# OpenTallas tools/qwen_missing/link_phy_gen.py: ot_qfd_ucie_x64_phy hard-macro ABSTRACT (licensed PHY IP; FDI side only)
VERSION 5.7 ;
BUSBITCHARS "[]" ;
DIVIDERCHAR "/" ;
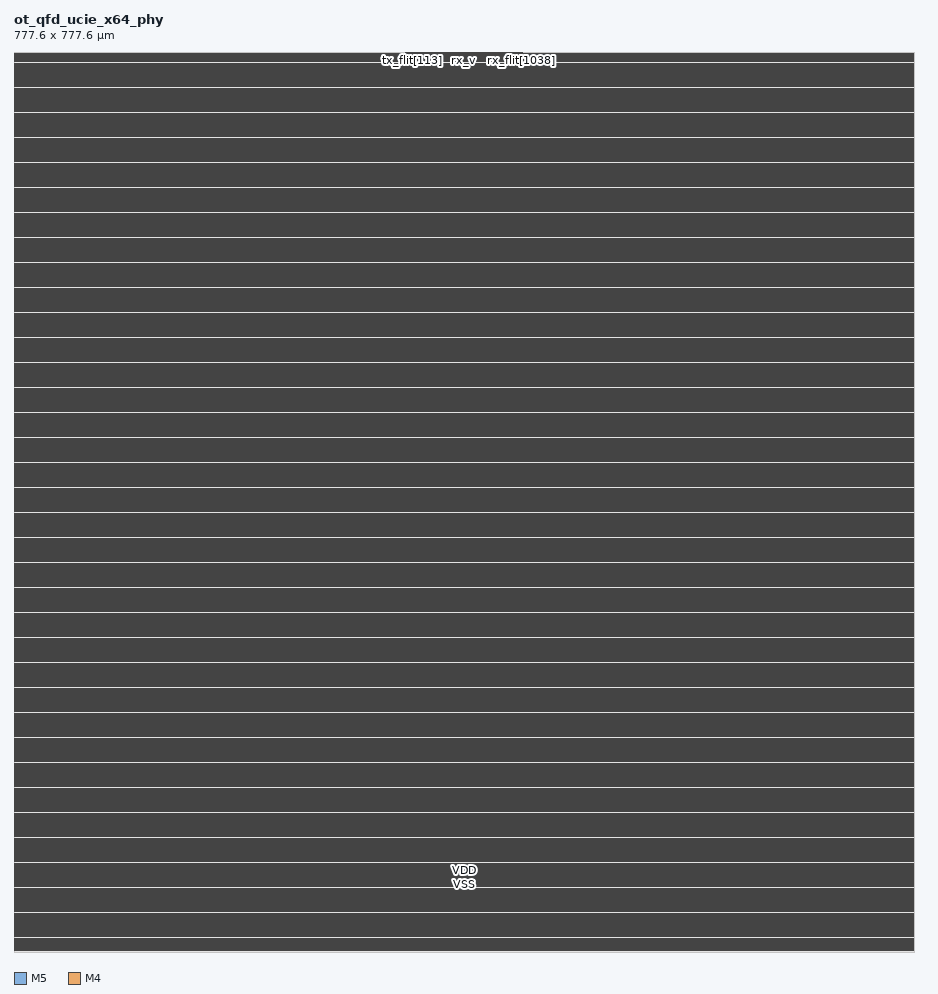
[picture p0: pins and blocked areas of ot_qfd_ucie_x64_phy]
MACRO ot_qfd_ucie_x64_phy
  FOREIGN ot_qfd_ucie_x64_phy 0 0 ;
  SYMMETRY X Y ;
  SIZE 777.600 BY 777.600 ;
  CLASS BLOCK ;
  PIN clk
    DIRECTION INPUT ;
    USE CLOCK ;
    SHAPE ABUTMENT ;
    PORT
      LAYER M5 ;
      RECT 338.616 777.408 338.640 777.600 ;
    END
  END clk
  PIN rst_n
    DIRECTION INPUT ;
    USE SIGNAL ;
    SHAPE ABUTMENT ;
    PORT
      LAYER M5 ;
      RECT 338.664 777.408 338.688 777.600 ;
    END
  END rst_n
  PIN tx_up
    DIRECTION OUTPUT ;
    USE SIGNAL ;
    SHAPE ABUTMENT ;
    PORT
      LAYER M5 ;
      RECT 338.712 777.408 338.736 777.600 ;
    END
  END tx_up
  PIN tx_v
    DIRECTION INPUT ;
    USE SIGNAL ;
    SHAPE ABUTMENT ;
    PORT
      LAYER M5 ;
      RECT 338.760 777.408 338.784 777.600 ;
    END
  END tx_v
  PIN tx_flit[0]
    DIRECTION INPUT ;
    USE SIGNAL ;
    SHAPE ABUTMENT ;
    PORT
      LAYER M5 ;
      RECT 338.808 777.408 338.832 777.600 ;
    END
  END tx_flit[0]
  PIN tx_flit[1]
    DIRECTION INPUT ;
    USE SIGNAL ;
    SHAPE ABUTMENT ;
    PORT
      LAYER M5 ;
      RECT 338.856 777.408 338.880 777.600 ;
    END
  END tx_flit[1]
  PIN tx_flit[2]
    DIRECTION INPUT ;
    USE SIGNAL ;
    SHAPE ABUTMENT ;
    PORT
      LAYER M5 ;
      RECT 338.904 777.408 338.928 777.600 ;
    END
  END tx_flit[2]
  PIN tx_flit[3]
    DIRECTION INPUT ;
    USE SIGNAL ;
    SHAPE ABUTMENT ;
    PORT
      LAYER M5 ;
      RECT 338.952 777.408 338.976 777.600 ;
    END
  END tx_flit[3]
  PIN tx_flit[4]
    DIRECTION INPUT ;
    USE SIGNAL ;
    SHAPE ABUTMENT ;
    PORT
      LAYER M5 ;
      RECT 339.000 777.408 339.024 777.600 ;
    END
  END tx_flit[4]
  PIN tx_flit[5]
    DIRECTION INPUT ;
    USE SIGNAL ;
    SHAPE ABUTMENT ;
    PORT
      LAYER M5 ;
      RECT 339.048 777.408 339.072 777.600 ;
    END
  END tx_flit[5]
  PIN tx_flit[6]
    DIRECTION INPUT ;
    USE SIGNAL ;
    SHAPE ABUTMENT ;
    PORT
      LAYER M5 ;
      RECT 339.096 777.408 339.120 777.600 ;
    END
  END tx_flit[6]
  PIN tx_flit[7]
    DIRECTION INPUT ;
    USE SIGNAL ;
    SHAPE ABUTMENT ;
    PORT
      LAYER M5 ;
      RECT 339.144 777.408 339.168 777.600 ;
    END
  END tx_flit[7]
  PIN tx_flit[8]
    DIRECTION INPUT ;
    USE SIGNAL ;
    SHAPE ABUTMENT ;
    PORT
      LAYER M5 ;
      RECT 339.192 777.408 339.216 777.600 ;
    END
  END tx_flit[8]
  PIN tx_flit[9]
    DIRECTION INPUT ;
    USE SIGNAL ;
    SHAPE ABUTMENT ;
    PORT
      LAYER M5 ;
      RECT 339.240 777.408 339.264 777.600 ;
    END
  END tx_flit[9]
  PIN tx_flit[10]
    DIRECTION INPUT ;
    USE SIGNAL ;
    SHAPE ABUTMENT ;
    PORT
      LAYER M5 ;
      RECT 339.288 777.408 339.312 777.600 ;
    END
  END tx_flit[10]
  PIN tx_flit[11]
    DIRECTION INPUT ;
    USE SIGNAL ;
    SHAPE ABUTMENT ;
    PORT
      LAYER M5 ;
      RECT 339.336 777.408 339.360 777.600 ;
    END
  END tx_flit[11]
  PIN tx_flit[12]
    DIRECTION INPUT ;
    USE SIGNAL ;
    SHAPE ABUTMENT ;
    PORT
      LAYER M5 ;
      RECT 339.384 777.408 339.408 777.600 ;
    END
  END tx_flit[12]
  PIN tx_flit[13]
    DIRECTION INPUT ;
    USE SIGNAL ;
    SHAPE ABUTMENT ;
    PORT
      LAYER M5 ;
      RECT 339.432 777.408 339.456 777.600 ;
    END
  END tx_flit[13]
  PIN tx_flit[14]
    DIRECTION INPUT ;
    USE SIGNAL ;
    SHAPE ABUTMENT ;
    PORT
      LAYER M5 ;
      RECT 339.480 777.408 339.504 777.600 ;
    END
  END tx_flit[14]
  PIN tx_flit[15]
    DIRECTION INPUT ;
    USE SIGNAL ;
    SHAPE ABUTMENT ;
    PORT
      LAYER M5 ;
      RECT 339.528 777.408 339.552 777.600 ;
    END
  END tx_flit[15]
  PIN tx_flit[16]
    DIRECTION INPUT ;
    USE SIGNAL ;
    SHAPE ABUTMENT ;
    PORT
      LAYER M5 ;
      RECT 339.576 777.408 339.600 777.600 ;
    END
  END tx_flit[16]
  PIN tx_flit[17]
    DIRECTION INPUT ;
    USE SIGNAL ;
    SHAPE ABUTMENT ;
    PORT
      LAYER M5 ;
      RECT 339.624 777.408 339.648 777.600 ;
    END
  END tx_flit[17]
  PIN tx_flit[18]
    DIRECTION INPUT ;
    USE SIGNAL ;
    SHAPE ABUTMENT ;
    PORT
      LAYER M5 ;
      RECT 339.672 777.408 339.696 777.600 ;
    END
  END tx_flit[18]
  PIN tx_flit[19]
    DIRECTION INPUT ;
    USE SIGNAL ;
    SHAPE ABUTMENT ;
    PORT
      LAYER M5 ;
      RECT 339.720 777.408 339.744 777.600 ;
    END
  END tx_flit[19]
  PIN tx_flit[20]
    DIRECTION INPUT ;
    USE SIGNAL ;
    SHAPE ABUTMENT ;
    PORT
      LAYER M5 ;
      RECT 339.768 777.408 339.792 777.600 ;
    END
  END tx_flit[20]
  PIN tx_flit[21]
    DIRECTION INPUT ;
    USE SIGNAL ;
    SHAPE ABUTMENT ;
    PORT
      LAYER M5 ;
      RECT 339.816 777.408 339.840 777.600 ;
    END
  END tx_flit[21]
  PIN tx_flit[22]
    DIRECTION INPUT ;
    USE SIGNAL ;
    SHAPE ABUTMENT ;
    PORT
      LAYER M5 ;
      RECT 339.864 777.408 339.888 777.600 ;
    END
  END tx_flit[22]
  PIN tx_flit[23]
    DIRECTION INPUT ;
    USE SIGNAL ;
    SHAPE ABUTMENT ;
    PORT
      LAYER M5 ;
      RECT 339.912 777.408 339.936 777.600 ;
    END
  END tx_flit[23]
  PIN tx_flit[24]
    DIRECTION INPUT ;
    USE SIGNAL ;
    SHAPE ABUTMENT ;
    PORT
      LAYER M5 ;
      RECT 339.960 777.408 339.984 777.600 ;
    END
  END tx_flit[24]
  PIN tx_flit[25]
    DIRECTION INPUT ;
    USE SIGNAL ;
    SHAPE ABUTMENT ;
    PORT
      LAYER M5 ;
      RECT 340.008 777.408 340.032 777.600 ;
    END
  END tx_flit[25]
  PIN tx_flit[26]
    DIRECTION INPUT ;
    USE SIGNAL ;
    SHAPE ABUTMENT ;
    PORT
      LAYER M5 ;
      RECT 340.056 777.408 340.080 777.600 ;
    END
  END tx_flit[26]
  PIN tx_flit[27]
    DIRECTION INPUT ;
    USE SIGNAL ;
    SHAPE ABUTMENT ;
    PORT
      LAYER M5 ;
      RECT 340.104 777.408 340.128 777.600 ;
    END
  END tx_flit[27]
  PIN tx_flit[28]
    DIRECTION INPUT ;
    USE SIGNAL ;
    SHAPE ABUTMENT ;
    PORT
      LAYER M5 ;
      RECT 340.152 777.408 340.176 777.600 ;
    END
  END tx_flit[28]
  PIN tx_flit[29]
    DIRECTION INPUT ;
    USE SIGNAL ;
    SHAPE ABUTMENT ;
    PORT
      LAYER M5 ;
      RECT 340.200 777.408 340.224 777.600 ;
    END
  END tx_flit[29]
  PIN tx_flit[30]
    DIRECTION INPUT ;
    USE SIGNAL ;
    SHAPE ABUTMENT ;
    PORT
      LAYER M5 ;
      RECT 340.248 777.408 340.272 777.600 ;
    END
  END tx_flit[30]
  PIN tx_flit[31]
    DIRECTION INPUT ;
    USE SIGNAL ;
    SHAPE ABUTMENT ;
    PORT
      LAYER M5 ;
      RECT 340.296 777.408 340.320 777.600 ;
    END
  END tx_flit[31]
  PIN tx_flit[32]
    DIRECTION INPUT ;
    USE SIGNAL ;
    SHAPE ABUTMENT ;
    PORT
      LAYER M5 ;
      RECT 340.344 777.408 340.368 777.600 ;
    END
  END tx_flit[32]
  PIN tx_flit[33]
    DIRECTION INPUT ;
    USE SIGNAL ;
    SHAPE ABUTMENT ;
    PORT
      LAYER M5 ;
      RECT 340.392 777.408 340.416 777.600 ;
    END
  END tx_flit[33]
  PIN tx_flit[34]
    DIRECTION INPUT ;
    USE SIGNAL ;
    SHAPE ABUTMENT ;
    PORT
      LAYER M5 ;
      RECT 340.440 777.408 340.464 777.600 ;
    END
  END tx_flit[34]
  PIN tx_flit[35]
    DIRECTION INPUT ;
    USE SIGNAL ;
    SHAPE ABUTMENT ;
    PORT
      LAYER M5 ;
      RECT 340.488 777.408 340.512 777.600 ;
    END
  END tx_flit[35]
  PIN tx_flit[36]
    DIRECTION INPUT ;
    USE SIGNAL ;
    SHAPE ABUTMENT ;
    PORT
      LAYER M5 ;
      RECT 340.536 777.408 340.560 777.600 ;
    END
  END tx_flit[36]
  PIN tx_flit[37]
    DIRECTION INPUT ;
    USE SIGNAL ;
    SHAPE ABUTMENT ;
    PORT
      LAYER M5 ;
      RECT 340.584 777.408 340.608 777.600 ;
    END
  END tx_flit[37]
  PIN tx_flit[38]
    DIRECTION INPUT ;
    USE SIGNAL ;
    SHAPE ABUTMENT ;
    PORT
      LAYER M5 ;
      RECT 340.632 777.408 340.656 777.600 ;
    END
  END tx_flit[38]
  PIN tx_flit[39]
    DIRECTION INPUT ;
    USE SIGNAL ;
    SHAPE ABUTMENT ;
    PORT
      LAYER M5 ;
      RECT 340.680 777.408 340.704 777.600 ;
    END
  END tx_flit[39]
  PIN tx_flit[40]
    DIRECTION INPUT ;
    USE SIGNAL ;
    SHAPE ABUTMENT ;
    PORT
      LAYER M5 ;
      RECT 340.728 777.408 340.752 777.600 ;
    END
  END tx_flit[40]
  PIN tx_flit[41]
    DIRECTION INPUT ;
    USE SIGNAL ;
    SHAPE ABUTMENT ;
    PORT
      LAYER M5 ;
      RECT 340.776 777.408 340.800 777.600 ;
    END
  END tx_flit[41]
  PIN tx_flit[42]
    DIRECTION INPUT ;
    USE SIGNAL ;
    SHAPE ABUTMENT ;
    PORT
      LAYER M5 ;
      RECT 340.824 777.408 340.848 777.600 ;
    END
  END tx_flit[42]
  PIN tx_flit[43]
    DIRECTION INPUT ;
    USE SIGNAL ;
    SHAPE ABUTMENT ;
    PORT
      LAYER M5 ;
      RECT 340.872 777.408 340.896 777.600 ;
    END
  END tx_flit[43]
  PIN tx_flit[44]
    DIRECTION INPUT ;
    USE SIGNAL ;
    SHAPE ABUTMENT ;
    PORT
      LAYER M5 ;
      RECT 340.920 777.408 340.944 777.600 ;
    END
  END tx_flit[44]
  PIN tx_flit[45]
    DIRECTION INPUT ;
    USE SIGNAL ;
    SHAPE ABUTMENT ;
    PORT
      LAYER M5 ;
      RECT 340.968 777.408 340.992 777.600 ;
    END
  END tx_flit[45]
  PIN tx_flit[46]
    DIRECTION INPUT ;
    USE SIGNAL ;
    SHAPE ABUTMENT ;
    PORT
      LAYER M5 ;
      RECT 341.016 777.408 341.040 777.600 ;
    END
  END tx_flit[46]
  PIN tx_flit[47]
    DIRECTION INPUT ;
    USE SIGNAL ;
    SHAPE ABUTMENT ;
    PORT
      LAYER M5 ;
      RECT 341.064 777.408 341.088 777.600 ;
    END
  END tx_flit[47]
  PIN tx_flit[48]
    DIRECTION INPUT ;
    USE SIGNAL ;
    SHAPE ABUTMENT ;
    PORT
      LAYER M5 ;
      RECT 341.112 777.408 341.136 777.600 ;
    END
  END tx_flit[48]
  PIN tx_flit[49]
    DIRECTION INPUT ;
    USE SIGNAL ;
    SHAPE ABUTMENT ;
    PORT
      LAYER M5 ;
      RECT 341.160 777.408 341.184 777.600 ;
    END
  END tx_flit[49]
  PIN tx_flit[50]
    DIRECTION INPUT ;
    USE SIGNAL ;
    SHAPE ABUTMENT ;
    PORT
      LAYER M5 ;
      RECT 341.208 777.408 341.232 777.600 ;
    END
  END tx_flit[50]
  PIN tx_flit[51]
    DIRECTION INPUT ;
    USE SIGNAL ;
    SHAPE ABUTMENT ;
    PORT
      LAYER M5 ;
      RECT 341.256 777.408 341.280 777.600 ;
    END
  END tx_flit[51]
  PIN tx_flit[52]
    DIRECTION INPUT ;
    USE SIGNAL ;
    SHAPE ABUTMENT ;
    PORT
      LAYER M5 ;
      RECT 341.304 777.408 341.328 777.600 ;
    END
  END tx_flit[52]
  PIN tx_flit[53]
    DIRECTION INPUT ;
    USE SIGNAL ;
    SHAPE ABUTMENT ;
    PORT
      LAYER M5 ;
      RECT 341.352 777.408 341.376 777.600 ;
    END
  END tx_flit[53]
  PIN tx_flit[54]
    DIRECTION INPUT ;
    USE SIGNAL ;
    SHAPE ABUTMENT ;
    PORT
      LAYER M5 ;
      RECT 341.400 777.408 341.424 777.600 ;
    END
  END tx_flit[54]
  PIN tx_flit[55]
    DIRECTION INPUT ;
    USE SIGNAL ;
    SHAPE ABUTMENT ;
    PORT
      LAYER M5 ;
      RECT 341.448 777.408 341.472 777.600 ;
    END
  END tx_flit[55]
  PIN tx_flit[56]
    DIRECTION INPUT ;
    USE SIGNAL ;
    SHAPE ABUTMENT ;
    PORT
      LAYER M5 ;
      RECT 341.496 777.408 341.520 777.600 ;
    END
  END tx_flit[56]
  PIN tx_flit[57]
    DIRECTION INPUT ;
    USE SIGNAL ;
    SHAPE ABUTMENT ;
    PORT
      LAYER M5 ;
      RECT 341.544 777.408 341.568 777.600 ;
    END
  END tx_flit[57]
  PIN tx_flit[58]
    DIRECTION INPUT ;
    USE SIGNAL ;
    SHAPE ABUTMENT ;
    PORT
      LAYER M5 ;
      RECT 341.592 777.408 341.616 777.600 ;
    END
  END tx_flit[58]
  PIN tx_flit[59]
    DIRECTION INPUT ;
    USE SIGNAL ;
    SHAPE ABUTMENT ;
    PORT
      LAYER M5 ;
      RECT 341.640 777.408 341.664 777.600 ;
    END
  END tx_flit[59]
  PIN tx_flit[60]
    DIRECTION INPUT ;
    USE SIGNAL ;
    SHAPE ABUTMENT ;
    PORT
      LAYER M5 ;
      RECT 341.688 777.408 341.712 777.600 ;
    END
  END tx_flit[60]
  PIN tx_flit[61]
    DIRECTION INPUT ;
    USE SIGNAL ;
    SHAPE ABUTMENT ;
    PORT
      LAYER M5 ;
      RECT 341.736 777.408 341.760 777.600 ;
    END
  END tx_flit[61]
  PIN tx_flit[62]
    DIRECTION INPUT ;
    USE SIGNAL ;
    SHAPE ABUTMENT ;
    PORT
      LAYER M5 ;
      RECT 341.784 777.408 341.808 777.600 ;
    END
  END tx_flit[62]
  PIN tx_flit[63]
    DIRECTION INPUT ;
    USE SIGNAL ;
    SHAPE ABUTMENT ;
    PORT
      LAYER M5 ;
      RECT 341.832 777.408 341.856 777.600 ;
    END
  END tx_flit[63]
  PIN tx_flit[64]
    DIRECTION INPUT ;
    USE SIGNAL ;
    SHAPE ABUTMENT ;
    PORT
      LAYER M5 ;
      RECT 341.880 777.408 341.904 777.600 ;
    END
  END tx_flit[64]
  PIN tx_flit[65]
    DIRECTION INPUT ;
    USE SIGNAL ;
    SHAPE ABUTMENT ;
    PORT
      LAYER M5 ;
      RECT 341.928 777.408 341.952 777.600 ;
    END
  END tx_flit[65]
  PIN tx_flit[66]
    DIRECTION INPUT ;
    USE SIGNAL ;
    SHAPE ABUTMENT ;
    PORT
      LAYER M5 ;
      RECT 341.976 777.408 342.000 777.600 ;
    END
  END tx_flit[66]
  PIN tx_flit[67]
    DIRECTION INPUT ;
    USE SIGNAL ;
    SHAPE ABUTMENT ;
    PORT
      LAYER M5 ;
      RECT 342.024 777.408 342.048 777.600 ;
    END
  END tx_flit[67]
  PIN tx_flit[68]
    DIRECTION INPUT ;
    USE SIGNAL ;
    SHAPE ABUTMENT ;
    PORT
      LAYER M5 ;
      RECT 342.072 777.408 342.096 777.600 ;
    END
  END tx_flit[68]
  PIN tx_flit[69]
    DIRECTION INPUT ;
    USE SIGNAL ;
    SHAPE ABUTMENT ;
    PORT
      LAYER M5 ;
      RECT 342.120 777.408 342.144 777.600 ;
    END
  END tx_flit[69]
  PIN tx_flit[70]
    DIRECTION INPUT ;
    USE SIGNAL ;
    SHAPE ABUTMENT ;
    PORT
      LAYER M5 ;
      RECT 342.168 777.408 342.192 777.600 ;
    END
  END tx_flit[70]
  PIN tx_flit[71]
    DIRECTION INPUT ;
    USE SIGNAL ;
    SHAPE ABUTMENT ;
    PORT
      LAYER M5 ;
      RECT 342.216 777.408 342.240 777.600 ;
    END
  END tx_flit[71]
  PIN tx_flit[72]
    DIRECTION INPUT ;
    USE SIGNAL ;
    SHAPE ABUTMENT ;
    PORT
      LAYER M5 ;
      RECT 342.264 777.408 342.288 777.600 ;
    END
  END tx_flit[72]
  PIN tx_flit[73]
    DIRECTION INPUT ;
    USE SIGNAL ;
    SHAPE ABUTMENT ;
    PORT
      LAYER M5 ;
      RECT 342.312 777.408 342.336 777.600 ;
    END
  END tx_flit[73]
  PIN tx_flit[74]
    DIRECTION INPUT ;
    USE SIGNAL ;
    SHAPE ABUTMENT ;
    PORT
      LAYER M5 ;
      RECT 342.360 777.408 342.384 777.600 ;
    END
  END tx_flit[74]
  PIN tx_flit[75]
    DIRECTION INPUT ;
    USE SIGNAL ;
    SHAPE ABUTMENT ;
    PORT
      LAYER M5 ;
      RECT 342.408 777.408 342.432 777.600 ;
    END
  END tx_flit[75]
  PIN tx_flit[76]
    DIRECTION INPUT ;
    USE SIGNAL ;
    SHAPE ABUTMENT ;
    PORT
      LAYER M5 ;
      RECT 342.456 777.408 342.480 777.600 ;
    END
  END tx_flit[76]
  PIN tx_flit[77]
    DIRECTION INPUT ;
    USE SIGNAL ;
    SHAPE ABUTMENT ;
    PORT
      LAYER M5 ;
      RECT 342.504 777.408 342.528 777.600 ;
    END
  END tx_flit[77]
  PIN tx_flit[78]
    DIRECTION INPUT ;
    USE SIGNAL ;
    SHAPE ABUTMENT ;
    PORT
      LAYER M5 ;
      RECT 342.552 777.408 342.576 777.600 ;
    END
  END tx_flit[78]
  PIN tx_flit[79]
    DIRECTION INPUT ;
    USE SIGNAL ;
    SHAPE ABUTMENT ;
    PORT
      LAYER M5 ;
      RECT 342.600 777.408 342.624 777.600 ;
    END
  END tx_flit[79]
  PIN tx_flit[80]
    DIRECTION INPUT ;
    USE SIGNAL ;
    SHAPE ABUTMENT ;
    PORT
      LAYER M5 ;
      RECT 342.648 777.408 342.672 777.600 ;
    END
  END tx_flit[80]
  PIN tx_flit[81]
    DIRECTION INPUT ;
    USE SIGNAL ;
    SHAPE ABUTMENT ;
    PORT
      LAYER M5 ;
      RECT 342.696 777.408 342.720 777.600 ;
    END
  END tx_flit[81]
  PIN tx_flit[82]
    DIRECTION INPUT ;
    USE SIGNAL ;
    SHAPE ABUTMENT ;
    PORT
      LAYER M5 ;
      RECT 342.744 777.408 342.768 777.600 ;
    END
  END tx_flit[82]
  PIN tx_flit[83]
    DIRECTION INPUT ;
    USE SIGNAL ;
    SHAPE ABUTMENT ;
    PORT
      LAYER M5 ;
      RECT 342.792 777.408 342.816 777.600 ;
    END
  END tx_flit[83]
  PIN tx_flit[84]
    DIRECTION INPUT ;
    USE SIGNAL ;
    SHAPE ABUTMENT ;
    PORT
      LAYER M5 ;
      RECT 342.840 777.408 342.864 777.600 ;
    END
  END tx_flit[84]
  PIN tx_flit[85]
    DIRECTION INPUT ;
    USE SIGNAL ;
    SHAPE ABUTMENT ;
    PORT
      LAYER M5 ;
      RECT 342.888 777.408 342.912 777.600 ;
    END
  END tx_flit[85]
  PIN tx_flit[86]
    DIRECTION INPUT ;
    USE SIGNAL ;
    SHAPE ABUTMENT ;
    PORT
      LAYER M5 ;
      RECT 342.936 777.408 342.960 777.600 ;
    END
  END tx_flit[86]
  PIN tx_flit[87]
    DIRECTION INPUT ;
    USE SIGNAL ;
    SHAPE ABUTMENT ;
    PORT
      LAYER M5 ;
      RECT 342.984 777.408 343.008 777.600 ;
    END
  END tx_flit[87]
  PIN tx_flit[88]
    DIRECTION INPUT ;
    USE SIGNAL ;
    SHAPE ABUTMENT ;
    PORT
      LAYER M5 ;
      RECT 343.032 777.408 343.056 777.600 ;
    END
  END tx_flit[88]
  PIN tx_flit[89]
    DIRECTION INPUT ;
    USE SIGNAL ;
    SHAPE ABUTMENT ;
    PORT
      LAYER M5 ;
      RECT 343.080 777.408 343.104 777.600 ;
    END
  END tx_flit[89]
  PIN tx_flit[90]
    DIRECTION INPUT ;
    USE SIGNAL ;
    SHAPE ABUTMENT ;
    PORT
      LAYER M5 ;
      RECT 343.128 777.408 343.152 777.600 ;
    END
  END tx_flit[90]
  PIN tx_flit[91]
    DIRECTION INPUT ;
    USE SIGNAL ;
    SHAPE ABUTMENT ;
    PORT
      LAYER M5 ;
      RECT 343.176 777.408 343.200 777.600 ;
    END
  END tx_flit[91]
  PIN tx_flit[92]
    DIRECTION INPUT ;
    USE SIGNAL ;
    SHAPE ABUTMENT ;
    PORT
      LAYER M5 ;
      RECT 343.224 777.408 343.248 777.600 ;
    END
  END tx_flit[92]
  PIN tx_flit[93]
    DIRECTION INPUT ;
    USE SIGNAL ;
    SHAPE ABUTMENT ;
    PORT
      LAYER M5 ;
      RECT 343.272 777.408 343.296 777.600 ;
    END
  END tx_flit[93]
  PIN tx_flit[94]
    DIRECTION INPUT ;
    USE SIGNAL ;
    SHAPE ABUTMENT ;
    PORT
      LAYER M5 ;
      RECT 343.320 777.408 343.344 777.600 ;
    END
  END tx_flit[94]
  PIN tx_flit[95]
    DIRECTION INPUT ;
    USE SIGNAL ;
    SHAPE ABUTMENT ;
    PORT
      LAYER M5 ;
      RECT 343.368 777.408 343.392 777.600 ;
    END
  END tx_flit[95]
  PIN tx_flit[96]
    DIRECTION INPUT ;
    USE SIGNAL ;
    SHAPE ABUTMENT ;
    PORT
      LAYER M5 ;
      RECT 343.416 777.408 343.440 777.600 ;
    END
  END tx_flit[96]
  PIN tx_flit[97]
    DIRECTION INPUT ;
    USE SIGNAL ;
    SHAPE ABUTMENT ;
    PORT
      LAYER M5 ;
      RECT 343.464 777.408 343.488 777.600 ;
    END
  END tx_flit[97]
  PIN tx_flit[98]
    DIRECTION INPUT ;
    USE SIGNAL ;
    SHAPE ABUTMENT ;
    PORT
      LAYER M5 ;
      RECT 343.512 777.408 343.536 777.600 ;
    END
  END tx_flit[98]
  PIN tx_flit[99]
    DIRECTION INPUT ;
    USE SIGNAL ;
    SHAPE ABUTMENT ;
    PORT
      LAYER M5 ;
      RECT 343.560 777.408 343.584 777.600 ;
    END
  END tx_flit[99]
  PIN tx_flit[100]
    DIRECTION INPUT ;
    USE SIGNAL ;
    SHAPE ABUTMENT ;
    PORT
      LAYER M5 ;
      RECT 343.608 777.408 343.632 777.600 ;
    END
  END tx_flit[100]
  PIN tx_flit[101]
    DIRECTION INPUT ;
    USE SIGNAL ;
    SHAPE ABUTMENT ;
    PORT
      LAYER M5 ;
      RECT 343.656 777.408 343.680 777.600 ;
    END
  END tx_flit[101]
  PIN tx_flit[102]
    DIRECTION INPUT ;
    USE SIGNAL ;
    SHAPE ABUTMENT ;
    PORT
      LAYER M5 ;
      RECT 343.704 777.408 343.728 777.600 ;
    END
  END tx_flit[102]
  PIN tx_flit[103]
    DIRECTION INPUT ;
    USE SIGNAL ;
    SHAPE ABUTMENT ;
    PORT
      LAYER M5 ;
      RECT 343.752 777.408 343.776 777.600 ;
    END
  END tx_flit[103]
  PIN tx_flit[104]
    DIRECTION INPUT ;
    USE SIGNAL ;
    SHAPE ABUTMENT ;
    PORT
      LAYER M5 ;
      RECT 343.800 777.408 343.824 777.600 ;
    END
  END tx_flit[104]
  PIN tx_flit[105]
    DIRECTION INPUT ;
    USE SIGNAL ;
    SHAPE ABUTMENT ;
    PORT
      LAYER M5 ;
      RECT 343.848 777.408 343.872 777.600 ;
    END
  END tx_flit[105]
  PIN tx_flit[106]
    DIRECTION INPUT ;
    USE SIGNAL ;
    SHAPE ABUTMENT ;
    PORT
      LAYER M5 ;
      RECT 343.896 777.408 343.920 777.600 ;
    END
  END tx_flit[106]
  PIN tx_flit[107]
    DIRECTION INPUT ;
    USE SIGNAL ;
    SHAPE ABUTMENT ;
    PORT
      LAYER M5 ;
      RECT 343.944 777.408 343.968 777.600 ;
    END
  END tx_flit[107]
  PIN tx_flit[108]
    DIRECTION INPUT ;
    USE SIGNAL ;
    SHAPE ABUTMENT ;
    PORT
      LAYER M5 ;
      RECT 343.992 777.408 344.016 777.600 ;
    END
  END tx_flit[108]
  PIN tx_flit[109]
    DIRECTION INPUT ;
    USE SIGNAL ;
    SHAPE ABUTMENT ;
    PORT
      LAYER M5 ;
      RECT 344.040 777.408 344.064 777.600 ;
    END
  END tx_flit[109]
  PIN tx_flit[110]
    DIRECTION INPUT ;
    USE SIGNAL ;
    SHAPE ABUTMENT ;
    PORT
      LAYER M5 ;
      RECT 344.088 777.408 344.112 777.600 ;
    END
  END tx_flit[110]
  PIN tx_flit[111]
    DIRECTION INPUT ;
    USE SIGNAL ;
    SHAPE ABUTMENT ;
    PORT
      LAYER M5 ;
      RECT 344.136 777.408 344.160 777.600 ;
    END
  END tx_flit[111]
  PIN tx_flit[112]
    DIRECTION INPUT ;
    USE SIGNAL ;
    SHAPE ABUTMENT ;
    PORT
      LAYER M5 ;
      RECT 344.184 777.408 344.208 777.600 ;
    END
  END tx_flit[112]
  PIN tx_flit[113]
    DIRECTION INPUT ;
    USE SIGNAL ;
    SHAPE ABUTMENT ;
    PORT
      LAYER M5 ;
      RECT 344.232 777.408 344.256 777.600 ;
    END
  END tx_flit[113]
  PIN tx_flit[114]
    DIRECTION INPUT ;
    USE SIGNAL ;
    SHAPE ABUTMENT ;
    PORT
      LAYER M5 ;
      RECT 344.280 777.408 344.304 777.600 ;
    END
  END tx_flit[114]
  PIN tx_flit[115]
    DIRECTION INPUT ;
    USE SIGNAL ;
    SHAPE ABUTMENT ;
    PORT
      LAYER M5 ;
      RECT 344.328 777.408 344.352 777.600 ;
    END
  END tx_flit[115]
  PIN tx_flit[116]
    DIRECTION INPUT ;
    USE SIGNAL ;
    SHAPE ABUTMENT ;
    PORT
      LAYER M5 ;
      RECT 344.376 777.408 344.400 777.600 ;
    END
  END tx_flit[116]
  PIN tx_flit[117]
    DIRECTION INPUT ;
    USE SIGNAL ;
    SHAPE ABUTMENT ;
    PORT
      LAYER M5 ;
      RECT 344.424 777.408 344.448 777.600 ;
    END
  END tx_flit[117]
  PIN tx_flit[118]
    DIRECTION INPUT ;
    USE SIGNAL ;
    SHAPE ABUTMENT ;
    PORT
      LAYER M5 ;
      RECT 344.472 777.408 344.496 777.600 ;
    END
  END tx_flit[118]
  PIN tx_flit[119]
    DIRECTION INPUT ;
    USE SIGNAL ;
    SHAPE ABUTMENT ;
    PORT
      LAYER M5 ;
      RECT 344.520 777.408 344.544 777.600 ;
    END
  END tx_flit[119]
  PIN tx_flit[120]
    DIRECTION INPUT ;
    USE SIGNAL ;
    SHAPE ABUTMENT ;
    PORT
      LAYER M5 ;
      RECT 344.568 777.408 344.592 777.600 ;
    END
  END tx_flit[120]
  PIN tx_flit[121]
    DIRECTION INPUT ;
    USE SIGNAL ;
    SHAPE ABUTMENT ;
    PORT
      LAYER M5 ;
      RECT 344.616 777.408 344.640 777.600 ;
    END
  END tx_flit[121]
  PIN tx_flit[122]
    DIRECTION INPUT ;
    USE SIGNAL ;
    SHAPE ABUTMENT ;
    PORT
      LAYER M5 ;
      RECT 344.664 777.408 344.688 777.600 ;
    END
  END tx_flit[122]
  PIN tx_flit[123]
    DIRECTION INPUT ;
    USE SIGNAL ;
    SHAPE ABUTMENT ;
    PORT
      LAYER M5 ;
      RECT 344.712 777.408 344.736 777.600 ;
    END
  END tx_flit[123]
  PIN tx_flit[124]
    DIRECTION INPUT ;
    USE SIGNAL ;
    SHAPE ABUTMENT ;
    PORT
      LAYER M5 ;
      RECT 344.760 777.408 344.784 777.600 ;
    END
  END tx_flit[124]
  PIN tx_flit[125]
    DIRECTION INPUT ;
    USE SIGNAL ;
    SHAPE ABUTMENT ;
    PORT
      LAYER M5 ;
      RECT 344.808 777.408 344.832 777.600 ;
    END
  END tx_flit[125]
  PIN tx_flit[126]
    DIRECTION INPUT ;
    USE SIGNAL ;
    SHAPE ABUTMENT ;
    PORT
      LAYER M5 ;
      RECT 344.856 777.408 344.880 777.600 ;
    END
  END tx_flit[126]
  PIN tx_flit[127]
    DIRECTION INPUT ;
    USE SIGNAL ;
    SHAPE ABUTMENT ;
    PORT
      LAYER M5 ;
      RECT 344.904 777.408 344.928 777.600 ;
    END
  END tx_flit[127]
  PIN tx_flit[128]
    DIRECTION INPUT ;
    USE SIGNAL ;
    SHAPE ABUTMENT ;
    PORT
      LAYER M5 ;
      RECT 344.952 777.408 344.976 777.600 ;
    END
  END tx_flit[128]
  PIN tx_flit[129]
    DIRECTION INPUT ;
    USE SIGNAL ;
    SHAPE ABUTMENT ;
    PORT
      LAYER M5 ;
      RECT 345.000 777.408 345.024 777.600 ;
    END
  END tx_flit[129]
  PIN tx_flit[130]
    DIRECTION INPUT ;
    USE SIGNAL ;
    SHAPE ABUTMENT ;
    PORT
      LAYER M5 ;
      RECT 345.048 777.408 345.072 777.600 ;
    END
  END tx_flit[130]
  PIN tx_flit[131]
    DIRECTION INPUT ;
    USE SIGNAL ;
    SHAPE ABUTMENT ;
    PORT
      LAYER M5 ;
      RECT 345.096 777.408 345.120 777.600 ;
    END
  END tx_flit[131]
  PIN tx_flit[132]
    DIRECTION INPUT ;
    USE SIGNAL ;
    SHAPE ABUTMENT ;
    PORT
      LAYER M5 ;
      RECT 345.144 777.408 345.168 777.600 ;
    END
  END tx_flit[132]
  PIN tx_flit[133]
    DIRECTION INPUT ;
    USE SIGNAL ;
    SHAPE ABUTMENT ;
    PORT
      LAYER M5 ;
      RECT 345.192 777.408 345.216 777.600 ;
    END
  END tx_flit[133]
  PIN tx_flit[134]
    DIRECTION INPUT ;
    USE SIGNAL ;
    SHAPE ABUTMENT ;
    PORT
      LAYER M5 ;
      RECT 345.240 777.408 345.264 777.600 ;
    END
  END tx_flit[134]
  PIN tx_flit[135]
    DIRECTION INPUT ;
    USE SIGNAL ;
    SHAPE ABUTMENT ;
    PORT
      LAYER M5 ;
      RECT 345.288 777.408 345.312 777.600 ;
    END
  END tx_flit[135]
  PIN tx_flit[136]
    DIRECTION INPUT ;
    USE SIGNAL ;
    SHAPE ABUTMENT ;
    PORT
      LAYER M5 ;
      RECT 345.336 777.408 345.360 777.600 ;
    END
  END tx_flit[136]
  PIN tx_flit[137]
    DIRECTION INPUT ;
    USE SIGNAL ;
    SHAPE ABUTMENT ;
    PORT
      LAYER M5 ;
      RECT 345.384 777.408 345.408 777.600 ;
    END
  END tx_flit[137]
  PIN tx_flit[138]
    DIRECTION INPUT ;
    USE SIGNAL ;
    SHAPE ABUTMENT ;
    PORT
      LAYER M5 ;
      RECT 345.432 777.408 345.456 777.600 ;
    END
  END tx_flit[138]
  PIN tx_flit[139]
    DIRECTION INPUT ;
    USE SIGNAL ;
    SHAPE ABUTMENT ;
    PORT
      LAYER M5 ;
      RECT 345.480 777.408 345.504 777.600 ;
    END
  END tx_flit[139]
  PIN tx_flit[140]
    DIRECTION INPUT ;
    USE SIGNAL ;
    SHAPE ABUTMENT ;
    PORT
      LAYER M5 ;
      RECT 345.528 777.408 345.552 777.600 ;
    END
  END tx_flit[140]
  PIN tx_flit[141]
    DIRECTION INPUT ;
    USE SIGNAL ;
    SHAPE ABUTMENT ;
    PORT
      LAYER M5 ;
      RECT 345.576 777.408 345.600 777.600 ;
    END
  END tx_flit[141]
  PIN tx_flit[142]
    DIRECTION INPUT ;
    USE SIGNAL ;
    SHAPE ABUTMENT ;
    PORT
      LAYER M5 ;
      RECT 345.624 777.408 345.648 777.600 ;
    END
  END tx_flit[142]
  PIN tx_flit[143]
    DIRECTION INPUT ;
    USE SIGNAL ;
    SHAPE ABUTMENT ;
    PORT
      LAYER M5 ;
      RECT 345.672 777.408 345.696 777.600 ;
    END
  END tx_flit[143]
  PIN tx_flit[144]
    DIRECTION INPUT ;
    USE SIGNAL ;
    SHAPE ABUTMENT ;
    PORT
      LAYER M5 ;
      RECT 345.720 777.408 345.744 777.600 ;
    END
  END tx_flit[144]
  PIN tx_flit[145]
    DIRECTION INPUT ;
    USE SIGNAL ;
    SHAPE ABUTMENT ;
    PORT
      LAYER M5 ;
      RECT 345.768 777.408 345.792 777.600 ;
    END
  END tx_flit[145]
  PIN tx_flit[146]
    DIRECTION INPUT ;
    USE SIGNAL ;
    SHAPE ABUTMENT ;
    PORT
      LAYER M5 ;
      RECT 345.816 777.408 345.840 777.600 ;
    END
  END tx_flit[146]
  PIN tx_flit[147]
    DIRECTION INPUT ;
    USE SIGNAL ;
    SHAPE ABUTMENT ;
    PORT
      LAYER M5 ;
      RECT 345.864 777.408 345.888 777.600 ;
    END
  END tx_flit[147]
  PIN tx_flit[148]
    DIRECTION INPUT ;
    USE SIGNAL ;
    SHAPE ABUTMENT ;
    PORT
      LAYER M5 ;
      RECT 345.912 777.408 345.936 777.600 ;
    END
  END tx_flit[148]
  PIN tx_flit[149]
    DIRECTION INPUT ;
    USE SIGNAL ;
    SHAPE ABUTMENT ;
    PORT
      LAYER M5 ;
      RECT 345.960 777.408 345.984 777.600 ;
    END
  END tx_flit[149]
  PIN tx_flit[150]
    DIRECTION INPUT ;
    USE SIGNAL ;
    SHAPE ABUTMENT ;
    PORT
      LAYER M5 ;
      RECT 346.008 777.408 346.032 777.600 ;
    END
  END tx_flit[150]
  PIN tx_flit[151]
    DIRECTION INPUT ;
    USE SIGNAL ;
    SHAPE ABUTMENT ;
    PORT
      LAYER M5 ;
      RECT 346.056 777.408 346.080 777.600 ;
    END
  END tx_flit[151]
  PIN tx_flit[152]
    DIRECTION INPUT ;
    USE SIGNAL ;
    SHAPE ABUTMENT ;
    PORT
      LAYER M5 ;
      RECT 346.104 777.408 346.128 777.600 ;
    END
  END tx_flit[152]
  PIN tx_flit[153]
    DIRECTION INPUT ;
    USE SIGNAL ;
    SHAPE ABUTMENT ;
    PORT
      LAYER M5 ;
      RECT 346.152 777.408 346.176 777.600 ;
    END
  END tx_flit[153]
  PIN tx_flit[154]
    DIRECTION INPUT ;
    USE SIGNAL ;
    SHAPE ABUTMENT ;
    PORT
      LAYER M5 ;
      RECT 346.200 777.408 346.224 777.600 ;
    END
  END tx_flit[154]
  PIN tx_flit[155]
    DIRECTION INPUT ;
    USE SIGNAL ;
    SHAPE ABUTMENT ;
    PORT
      LAYER M5 ;
      RECT 346.248 777.408 346.272 777.600 ;
    END
  END tx_flit[155]
  PIN tx_flit[156]
    DIRECTION INPUT ;
    USE SIGNAL ;
    SHAPE ABUTMENT ;
    PORT
      LAYER M5 ;
      RECT 346.296 777.408 346.320 777.600 ;
    END
  END tx_flit[156]
  PIN tx_flit[157]
    DIRECTION INPUT ;
    USE SIGNAL ;
    SHAPE ABUTMENT ;
    PORT
      LAYER M5 ;
      RECT 346.344 777.408 346.368 777.600 ;
    END
  END tx_flit[157]
  PIN tx_flit[158]
    DIRECTION INPUT ;
    USE SIGNAL ;
    SHAPE ABUTMENT ;
    PORT
      LAYER M5 ;
      RECT 346.392 777.408 346.416 777.600 ;
    END
  END tx_flit[158]
  PIN tx_flit[159]
    DIRECTION INPUT ;
    USE SIGNAL ;
    SHAPE ABUTMENT ;
    PORT
      LAYER M5 ;
      RECT 346.440 777.408 346.464 777.600 ;
    END
  END tx_flit[159]
  PIN tx_flit[160]
    DIRECTION INPUT ;
    USE SIGNAL ;
    SHAPE ABUTMENT ;
    PORT
      LAYER M5 ;
      RECT 346.488 777.408 346.512 777.600 ;
    END
  END tx_flit[160]
  PIN tx_flit[161]
    DIRECTION INPUT ;
    USE SIGNAL ;
    SHAPE ABUTMENT ;
    PORT
      LAYER M5 ;
      RECT 346.536 777.408 346.560 777.600 ;
    END
  END tx_flit[161]
  PIN tx_flit[162]
    DIRECTION INPUT ;
    USE SIGNAL ;
    SHAPE ABUTMENT ;
    PORT
      LAYER M5 ;
      RECT 346.584 777.408 346.608 777.600 ;
    END
  END tx_flit[162]
  PIN tx_flit[163]
    DIRECTION INPUT ;
    USE SIGNAL ;
    SHAPE ABUTMENT ;
    PORT
      LAYER M5 ;
      RECT 346.632 777.408 346.656 777.600 ;
    END
  END tx_flit[163]
  PIN tx_flit[164]
    DIRECTION INPUT ;
    USE SIGNAL ;
    SHAPE ABUTMENT ;
    PORT
      LAYER M5 ;
      RECT 346.680 777.408 346.704 777.600 ;
    END
  END tx_flit[164]
  PIN tx_flit[165]
    DIRECTION INPUT ;
    USE SIGNAL ;
    SHAPE ABUTMENT ;
    PORT
      LAYER M5 ;
      RECT 346.728 777.408 346.752 777.600 ;
    END
  END tx_flit[165]
  PIN tx_flit[166]
    DIRECTION INPUT ;
    USE SIGNAL ;
    SHAPE ABUTMENT ;
    PORT
      LAYER M5 ;
      RECT 346.776 777.408 346.800 777.600 ;
    END
  END tx_flit[166]
  PIN tx_flit[167]
    DIRECTION INPUT ;
    USE SIGNAL ;
    SHAPE ABUTMENT ;
    PORT
      LAYER M5 ;
      RECT 346.824 777.408 346.848 777.600 ;
    END
  END tx_flit[167]
  PIN tx_flit[168]
    DIRECTION INPUT ;
    USE SIGNAL ;
    SHAPE ABUTMENT ;
    PORT
      LAYER M5 ;
      RECT 346.872 777.408 346.896 777.600 ;
    END
  END tx_flit[168]
  PIN tx_flit[169]
    DIRECTION INPUT ;
    USE SIGNAL ;
    SHAPE ABUTMENT ;
    PORT
      LAYER M5 ;
      RECT 346.920 777.408 346.944 777.600 ;
    END
  END tx_flit[169]
  PIN tx_flit[170]
    DIRECTION INPUT ;
    USE SIGNAL ;
    SHAPE ABUTMENT ;
    PORT
      LAYER M5 ;
      RECT 346.968 777.408 346.992 777.600 ;
    END
  END tx_flit[170]
  PIN tx_flit[171]
    DIRECTION INPUT ;
    USE SIGNAL ;
    SHAPE ABUTMENT ;
    PORT
      LAYER M5 ;
      RECT 347.016 777.408 347.040 777.600 ;
    END
  END tx_flit[171]
  PIN tx_flit[172]
    DIRECTION INPUT ;
    USE SIGNAL ;
    SHAPE ABUTMENT ;
    PORT
      LAYER M5 ;
      RECT 347.064 777.408 347.088 777.600 ;
    END
  END tx_flit[172]
  PIN tx_flit[173]
    DIRECTION INPUT ;
    USE SIGNAL ;
    SHAPE ABUTMENT ;
    PORT
      LAYER M5 ;
      RECT 347.112 777.408 347.136 777.600 ;
    END
  END tx_flit[173]
  PIN tx_flit[174]
    DIRECTION INPUT ;
    USE SIGNAL ;
    SHAPE ABUTMENT ;
    PORT
      LAYER M5 ;
      RECT 347.160 777.408 347.184 777.600 ;
    END
  END tx_flit[174]
  PIN tx_flit[175]
    DIRECTION INPUT ;
    USE SIGNAL ;
    SHAPE ABUTMENT ;
    PORT
      LAYER M5 ;
      RECT 347.208 777.408 347.232 777.600 ;
    END
  END tx_flit[175]
  PIN tx_flit[176]
    DIRECTION INPUT ;
    USE SIGNAL ;
    SHAPE ABUTMENT ;
    PORT
      LAYER M5 ;
      RECT 347.256 777.408 347.280 777.600 ;
    END
  END tx_flit[176]
  PIN tx_flit[177]
    DIRECTION INPUT ;
    USE SIGNAL ;
    SHAPE ABUTMENT ;
    PORT
      LAYER M5 ;
      RECT 347.304 777.408 347.328 777.600 ;
    END
  END tx_flit[177]
  PIN tx_flit[178]
    DIRECTION INPUT ;
    USE SIGNAL ;
    SHAPE ABUTMENT ;
    PORT
      LAYER M5 ;
      RECT 347.352 777.408 347.376 777.600 ;
    END
  END tx_flit[178]
  PIN tx_flit[179]
    DIRECTION INPUT ;
    USE SIGNAL ;
    SHAPE ABUTMENT ;
    PORT
      LAYER M5 ;
      RECT 347.400 777.408 347.424 777.600 ;
    END
  END tx_flit[179]
  PIN tx_flit[180]
    DIRECTION INPUT ;
    USE SIGNAL ;
    SHAPE ABUTMENT ;
    PORT
      LAYER M5 ;
      RECT 347.448 777.408 347.472 777.600 ;
    END
  END tx_flit[180]
  PIN tx_flit[181]
    DIRECTION INPUT ;
    USE SIGNAL ;
    SHAPE ABUTMENT ;
    PORT
      LAYER M5 ;
      RECT 347.496 777.408 347.520 777.600 ;
    END
  END tx_flit[181]
  PIN tx_flit[182]
    DIRECTION INPUT ;
    USE SIGNAL ;
    SHAPE ABUTMENT ;
    PORT
      LAYER M5 ;
      RECT 347.544 777.408 347.568 777.600 ;
    END
  END tx_flit[182]
  PIN tx_flit[183]
    DIRECTION INPUT ;
    USE SIGNAL ;
    SHAPE ABUTMENT ;
    PORT
      LAYER M5 ;
      RECT 347.592 777.408 347.616 777.600 ;
    END
  END tx_flit[183]
  PIN tx_flit[184]
    DIRECTION INPUT ;
    USE SIGNAL ;
    SHAPE ABUTMENT ;
    PORT
      LAYER M5 ;
      RECT 347.640 777.408 347.664 777.600 ;
    END
  END tx_flit[184]
  PIN tx_flit[185]
    DIRECTION INPUT ;
    USE SIGNAL ;
    SHAPE ABUTMENT ;
    PORT
      LAYER M5 ;
      RECT 347.688 777.408 347.712 777.600 ;
    END
  END tx_flit[185]
  PIN tx_flit[186]
    DIRECTION INPUT ;
    USE SIGNAL ;
    SHAPE ABUTMENT ;
    PORT
      LAYER M5 ;
      RECT 347.736 777.408 347.760 777.600 ;
    END
  END tx_flit[186]
  PIN tx_flit[187]
    DIRECTION INPUT ;
    USE SIGNAL ;
    SHAPE ABUTMENT ;
    PORT
      LAYER M5 ;
      RECT 347.784 777.408 347.808 777.600 ;
    END
  END tx_flit[187]
  PIN tx_flit[188]
    DIRECTION INPUT ;
    USE SIGNAL ;
    SHAPE ABUTMENT ;
    PORT
      LAYER M5 ;
      RECT 347.832 777.408 347.856 777.600 ;
    END
  END tx_flit[188]
  PIN tx_flit[189]
    DIRECTION INPUT ;
    USE SIGNAL ;
    SHAPE ABUTMENT ;
    PORT
      LAYER M5 ;
      RECT 347.880 777.408 347.904 777.600 ;
    END
  END tx_flit[189]
  PIN tx_flit[190]
    DIRECTION INPUT ;
    USE SIGNAL ;
    SHAPE ABUTMENT ;
    PORT
      LAYER M5 ;
      RECT 347.928 777.408 347.952 777.600 ;
    END
  END tx_flit[190]
  PIN tx_flit[191]
    DIRECTION INPUT ;
    USE SIGNAL ;
    SHAPE ABUTMENT ;
    PORT
      LAYER M5 ;
      RECT 347.976 777.408 348.000 777.600 ;
    END
  END tx_flit[191]
  PIN tx_flit[192]
    DIRECTION INPUT ;
    USE SIGNAL ;
    SHAPE ABUTMENT ;
    PORT
      LAYER M5 ;
      RECT 348.024 777.408 348.048 777.600 ;
    END
  END tx_flit[192]
  PIN tx_flit[193]
    DIRECTION INPUT ;
    USE SIGNAL ;
    SHAPE ABUTMENT ;
    PORT
      LAYER M5 ;
      RECT 348.072 777.408 348.096 777.600 ;
    END
  END tx_flit[193]
  PIN tx_flit[194]
    DIRECTION INPUT ;
    USE SIGNAL ;
    SHAPE ABUTMENT ;
    PORT
      LAYER M5 ;
      RECT 348.120 777.408 348.144 777.600 ;
    END
  END tx_flit[194]
  PIN tx_flit[195]
    DIRECTION INPUT ;
    USE SIGNAL ;
    SHAPE ABUTMENT ;
    PORT
      LAYER M5 ;
      RECT 348.168 777.408 348.192 777.600 ;
    END
  END tx_flit[195]
  PIN tx_flit[196]
    DIRECTION INPUT ;
    USE SIGNAL ;
    SHAPE ABUTMENT ;
    PORT
      LAYER M5 ;
      RECT 348.216 777.408 348.240 777.600 ;
    END
  END tx_flit[196]
  PIN tx_flit[197]
    DIRECTION INPUT ;
    USE SIGNAL ;
    SHAPE ABUTMENT ;
    PORT
      LAYER M5 ;
      RECT 348.264 777.408 348.288 777.600 ;
    END
  END tx_flit[197]
  PIN tx_flit[198]
    DIRECTION INPUT ;
    USE SIGNAL ;
    SHAPE ABUTMENT ;
    PORT
      LAYER M5 ;
      RECT 348.312 777.408 348.336 777.600 ;
    END
  END tx_flit[198]
  PIN tx_flit[199]
    DIRECTION INPUT ;
    USE SIGNAL ;
    SHAPE ABUTMENT ;
    PORT
      LAYER M5 ;
      RECT 348.360 777.408 348.384 777.600 ;
    END
  END tx_flit[199]
  PIN tx_flit[200]
    DIRECTION INPUT ;
    USE SIGNAL ;
    SHAPE ABUTMENT ;
    PORT
      LAYER M5 ;
      RECT 348.408 777.408 348.432 777.600 ;
    END
  END tx_flit[200]
  PIN tx_flit[201]
    DIRECTION INPUT ;
    USE SIGNAL ;
    SHAPE ABUTMENT ;
    PORT
      LAYER M5 ;
      RECT 348.456 777.408 348.480 777.600 ;
    END
  END tx_flit[201]
  PIN tx_flit[202]
    DIRECTION INPUT ;
    USE SIGNAL ;
    SHAPE ABUTMENT ;
    PORT
      LAYER M5 ;
      RECT 348.504 777.408 348.528 777.600 ;
    END
  END tx_flit[202]
  PIN tx_flit[203]
    DIRECTION INPUT ;
    USE SIGNAL ;
    SHAPE ABUTMENT ;
    PORT
      LAYER M5 ;
      RECT 348.552 777.408 348.576 777.600 ;
    END
  END tx_flit[203]
  PIN tx_flit[204]
    DIRECTION INPUT ;
    USE SIGNAL ;
    SHAPE ABUTMENT ;
    PORT
      LAYER M5 ;
      RECT 348.600 777.408 348.624 777.600 ;
    END
  END tx_flit[204]
  PIN tx_flit[205]
    DIRECTION INPUT ;
    USE SIGNAL ;
    SHAPE ABUTMENT ;
    PORT
      LAYER M5 ;
      RECT 348.648 777.408 348.672 777.600 ;
    END
  END tx_flit[205]
  PIN tx_flit[206]
    DIRECTION INPUT ;
    USE SIGNAL ;
    SHAPE ABUTMENT ;
    PORT
      LAYER M5 ;
      RECT 348.696 777.408 348.720 777.600 ;
    END
  END tx_flit[206]
  PIN tx_flit[207]
    DIRECTION INPUT ;
    USE SIGNAL ;
    SHAPE ABUTMENT ;
    PORT
      LAYER M5 ;
      RECT 348.744 777.408 348.768 777.600 ;
    END
  END tx_flit[207]
  PIN tx_flit[208]
    DIRECTION INPUT ;
    USE SIGNAL ;
    SHAPE ABUTMENT ;
    PORT
      LAYER M5 ;
      RECT 348.792 777.408 348.816 777.600 ;
    END
  END tx_flit[208]
  PIN tx_flit[209]
    DIRECTION INPUT ;
    USE SIGNAL ;
    SHAPE ABUTMENT ;
    PORT
      LAYER M5 ;
      RECT 348.840 777.408 348.864 777.600 ;
    END
  END tx_flit[209]
  PIN tx_flit[210]
    DIRECTION INPUT ;
    USE SIGNAL ;
    SHAPE ABUTMENT ;
    PORT
      LAYER M5 ;
      RECT 348.888 777.408 348.912 777.600 ;
    END
  END tx_flit[210]
  PIN tx_flit[211]
    DIRECTION INPUT ;
    USE SIGNAL ;
    SHAPE ABUTMENT ;
    PORT
      LAYER M5 ;
      RECT 348.936 777.408 348.960 777.600 ;
    END
  END tx_flit[211]
  PIN tx_flit[212]
    DIRECTION INPUT ;
    USE SIGNAL ;
    SHAPE ABUTMENT ;
    PORT
      LAYER M5 ;
      RECT 348.984 777.408 349.008 777.600 ;
    END
  END tx_flit[212]
  PIN tx_flit[213]
    DIRECTION INPUT ;
    USE SIGNAL ;
    SHAPE ABUTMENT ;
    PORT
      LAYER M5 ;
      RECT 349.032 777.408 349.056 777.600 ;
    END
  END tx_flit[213]
  PIN tx_flit[214]
    DIRECTION INPUT ;
    USE SIGNAL ;
    SHAPE ABUTMENT ;
    PORT
      LAYER M5 ;
      RECT 349.080 777.408 349.104 777.600 ;
    END
  END tx_flit[214]
  PIN tx_flit[215]
    DIRECTION INPUT ;
    USE SIGNAL ;
    SHAPE ABUTMENT ;
    PORT
      LAYER M5 ;
      RECT 349.128 777.408 349.152 777.600 ;
    END
  END tx_flit[215]
  PIN tx_flit[216]
    DIRECTION INPUT ;
    USE SIGNAL ;
    SHAPE ABUTMENT ;
    PORT
      LAYER M5 ;
      RECT 349.176 777.408 349.200 777.600 ;
    END
  END tx_flit[216]
  PIN tx_flit[217]
    DIRECTION INPUT ;
    USE SIGNAL ;
    SHAPE ABUTMENT ;
    PORT
      LAYER M5 ;
      RECT 349.224 777.408 349.248 777.600 ;
    END
  END tx_flit[217]
  PIN tx_flit[218]
    DIRECTION INPUT ;
    USE SIGNAL ;
    SHAPE ABUTMENT ;
    PORT
      LAYER M5 ;
      RECT 349.272 777.408 349.296 777.600 ;
    END
  END tx_flit[218]
  PIN tx_flit[219]
    DIRECTION INPUT ;
    USE SIGNAL ;
    SHAPE ABUTMENT ;
    PORT
      LAYER M5 ;
      RECT 349.320 777.408 349.344 777.600 ;
    END
  END tx_flit[219]
  PIN tx_flit[220]
    DIRECTION INPUT ;
    USE SIGNAL ;
    SHAPE ABUTMENT ;
    PORT
      LAYER M5 ;
      RECT 349.368 777.408 349.392 777.600 ;
    END
  END tx_flit[220]
  PIN tx_flit[221]
    DIRECTION INPUT ;
    USE SIGNAL ;
    SHAPE ABUTMENT ;
    PORT
      LAYER M5 ;
      RECT 349.416 777.408 349.440 777.600 ;
    END
  END tx_flit[221]
  PIN tx_flit[222]
    DIRECTION INPUT ;
    USE SIGNAL ;
    SHAPE ABUTMENT ;
    PORT
      LAYER M5 ;
      RECT 349.464 777.408 349.488 777.600 ;
    END
  END tx_flit[222]
  PIN tx_flit[223]
    DIRECTION INPUT ;
    USE SIGNAL ;
    SHAPE ABUTMENT ;
    PORT
      LAYER M5 ;
      RECT 349.512 777.408 349.536 777.600 ;
    END
  END tx_flit[223]
  PIN tx_flit[224]
    DIRECTION INPUT ;
    USE SIGNAL ;
    SHAPE ABUTMENT ;
    PORT
      LAYER M5 ;
      RECT 349.560 777.408 349.584 777.600 ;
    END
  END tx_flit[224]
  PIN tx_flit[225]
    DIRECTION INPUT ;
    USE SIGNAL ;
    SHAPE ABUTMENT ;
    PORT
      LAYER M5 ;
      RECT 349.608 777.408 349.632 777.600 ;
    END
  END tx_flit[225]
  PIN tx_flit[226]
    DIRECTION INPUT ;
    USE SIGNAL ;
    SHAPE ABUTMENT ;
    PORT
      LAYER M5 ;
      RECT 349.656 777.408 349.680 777.600 ;
    END
  END tx_flit[226]
  PIN tx_flit[227]
    DIRECTION INPUT ;
    USE SIGNAL ;
    SHAPE ABUTMENT ;
    PORT
      LAYER M5 ;
      RECT 349.704 777.408 349.728 777.600 ;
    END
  END tx_flit[227]
  PIN tx_flit[228]
    DIRECTION INPUT ;
    USE SIGNAL ;
    SHAPE ABUTMENT ;
    PORT
      LAYER M5 ;
      RECT 349.752 777.408 349.776 777.600 ;
    END
  END tx_flit[228]
  PIN tx_flit[229]
    DIRECTION INPUT ;
    USE SIGNAL ;
    SHAPE ABUTMENT ;
    PORT
      LAYER M5 ;
      RECT 349.800 777.408 349.824 777.600 ;
    END
  END tx_flit[229]
  PIN tx_flit[230]
    DIRECTION INPUT ;
    USE SIGNAL ;
    SHAPE ABUTMENT ;
    PORT
      LAYER M5 ;
      RECT 349.848 777.408 349.872 777.600 ;
    END
  END tx_flit[230]
  PIN tx_flit[231]
    DIRECTION INPUT ;
    USE SIGNAL ;
    SHAPE ABUTMENT ;
    PORT
      LAYER M5 ;
      RECT 349.896 777.408 349.920 777.600 ;
    END
  END tx_flit[231]
  PIN tx_flit[232]
    DIRECTION INPUT ;
    USE SIGNAL ;
    SHAPE ABUTMENT ;
    PORT
      LAYER M5 ;
      RECT 349.944 777.408 349.968 777.600 ;
    END
  END tx_flit[232]
  PIN tx_flit[233]
    DIRECTION INPUT ;
    USE SIGNAL ;
    SHAPE ABUTMENT ;
    PORT
      LAYER M5 ;
      RECT 349.992 777.408 350.016 777.600 ;
    END
  END tx_flit[233]
  PIN tx_flit[234]
    DIRECTION INPUT ;
    USE SIGNAL ;
    SHAPE ABUTMENT ;
    PORT
      LAYER M5 ;
      RECT 350.040 777.408 350.064 777.600 ;
    END
  END tx_flit[234]
  PIN tx_flit[235]
    DIRECTION INPUT ;
    USE SIGNAL ;
    SHAPE ABUTMENT ;
    PORT
      LAYER M5 ;
      RECT 350.088 777.408 350.112 777.600 ;
    END
  END tx_flit[235]
  PIN tx_flit[236]
    DIRECTION INPUT ;
    USE SIGNAL ;
    SHAPE ABUTMENT ;
    PORT
      LAYER M5 ;
      RECT 350.136 777.408 350.160 777.600 ;
    END
  END tx_flit[236]
  PIN tx_flit[237]
    DIRECTION INPUT ;
    USE SIGNAL ;
    SHAPE ABUTMENT ;
    PORT
      LAYER M5 ;
      RECT 350.184 777.408 350.208 777.600 ;
    END
  END tx_flit[237]
  PIN tx_flit[238]
    DIRECTION INPUT ;
    USE SIGNAL ;
    SHAPE ABUTMENT ;
    PORT
      LAYER M5 ;
      RECT 350.232 777.408 350.256 777.600 ;
    END
  END tx_flit[238]
  PIN tx_flit[239]
    DIRECTION INPUT ;
    USE SIGNAL ;
    SHAPE ABUTMENT ;
    PORT
      LAYER M5 ;
      RECT 350.280 777.408 350.304 777.600 ;
    END
  END tx_flit[239]
  PIN tx_flit[240]
    DIRECTION INPUT ;
    USE SIGNAL ;
    SHAPE ABUTMENT ;
    PORT
      LAYER M5 ;
      RECT 350.328 777.408 350.352 777.600 ;
    END
  END tx_flit[240]
  PIN tx_flit[241]
    DIRECTION INPUT ;
    USE SIGNAL ;
    SHAPE ABUTMENT ;
    PORT
      LAYER M5 ;
      RECT 350.376 777.408 350.400 777.600 ;
    END
  END tx_flit[241]
  PIN tx_flit[242]
    DIRECTION INPUT ;
    USE SIGNAL ;
    SHAPE ABUTMENT ;
    PORT
      LAYER M5 ;
      RECT 350.424 777.408 350.448 777.600 ;
    END
  END tx_flit[242]
  PIN tx_flit[243]
    DIRECTION INPUT ;
    USE SIGNAL ;
    SHAPE ABUTMENT ;
    PORT
      LAYER M5 ;
      RECT 350.472 777.408 350.496 777.600 ;
    END
  END tx_flit[243]
  PIN tx_flit[244]
    DIRECTION INPUT ;
    USE SIGNAL ;
    SHAPE ABUTMENT ;
    PORT
      LAYER M5 ;
      RECT 350.520 777.408 350.544 777.600 ;
    END
  END tx_flit[244]
  PIN tx_flit[245]
    DIRECTION INPUT ;
    USE SIGNAL ;
    SHAPE ABUTMENT ;
    PORT
      LAYER M5 ;
      RECT 350.568 777.408 350.592 777.600 ;
    END
  END tx_flit[245]
  PIN tx_flit[246]
    DIRECTION INPUT ;
    USE SIGNAL ;
    SHAPE ABUTMENT ;
    PORT
      LAYER M5 ;
      RECT 350.616 777.408 350.640 777.600 ;
    END
  END tx_flit[246]
  PIN tx_flit[247]
    DIRECTION INPUT ;
    USE SIGNAL ;
    SHAPE ABUTMENT ;
    PORT
      LAYER M5 ;
      RECT 350.664 777.408 350.688 777.600 ;
    END
  END tx_flit[247]
  PIN tx_flit[248]
    DIRECTION INPUT ;
    USE SIGNAL ;
    SHAPE ABUTMENT ;
    PORT
      LAYER M5 ;
      RECT 350.712 777.408 350.736 777.600 ;
    END
  END tx_flit[248]
  PIN tx_flit[249]
    DIRECTION INPUT ;
    USE SIGNAL ;
    SHAPE ABUTMENT ;
    PORT
      LAYER M5 ;
      RECT 350.760 777.408 350.784 777.600 ;
    END
  END tx_flit[249]
  PIN tx_flit[250]
    DIRECTION INPUT ;
    USE SIGNAL ;
    SHAPE ABUTMENT ;
    PORT
      LAYER M5 ;
      RECT 350.808 777.408 350.832 777.600 ;
    END
  END tx_flit[250]
  PIN tx_flit[251]
    DIRECTION INPUT ;
    USE SIGNAL ;
    SHAPE ABUTMENT ;
    PORT
      LAYER M5 ;
      RECT 350.856 777.408 350.880 777.600 ;
    END
  END tx_flit[251]
  PIN tx_flit[252]
    DIRECTION INPUT ;
    USE SIGNAL ;
    SHAPE ABUTMENT ;
    PORT
      LAYER M5 ;
      RECT 350.904 777.408 350.928 777.600 ;
    END
  END tx_flit[252]
  PIN tx_flit[253]
    DIRECTION INPUT ;
    USE SIGNAL ;
    SHAPE ABUTMENT ;
    PORT
      LAYER M5 ;
      RECT 350.952 777.408 350.976 777.600 ;
    END
  END tx_flit[253]
  PIN tx_flit[254]
    DIRECTION INPUT ;
    USE SIGNAL ;
    SHAPE ABUTMENT ;
    PORT
      LAYER M5 ;
      RECT 351.000 777.408 351.024 777.600 ;
    END
  END tx_flit[254]
  PIN tx_flit[255]
    DIRECTION INPUT ;
    USE SIGNAL ;
    SHAPE ABUTMENT ;
    PORT
      LAYER M5 ;
      RECT 351.048 777.408 351.072 777.600 ;
    END
  END tx_flit[255]
  PIN tx_flit[256]
    DIRECTION INPUT ;
    USE SIGNAL ;
    SHAPE ABUTMENT ;
    PORT
      LAYER M5 ;
      RECT 351.096 777.408 351.120 777.600 ;
    END
  END tx_flit[256]
  PIN tx_flit[257]
    DIRECTION INPUT ;
    USE SIGNAL ;
    SHAPE ABUTMENT ;
    PORT
      LAYER M5 ;
      RECT 351.144 777.408 351.168 777.600 ;
    END
  END tx_flit[257]
  PIN tx_flit[258]
    DIRECTION INPUT ;
    USE SIGNAL ;
    SHAPE ABUTMENT ;
    PORT
      LAYER M5 ;
      RECT 351.192 777.408 351.216 777.600 ;
    END
  END tx_flit[258]
  PIN tx_flit[259]
    DIRECTION INPUT ;
    USE SIGNAL ;
    SHAPE ABUTMENT ;
    PORT
      LAYER M5 ;
      RECT 351.240 777.408 351.264 777.600 ;
    END
  END tx_flit[259]
  PIN tx_flit[260]
    DIRECTION INPUT ;
    USE SIGNAL ;
    SHAPE ABUTMENT ;
    PORT
      LAYER M5 ;
      RECT 351.288 777.408 351.312 777.600 ;
    END
  END tx_flit[260]
  PIN tx_flit[261]
    DIRECTION INPUT ;
    USE SIGNAL ;
    SHAPE ABUTMENT ;
    PORT
      LAYER M5 ;
      RECT 351.336 777.408 351.360 777.600 ;
    END
  END tx_flit[261]
  PIN tx_flit[262]
    DIRECTION INPUT ;
    USE SIGNAL ;
    SHAPE ABUTMENT ;
    PORT
      LAYER M5 ;
      RECT 351.384 777.408 351.408 777.600 ;
    END
  END tx_flit[262]
  PIN tx_flit[263]
    DIRECTION INPUT ;
    USE SIGNAL ;
    SHAPE ABUTMENT ;
    PORT
      LAYER M5 ;
      RECT 351.432 777.408 351.456 777.600 ;
    END
  END tx_flit[263]
  PIN tx_flit[264]
    DIRECTION INPUT ;
    USE SIGNAL ;
    SHAPE ABUTMENT ;
    PORT
      LAYER M5 ;
      RECT 351.480 777.408 351.504 777.600 ;
    END
  END tx_flit[264]
  PIN tx_flit[265]
    DIRECTION INPUT ;
    USE SIGNAL ;
    SHAPE ABUTMENT ;
    PORT
      LAYER M5 ;
      RECT 351.528 777.408 351.552 777.600 ;
    END
  END tx_flit[265]
  PIN tx_flit[266]
    DIRECTION INPUT ;
    USE SIGNAL ;
    SHAPE ABUTMENT ;
    PORT
      LAYER M5 ;
      RECT 351.576 777.408 351.600 777.600 ;
    END
  END tx_flit[266]
  PIN tx_flit[267]
    DIRECTION INPUT ;
    USE SIGNAL ;
    SHAPE ABUTMENT ;
    PORT
      LAYER M5 ;
      RECT 351.624 777.408 351.648 777.600 ;
    END
  END tx_flit[267]
  PIN tx_flit[268]
    DIRECTION INPUT ;
    USE SIGNAL ;
    SHAPE ABUTMENT ;
    PORT
      LAYER M5 ;
      RECT 351.672 777.408 351.696 777.600 ;
    END
  END tx_flit[268]
  PIN tx_flit[269]
    DIRECTION INPUT ;
    USE SIGNAL ;
    SHAPE ABUTMENT ;
    PORT
      LAYER M5 ;
      RECT 351.720 777.408 351.744 777.600 ;
    END
  END tx_flit[269]
  PIN tx_flit[270]
    DIRECTION INPUT ;
    USE SIGNAL ;
    SHAPE ABUTMENT ;
    PORT
      LAYER M5 ;
      RECT 351.768 777.408 351.792 777.600 ;
    END
  END tx_flit[270]
  PIN tx_flit[271]
    DIRECTION INPUT ;
    USE SIGNAL ;
    SHAPE ABUTMENT ;
    PORT
      LAYER M5 ;
      RECT 351.816 777.408 351.840 777.600 ;
    END
  END tx_flit[271]
  PIN tx_flit[272]
    DIRECTION INPUT ;
    USE SIGNAL ;
    SHAPE ABUTMENT ;
    PORT
      LAYER M5 ;
      RECT 351.864 777.408 351.888 777.600 ;
    END
  END tx_flit[272]
  PIN tx_flit[273]
    DIRECTION INPUT ;
    USE SIGNAL ;
    SHAPE ABUTMENT ;
    PORT
      LAYER M5 ;
      RECT 351.912 777.408 351.936 777.600 ;
    END
  END tx_flit[273]
  PIN tx_flit[274]
    DIRECTION INPUT ;
    USE SIGNAL ;
    SHAPE ABUTMENT ;
    PORT
      LAYER M5 ;
      RECT 351.960 777.408 351.984 777.600 ;
    END
  END tx_flit[274]
  PIN tx_flit[275]
    DIRECTION INPUT ;
    USE SIGNAL ;
    SHAPE ABUTMENT ;
    PORT
      LAYER M5 ;
      RECT 352.008 777.408 352.032 777.600 ;
    END
  END tx_flit[275]
  PIN tx_flit[276]
    DIRECTION INPUT ;
    USE SIGNAL ;
    SHAPE ABUTMENT ;
    PORT
      LAYER M5 ;
      RECT 352.056 777.408 352.080 777.600 ;
    END
  END tx_flit[276]
  PIN tx_flit[277]
    DIRECTION INPUT ;
    USE SIGNAL ;
    SHAPE ABUTMENT ;
    PORT
      LAYER M5 ;
      RECT 352.104 777.408 352.128 777.600 ;
    END
  END tx_flit[277]
  PIN tx_flit[278]
    DIRECTION INPUT ;
    USE SIGNAL ;
    SHAPE ABUTMENT ;
    PORT
      LAYER M5 ;
      RECT 352.152 777.408 352.176 777.600 ;
    END
  END tx_flit[278]
  PIN tx_flit[279]
    DIRECTION INPUT ;
    USE SIGNAL ;
    SHAPE ABUTMENT ;
    PORT
      LAYER M5 ;
      RECT 352.200 777.408 352.224 777.600 ;
    END
  END tx_flit[279]
  PIN tx_flit[280]
    DIRECTION INPUT ;
    USE SIGNAL ;
    SHAPE ABUTMENT ;
    PORT
      LAYER M5 ;
      RECT 352.248 777.408 352.272 777.600 ;
    END
  END tx_flit[280]
  PIN tx_flit[281]
    DIRECTION INPUT ;
    USE SIGNAL ;
    SHAPE ABUTMENT ;
    PORT
      LAYER M5 ;
      RECT 352.296 777.408 352.320 777.600 ;
    END
  END tx_flit[281]
  PIN tx_flit[282]
    DIRECTION INPUT ;
    USE SIGNAL ;
    SHAPE ABUTMENT ;
    PORT
      LAYER M5 ;
      RECT 352.344 777.408 352.368 777.600 ;
    END
  END tx_flit[282]
  PIN tx_flit[283]
    DIRECTION INPUT ;
    USE SIGNAL ;
    SHAPE ABUTMENT ;
    PORT
      LAYER M5 ;
      RECT 352.392 777.408 352.416 777.600 ;
    END
  END tx_flit[283]
  PIN tx_flit[284]
    DIRECTION INPUT ;
    USE SIGNAL ;
    SHAPE ABUTMENT ;
    PORT
      LAYER M5 ;
      RECT 352.440 777.408 352.464 777.600 ;
    END
  END tx_flit[284]
  PIN tx_flit[285]
    DIRECTION INPUT ;
    USE SIGNAL ;
    SHAPE ABUTMENT ;
    PORT
      LAYER M5 ;
      RECT 352.488 777.408 352.512 777.600 ;
    END
  END tx_flit[285]
  PIN tx_flit[286]
    DIRECTION INPUT ;
    USE SIGNAL ;
    SHAPE ABUTMENT ;
    PORT
      LAYER M5 ;
      RECT 352.536 777.408 352.560 777.600 ;
    END
  END tx_flit[286]
  PIN tx_flit[287]
    DIRECTION INPUT ;
    USE SIGNAL ;
    SHAPE ABUTMENT ;
    PORT
      LAYER M5 ;
      RECT 352.584 777.408 352.608 777.600 ;
    END
  END tx_flit[287]
  PIN tx_flit[288]
    DIRECTION INPUT ;
    USE SIGNAL ;
    SHAPE ABUTMENT ;
    PORT
      LAYER M5 ;
      RECT 352.632 777.408 352.656 777.600 ;
    END
  END tx_flit[288]
  PIN tx_flit[289]
    DIRECTION INPUT ;
    USE SIGNAL ;
    SHAPE ABUTMENT ;
    PORT
      LAYER M5 ;
      RECT 352.680 777.408 352.704 777.600 ;
    END
  END tx_flit[289]
  PIN tx_flit[290]
    DIRECTION INPUT ;
    USE SIGNAL ;
    SHAPE ABUTMENT ;
    PORT
      LAYER M5 ;
      RECT 352.728 777.408 352.752 777.600 ;
    END
  END tx_flit[290]
  PIN tx_flit[291]
    DIRECTION INPUT ;
    USE SIGNAL ;
    SHAPE ABUTMENT ;
    PORT
      LAYER M5 ;
      RECT 352.776 777.408 352.800 777.600 ;
    END
  END tx_flit[291]
  PIN tx_flit[292]
    DIRECTION INPUT ;
    USE SIGNAL ;
    SHAPE ABUTMENT ;
    PORT
      LAYER M5 ;
      RECT 352.824 777.408 352.848 777.600 ;
    END
  END tx_flit[292]
  PIN tx_flit[293]
    DIRECTION INPUT ;
    USE SIGNAL ;
    SHAPE ABUTMENT ;
    PORT
      LAYER M5 ;
      RECT 352.872 777.408 352.896 777.600 ;
    END
  END tx_flit[293]
  PIN tx_flit[294]
    DIRECTION INPUT ;
    USE SIGNAL ;
    SHAPE ABUTMENT ;
    PORT
      LAYER M5 ;
      RECT 352.920 777.408 352.944 777.600 ;
    END
  END tx_flit[294]
  PIN tx_flit[295]
    DIRECTION INPUT ;
    USE SIGNAL ;
    SHAPE ABUTMENT ;
    PORT
      LAYER M5 ;
      RECT 352.968 777.408 352.992 777.600 ;
    END
  END tx_flit[295]
  PIN tx_flit[296]
    DIRECTION INPUT ;
    USE SIGNAL ;
    SHAPE ABUTMENT ;
    PORT
      LAYER M5 ;
      RECT 353.016 777.408 353.040 777.600 ;
    END
  END tx_flit[296]
  PIN tx_flit[297]
    DIRECTION INPUT ;
    USE SIGNAL ;
    SHAPE ABUTMENT ;
    PORT
      LAYER M5 ;
      RECT 353.064 777.408 353.088 777.600 ;
    END
  END tx_flit[297]
  PIN tx_flit[298]
    DIRECTION INPUT ;
    USE SIGNAL ;
    SHAPE ABUTMENT ;
    PORT
      LAYER M5 ;
      RECT 353.112 777.408 353.136 777.600 ;
    END
  END tx_flit[298]
  PIN tx_flit[299]
    DIRECTION INPUT ;
    USE SIGNAL ;
    SHAPE ABUTMENT ;
    PORT
      LAYER M5 ;
      RECT 353.160 777.408 353.184 777.600 ;
    END
  END tx_flit[299]
  PIN tx_flit[300]
    DIRECTION INPUT ;
    USE SIGNAL ;
    SHAPE ABUTMENT ;
    PORT
      LAYER M5 ;
      RECT 353.208 777.408 353.232 777.600 ;
    END
  END tx_flit[300]
  PIN tx_flit[301]
    DIRECTION INPUT ;
    USE SIGNAL ;
    SHAPE ABUTMENT ;
    PORT
      LAYER M5 ;
      RECT 353.256 777.408 353.280 777.600 ;
    END
  END tx_flit[301]
  PIN tx_flit[302]
    DIRECTION INPUT ;
    USE SIGNAL ;
    SHAPE ABUTMENT ;
    PORT
      LAYER M5 ;
      RECT 353.304 777.408 353.328 777.600 ;
    END
  END tx_flit[302]
  PIN tx_flit[303]
    DIRECTION INPUT ;
    USE SIGNAL ;
    SHAPE ABUTMENT ;
    PORT
      LAYER M5 ;
      RECT 353.352 777.408 353.376 777.600 ;
    END
  END tx_flit[303]
  PIN tx_flit[304]
    DIRECTION INPUT ;
    USE SIGNAL ;
    SHAPE ABUTMENT ;
    PORT
      LAYER M5 ;
      RECT 353.400 777.408 353.424 777.600 ;
    END
  END tx_flit[304]
  PIN tx_flit[305]
    DIRECTION INPUT ;
    USE SIGNAL ;
    SHAPE ABUTMENT ;
    PORT
      LAYER M5 ;
      RECT 353.448 777.408 353.472 777.600 ;
    END
  END tx_flit[305]
  PIN tx_flit[306]
    DIRECTION INPUT ;
    USE SIGNAL ;
    SHAPE ABUTMENT ;
    PORT
      LAYER M5 ;
      RECT 353.496 777.408 353.520 777.600 ;
    END
  END tx_flit[306]
  PIN tx_flit[307]
    DIRECTION INPUT ;
    USE SIGNAL ;
    SHAPE ABUTMENT ;
    PORT
      LAYER M5 ;
      RECT 353.544 777.408 353.568 777.600 ;
    END
  END tx_flit[307]
  PIN tx_flit[308]
    DIRECTION INPUT ;
    USE SIGNAL ;
    SHAPE ABUTMENT ;
    PORT
      LAYER M5 ;
      RECT 353.592 777.408 353.616 777.600 ;
    END
  END tx_flit[308]
  PIN tx_flit[309]
    DIRECTION INPUT ;
    USE SIGNAL ;
    SHAPE ABUTMENT ;
    PORT
      LAYER M5 ;
      RECT 353.640 777.408 353.664 777.600 ;
    END
  END tx_flit[309]
  PIN tx_flit[310]
    DIRECTION INPUT ;
    USE SIGNAL ;
    SHAPE ABUTMENT ;
    PORT
      LAYER M5 ;
      RECT 353.688 777.408 353.712 777.600 ;
    END
  END tx_flit[310]
  PIN tx_flit[311]
    DIRECTION INPUT ;
    USE SIGNAL ;
    SHAPE ABUTMENT ;
    PORT
      LAYER M5 ;
      RECT 353.736 777.408 353.760 777.600 ;
    END
  END tx_flit[311]
  PIN tx_flit[312]
    DIRECTION INPUT ;
    USE SIGNAL ;
    SHAPE ABUTMENT ;
    PORT
      LAYER M5 ;
      RECT 353.784 777.408 353.808 777.600 ;
    END
  END tx_flit[312]
  PIN tx_flit[313]
    DIRECTION INPUT ;
    USE SIGNAL ;
    SHAPE ABUTMENT ;
    PORT
      LAYER M5 ;
      RECT 353.832 777.408 353.856 777.600 ;
    END
  END tx_flit[313]
  PIN tx_flit[314]
    DIRECTION INPUT ;
    USE SIGNAL ;
    SHAPE ABUTMENT ;
    PORT
      LAYER M5 ;
      RECT 353.880 777.408 353.904 777.600 ;
    END
  END tx_flit[314]
  PIN tx_flit[315]
    DIRECTION INPUT ;
    USE SIGNAL ;
    SHAPE ABUTMENT ;
    PORT
      LAYER M5 ;
      RECT 353.928 777.408 353.952 777.600 ;
    END
  END tx_flit[315]
  PIN tx_flit[316]
    DIRECTION INPUT ;
    USE SIGNAL ;
    SHAPE ABUTMENT ;
    PORT
      LAYER M5 ;
      RECT 353.976 777.408 354.000 777.600 ;
    END
  END tx_flit[316]
  PIN tx_flit[317]
    DIRECTION INPUT ;
    USE SIGNAL ;
    SHAPE ABUTMENT ;
    PORT
      LAYER M5 ;
      RECT 354.024 777.408 354.048 777.600 ;
    END
  END tx_flit[317]
  PIN tx_flit[318]
    DIRECTION INPUT ;
    USE SIGNAL ;
    SHAPE ABUTMENT ;
    PORT
      LAYER M5 ;
      RECT 354.072 777.408 354.096 777.600 ;
    END
  END tx_flit[318]
  PIN tx_flit[319]
    DIRECTION INPUT ;
    USE SIGNAL ;
    SHAPE ABUTMENT ;
    PORT
      LAYER M5 ;
      RECT 354.120 777.408 354.144 777.600 ;
    END
  END tx_flit[319]
  PIN tx_flit[320]
    DIRECTION INPUT ;
    USE SIGNAL ;
    SHAPE ABUTMENT ;
    PORT
      LAYER M5 ;
      RECT 354.168 777.408 354.192 777.600 ;
    END
  END tx_flit[320]
  PIN tx_flit[321]
    DIRECTION INPUT ;
    USE SIGNAL ;
    SHAPE ABUTMENT ;
    PORT
      LAYER M5 ;
      RECT 354.216 777.408 354.240 777.600 ;
    END
  END tx_flit[321]
  PIN tx_flit[322]
    DIRECTION INPUT ;
    USE SIGNAL ;
    SHAPE ABUTMENT ;
    PORT
      LAYER M5 ;
      RECT 354.264 777.408 354.288 777.600 ;
    END
  END tx_flit[322]
  PIN tx_flit[323]
    DIRECTION INPUT ;
    USE SIGNAL ;
    SHAPE ABUTMENT ;
    PORT
      LAYER M5 ;
      RECT 354.312 777.408 354.336 777.600 ;
    END
  END tx_flit[323]
  PIN tx_flit[324]
    DIRECTION INPUT ;
    USE SIGNAL ;
    SHAPE ABUTMENT ;
    PORT
      LAYER M5 ;
      RECT 354.360 777.408 354.384 777.600 ;
    END
  END tx_flit[324]
  PIN tx_flit[325]
    DIRECTION INPUT ;
    USE SIGNAL ;
    SHAPE ABUTMENT ;
    PORT
      LAYER M5 ;
      RECT 354.408 777.408 354.432 777.600 ;
    END
  END tx_flit[325]
  PIN tx_flit[326]
    DIRECTION INPUT ;
    USE SIGNAL ;
    SHAPE ABUTMENT ;
    PORT
      LAYER M5 ;
      RECT 354.456 777.408 354.480 777.600 ;
    END
  END tx_flit[326]
  PIN tx_flit[327]
    DIRECTION INPUT ;
    USE SIGNAL ;
    SHAPE ABUTMENT ;
    PORT
      LAYER M5 ;
      RECT 354.504 777.408 354.528 777.600 ;
    END
  END tx_flit[327]
  PIN tx_flit[328]
    DIRECTION INPUT ;
    USE SIGNAL ;
    SHAPE ABUTMENT ;
    PORT
      LAYER M5 ;
      RECT 354.552 777.408 354.576 777.600 ;
    END
  END tx_flit[328]
  PIN tx_flit[329]
    DIRECTION INPUT ;
    USE SIGNAL ;
    SHAPE ABUTMENT ;
    PORT
      LAYER M5 ;
      RECT 354.600 777.408 354.624 777.600 ;
    END
  END tx_flit[329]
  PIN tx_flit[330]
    DIRECTION INPUT ;
    USE SIGNAL ;
    SHAPE ABUTMENT ;
    PORT
      LAYER M5 ;
      RECT 354.648 777.408 354.672 777.600 ;
    END
  END tx_flit[330]
  PIN tx_flit[331]
    DIRECTION INPUT ;
    USE SIGNAL ;
    SHAPE ABUTMENT ;
    PORT
      LAYER M5 ;
      RECT 354.696 777.408 354.720 777.600 ;
    END
  END tx_flit[331]
  PIN tx_flit[332]
    DIRECTION INPUT ;
    USE SIGNAL ;
    SHAPE ABUTMENT ;
    PORT
      LAYER M5 ;
      RECT 354.744 777.408 354.768 777.600 ;
    END
  END tx_flit[332]
  PIN tx_flit[333]
    DIRECTION INPUT ;
    USE SIGNAL ;
    SHAPE ABUTMENT ;
    PORT
      LAYER M5 ;
      RECT 354.792 777.408 354.816 777.600 ;
    END
  END tx_flit[333]
  PIN tx_flit[334]
    DIRECTION INPUT ;
    USE SIGNAL ;
    SHAPE ABUTMENT ;
    PORT
      LAYER M5 ;
      RECT 354.840 777.408 354.864 777.600 ;
    END
  END tx_flit[334]
  PIN tx_flit[335]
    DIRECTION INPUT ;
    USE SIGNAL ;
    SHAPE ABUTMENT ;
    PORT
      LAYER M5 ;
      RECT 354.888 777.408 354.912 777.600 ;
    END
  END tx_flit[335]
  PIN tx_flit[336]
    DIRECTION INPUT ;
    USE SIGNAL ;
    SHAPE ABUTMENT ;
    PORT
      LAYER M5 ;
      RECT 354.936 777.408 354.960 777.600 ;
    END
  END tx_flit[336]
  PIN tx_flit[337]
    DIRECTION INPUT ;
    USE SIGNAL ;
    SHAPE ABUTMENT ;
    PORT
      LAYER M5 ;
      RECT 354.984 777.408 355.008 777.600 ;
    END
  END tx_flit[337]
  PIN tx_flit[338]
    DIRECTION INPUT ;
    USE SIGNAL ;
    SHAPE ABUTMENT ;
    PORT
      LAYER M5 ;
      RECT 355.032 777.408 355.056 777.600 ;
    END
  END tx_flit[338]
  PIN tx_flit[339]
    DIRECTION INPUT ;
    USE SIGNAL ;
    SHAPE ABUTMENT ;
    PORT
      LAYER M5 ;
      RECT 355.080 777.408 355.104 777.600 ;
    END
  END tx_flit[339]
  PIN tx_flit[340]
    DIRECTION INPUT ;
    USE SIGNAL ;
    SHAPE ABUTMENT ;
    PORT
      LAYER M5 ;
      RECT 355.128 777.408 355.152 777.600 ;
    END
  END tx_flit[340]
  PIN tx_flit[341]
    DIRECTION INPUT ;
    USE SIGNAL ;
    SHAPE ABUTMENT ;
    PORT
      LAYER M5 ;
      RECT 355.176 777.408 355.200 777.600 ;
    END
  END tx_flit[341]
  PIN tx_flit[342]
    DIRECTION INPUT ;
    USE SIGNAL ;
    SHAPE ABUTMENT ;
    PORT
      LAYER M5 ;
      RECT 355.224 777.408 355.248 777.600 ;
    END
  END tx_flit[342]
  PIN tx_flit[343]
    DIRECTION INPUT ;
    USE SIGNAL ;
    SHAPE ABUTMENT ;
    PORT
      LAYER M5 ;
      RECT 355.272 777.408 355.296 777.600 ;
    END
  END tx_flit[343]
  PIN tx_flit[344]
    DIRECTION INPUT ;
    USE SIGNAL ;
    SHAPE ABUTMENT ;
    PORT
      LAYER M5 ;
      RECT 355.320 777.408 355.344 777.600 ;
    END
  END tx_flit[344]
  PIN tx_flit[345]
    DIRECTION INPUT ;
    USE SIGNAL ;
    SHAPE ABUTMENT ;
    PORT
      LAYER M5 ;
      RECT 355.368 777.408 355.392 777.600 ;
    END
  END tx_flit[345]
  PIN tx_flit[346]
    DIRECTION INPUT ;
    USE SIGNAL ;
    SHAPE ABUTMENT ;
    PORT
      LAYER M5 ;
      RECT 355.416 777.408 355.440 777.600 ;
    END
  END tx_flit[346]
  PIN tx_flit[347]
    DIRECTION INPUT ;
    USE SIGNAL ;
    SHAPE ABUTMENT ;
    PORT
      LAYER M5 ;
      RECT 355.464 777.408 355.488 777.600 ;
    END
  END tx_flit[347]
  PIN tx_flit[348]
    DIRECTION INPUT ;
    USE SIGNAL ;
    SHAPE ABUTMENT ;
    PORT
      LAYER M5 ;
      RECT 355.512 777.408 355.536 777.600 ;
    END
  END tx_flit[348]
  PIN tx_flit[349]
    DIRECTION INPUT ;
    USE SIGNAL ;
    SHAPE ABUTMENT ;
    PORT
      LAYER M5 ;
      RECT 355.560 777.408 355.584 777.600 ;
    END
  END tx_flit[349]
  PIN tx_flit[350]
    DIRECTION INPUT ;
    USE SIGNAL ;
    SHAPE ABUTMENT ;
    PORT
      LAYER M5 ;
      RECT 355.608 777.408 355.632 777.600 ;
    END
  END tx_flit[350]
  PIN tx_flit[351]
    DIRECTION INPUT ;
    USE SIGNAL ;
    SHAPE ABUTMENT ;
    PORT
      LAYER M5 ;
      RECT 355.656 777.408 355.680 777.600 ;
    END
  END tx_flit[351]
  PIN tx_flit[352]
    DIRECTION INPUT ;
    USE SIGNAL ;
    SHAPE ABUTMENT ;
    PORT
      LAYER M5 ;
      RECT 355.704 777.408 355.728 777.600 ;
    END
  END tx_flit[352]
  PIN tx_flit[353]
    DIRECTION INPUT ;
    USE SIGNAL ;
    SHAPE ABUTMENT ;
    PORT
      LAYER M5 ;
      RECT 355.752 777.408 355.776 777.600 ;
    END
  END tx_flit[353]
  PIN tx_flit[354]
    DIRECTION INPUT ;
    USE SIGNAL ;
    SHAPE ABUTMENT ;
    PORT
      LAYER M5 ;
      RECT 355.800 777.408 355.824 777.600 ;
    END
  END tx_flit[354]
  PIN tx_flit[355]
    DIRECTION INPUT ;
    USE SIGNAL ;
    SHAPE ABUTMENT ;
    PORT
      LAYER M5 ;
      RECT 355.848 777.408 355.872 777.600 ;
    END
  END tx_flit[355]
  PIN tx_flit[356]
    DIRECTION INPUT ;
    USE SIGNAL ;
    SHAPE ABUTMENT ;
    PORT
      LAYER M5 ;
      RECT 355.896 777.408 355.920 777.600 ;
    END
  END tx_flit[356]
  PIN tx_flit[357]
    DIRECTION INPUT ;
    USE SIGNAL ;
    SHAPE ABUTMENT ;
    PORT
      LAYER M5 ;
      RECT 355.944 777.408 355.968 777.600 ;
    END
  END tx_flit[357]
  PIN tx_flit[358]
    DIRECTION INPUT ;
    USE SIGNAL ;
    SHAPE ABUTMENT ;
    PORT
      LAYER M5 ;
      RECT 355.992 777.408 356.016 777.600 ;
    END
  END tx_flit[358]
  PIN tx_flit[359]
    DIRECTION INPUT ;
    USE SIGNAL ;
    SHAPE ABUTMENT ;
    PORT
      LAYER M5 ;
      RECT 356.040 777.408 356.064 777.600 ;
    END
  END tx_flit[359]
  PIN tx_flit[360]
    DIRECTION INPUT ;
    USE SIGNAL ;
    SHAPE ABUTMENT ;
    PORT
      LAYER M5 ;
      RECT 356.088 777.408 356.112 777.600 ;
    END
  END tx_flit[360]
  PIN tx_flit[361]
    DIRECTION INPUT ;
    USE SIGNAL ;
    SHAPE ABUTMENT ;
    PORT
      LAYER M5 ;
      RECT 356.136 777.408 356.160 777.600 ;
    END
  END tx_flit[361]
  PIN tx_flit[362]
    DIRECTION INPUT ;
    USE SIGNAL ;
    SHAPE ABUTMENT ;
    PORT
      LAYER M5 ;
      RECT 356.184 777.408 356.208 777.600 ;
    END
  END tx_flit[362]
  PIN tx_flit[363]
    DIRECTION INPUT ;
    USE SIGNAL ;
    SHAPE ABUTMENT ;
    PORT
      LAYER M5 ;
      RECT 356.232 777.408 356.256 777.600 ;
    END
  END tx_flit[363]
  PIN tx_flit[364]
    DIRECTION INPUT ;
    USE SIGNAL ;
    SHAPE ABUTMENT ;
    PORT
      LAYER M5 ;
      RECT 356.280 777.408 356.304 777.600 ;
    END
  END tx_flit[364]
  PIN tx_flit[365]
    DIRECTION INPUT ;
    USE SIGNAL ;
    SHAPE ABUTMENT ;
    PORT
      LAYER M5 ;
      RECT 356.328 777.408 356.352 777.600 ;
    END
  END tx_flit[365]
  PIN tx_flit[366]
    DIRECTION INPUT ;
    USE SIGNAL ;
    SHAPE ABUTMENT ;
    PORT
      LAYER M5 ;
      RECT 356.376 777.408 356.400 777.600 ;
    END
  END tx_flit[366]
  PIN tx_flit[367]
    DIRECTION INPUT ;
    USE SIGNAL ;
    SHAPE ABUTMENT ;
    PORT
      LAYER M5 ;
      RECT 356.424 777.408 356.448 777.600 ;
    END
  END tx_flit[367]
  PIN tx_flit[368]
    DIRECTION INPUT ;
    USE SIGNAL ;
    SHAPE ABUTMENT ;
    PORT
      LAYER M5 ;
      RECT 356.472 777.408 356.496 777.600 ;
    END
  END tx_flit[368]
  PIN tx_flit[369]
    DIRECTION INPUT ;
    USE SIGNAL ;
    SHAPE ABUTMENT ;
    PORT
      LAYER M5 ;
      RECT 356.520 777.408 356.544 777.600 ;
    END
  END tx_flit[369]
  PIN tx_flit[370]
    DIRECTION INPUT ;
    USE SIGNAL ;
    SHAPE ABUTMENT ;
    PORT
      LAYER M5 ;
      RECT 356.568 777.408 356.592 777.600 ;
    END
  END tx_flit[370]
  PIN tx_flit[371]
    DIRECTION INPUT ;
    USE SIGNAL ;
    SHAPE ABUTMENT ;
    PORT
      LAYER M5 ;
      RECT 356.616 777.408 356.640 777.600 ;
    END
  END tx_flit[371]
  PIN tx_flit[372]
    DIRECTION INPUT ;
    USE SIGNAL ;
    SHAPE ABUTMENT ;
    PORT
      LAYER M5 ;
      RECT 356.664 777.408 356.688 777.600 ;
    END
  END tx_flit[372]
  PIN tx_flit[373]
    DIRECTION INPUT ;
    USE SIGNAL ;
    SHAPE ABUTMENT ;
    PORT
      LAYER M5 ;
      RECT 356.712 777.408 356.736 777.600 ;
    END
  END tx_flit[373]
  PIN tx_flit[374]
    DIRECTION INPUT ;
    USE SIGNAL ;
    SHAPE ABUTMENT ;
    PORT
      LAYER M5 ;
      RECT 356.760 777.408 356.784 777.600 ;
    END
  END tx_flit[374]
  PIN tx_flit[375]
    DIRECTION INPUT ;
    USE SIGNAL ;
    SHAPE ABUTMENT ;
    PORT
      LAYER M5 ;
      RECT 356.808 777.408 356.832 777.600 ;
    END
  END tx_flit[375]
  PIN tx_flit[376]
    DIRECTION INPUT ;
    USE SIGNAL ;
    SHAPE ABUTMENT ;
    PORT
      LAYER M5 ;
      RECT 356.856 777.408 356.880 777.600 ;
    END
  END tx_flit[376]
  PIN tx_flit[377]
    DIRECTION INPUT ;
    USE SIGNAL ;
    SHAPE ABUTMENT ;
    PORT
      LAYER M5 ;
      RECT 356.904 777.408 356.928 777.600 ;
    END
  END tx_flit[377]
  PIN tx_flit[378]
    DIRECTION INPUT ;
    USE SIGNAL ;
    SHAPE ABUTMENT ;
    PORT
      LAYER M5 ;
      RECT 356.952 777.408 356.976 777.600 ;
    END
  END tx_flit[378]
  PIN tx_flit[379]
    DIRECTION INPUT ;
    USE SIGNAL ;
    SHAPE ABUTMENT ;
    PORT
      LAYER M5 ;
      RECT 357.000 777.408 357.024 777.600 ;
    END
  END tx_flit[379]
  PIN tx_flit[380]
    DIRECTION INPUT ;
    USE SIGNAL ;
    SHAPE ABUTMENT ;
    PORT
      LAYER M5 ;
      RECT 357.048 777.408 357.072 777.600 ;
    END
  END tx_flit[380]
  PIN tx_flit[381]
    DIRECTION INPUT ;
    USE SIGNAL ;
    SHAPE ABUTMENT ;
    PORT
      LAYER M5 ;
      RECT 357.096 777.408 357.120 777.600 ;
    END
  END tx_flit[381]
  PIN tx_flit[382]
    DIRECTION INPUT ;
    USE SIGNAL ;
    SHAPE ABUTMENT ;
    PORT
      LAYER M5 ;
      RECT 357.144 777.408 357.168 777.600 ;
    END
  END tx_flit[382]
  PIN tx_flit[383]
    DIRECTION INPUT ;
    USE SIGNAL ;
    SHAPE ABUTMENT ;
    PORT
      LAYER M5 ;
      RECT 357.192 777.408 357.216 777.600 ;
    END
  END tx_flit[383]
  PIN tx_flit[384]
    DIRECTION INPUT ;
    USE SIGNAL ;
    SHAPE ABUTMENT ;
    PORT
      LAYER M5 ;
      RECT 357.240 777.408 357.264 777.600 ;
    END
  END tx_flit[384]
  PIN tx_flit[385]
    DIRECTION INPUT ;
    USE SIGNAL ;
    SHAPE ABUTMENT ;
    PORT
      LAYER M5 ;
      RECT 357.288 777.408 357.312 777.600 ;
    END
  END tx_flit[385]
  PIN tx_flit[386]
    DIRECTION INPUT ;
    USE SIGNAL ;
    SHAPE ABUTMENT ;
    PORT
      LAYER M5 ;
      RECT 357.336 777.408 357.360 777.600 ;
    END
  END tx_flit[386]
  PIN tx_flit[387]
    DIRECTION INPUT ;
    USE SIGNAL ;
    SHAPE ABUTMENT ;
    PORT
      LAYER M5 ;
      RECT 357.384 777.408 357.408 777.600 ;
    END
  END tx_flit[387]
  PIN tx_flit[388]
    DIRECTION INPUT ;
    USE SIGNAL ;
    SHAPE ABUTMENT ;
    PORT
      LAYER M5 ;
      RECT 357.432 777.408 357.456 777.600 ;
    END
  END tx_flit[388]
  PIN tx_flit[389]
    DIRECTION INPUT ;
    USE SIGNAL ;
    SHAPE ABUTMENT ;
    PORT
      LAYER M5 ;
      RECT 357.480 777.408 357.504 777.600 ;
    END
  END tx_flit[389]
  PIN tx_flit[390]
    DIRECTION INPUT ;
    USE SIGNAL ;
    SHAPE ABUTMENT ;
    PORT
      LAYER M5 ;
      RECT 357.528 777.408 357.552 777.600 ;
    END
  END tx_flit[390]
  PIN tx_flit[391]
    DIRECTION INPUT ;
    USE SIGNAL ;
    SHAPE ABUTMENT ;
    PORT
      LAYER M5 ;
      RECT 357.576 777.408 357.600 777.600 ;
    END
  END tx_flit[391]
  PIN tx_flit[392]
    DIRECTION INPUT ;
    USE SIGNAL ;
    SHAPE ABUTMENT ;
    PORT
      LAYER M5 ;
      RECT 357.624 777.408 357.648 777.600 ;
    END
  END tx_flit[392]
  PIN tx_flit[393]
    DIRECTION INPUT ;
    USE SIGNAL ;
    SHAPE ABUTMENT ;
    PORT
      LAYER M5 ;
      RECT 357.672 777.408 357.696 777.600 ;
    END
  END tx_flit[393]
  PIN tx_flit[394]
    DIRECTION INPUT ;
    USE SIGNAL ;
    SHAPE ABUTMENT ;
    PORT
      LAYER M5 ;
      RECT 357.720 777.408 357.744 777.600 ;
    END
  END tx_flit[394]
  PIN tx_flit[395]
    DIRECTION INPUT ;
    USE SIGNAL ;
    SHAPE ABUTMENT ;
    PORT
      LAYER M5 ;
      RECT 357.768 777.408 357.792 777.600 ;
    END
  END tx_flit[395]
  PIN tx_flit[396]
    DIRECTION INPUT ;
    USE SIGNAL ;
    SHAPE ABUTMENT ;
    PORT
      LAYER M5 ;
      RECT 357.816 777.408 357.840 777.600 ;
    END
  END tx_flit[396]
  PIN tx_flit[397]
    DIRECTION INPUT ;
    USE SIGNAL ;
    SHAPE ABUTMENT ;
    PORT
      LAYER M5 ;
      RECT 357.864 777.408 357.888 777.600 ;
    END
  END tx_flit[397]
  PIN tx_flit[398]
    DIRECTION INPUT ;
    USE SIGNAL ;
    SHAPE ABUTMENT ;
    PORT
      LAYER M5 ;
      RECT 357.912 777.408 357.936 777.600 ;
    END
  END tx_flit[398]
  PIN tx_flit[399]
    DIRECTION INPUT ;
    USE SIGNAL ;
    SHAPE ABUTMENT ;
    PORT
      LAYER M5 ;
      RECT 357.960 777.408 357.984 777.600 ;
    END
  END tx_flit[399]
  PIN tx_flit[400]
    DIRECTION INPUT ;
    USE SIGNAL ;
    SHAPE ABUTMENT ;
    PORT
      LAYER M5 ;
      RECT 358.008 777.408 358.032 777.600 ;
    END
  END tx_flit[400]
  PIN tx_flit[401]
    DIRECTION INPUT ;
    USE SIGNAL ;
    SHAPE ABUTMENT ;
    PORT
      LAYER M5 ;
      RECT 358.056 777.408 358.080 777.600 ;
    END
  END tx_flit[401]
  PIN tx_flit[402]
    DIRECTION INPUT ;
    USE SIGNAL ;
    SHAPE ABUTMENT ;
    PORT
      LAYER M5 ;
      RECT 358.104 777.408 358.128 777.600 ;
    END
  END tx_flit[402]
  PIN tx_flit[403]
    DIRECTION INPUT ;
    USE SIGNAL ;
    SHAPE ABUTMENT ;
    PORT
      LAYER M5 ;
      RECT 358.152 777.408 358.176 777.600 ;
    END
  END tx_flit[403]
  PIN tx_flit[404]
    DIRECTION INPUT ;
    USE SIGNAL ;
    SHAPE ABUTMENT ;
    PORT
      LAYER M5 ;
      RECT 358.200 777.408 358.224 777.600 ;
    END
  END tx_flit[404]
  PIN tx_flit[405]
    DIRECTION INPUT ;
    USE SIGNAL ;
    SHAPE ABUTMENT ;
    PORT
      LAYER M5 ;
      RECT 358.248 777.408 358.272 777.600 ;
    END
  END tx_flit[405]
  PIN tx_flit[406]
    DIRECTION INPUT ;
    USE SIGNAL ;
    SHAPE ABUTMENT ;
    PORT
      LAYER M5 ;
      RECT 358.296 777.408 358.320 777.600 ;
    END
  END tx_flit[406]
  PIN tx_flit[407]
    DIRECTION INPUT ;
    USE SIGNAL ;
    SHAPE ABUTMENT ;
    PORT
      LAYER M5 ;
      RECT 358.344 777.408 358.368 777.600 ;
    END
  END tx_flit[407]
  PIN tx_flit[408]
    DIRECTION INPUT ;
    USE SIGNAL ;
    SHAPE ABUTMENT ;
    PORT
      LAYER M5 ;
      RECT 358.392 777.408 358.416 777.600 ;
    END
  END tx_flit[408]
  PIN tx_flit[409]
    DIRECTION INPUT ;
    USE SIGNAL ;
    SHAPE ABUTMENT ;
    PORT
      LAYER M5 ;
      RECT 358.440 777.408 358.464 777.600 ;
    END
  END tx_flit[409]
  PIN tx_flit[410]
    DIRECTION INPUT ;
    USE SIGNAL ;
    SHAPE ABUTMENT ;
    PORT
      LAYER M5 ;
      RECT 358.488 777.408 358.512 777.600 ;
    END
  END tx_flit[410]
  PIN tx_flit[411]
    DIRECTION INPUT ;
    USE SIGNAL ;
    SHAPE ABUTMENT ;
    PORT
      LAYER M5 ;
      RECT 358.536 777.408 358.560 777.600 ;
    END
  END tx_flit[411]
  PIN tx_flit[412]
    DIRECTION INPUT ;
    USE SIGNAL ;
    SHAPE ABUTMENT ;
    PORT
      LAYER M5 ;
      RECT 358.584 777.408 358.608 777.600 ;
    END
  END tx_flit[412]
  PIN tx_flit[413]
    DIRECTION INPUT ;
    USE SIGNAL ;
    SHAPE ABUTMENT ;
    PORT
      LAYER M5 ;
      RECT 358.632 777.408 358.656 777.600 ;
    END
  END tx_flit[413]
  PIN tx_flit[414]
    DIRECTION INPUT ;
    USE SIGNAL ;
    SHAPE ABUTMENT ;
    PORT
      LAYER M5 ;
      RECT 358.680 777.408 358.704 777.600 ;
    END
  END tx_flit[414]
  PIN tx_flit[415]
    DIRECTION INPUT ;
    USE SIGNAL ;
    SHAPE ABUTMENT ;
    PORT
      LAYER M5 ;
      RECT 358.728 777.408 358.752 777.600 ;
    END
  END tx_flit[415]
  PIN tx_flit[416]
    DIRECTION INPUT ;
    USE SIGNAL ;
    SHAPE ABUTMENT ;
    PORT
      LAYER M5 ;
      RECT 358.776 777.408 358.800 777.600 ;
    END
  END tx_flit[416]
  PIN tx_flit[417]
    DIRECTION INPUT ;
    USE SIGNAL ;
    SHAPE ABUTMENT ;
    PORT
      LAYER M5 ;
      RECT 358.824 777.408 358.848 777.600 ;
    END
  END tx_flit[417]
  PIN tx_flit[418]
    DIRECTION INPUT ;
    USE SIGNAL ;
    SHAPE ABUTMENT ;
    PORT
      LAYER M5 ;
      RECT 358.872 777.408 358.896 777.600 ;
    END
  END tx_flit[418]
  PIN tx_flit[419]
    DIRECTION INPUT ;
    USE SIGNAL ;
    SHAPE ABUTMENT ;
    PORT
      LAYER M5 ;
      RECT 358.920 777.408 358.944 777.600 ;
    END
  END tx_flit[419]
  PIN tx_flit[420]
    DIRECTION INPUT ;
    USE SIGNAL ;
    SHAPE ABUTMENT ;
    PORT
      LAYER M5 ;
      RECT 358.968 777.408 358.992 777.600 ;
    END
  END tx_flit[420]
  PIN tx_flit[421]
    DIRECTION INPUT ;
    USE SIGNAL ;
    SHAPE ABUTMENT ;
    PORT
      LAYER M5 ;
      RECT 359.016 777.408 359.040 777.600 ;
    END
  END tx_flit[421]
  PIN tx_flit[422]
    DIRECTION INPUT ;
    USE SIGNAL ;
    SHAPE ABUTMENT ;
    PORT
      LAYER M5 ;
      RECT 359.064 777.408 359.088 777.600 ;
    END
  END tx_flit[422]
  PIN tx_flit[423]
    DIRECTION INPUT ;
    USE SIGNAL ;
    SHAPE ABUTMENT ;
    PORT
      LAYER M5 ;
      RECT 359.112 777.408 359.136 777.600 ;
    END
  END tx_flit[423]
  PIN tx_flit[424]
    DIRECTION INPUT ;
    USE SIGNAL ;
    SHAPE ABUTMENT ;
    PORT
      LAYER M5 ;
      RECT 359.160 777.408 359.184 777.600 ;
    END
  END tx_flit[424]
  PIN tx_flit[425]
    DIRECTION INPUT ;
    USE SIGNAL ;
    SHAPE ABUTMENT ;
    PORT
      LAYER M5 ;
      RECT 359.208 777.408 359.232 777.600 ;
    END
  END tx_flit[425]
  PIN tx_flit[426]
    DIRECTION INPUT ;
    USE SIGNAL ;
    SHAPE ABUTMENT ;
    PORT
      LAYER M5 ;
      RECT 359.256 777.408 359.280 777.600 ;
    END
  END tx_flit[426]
  PIN tx_flit[427]
    DIRECTION INPUT ;
    USE SIGNAL ;
    SHAPE ABUTMENT ;
    PORT
      LAYER M5 ;
      RECT 359.304 777.408 359.328 777.600 ;
    END
  END tx_flit[427]
  PIN tx_flit[428]
    DIRECTION INPUT ;
    USE SIGNAL ;
    SHAPE ABUTMENT ;
    PORT
      LAYER M5 ;
      RECT 359.352 777.408 359.376 777.600 ;
    END
  END tx_flit[428]
  PIN tx_flit[429]
    DIRECTION INPUT ;
    USE SIGNAL ;
    SHAPE ABUTMENT ;
    PORT
      LAYER M5 ;
      RECT 359.400 777.408 359.424 777.600 ;
    END
  END tx_flit[429]
  PIN tx_flit[430]
    DIRECTION INPUT ;
    USE SIGNAL ;
    SHAPE ABUTMENT ;
    PORT
      LAYER M5 ;
      RECT 359.448 777.408 359.472 777.600 ;
    END
  END tx_flit[430]
  PIN tx_flit[431]
    DIRECTION INPUT ;
    USE SIGNAL ;
    SHAPE ABUTMENT ;
    PORT
      LAYER M5 ;
      RECT 359.496 777.408 359.520 777.600 ;
    END
  END tx_flit[431]
  PIN tx_flit[432]
    DIRECTION INPUT ;
    USE SIGNAL ;
    SHAPE ABUTMENT ;
    PORT
      LAYER M5 ;
      RECT 359.544 777.408 359.568 777.600 ;
    END
  END tx_flit[432]
  PIN tx_flit[433]
    DIRECTION INPUT ;
    USE SIGNAL ;
    SHAPE ABUTMENT ;
    PORT
      LAYER M5 ;
      RECT 359.592 777.408 359.616 777.600 ;
    END
  END tx_flit[433]
  PIN tx_flit[434]
    DIRECTION INPUT ;
    USE SIGNAL ;
    SHAPE ABUTMENT ;
    PORT
      LAYER M5 ;
      RECT 359.640 777.408 359.664 777.600 ;
    END
  END tx_flit[434]
  PIN tx_flit[435]
    DIRECTION INPUT ;
    USE SIGNAL ;
    SHAPE ABUTMENT ;
    PORT
      LAYER M5 ;
      RECT 359.688 777.408 359.712 777.600 ;
    END
  END tx_flit[435]
  PIN tx_flit[436]
    DIRECTION INPUT ;
    USE SIGNAL ;
    SHAPE ABUTMENT ;
    PORT
      LAYER M5 ;
      RECT 359.736 777.408 359.760 777.600 ;
    END
  END tx_flit[436]
  PIN tx_flit[437]
    DIRECTION INPUT ;
    USE SIGNAL ;
    SHAPE ABUTMENT ;
    PORT
      LAYER M5 ;
      RECT 359.784 777.408 359.808 777.600 ;
    END
  END tx_flit[437]
  PIN tx_flit[438]
    DIRECTION INPUT ;
    USE SIGNAL ;
    SHAPE ABUTMENT ;
    PORT
      LAYER M5 ;
      RECT 359.832 777.408 359.856 777.600 ;
    END
  END tx_flit[438]
  PIN tx_flit[439]
    DIRECTION INPUT ;
    USE SIGNAL ;
    SHAPE ABUTMENT ;
    PORT
      LAYER M5 ;
      RECT 359.880 777.408 359.904 777.600 ;
    END
  END tx_flit[439]
  PIN tx_flit[440]
    DIRECTION INPUT ;
    USE SIGNAL ;
    SHAPE ABUTMENT ;
    PORT
      LAYER M5 ;
      RECT 359.928 777.408 359.952 777.600 ;
    END
  END tx_flit[440]
  PIN tx_flit[441]
    DIRECTION INPUT ;
    USE SIGNAL ;
    SHAPE ABUTMENT ;
    PORT
      LAYER M5 ;
      RECT 359.976 777.408 360.000 777.600 ;
    END
  END tx_flit[441]
  PIN tx_flit[442]
    DIRECTION INPUT ;
    USE SIGNAL ;
    SHAPE ABUTMENT ;
    PORT
      LAYER M5 ;
      RECT 360.024 777.408 360.048 777.600 ;
    END
  END tx_flit[442]
  PIN tx_flit[443]
    DIRECTION INPUT ;
    USE SIGNAL ;
    SHAPE ABUTMENT ;
    PORT
      LAYER M5 ;
      RECT 360.072 777.408 360.096 777.600 ;
    END
  END tx_flit[443]
  PIN tx_flit[444]
    DIRECTION INPUT ;
    USE SIGNAL ;
    SHAPE ABUTMENT ;
    PORT
      LAYER M5 ;
      RECT 360.120 777.408 360.144 777.600 ;
    END
  END tx_flit[444]
  PIN tx_flit[445]
    DIRECTION INPUT ;
    USE SIGNAL ;
    SHAPE ABUTMENT ;
    PORT
      LAYER M5 ;
      RECT 360.168 777.408 360.192 777.600 ;
    END
  END tx_flit[445]
  PIN tx_flit[446]
    DIRECTION INPUT ;
    USE SIGNAL ;
    SHAPE ABUTMENT ;
    PORT
      LAYER M5 ;
      RECT 360.216 777.408 360.240 777.600 ;
    END
  END tx_flit[446]
  PIN tx_flit[447]
    DIRECTION INPUT ;
    USE SIGNAL ;
    SHAPE ABUTMENT ;
    PORT
      LAYER M5 ;
      RECT 360.264 777.408 360.288 777.600 ;
    END
  END tx_flit[447]
  PIN tx_flit[448]
    DIRECTION INPUT ;
    USE SIGNAL ;
    SHAPE ABUTMENT ;
    PORT
      LAYER M5 ;
      RECT 360.312 777.408 360.336 777.600 ;
    END
  END tx_flit[448]
  PIN tx_flit[449]
    DIRECTION INPUT ;
    USE SIGNAL ;
    SHAPE ABUTMENT ;
    PORT
      LAYER M5 ;
      RECT 360.360 777.408 360.384 777.600 ;
    END
  END tx_flit[449]
  PIN tx_flit[450]
    DIRECTION INPUT ;
    USE SIGNAL ;
    SHAPE ABUTMENT ;
    PORT
      LAYER M5 ;
      RECT 360.408 777.408 360.432 777.600 ;
    END
  END tx_flit[450]
  PIN tx_flit[451]
    DIRECTION INPUT ;
    USE SIGNAL ;
    SHAPE ABUTMENT ;
    PORT
      LAYER M5 ;
      RECT 360.456 777.408 360.480 777.600 ;
    END
  END tx_flit[451]
  PIN tx_flit[452]
    DIRECTION INPUT ;
    USE SIGNAL ;
    SHAPE ABUTMENT ;
    PORT
      LAYER M5 ;
      RECT 360.504 777.408 360.528 777.600 ;
    END
  END tx_flit[452]
  PIN tx_flit[453]
    DIRECTION INPUT ;
    USE SIGNAL ;
    SHAPE ABUTMENT ;
    PORT
      LAYER M5 ;
      RECT 360.552 777.408 360.576 777.600 ;
    END
  END tx_flit[453]
  PIN tx_flit[454]
    DIRECTION INPUT ;
    USE SIGNAL ;
    SHAPE ABUTMENT ;
    PORT
      LAYER M5 ;
      RECT 360.600 777.408 360.624 777.600 ;
    END
  END tx_flit[454]
  PIN tx_flit[455]
    DIRECTION INPUT ;
    USE SIGNAL ;
    SHAPE ABUTMENT ;
    PORT
      LAYER M5 ;
      RECT 360.648 777.408 360.672 777.600 ;
    END
  END tx_flit[455]
  PIN tx_flit[456]
    DIRECTION INPUT ;
    USE SIGNAL ;
    SHAPE ABUTMENT ;
    PORT
      LAYER M5 ;
      RECT 360.696 777.408 360.720 777.600 ;
    END
  END tx_flit[456]
  PIN tx_flit[457]
    DIRECTION INPUT ;
    USE SIGNAL ;
    SHAPE ABUTMENT ;
    PORT
      LAYER M5 ;
      RECT 360.744 777.408 360.768 777.600 ;
    END
  END tx_flit[457]
  PIN tx_flit[458]
    DIRECTION INPUT ;
    USE SIGNAL ;
    SHAPE ABUTMENT ;
    PORT
      LAYER M5 ;
      RECT 360.792 777.408 360.816 777.600 ;
    END
  END tx_flit[458]
  PIN tx_flit[459]
    DIRECTION INPUT ;
    USE SIGNAL ;
    SHAPE ABUTMENT ;
    PORT
      LAYER M5 ;
      RECT 360.840 777.408 360.864 777.600 ;
    END
  END tx_flit[459]
  PIN tx_flit[460]
    DIRECTION INPUT ;
    USE SIGNAL ;
    SHAPE ABUTMENT ;
    PORT
      LAYER M5 ;
      RECT 360.888 777.408 360.912 777.600 ;
    END
  END tx_flit[460]
  PIN tx_flit[461]
    DIRECTION INPUT ;
    USE SIGNAL ;
    SHAPE ABUTMENT ;
    PORT
      LAYER M5 ;
      RECT 360.936 777.408 360.960 777.600 ;
    END
  END tx_flit[461]
  PIN tx_flit[462]
    DIRECTION INPUT ;
    USE SIGNAL ;
    SHAPE ABUTMENT ;
    PORT
      LAYER M5 ;
      RECT 360.984 777.408 361.008 777.600 ;
    END
  END tx_flit[462]
  PIN tx_flit[463]
    DIRECTION INPUT ;
    USE SIGNAL ;
    SHAPE ABUTMENT ;
    PORT
      LAYER M5 ;
      RECT 361.032 777.408 361.056 777.600 ;
    END
  END tx_flit[463]
  PIN tx_flit[464]
    DIRECTION INPUT ;
    USE SIGNAL ;
    SHAPE ABUTMENT ;
    PORT
      LAYER M5 ;
      RECT 361.080 777.408 361.104 777.600 ;
    END
  END tx_flit[464]
  PIN tx_flit[465]
    DIRECTION INPUT ;
    USE SIGNAL ;
    SHAPE ABUTMENT ;
    PORT
      LAYER M5 ;
      RECT 361.128 777.408 361.152 777.600 ;
    END
  END tx_flit[465]
  PIN tx_flit[466]
    DIRECTION INPUT ;
    USE SIGNAL ;
    SHAPE ABUTMENT ;
    PORT
      LAYER M5 ;
      RECT 361.176 777.408 361.200 777.600 ;
    END
  END tx_flit[466]
  PIN tx_flit[467]
    DIRECTION INPUT ;
    USE SIGNAL ;
    SHAPE ABUTMENT ;
    PORT
      LAYER M5 ;
      RECT 361.224 777.408 361.248 777.600 ;
    END
  END tx_flit[467]
  PIN tx_flit[468]
    DIRECTION INPUT ;
    USE SIGNAL ;
    SHAPE ABUTMENT ;
    PORT
      LAYER M5 ;
      RECT 361.272 777.408 361.296 777.600 ;
    END
  END tx_flit[468]
  PIN tx_flit[469]
    DIRECTION INPUT ;
    USE SIGNAL ;
    SHAPE ABUTMENT ;
    PORT
      LAYER M5 ;
      RECT 361.320 777.408 361.344 777.600 ;
    END
  END tx_flit[469]
  PIN tx_flit[470]
    DIRECTION INPUT ;
    USE SIGNAL ;
    SHAPE ABUTMENT ;
    PORT
      LAYER M5 ;
      RECT 361.368 777.408 361.392 777.600 ;
    END
  END tx_flit[470]
  PIN tx_flit[471]
    DIRECTION INPUT ;
    USE SIGNAL ;
    SHAPE ABUTMENT ;
    PORT
      LAYER M5 ;
      RECT 361.416 777.408 361.440 777.600 ;
    END
  END tx_flit[471]
  PIN tx_flit[472]
    DIRECTION INPUT ;
    USE SIGNAL ;
    SHAPE ABUTMENT ;
    PORT
      LAYER M5 ;
      RECT 361.464 777.408 361.488 777.600 ;
    END
  END tx_flit[472]
  PIN tx_flit[473]
    DIRECTION INPUT ;
    USE SIGNAL ;
    SHAPE ABUTMENT ;
    PORT
      LAYER M5 ;
      RECT 361.512 777.408 361.536 777.600 ;
    END
  END tx_flit[473]
  PIN tx_flit[474]
    DIRECTION INPUT ;
    USE SIGNAL ;
    SHAPE ABUTMENT ;
    PORT
      LAYER M5 ;
      RECT 361.560 777.408 361.584 777.600 ;
    END
  END tx_flit[474]
  PIN tx_flit[475]
    DIRECTION INPUT ;
    USE SIGNAL ;
    SHAPE ABUTMENT ;
    PORT
      LAYER M5 ;
      RECT 361.608 777.408 361.632 777.600 ;
    END
  END tx_flit[475]
  PIN tx_flit[476]
    DIRECTION INPUT ;
    USE SIGNAL ;
    SHAPE ABUTMENT ;
    PORT
      LAYER M5 ;
      RECT 361.656 777.408 361.680 777.600 ;
    END
  END tx_flit[476]
  PIN tx_flit[477]
    DIRECTION INPUT ;
    USE SIGNAL ;
    SHAPE ABUTMENT ;
    PORT
      LAYER M5 ;
      RECT 361.704 777.408 361.728 777.600 ;
    END
  END tx_flit[477]
  PIN tx_flit[478]
    DIRECTION INPUT ;
    USE SIGNAL ;
    SHAPE ABUTMENT ;
    PORT
      LAYER M5 ;
      RECT 361.752 777.408 361.776 777.600 ;
    END
  END tx_flit[478]
  PIN tx_flit[479]
    DIRECTION INPUT ;
    USE SIGNAL ;
    SHAPE ABUTMENT ;
    PORT
      LAYER M5 ;
      RECT 361.800 777.408 361.824 777.600 ;
    END
  END tx_flit[479]
  PIN tx_flit[480]
    DIRECTION INPUT ;
    USE SIGNAL ;
    SHAPE ABUTMENT ;
    PORT
      LAYER M5 ;
      RECT 361.848 777.408 361.872 777.600 ;
    END
  END tx_flit[480]
  PIN tx_flit[481]
    DIRECTION INPUT ;
    USE SIGNAL ;
    SHAPE ABUTMENT ;
    PORT
      LAYER M5 ;
      RECT 361.896 777.408 361.920 777.600 ;
    END
  END tx_flit[481]
  PIN tx_flit[482]
    DIRECTION INPUT ;
    USE SIGNAL ;
    SHAPE ABUTMENT ;
    PORT
      LAYER M5 ;
      RECT 361.944 777.408 361.968 777.600 ;
    END
  END tx_flit[482]
  PIN tx_flit[483]
    DIRECTION INPUT ;
    USE SIGNAL ;
    SHAPE ABUTMENT ;
    PORT
      LAYER M5 ;
      RECT 361.992 777.408 362.016 777.600 ;
    END
  END tx_flit[483]
  PIN tx_flit[484]
    DIRECTION INPUT ;
    USE SIGNAL ;
    SHAPE ABUTMENT ;
    PORT
      LAYER M5 ;
      RECT 362.040 777.408 362.064 777.600 ;
    END
  END tx_flit[484]
  PIN tx_flit[485]
    DIRECTION INPUT ;
    USE SIGNAL ;
    SHAPE ABUTMENT ;
    PORT
      LAYER M5 ;
      RECT 362.088 777.408 362.112 777.600 ;
    END
  END tx_flit[485]
  PIN tx_flit[486]
    DIRECTION INPUT ;
    USE SIGNAL ;
    SHAPE ABUTMENT ;
    PORT
      LAYER M5 ;
      RECT 362.136 777.408 362.160 777.600 ;
    END
  END tx_flit[486]
  PIN tx_flit[487]
    DIRECTION INPUT ;
    USE SIGNAL ;
    SHAPE ABUTMENT ;
    PORT
      LAYER M5 ;
      RECT 362.184 777.408 362.208 777.600 ;
    END
  END tx_flit[487]
  PIN tx_flit[488]
    DIRECTION INPUT ;
    USE SIGNAL ;
    SHAPE ABUTMENT ;
    PORT
      LAYER M5 ;
      RECT 362.232 777.408 362.256 777.600 ;
    END
  END tx_flit[488]
  PIN tx_flit[489]
    DIRECTION INPUT ;
    USE SIGNAL ;
    SHAPE ABUTMENT ;
    PORT
      LAYER M5 ;
      RECT 362.280 777.408 362.304 777.600 ;
    END
  END tx_flit[489]
  PIN tx_flit[490]
    DIRECTION INPUT ;
    USE SIGNAL ;
    SHAPE ABUTMENT ;
    PORT
      LAYER M5 ;
      RECT 362.328 777.408 362.352 777.600 ;
    END
  END tx_flit[490]
  PIN tx_flit[491]
    DIRECTION INPUT ;
    USE SIGNAL ;
    SHAPE ABUTMENT ;
    PORT
      LAYER M5 ;
      RECT 362.376 777.408 362.400 777.600 ;
    END
  END tx_flit[491]
  PIN tx_flit[492]
    DIRECTION INPUT ;
    USE SIGNAL ;
    SHAPE ABUTMENT ;
    PORT
      LAYER M5 ;
      RECT 362.424 777.408 362.448 777.600 ;
    END
  END tx_flit[492]
  PIN tx_flit[493]
    DIRECTION INPUT ;
    USE SIGNAL ;
    SHAPE ABUTMENT ;
    PORT
      LAYER M5 ;
      RECT 362.472 777.408 362.496 777.600 ;
    END
  END tx_flit[493]
  PIN tx_flit[494]
    DIRECTION INPUT ;
    USE SIGNAL ;
    SHAPE ABUTMENT ;
    PORT
      LAYER M5 ;
      RECT 362.520 777.408 362.544 777.600 ;
    END
  END tx_flit[494]
  PIN tx_flit[495]
    DIRECTION INPUT ;
    USE SIGNAL ;
    SHAPE ABUTMENT ;
    PORT
      LAYER M5 ;
      RECT 362.568 777.408 362.592 777.600 ;
    END
  END tx_flit[495]
  PIN tx_flit[496]
    DIRECTION INPUT ;
    USE SIGNAL ;
    SHAPE ABUTMENT ;
    PORT
      LAYER M5 ;
      RECT 362.616 777.408 362.640 777.600 ;
    END
  END tx_flit[496]
  PIN tx_flit[497]
    DIRECTION INPUT ;
    USE SIGNAL ;
    SHAPE ABUTMENT ;
    PORT
      LAYER M5 ;
      RECT 362.664 777.408 362.688 777.600 ;
    END
  END tx_flit[497]
  PIN tx_flit[498]
    DIRECTION INPUT ;
    USE SIGNAL ;
    SHAPE ABUTMENT ;
    PORT
      LAYER M5 ;
      RECT 362.712 777.408 362.736 777.600 ;
    END
  END tx_flit[498]
  PIN tx_flit[499]
    DIRECTION INPUT ;
    USE SIGNAL ;
    SHAPE ABUTMENT ;
    PORT
      LAYER M5 ;
      RECT 362.760 777.408 362.784 777.600 ;
    END
  END tx_flit[499]
  PIN tx_flit[500]
    DIRECTION INPUT ;
    USE SIGNAL ;
    SHAPE ABUTMENT ;
    PORT
      LAYER M5 ;
      RECT 362.808 777.408 362.832 777.600 ;
    END
  END tx_flit[500]
  PIN tx_flit[501]
    DIRECTION INPUT ;
    USE SIGNAL ;
    SHAPE ABUTMENT ;
    PORT
      LAYER M5 ;
      RECT 362.856 777.408 362.880 777.600 ;
    END
  END tx_flit[501]
  PIN tx_flit[502]
    DIRECTION INPUT ;
    USE SIGNAL ;
    SHAPE ABUTMENT ;
    PORT
      LAYER M5 ;
      RECT 362.904 777.408 362.928 777.600 ;
    END
  END tx_flit[502]
  PIN tx_flit[503]
    DIRECTION INPUT ;
    USE SIGNAL ;
    SHAPE ABUTMENT ;
    PORT
      LAYER M5 ;
      RECT 362.952 777.408 362.976 777.600 ;
    END
  END tx_flit[503]
  PIN tx_flit[504]
    DIRECTION INPUT ;
    USE SIGNAL ;
    SHAPE ABUTMENT ;
    PORT
      LAYER M5 ;
      RECT 363.000 777.408 363.024 777.600 ;
    END
  END tx_flit[504]
  PIN tx_flit[505]
    DIRECTION INPUT ;
    USE SIGNAL ;
    SHAPE ABUTMENT ;
    PORT
      LAYER M5 ;
      RECT 363.048 777.408 363.072 777.600 ;
    END
  END tx_flit[505]
  PIN tx_flit[506]
    DIRECTION INPUT ;
    USE SIGNAL ;
    SHAPE ABUTMENT ;
    PORT
      LAYER M5 ;
      RECT 363.096 777.408 363.120 777.600 ;
    END
  END tx_flit[506]
  PIN tx_flit[507]
    DIRECTION INPUT ;
    USE SIGNAL ;
    SHAPE ABUTMENT ;
    PORT
      LAYER M5 ;
      RECT 363.144 777.408 363.168 777.600 ;
    END
  END tx_flit[507]
  PIN tx_flit[508]
    DIRECTION INPUT ;
    USE SIGNAL ;
    SHAPE ABUTMENT ;
    PORT
      LAYER M5 ;
      RECT 363.192 777.408 363.216 777.600 ;
    END
  END tx_flit[508]
  PIN tx_flit[509]
    DIRECTION INPUT ;
    USE SIGNAL ;
    SHAPE ABUTMENT ;
    PORT
      LAYER M5 ;
      RECT 363.240 777.408 363.264 777.600 ;
    END
  END tx_flit[509]
  PIN tx_flit[510]
    DIRECTION INPUT ;
    USE SIGNAL ;
    SHAPE ABUTMENT ;
    PORT
      LAYER M5 ;
      RECT 363.288 777.408 363.312 777.600 ;
    END
  END tx_flit[510]
  PIN tx_flit[511]
    DIRECTION INPUT ;
    USE SIGNAL ;
    SHAPE ABUTMENT ;
    PORT
      LAYER M5 ;
      RECT 363.336 777.408 363.360 777.600 ;
    END
  END tx_flit[511]
  PIN tx_flit[512]
    DIRECTION INPUT ;
    USE SIGNAL ;
    SHAPE ABUTMENT ;
    PORT
      LAYER M5 ;
      RECT 363.384 777.408 363.408 777.600 ;
    END
  END tx_flit[512]
  PIN tx_flit[513]
    DIRECTION INPUT ;
    USE SIGNAL ;
    SHAPE ABUTMENT ;
    PORT
      LAYER M5 ;
      RECT 363.432 777.408 363.456 777.600 ;
    END
  END tx_flit[513]
  PIN tx_flit[514]
    DIRECTION INPUT ;
    USE SIGNAL ;
    SHAPE ABUTMENT ;
    PORT
      LAYER M5 ;
      RECT 363.480 777.408 363.504 777.600 ;
    END
  END tx_flit[514]
  PIN tx_flit[515]
    DIRECTION INPUT ;
    USE SIGNAL ;
    SHAPE ABUTMENT ;
    PORT
      LAYER M5 ;
      RECT 363.528 777.408 363.552 777.600 ;
    END
  END tx_flit[515]
  PIN tx_flit[516]
    DIRECTION INPUT ;
    USE SIGNAL ;
    SHAPE ABUTMENT ;
    PORT
      LAYER M5 ;
      RECT 363.576 777.408 363.600 777.600 ;
    END
  END tx_flit[516]
  PIN tx_flit[517]
    DIRECTION INPUT ;
    USE SIGNAL ;
    SHAPE ABUTMENT ;
    PORT
      LAYER M5 ;
      RECT 363.624 777.408 363.648 777.600 ;
    END
  END tx_flit[517]
  PIN tx_flit[518]
    DIRECTION INPUT ;
    USE SIGNAL ;
    SHAPE ABUTMENT ;
    PORT
      LAYER M5 ;
      RECT 363.672 777.408 363.696 777.600 ;
    END
  END tx_flit[518]
  PIN tx_flit[519]
    DIRECTION INPUT ;
    USE SIGNAL ;
    SHAPE ABUTMENT ;
    PORT
      LAYER M5 ;
      RECT 363.720 777.408 363.744 777.600 ;
    END
  END tx_flit[519]
  PIN tx_flit[520]
    DIRECTION INPUT ;
    USE SIGNAL ;
    SHAPE ABUTMENT ;
    PORT
      LAYER M5 ;
      RECT 363.768 777.408 363.792 777.600 ;
    END
  END tx_flit[520]
  PIN tx_flit[521]
    DIRECTION INPUT ;
    USE SIGNAL ;
    SHAPE ABUTMENT ;
    PORT
      LAYER M5 ;
      RECT 363.816 777.408 363.840 777.600 ;
    END
  END tx_flit[521]
  PIN tx_flit[522]
    DIRECTION INPUT ;
    USE SIGNAL ;
    SHAPE ABUTMENT ;
    PORT
      LAYER M5 ;
      RECT 363.864 777.408 363.888 777.600 ;
    END
  END tx_flit[522]
  PIN tx_flit[523]
    DIRECTION INPUT ;
    USE SIGNAL ;
    SHAPE ABUTMENT ;
    PORT
      LAYER M5 ;
      RECT 363.912 777.408 363.936 777.600 ;
    END
  END tx_flit[523]
  PIN tx_flit[524]
    DIRECTION INPUT ;
    USE SIGNAL ;
    SHAPE ABUTMENT ;
    PORT
      LAYER M5 ;
      RECT 363.960 777.408 363.984 777.600 ;
    END
  END tx_flit[524]
  PIN tx_flit[525]
    DIRECTION INPUT ;
    USE SIGNAL ;
    SHAPE ABUTMENT ;
    PORT
      LAYER M5 ;
      RECT 364.008 777.408 364.032 777.600 ;
    END
  END tx_flit[525]
  PIN tx_flit[526]
    DIRECTION INPUT ;
    USE SIGNAL ;
    SHAPE ABUTMENT ;
    PORT
      LAYER M5 ;
      RECT 364.056 777.408 364.080 777.600 ;
    END
  END tx_flit[526]
  PIN tx_flit[527]
    DIRECTION INPUT ;
    USE SIGNAL ;
    SHAPE ABUTMENT ;
    PORT
      LAYER M5 ;
      RECT 364.104 777.408 364.128 777.600 ;
    END
  END tx_flit[527]
  PIN tx_flit[528]
    DIRECTION INPUT ;
    USE SIGNAL ;
    SHAPE ABUTMENT ;
    PORT
      LAYER M5 ;
      RECT 364.152 777.408 364.176 777.600 ;
    END
  END tx_flit[528]
  PIN tx_flit[529]
    DIRECTION INPUT ;
    USE SIGNAL ;
    SHAPE ABUTMENT ;
    PORT
      LAYER M5 ;
      RECT 364.200 777.408 364.224 777.600 ;
    END
  END tx_flit[529]
  PIN tx_flit[530]
    DIRECTION INPUT ;
    USE SIGNAL ;
    SHAPE ABUTMENT ;
    PORT
      LAYER M5 ;
      RECT 364.248 777.408 364.272 777.600 ;
    END
  END tx_flit[530]
  PIN tx_flit[531]
    DIRECTION INPUT ;
    USE SIGNAL ;
    SHAPE ABUTMENT ;
    PORT
      LAYER M5 ;
      RECT 364.296 777.408 364.320 777.600 ;
    END
  END tx_flit[531]
  PIN tx_flit[532]
    DIRECTION INPUT ;
    USE SIGNAL ;
    SHAPE ABUTMENT ;
    PORT
      LAYER M5 ;
      RECT 364.344 777.408 364.368 777.600 ;
    END
  END tx_flit[532]
  PIN tx_flit[533]
    DIRECTION INPUT ;
    USE SIGNAL ;
    SHAPE ABUTMENT ;
    PORT
      LAYER M5 ;
      RECT 364.392 777.408 364.416 777.600 ;
    END
  END tx_flit[533]
  PIN tx_flit[534]
    DIRECTION INPUT ;
    USE SIGNAL ;
    SHAPE ABUTMENT ;
    PORT
      LAYER M5 ;
      RECT 364.440 777.408 364.464 777.600 ;
    END
  END tx_flit[534]
  PIN tx_flit[535]
    DIRECTION INPUT ;
    USE SIGNAL ;
    SHAPE ABUTMENT ;
    PORT
      LAYER M5 ;
      RECT 364.488 777.408 364.512 777.600 ;
    END
  END tx_flit[535]
  PIN tx_flit[536]
    DIRECTION INPUT ;
    USE SIGNAL ;
    SHAPE ABUTMENT ;
    PORT
      LAYER M5 ;
      RECT 364.536 777.408 364.560 777.600 ;
    END
  END tx_flit[536]
  PIN tx_flit[537]
    DIRECTION INPUT ;
    USE SIGNAL ;
    SHAPE ABUTMENT ;
    PORT
      LAYER M5 ;
      RECT 364.584 777.408 364.608 777.600 ;
    END
  END tx_flit[537]
  PIN tx_flit[538]
    DIRECTION INPUT ;
    USE SIGNAL ;
    SHAPE ABUTMENT ;
    PORT
      LAYER M5 ;
      RECT 364.632 777.408 364.656 777.600 ;
    END
  END tx_flit[538]
  PIN tx_flit[539]
    DIRECTION INPUT ;
    USE SIGNAL ;
    SHAPE ABUTMENT ;
    PORT
      LAYER M5 ;
      RECT 364.680 777.408 364.704 777.600 ;
    END
  END tx_flit[539]
  PIN tx_flit[540]
    DIRECTION INPUT ;
    USE SIGNAL ;
    SHAPE ABUTMENT ;
    PORT
      LAYER M5 ;
      RECT 364.728 777.408 364.752 777.600 ;
    END
  END tx_flit[540]
  PIN tx_flit[541]
    DIRECTION INPUT ;
    USE SIGNAL ;
    SHAPE ABUTMENT ;
    PORT
      LAYER M5 ;
      RECT 364.776 777.408 364.800 777.600 ;
    END
  END tx_flit[541]
  PIN tx_flit[542]
    DIRECTION INPUT ;
    USE SIGNAL ;
    SHAPE ABUTMENT ;
    PORT
      LAYER M5 ;
      RECT 364.824 777.408 364.848 777.600 ;
    END
  END tx_flit[542]
  PIN tx_flit[543]
    DIRECTION INPUT ;
    USE SIGNAL ;
    SHAPE ABUTMENT ;
    PORT
      LAYER M5 ;
      RECT 364.872 777.408 364.896 777.600 ;
    END
  END tx_flit[543]
  PIN tx_flit[544]
    DIRECTION INPUT ;
    USE SIGNAL ;
    SHAPE ABUTMENT ;
    PORT
      LAYER M5 ;
      RECT 364.920 777.408 364.944 777.600 ;
    END
  END tx_flit[544]
  PIN tx_flit[545]
    DIRECTION INPUT ;
    USE SIGNAL ;
    SHAPE ABUTMENT ;
    PORT
      LAYER M5 ;
      RECT 364.968 777.408 364.992 777.600 ;
    END
  END tx_flit[545]
  PIN tx_flit[546]
    DIRECTION INPUT ;
    USE SIGNAL ;
    SHAPE ABUTMENT ;
    PORT
      LAYER M5 ;
      RECT 365.016 777.408 365.040 777.600 ;
    END
  END tx_flit[546]
  PIN tx_flit[547]
    DIRECTION INPUT ;
    USE SIGNAL ;
    SHAPE ABUTMENT ;
    PORT
      LAYER M5 ;
      RECT 365.064 777.408 365.088 777.600 ;
    END
  END tx_flit[547]
  PIN tx_flit[548]
    DIRECTION INPUT ;
    USE SIGNAL ;
    SHAPE ABUTMENT ;
    PORT
      LAYER M5 ;
      RECT 365.112 777.408 365.136 777.600 ;
    END
  END tx_flit[548]
  PIN tx_flit[549]
    DIRECTION INPUT ;
    USE SIGNAL ;
    SHAPE ABUTMENT ;
    PORT
      LAYER M5 ;
      RECT 365.160 777.408 365.184 777.600 ;
    END
  END tx_flit[549]
  PIN tx_flit[550]
    DIRECTION INPUT ;
    USE SIGNAL ;
    SHAPE ABUTMENT ;
    PORT
      LAYER M5 ;
      RECT 365.208 777.408 365.232 777.600 ;
    END
  END tx_flit[550]
  PIN tx_flit[551]
    DIRECTION INPUT ;
    USE SIGNAL ;
    SHAPE ABUTMENT ;
    PORT
      LAYER M5 ;
      RECT 365.256 777.408 365.280 777.600 ;
    END
  END tx_flit[551]
  PIN tx_flit[552]
    DIRECTION INPUT ;
    USE SIGNAL ;
    SHAPE ABUTMENT ;
    PORT
      LAYER M5 ;
      RECT 365.304 777.408 365.328 777.600 ;
    END
  END tx_flit[552]
  PIN tx_flit[553]
    DIRECTION INPUT ;
    USE SIGNAL ;
    SHAPE ABUTMENT ;
    PORT
      LAYER M5 ;
      RECT 365.352 777.408 365.376 777.600 ;
    END
  END tx_flit[553]
  PIN tx_flit[554]
    DIRECTION INPUT ;
    USE SIGNAL ;
    SHAPE ABUTMENT ;
    PORT
      LAYER M5 ;
      RECT 365.400 777.408 365.424 777.600 ;
    END
  END tx_flit[554]
  PIN tx_flit[555]
    DIRECTION INPUT ;
    USE SIGNAL ;
    SHAPE ABUTMENT ;
    PORT
      LAYER M5 ;
      RECT 365.448 777.408 365.472 777.600 ;
    END
  END tx_flit[555]
  PIN tx_flit[556]
    DIRECTION INPUT ;
    USE SIGNAL ;
    SHAPE ABUTMENT ;
    PORT
      LAYER M5 ;
      RECT 365.496 777.408 365.520 777.600 ;
    END
  END tx_flit[556]
  PIN tx_flit[557]
    DIRECTION INPUT ;
    USE SIGNAL ;
    SHAPE ABUTMENT ;
    PORT
      LAYER M5 ;
      RECT 365.544 777.408 365.568 777.600 ;
    END
  END tx_flit[557]
  PIN tx_flit[558]
    DIRECTION INPUT ;
    USE SIGNAL ;
    SHAPE ABUTMENT ;
    PORT
      LAYER M5 ;
      RECT 365.592 777.408 365.616 777.600 ;
    END
  END tx_flit[558]
  PIN tx_flit[559]
    DIRECTION INPUT ;
    USE SIGNAL ;
    SHAPE ABUTMENT ;
    PORT
      LAYER M5 ;
      RECT 365.640 777.408 365.664 777.600 ;
    END
  END tx_flit[559]
  PIN tx_flit[560]
    DIRECTION INPUT ;
    USE SIGNAL ;
    SHAPE ABUTMENT ;
    PORT
      LAYER M5 ;
      RECT 365.688 777.408 365.712 777.600 ;
    END
  END tx_flit[560]
  PIN tx_flit[561]
    DIRECTION INPUT ;
    USE SIGNAL ;
    SHAPE ABUTMENT ;
    PORT
      LAYER M5 ;
      RECT 365.736 777.408 365.760 777.600 ;
    END
  END tx_flit[561]
  PIN tx_flit[562]
    DIRECTION INPUT ;
    USE SIGNAL ;
    SHAPE ABUTMENT ;
    PORT
      LAYER M5 ;
      RECT 365.784 777.408 365.808 777.600 ;
    END
  END tx_flit[562]
  PIN tx_flit[563]
    DIRECTION INPUT ;
    USE SIGNAL ;
    SHAPE ABUTMENT ;
    PORT
      LAYER M5 ;
      RECT 365.832 777.408 365.856 777.600 ;
    END
  END tx_flit[563]
  PIN tx_flit[564]
    DIRECTION INPUT ;
    USE SIGNAL ;
    SHAPE ABUTMENT ;
    PORT
      LAYER M5 ;
      RECT 365.880 777.408 365.904 777.600 ;
    END
  END tx_flit[564]
  PIN tx_flit[565]
    DIRECTION INPUT ;
    USE SIGNAL ;
    SHAPE ABUTMENT ;
    PORT
      LAYER M5 ;
      RECT 365.928 777.408 365.952 777.600 ;
    END
  END tx_flit[565]
  PIN tx_flit[566]
    DIRECTION INPUT ;
    USE SIGNAL ;
    SHAPE ABUTMENT ;
    PORT
      LAYER M5 ;
      RECT 365.976 777.408 366.000 777.600 ;
    END
  END tx_flit[566]
  PIN tx_flit[567]
    DIRECTION INPUT ;
    USE SIGNAL ;
    SHAPE ABUTMENT ;
    PORT
      LAYER M5 ;
      RECT 366.024 777.408 366.048 777.600 ;
    END
  END tx_flit[567]
  PIN tx_flit[568]
    DIRECTION INPUT ;
    USE SIGNAL ;
    SHAPE ABUTMENT ;
    PORT
      LAYER M5 ;
      RECT 366.072 777.408 366.096 777.600 ;
    END
  END tx_flit[568]
  PIN tx_flit[569]
    DIRECTION INPUT ;
    USE SIGNAL ;
    SHAPE ABUTMENT ;
    PORT
      LAYER M5 ;
      RECT 366.120 777.408 366.144 777.600 ;
    END
  END tx_flit[569]
  PIN tx_flit[570]
    DIRECTION INPUT ;
    USE SIGNAL ;
    SHAPE ABUTMENT ;
    PORT
      LAYER M5 ;
      RECT 366.168 777.408 366.192 777.600 ;
    END
  END tx_flit[570]
  PIN tx_flit[571]
    DIRECTION INPUT ;
    USE SIGNAL ;
    SHAPE ABUTMENT ;
    PORT
      LAYER M5 ;
      RECT 366.216 777.408 366.240 777.600 ;
    END
  END tx_flit[571]
  PIN tx_flit[572]
    DIRECTION INPUT ;
    USE SIGNAL ;
    SHAPE ABUTMENT ;
    PORT
      LAYER M5 ;
      RECT 366.264 777.408 366.288 777.600 ;
    END
  END tx_flit[572]
  PIN tx_flit[573]
    DIRECTION INPUT ;
    USE SIGNAL ;
    SHAPE ABUTMENT ;
    PORT
      LAYER M5 ;
      RECT 366.312 777.408 366.336 777.600 ;
    END
  END tx_flit[573]
  PIN tx_flit[574]
    DIRECTION INPUT ;
    USE SIGNAL ;
    SHAPE ABUTMENT ;
    PORT
      LAYER M5 ;
      RECT 366.360 777.408 366.384 777.600 ;
    END
  END tx_flit[574]
  PIN tx_flit[575]
    DIRECTION INPUT ;
    USE SIGNAL ;
    SHAPE ABUTMENT ;
    PORT
      LAYER M5 ;
      RECT 366.408 777.408 366.432 777.600 ;
    END
  END tx_flit[575]
  PIN tx_flit[576]
    DIRECTION INPUT ;
    USE SIGNAL ;
    SHAPE ABUTMENT ;
    PORT
      LAYER M5 ;
      RECT 366.456 777.408 366.480 777.600 ;
    END
  END tx_flit[576]
  PIN tx_flit[577]
    DIRECTION INPUT ;
    USE SIGNAL ;
    SHAPE ABUTMENT ;
    PORT
      LAYER M5 ;
      RECT 366.504 777.408 366.528 777.600 ;
    END
  END tx_flit[577]
  PIN tx_flit[578]
    DIRECTION INPUT ;
    USE SIGNAL ;
    SHAPE ABUTMENT ;
    PORT
      LAYER M5 ;
      RECT 366.552 777.408 366.576 777.600 ;
    END
  END tx_flit[578]
  PIN tx_flit[579]
    DIRECTION INPUT ;
    USE SIGNAL ;
    SHAPE ABUTMENT ;
    PORT
      LAYER M5 ;
      RECT 366.600 777.408 366.624 777.600 ;
    END
  END tx_flit[579]
  PIN tx_flit[580]
    DIRECTION INPUT ;
    USE SIGNAL ;
    SHAPE ABUTMENT ;
    PORT
      LAYER M5 ;
      RECT 366.648 777.408 366.672 777.600 ;
    END
  END tx_flit[580]
  PIN tx_flit[581]
    DIRECTION INPUT ;
    USE SIGNAL ;
    SHAPE ABUTMENT ;
    PORT
      LAYER M5 ;
      RECT 366.696 777.408 366.720 777.600 ;
    END
  END tx_flit[581]
  PIN tx_flit[582]
    DIRECTION INPUT ;
    USE SIGNAL ;
    SHAPE ABUTMENT ;
    PORT
      LAYER M5 ;
      RECT 366.744 777.408 366.768 777.600 ;
    END
  END tx_flit[582]
  PIN tx_flit[583]
    DIRECTION INPUT ;
    USE SIGNAL ;
    SHAPE ABUTMENT ;
    PORT
      LAYER M5 ;
      RECT 366.792 777.408 366.816 777.600 ;
    END
  END tx_flit[583]
  PIN tx_flit[584]
    DIRECTION INPUT ;
    USE SIGNAL ;
    SHAPE ABUTMENT ;
    PORT
      LAYER M5 ;
      RECT 366.840 777.408 366.864 777.600 ;
    END
  END tx_flit[584]
  PIN tx_flit[585]
    DIRECTION INPUT ;
    USE SIGNAL ;
    SHAPE ABUTMENT ;
    PORT
      LAYER M5 ;
      RECT 366.888 777.408 366.912 777.600 ;
    END
  END tx_flit[585]
  PIN tx_flit[586]
    DIRECTION INPUT ;
    USE SIGNAL ;
    SHAPE ABUTMENT ;
    PORT
      LAYER M5 ;
      RECT 366.936 777.408 366.960 777.600 ;
    END
  END tx_flit[586]
  PIN tx_flit[587]
    DIRECTION INPUT ;
    USE SIGNAL ;
    SHAPE ABUTMENT ;
    PORT
      LAYER M5 ;
      RECT 366.984 777.408 367.008 777.600 ;
    END
  END tx_flit[587]
  PIN tx_flit[588]
    DIRECTION INPUT ;
    USE SIGNAL ;
    SHAPE ABUTMENT ;
    PORT
      LAYER M5 ;
      RECT 367.032 777.408 367.056 777.600 ;
    END
  END tx_flit[588]
  PIN tx_flit[589]
    DIRECTION INPUT ;
    USE SIGNAL ;
    SHAPE ABUTMENT ;
    PORT
      LAYER M5 ;
      RECT 367.080 777.408 367.104 777.600 ;
    END
  END tx_flit[589]
  PIN tx_flit[590]
    DIRECTION INPUT ;
    USE SIGNAL ;
    SHAPE ABUTMENT ;
    PORT
      LAYER M5 ;
      RECT 367.128 777.408 367.152 777.600 ;
    END
  END tx_flit[590]
  PIN tx_flit[591]
    DIRECTION INPUT ;
    USE SIGNAL ;
    SHAPE ABUTMENT ;
    PORT
      LAYER M5 ;
      RECT 367.176 777.408 367.200 777.600 ;
    END
  END tx_flit[591]
  PIN tx_flit[592]
    DIRECTION INPUT ;
    USE SIGNAL ;
    SHAPE ABUTMENT ;
    PORT
      LAYER M5 ;
      RECT 367.224 777.408 367.248 777.600 ;
    END
  END tx_flit[592]
  PIN tx_flit[593]
    DIRECTION INPUT ;
    USE SIGNAL ;
    SHAPE ABUTMENT ;
    PORT
      LAYER M5 ;
      RECT 367.272 777.408 367.296 777.600 ;
    END
  END tx_flit[593]
  PIN tx_flit[594]
    DIRECTION INPUT ;
    USE SIGNAL ;
    SHAPE ABUTMENT ;
    PORT
      LAYER M5 ;
      RECT 367.320 777.408 367.344 777.600 ;
    END
  END tx_flit[594]
  PIN tx_flit[595]
    DIRECTION INPUT ;
    USE SIGNAL ;
    SHAPE ABUTMENT ;
    PORT
      LAYER M5 ;
      RECT 367.368 777.408 367.392 777.600 ;
    END
  END tx_flit[595]
  PIN tx_flit[596]
    DIRECTION INPUT ;
    USE SIGNAL ;
    SHAPE ABUTMENT ;
    PORT
      LAYER M5 ;
      RECT 367.416 777.408 367.440 777.600 ;
    END
  END tx_flit[596]
  PIN tx_flit[597]
    DIRECTION INPUT ;
    USE SIGNAL ;
    SHAPE ABUTMENT ;
    PORT
      LAYER M5 ;
      RECT 367.464 777.408 367.488 777.600 ;
    END
  END tx_flit[597]
  PIN tx_flit[598]
    DIRECTION INPUT ;
    USE SIGNAL ;
    SHAPE ABUTMENT ;
    PORT
      LAYER M5 ;
      RECT 367.512 777.408 367.536 777.600 ;
    END
  END tx_flit[598]
  PIN tx_flit[599]
    DIRECTION INPUT ;
    USE SIGNAL ;
    SHAPE ABUTMENT ;
    PORT
      LAYER M5 ;
      RECT 367.560 777.408 367.584 777.600 ;
    END
  END tx_flit[599]
  PIN tx_flit[600]
    DIRECTION INPUT ;
    USE SIGNAL ;
    SHAPE ABUTMENT ;
    PORT
      LAYER M5 ;
      RECT 367.608 777.408 367.632 777.600 ;
    END
  END tx_flit[600]
  PIN tx_flit[601]
    DIRECTION INPUT ;
    USE SIGNAL ;
    SHAPE ABUTMENT ;
    PORT
      LAYER M5 ;
      RECT 367.656 777.408 367.680 777.600 ;
    END
  END tx_flit[601]
  PIN tx_flit[602]
    DIRECTION INPUT ;
    USE SIGNAL ;
    SHAPE ABUTMENT ;
    PORT
      LAYER M5 ;
      RECT 367.704 777.408 367.728 777.600 ;
    END
  END tx_flit[602]
  PIN tx_flit[603]
    DIRECTION INPUT ;
    USE SIGNAL ;
    SHAPE ABUTMENT ;
    PORT
      LAYER M5 ;
      RECT 367.752 777.408 367.776 777.600 ;
    END
  END tx_flit[603]
  PIN tx_flit[604]
    DIRECTION INPUT ;
    USE SIGNAL ;
    SHAPE ABUTMENT ;
    PORT
      LAYER M5 ;
      RECT 367.800 777.408 367.824 777.600 ;
    END
  END tx_flit[604]
  PIN tx_flit[605]
    DIRECTION INPUT ;
    USE SIGNAL ;
    SHAPE ABUTMENT ;
    PORT
      LAYER M5 ;
      RECT 367.848 777.408 367.872 777.600 ;
    END
  END tx_flit[605]
  PIN tx_flit[606]
    DIRECTION INPUT ;
    USE SIGNAL ;
    SHAPE ABUTMENT ;
    PORT
      LAYER M5 ;
      RECT 367.896 777.408 367.920 777.600 ;
    END
  END tx_flit[606]
  PIN tx_flit[607]
    DIRECTION INPUT ;
    USE SIGNAL ;
    SHAPE ABUTMENT ;
    PORT
      LAYER M5 ;
      RECT 367.944 777.408 367.968 777.600 ;
    END
  END tx_flit[607]
  PIN tx_flit[608]
    DIRECTION INPUT ;
    USE SIGNAL ;
    SHAPE ABUTMENT ;
    PORT
      LAYER M5 ;
      RECT 367.992 777.408 368.016 777.600 ;
    END
  END tx_flit[608]
  PIN tx_flit[609]
    DIRECTION INPUT ;
    USE SIGNAL ;
    SHAPE ABUTMENT ;
    PORT
      LAYER M5 ;
      RECT 368.040 777.408 368.064 777.600 ;
    END
  END tx_flit[609]
  PIN tx_flit[610]
    DIRECTION INPUT ;
    USE SIGNAL ;
    SHAPE ABUTMENT ;
    PORT
      LAYER M5 ;
      RECT 368.088 777.408 368.112 777.600 ;
    END
  END tx_flit[610]
  PIN tx_flit[611]
    DIRECTION INPUT ;
    USE SIGNAL ;
    SHAPE ABUTMENT ;
    PORT
      LAYER M5 ;
      RECT 368.136 777.408 368.160 777.600 ;
    END
  END tx_flit[611]
  PIN tx_flit[612]
    DIRECTION INPUT ;
    USE SIGNAL ;
    SHAPE ABUTMENT ;
    PORT
      LAYER M5 ;
      RECT 368.184 777.408 368.208 777.600 ;
    END
  END tx_flit[612]
  PIN tx_flit[613]
    DIRECTION INPUT ;
    USE SIGNAL ;
    SHAPE ABUTMENT ;
    PORT
      LAYER M5 ;
      RECT 368.232 777.408 368.256 777.600 ;
    END
  END tx_flit[613]
  PIN tx_flit[614]
    DIRECTION INPUT ;
    USE SIGNAL ;
    SHAPE ABUTMENT ;
    PORT
      LAYER M5 ;
      RECT 368.280 777.408 368.304 777.600 ;
    END
  END tx_flit[614]
  PIN tx_flit[615]
    DIRECTION INPUT ;
    USE SIGNAL ;
    SHAPE ABUTMENT ;
    PORT
      LAYER M5 ;
      RECT 368.328 777.408 368.352 777.600 ;
    END
  END tx_flit[615]
  PIN tx_flit[616]
    DIRECTION INPUT ;
    USE SIGNAL ;
    SHAPE ABUTMENT ;
    PORT
      LAYER M5 ;
      RECT 368.376 777.408 368.400 777.600 ;
    END
  END tx_flit[616]
  PIN tx_flit[617]
    DIRECTION INPUT ;
    USE SIGNAL ;
    SHAPE ABUTMENT ;
    PORT
      LAYER M5 ;
      RECT 368.424 777.408 368.448 777.600 ;
    END
  END tx_flit[617]
  PIN tx_flit[618]
    DIRECTION INPUT ;
    USE SIGNAL ;
    SHAPE ABUTMENT ;
    PORT
      LAYER M5 ;
      RECT 368.472 777.408 368.496 777.600 ;
    END
  END tx_flit[618]
  PIN tx_flit[619]
    DIRECTION INPUT ;
    USE SIGNAL ;
    SHAPE ABUTMENT ;
    PORT
      LAYER M5 ;
      RECT 368.520 777.408 368.544 777.600 ;
    END
  END tx_flit[619]
  PIN tx_flit[620]
    DIRECTION INPUT ;
    USE SIGNAL ;
    SHAPE ABUTMENT ;
    PORT
      LAYER M5 ;
      RECT 368.568 777.408 368.592 777.600 ;
    END
  END tx_flit[620]
  PIN tx_flit[621]
    DIRECTION INPUT ;
    USE SIGNAL ;
    SHAPE ABUTMENT ;
    PORT
      LAYER M5 ;
      RECT 368.616 777.408 368.640 777.600 ;
    END
  END tx_flit[621]
  PIN tx_flit[622]
    DIRECTION INPUT ;
    USE SIGNAL ;
    SHAPE ABUTMENT ;
    PORT
      LAYER M5 ;
      RECT 368.664 777.408 368.688 777.600 ;
    END
  END tx_flit[622]
  PIN tx_flit[623]
    DIRECTION INPUT ;
    USE SIGNAL ;
    SHAPE ABUTMENT ;
    PORT
      LAYER M5 ;
      RECT 368.712 777.408 368.736 777.600 ;
    END
  END tx_flit[623]
  PIN tx_flit[624]
    DIRECTION INPUT ;
    USE SIGNAL ;
    SHAPE ABUTMENT ;
    PORT
      LAYER M5 ;
      RECT 368.760 777.408 368.784 777.600 ;
    END
  END tx_flit[624]
  PIN tx_flit[625]
    DIRECTION INPUT ;
    USE SIGNAL ;
    SHAPE ABUTMENT ;
    PORT
      LAYER M5 ;
      RECT 368.808 777.408 368.832 777.600 ;
    END
  END tx_flit[625]
  PIN tx_flit[626]
    DIRECTION INPUT ;
    USE SIGNAL ;
    SHAPE ABUTMENT ;
    PORT
      LAYER M5 ;
      RECT 368.856 777.408 368.880 777.600 ;
    END
  END tx_flit[626]
  PIN tx_flit[627]
    DIRECTION INPUT ;
    USE SIGNAL ;
    SHAPE ABUTMENT ;
    PORT
      LAYER M5 ;
      RECT 368.904 777.408 368.928 777.600 ;
    END
  END tx_flit[627]
  PIN tx_flit[628]
    DIRECTION INPUT ;
    USE SIGNAL ;
    SHAPE ABUTMENT ;
    PORT
      LAYER M5 ;
      RECT 368.952 777.408 368.976 777.600 ;
    END
  END tx_flit[628]
  PIN tx_flit[629]
    DIRECTION INPUT ;
    USE SIGNAL ;
    SHAPE ABUTMENT ;
    PORT
      LAYER M5 ;
      RECT 369.000 777.408 369.024 777.600 ;
    END
  END tx_flit[629]
  PIN tx_flit[630]
    DIRECTION INPUT ;
    USE SIGNAL ;
    SHAPE ABUTMENT ;
    PORT
      LAYER M5 ;
      RECT 369.048 777.408 369.072 777.600 ;
    END
  END tx_flit[630]
  PIN tx_flit[631]
    DIRECTION INPUT ;
    USE SIGNAL ;
    SHAPE ABUTMENT ;
    PORT
      LAYER M5 ;
      RECT 369.096 777.408 369.120 777.600 ;
    END
  END tx_flit[631]
  PIN tx_flit[632]
    DIRECTION INPUT ;
    USE SIGNAL ;
    SHAPE ABUTMENT ;
    PORT
      LAYER M5 ;
      RECT 369.144 777.408 369.168 777.600 ;
    END
  END tx_flit[632]
  PIN tx_flit[633]
    DIRECTION INPUT ;
    USE SIGNAL ;
    SHAPE ABUTMENT ;
    PORT
      LAYER M5 ;
      RECT 369.192 777.408 369.216 777.600 ;
    END
  END tx_flit[633]
  PIN tx_flit[634]
    DIRECTION INPUT ;
    USE SIGNAL ;
    SHAPE ABUTMENT ;
    PORT
      LAYER M5 ;
      RECT 369.240 777.408 369.264 777.600 ;
    END
  END tx_flit[634]
  PIN tx_flit[635]
    DIRECTION INPUT ;
    USE SIGNAL ;
    SHAPE ABUTMENT ;
    PORT
      LAYER M5 ;
      RECT 369.288 777.408 369.312 777.600 ;
    END
  END tx_flit[635]
  PIN tx_flit[636]
    DIRECTION INPUT ;
    USE SIGNAL ;
    SHAPE ABUTMENT ;
    PORT
      LAYER M5 ;
      RECT 369.336 777.408 369.360 777.600 ;
    END
  END tx_flit[636]
  PIN tx_flit[637]
    DIRECTION INPUT ;
    USE SIGNAL ;
    SHAPE ABUTMENT ;
    PORT
      LAYER M5 ;
      RECT 369.384 777.408 369.408 777.600 ;
    END
  END tx_flit[637]
  PIN tx_flit[638]
    DIRECTION INPUT ;
    USE SIGNAL ;
    SHAPE ABUTMENT ;
    PORT
      LAYER M5 ;
      RECT 369.432 777.408 369.456 777.600 ;
    END
  END tx_flit[638]
  PIN tx_flit[639]
    DIRECTION INPUT ;
    USE SIGNAL ;
    SHAPE ABUTMENT ;
    PORT
      LAYER M5 ;
      RECT 369.480 777.408 369.504 777.600 ;
    END
  END tx_flit[639]
  PIN tx_flit[640]
    DIRECTION INPUT ;
    USE SIGNAL ;
    SHAPE ABUTMENT ;
    PORT
      LAYER M5 ;
      RECT 369.528 777.408 369.552 777.600 ;
    END
  END tx_flit[640]
  PIN tx_flit[641]
    DIRECTION INPUT ;
    USE SIGNAL ;
    SHAPE ABUTMENT ;
    PORT
      LAYER M5 ;
      RECT 369.576 777.408 369.600 777.600 ;
    END
  END tx_flit[641]
  PIN tx_flit[642]
    DIRECTION INPUT ;
    USE SIGNAL ;
    SHAPE ABUTMENT ;
    PORT
      LAYER M5 ;
      RECT 369.624 777.408 369.648 777.600 ;
    END
  END tx_flit[642]
  PIN tx_flit[643]
    DIRECTION INPUT ;
    USE SIGNAL ;
    SHAPE ABUTMENT ;
    PORT
      LAYER M5 ;
      RECT 369.672 777.408 369.696 777.600 ;
    END
  END tx_flit[643]
  PIN tx_flit[644]
    DIRECTION INPUT ;
    USE SIGNAL ;
    SHAPE ABUTMENT ;
    PORT
      LAYER M5 ;
      RECT 369.720 777.408 369.744 777.600 ;
    END
  END tx_flit[644]
  PIN tx_flit[645]
    DIRECTION INPUT ;
    USE SIGNAL ;
    SHAPE ABUTMENT ;
    PORT
      LAYER M5 ;
      RECT 369.768 777.408 369.792 777.600 ;
    END
  END tx_flit[645]
  PIN tx_flit[646]
    DIRECTION INPUT ;
    USE SIGNAL ;
    SHAPE ABUTMENT ;
    PORT
      LAYER M5 ;
      RECT 369.816 777.408 369.840 777.600 ;
    END
  END tx_flit[646]
  PIN tx_flit[647]
    DIRECTION INPUT ;
    USE SIGNAL ;
    SHAPE ABUTMENT ;
    PORT
      LAYER M5 ;
      RECT 369.864 777.408 369.888 777.600 ;
    END
  END tx_flit[647]
  PIN tx_flit[648]
    DIRECTION INPUT ;
    USE SIGNAL ;
    SHAPE ABUTMENT ;
    PORT
      LAYER M5 ;
      RECT 369.912 777.408 369.936 777.600 ;
    END
  END tx_flit[648]
  PIN tx_flit[649]
    DIRECTION INPUT ;
    USE SIGNAL ;
    SHAPE ABUTMENT ;
    PORT
      LAYER M5 ;
      RECT 369.960 777.408 369.984 777.600 ;
    END
  END tx_flit[649]
  PIN tx_flit[650]
    DIRECTION INPUT ;
    USE SIGNAL ;
    SHAPE ABUTMENT ;
    PORT
      LAYER M5 ;
      RECT 370.008 777.408 370.032 777.600 ;
    END
  END tx_flit[650]
  PIN tx_flit[651]
    DIRECTION INPUT ;
    USE SIGNAL ;
    SHAPE ABUTMENT ;
    PORT
      LAYER M5 ;
      RECT 370.056 777.408 370.080 777.600 ;
    END
  END tx_flit[651]
  PIN tx_flit[652]
    DIRECTION INPUT ;
    USE SIGNAL ;
    SHAPE ABUTMENT ;
    PORT
      LAYER M5 ;
      RECT 370.104 777.408 370.128 777.600 ;
    END
  END tx_flit[652]
  PIN tx_flit[653]
    DIRECTION INPUT ;
    USE SIGNAL ;
    SHAPE ABUTMENT ;
    PORT
      LAYER M5 ;
      RECT 370.152 777.408 370.176 777.600 ;
    END
  END tx_flit[653]
  PIN tx_flit[654]
    DIRECTION INPUT ;
    USE SIGNAL ;
    SHAPE ABUTMENT ;
    PORT
      LAYER M5 ;
      RECT 370.200 777.408 370.224 777.600 ;
    END
  END tx_flit[654]
  PIN tx_flit[655]
    DIRECTION INPUT ;
    USE SIGNAL ;
    SHAPE ABUTMENT ;
    PORT
      LAYER M5 ;
      RECT 370.248 777.408 370.272 777.600 ;
    END
  END tx_flit[655]
  PIN tx_flit[656]
    DIRECTION INPUT ;
    USE SIGNAL ;
    SHAPE ABUTMENT ;
    PORT
      LAYER M5 ;
      RECT 370.296 777.408 370.320 777.600 ;
    END
  END tx_flit[656]
  PIN tx_flit[657]
    DIRECTION INPUT ;
    USE SIGNAL ;
    SHAPE ABUTMENT ;
    PORT
      LAYER M5 ;
      RECT 370.344 777.408 370.368 777.600 ;
    END
  END tx_flit[657]
  PIN tx_flit[658]
    DIRECTION INPUT ;
    USE SIGNAL ;
    SHAPE ABUTMENT ;
    PORT
      LAYER M5 ;
      RECT 370.392 777.408 370.416 777.600 ;
    END
  END tx_flit[658]
  PIN tx_flit[659]
    DIRECTION INPUT ;
    USE SIGNAL ;
    SHAPE ABUTMENT ;
    PORT
      LAYER M5 ;
      RECT 370.440 777.408 370.464 777.600 ;
    END
  END tx_flit[659]
  PIN tx_flit[660]
    DIRECTION INPUT ;
    USE SIGNAL ;
    SHAPE ABUTMENT ;
    PORT
      LAYER M5 ;
      RECT 370.488 777.408 370.512 777.600 ;
    END
  END tx_flit[660]
  PIN tx_flit[661]
    DIRECTION INPUT ;
    USE SIGNAL ;
    SHAPE ABUTMENT ;
    PORT
      LAYER M5 ;
      RECT 370.536 777.408 370.560 777.600 ;
    END
  END tx_flit[661]
  PIN tx_flit[662]
    DIRECTION INPUT ;
    USE SIGNAL ;
    SHAPE ABUTMENT ;
    PORT
      LAYER M5 ;
      RECT 370.584 777.408 370.608 777.600 ;
    END
  END tx_flit[662]
  PIN tx_flit[663]
    DIRECTION INPUT ;
    USE SIGNAL ;
    SHAPE ABUTMENT ;
    PORT
      LAYER M5 ;
      RECT 370.632 777.408 370.656 777.600 ;
    END
  END tx_flit[663]
  PIN tx_flit[664]
    DIRECTION INPUT ;
    USE SIGNAL ;
    SHAPE ABUTMENT ;
    PORT
      LAYER M5 ;
      RECT 370.680 777.408 370.704 777.600 ;
    END
  END tx_flit[664]
  PIN tx_flit[665]
    DIRECTION INPUT ;
    USE SIGNAL ;
    SHAPE ABUTMENT ;
    PORT
      LAYER M5 ;
      RECT 370.728 777.408 370.752 777.600 ;
    END
  END tx_flit[665]
  PIN tx_flit[666]
    DIRECTION INPUT ;
    USE SIGNAL ;
    SHAPE ABUTMENT ;
    PORT
      LAYER M5 ;
      RECT 370.776 777.408 370.800 777.600 ;
    END
  END tx_flit[666]
  PIN tx_flit[667]
    DIRECTION INPUT ;
    USE SIGNAL ;
    SHAPE ABUTMENT ;
    PORT
      LAYER M5 ;
      RECT 370.824 777.408 370.848 777.600 ;
    END
  END tx_flit[667]
  PIN tx_flit[668]
    DIRECTION INPUT ;
    USE SIGNAL ;
    SHAPE ABUTMENT ;
    PORT
      LAYER M5 ;
      RECT 370.872 777.408 370.896 777.600 ;
    END
  END tx_flit[668]
  PIN tx_flit[669]
    DIRECTION INPUT ;
    USE SIGNAL ;
    SHAPE ABUTMENT ;
    PORT
      LAYER M5 ;
      RECT 370.920 777.408 370.944 777.600 ;
    END
  END tx_flit[669]
  PIN tx_flit[670]
    DIRECTION INPUT ;
    USE SIGNAL ;
    SHAPE ABUTMENT ;
    PORT
      LAYER M5 ;
      RECT 370.968 777.408 370.992 777.600 ;
    END
  END tx_flit[670]
  PIN tx_flit[671]
    DIRECTION INPUT ;
    USE SIGNAL ;
    SHAPE ABUTMENT ;
    PORT
      LAYER M5 ;
      RECT 371.016 777.408 371.040 777.600 ;
    END
  END tx_flit[671]
  PIN tx_flit[672]
    DIRECTION INPUT ;
    USE SIGNAL ;
    SHAPE ABUTMENT ;
    PORT
      LAYER M5 ;
      RECT 371.064 777.408 371.088 777.600 ;
    END
  END tx_flit[672]
  PIN tx_flit[673]
    DIRECTION INPUT ;
    USE SIGNAL ;
    SHAPE ABUTMENT ;
    PORT
      LAYER M5 ;
      RECT 371.112 777.408 371.136 777.600 ;
    END
  END tx_flit[673]
  PIN tx_flit[674]
    DIRECTION INPUT ;
    USE SIGNAL ;
    SHAPE ABUTMENT ;
    PORT
      LAYER M5 ;
      RECT 371.160 777.408 371.184 777.600 ;
    END
  END tx_flit[674]
  PIN tx_flit[675]
    DIRECTION INPUT ;
    USE SIGNAL ;
    SHAPE ABUTMENT ;
    PORT
      LAYER M5 ;
      RECT 371.208 777.408 371.232 777.600 ;
    END
  END tx_flit[675]
  PIN tx_flit[676]
    DIRECTION INPUT ;
    USE SIGNAL ;
    SHAPE ABUTMENT ;
    PORT
      LAYER M5 ;
      RECT 371.256 777.408 371.280 777.600 ;
    END
  END tx_flit[676]
  PIN tx_flit[677]
    DIRECTION INPUT ;
    USE SIGNAL ;
    SHAPE ABUTMENT ;
    PORT
      LAYER M5 ;
      RECT 371.304 777.408 371.328 777.600 ;
    END
  END tx_flit[677]
  PIN tx_flit[678]
    DIRECTION INPUT ;
    USE SIGNAL ;
    SHAPE ABUTMENT ;
    PORT
      LAYER M5 ;
      RECT 371.352 777.408 371.376 777.600 ;
    END
  END tx_flit[678]
  PIN tx_flit[679]
    DIRECTION INPUT ;
    USE SIGNAL ;
    SHAPE ABUTMENT ;
    PORT
      LAYER M5 ;
      RECT 371.400 777.408 371.424 777.600 ;
    END
  END tx_flit[679]
  PIN tx_flit[680]
    DIRECTION INPUT ;
    USE SIGNAL ;
    SHAPE ABUTMENT ;
    PORT
      LAYER M5 ;
      RECT 371.448 777.408 371.472 777.600 ;
    END
  END tx_flit[680]
  PIN tx_flit[681]
    DIRECTION INPUT ;
    USE SIGNAL ;
    SHAPE ABUTMENT ;
    PORT
      LAYER M5 ;
      RECT 371.496 777.408 371.520 777.600 ;
    END
  END tx_flit[681]
  PIN tx_flit[682]
    DIRECTION INPUT ;
    USE SIGNAL ;
    SHAPE ABUTMENT ;
    PORT
      LAYER M5 ;
      RECT 371.544 777.408 371.568 777.600 ;
    END
  END tx_flit[682]
  PIN tx_flit[683]
    DIRECTION INPUT ;
    USE SIGNAL ;
    SHAPE ABUTMENT ;
    PORT
      LAYER M5 ;
      RECT 371.592 777.408 371.616 777.600 ;
    END
  END tx_flit[683]
  PIN tx_flit[684]
    DIRECTION INPUT ;
    USE SIGNAL ;
    SHAPE ABUTMENT ;
    PORT
      LAYER M5 ;
      RECT 371.640 777.408 371.664 777.600 ;
    END
  END tx_flit[684]
  PIN tx_flit[685]
    DIRECTION INPUT ;
    USE SIGNAL ;
    SHAPE ABUTMENT ;
    PORT
      LAYER M5 ;
      RECT 371.688 777.408 371.712 777.600 ;
    END
  END tx_flit[685]
  PIN tx_flit[686]
    DIRECTION INPUT ;
    USE SIGNAL ;
    SHAPE ABUTMENT ;
    PORT
      LAYER M5 ;
      RECT 371.736 777.408 371.760 777.600 ;
    END
  END tx_flit[686]
  PIN tx_flit[687]
    DIRECTION INPUT ;
    USE SIGNAL ;
    SHAPE ABUTMENT ;
    PORT
      LAYER M5 ;
      RECT 371.784 777.408 371.808 777.600 ;
    END
  END tx_flit[687]
  PIN tx_flit[688]
    DIRECTION INPUT ;
    USE SIGNAL ;
    SHAPE ABUTMENT ;
    PORT
      LAYER M5 ;
      RECT 371.832 777.408 371.856 777.600 ;
    END
  END tx_flit[688]
  PIN tx_flit[689]
    DIRECTION INPUT ;
    USE SIGNAL ;
    SHAPE ABUTMENT ;
    PORT
      LAYER M5 ;
      RECT 371.880 777.408 371.904 777.600 ;
    END
  END tx_flit[689]
  PIN tx_flit[690]
    DIRECTION INPUT ;
    USE SIGNAL ;
    SHAPE ABUTMENT ;
    PORT
      LAYER M5 ;
      RECT 371.928 777.408 371.952 777.600 ;
    END
  END tx_flit[690]
  PIN tx_flit[691]
    DIRECTION INPUT ;
    USE SIGNAL ;
    SHAPE ABUTMENT ;
    PORT
      LAYER M5 ;
      RECT 371.976 777.408 372.000 777.600 ;
    END
  END tx_flit[691]
  PIN tx_flit[692]
    DIRECTION INPUT ;
    USE SIGNAL ;
    SHAPE ABUTMENT ;
    PORT
      LAYER M5 ;
      RECT 372.024 777.408 372.048 777.600 ;
    END
  END tx_flit[692]
  PIN tx_flit[693]
    DIRECTION INPUT ;
    USE SIGNAL ;
    SHAPE ABUTMENT ;
    PORT
      LAYER M5 ;
      RECT 372.072 777.408 372.096 777.600 ;
    END
  END tx_flit[693]
  PIN tx_flit[694]
    DIRECTION INPUT ;
    USE SIGNAL ;
    SHAPE ABUTMENT ;
    PORT
      LAYER M5 ;
      RECT 372.120 777.408 372.144 777.600 ;
    END
  END tx_flit[694]
  PIN tx_flit[695]
    DIRECTION INPUT ;
    USE SIGNAL ;
    SHAPE ABUTMENT ;
    PORT
      LAYER M5 ;
      RECT 372.168 777.408 372.192 777.600 ;
    END
  END tx_flit[695]
  PIN tx_flit[696]
    DIRECTION INPUT ;
    USE SIGNAL ;
    SHAPE ABUTMENT ;
    PORT
      LAYER M5 ;
      RECT 372.216 777.408 372.240 777.600 ;
    END
  END tx_flit[696]
  PIN tx_flit[697]
    DIRECTION INPUT ;
    USE SIGNAL ;
    SHAPE ABUTMENT ;
    PORT
      LAYER M5 ;
      RECT 372.264 777.408 372.288 777.600 ;
    END
  END tx_flit[697]
  PIN tx_flit[698]
    DIRECTION INPUT ;
    USE SIGNAL ;
    SHAPE ABUTMENT ;
    PORT
      LAYER M5 ;
      RECT 372.312 777.408 372.336 777.600 ;
    END
  END tx_flit[698]
  PIN tx_flit[699]
    DIRECTION INPUT ;
    USE SIGNAL ;
    SHAPE ABUTMENT ;
    PORT
      LAYER M5 ;
      RECT 372.360 777.408 372.384 777.600 ;
    END
  END tx_flit[699]
  PIN tx_flit[700]
    DIRECTION INPUT ;
    USE SIGNAL ;
    SHAPE ABUTMENT ;
    PORT
      LAYER M5 ;
      RECT 372.408 777.408 372.432 777.600 ;
    END
  END tx_flit[700]
  PIN tx_flit[701]
    DIRECTION INPUT ;
    USE SIGNAL ;
    SHAPE ABUTMENT ;
    PORT
      LAYER M5 ;
      RECT 372.456 777.408 372.480 777.600 ;
    END
  END tx_flit[701]
  PIN tx_flit[702]
    DIRECTION INPUT ;
    USE SIGNAL ;
    SHAPE ABUTMENT ;
    PORT
      LAYER M5 ;
      RECT 372.504 777.408 372.528 777.600 ;
    END
  END tx_flit[702]
  PIN tx_flit[703]
    DIRECTION INPUT ;
    USE SIGNAL ;
    SHAPE ABUTMENT ;
    PORT
      LAYER M5 ;
      RECT 372.552 777.408 372.576 777.600 ;
    END
  END tx_flit[703]
  PIN tx_flit[704]
    DIRECTION INPUT ;
    USE SIGNAL ;
    SHAPE ABUTMENT ;
    PORT
      LAYER M5 ;
      RECT 372.600 777.408 372.624 777.600 ;
    END
  END tx_flit[704]
  PIN tx_flit[705]
    DIRECTION INPUT ;
    USE SIGNAL ;
    SHAPE ABUTMENT ;
    PORT
      LAYER M5 ;
      RECT 372.648 777.408 372.672 777.600 ;
    END
  END tx_flit[705]
  PIN tx_flit[706]
    DIRECTION INPUT ;
    USE SIGNAL ;
    SHAPE ABUTMENT ;
    PORT
      LAYER M5 ;
      RECT 372.696 777.408 372.720 777.600 ;
    END
  END tx_flit[706]
  PIN tx_flit[707]
    DIRECTION INPUT ;
    USE SIGNAL ;
    SHAPE ABUTMENT ;
    PORT
      LAYER M5 ;
      RECT 372.744 777.408 372.768 777.600 ;
    END
  END tx_flit[707]
  PIN tx_flit[708]
    DIRECTION INPUT ;
    USE SIGNAL ;
    SHAPE ABUTMENT ;
    PORT
      LAYER M5 ;
      RECT 372.792 777.408 372.816 777.600 ;
    END
  END tx_flit[708]
  PIN tx_flit[709]
    DIRECTION INPUT ;
    USE SIGNAL ;
    SHAPE ABUTMENT ;
    PORT
      LAYER M5 ;
      RECT 372.840 777.408 372.864 777.600 ;
    END
  END tx_flit[709]
  PIN tx_flit[710]
    DIRECTION INPUT ;
    USE SIGNAL ;
    SHAPE ABUTMENT ;
    PORT
      LAYER M5 ;
      RECT 372.888 777.408 372.912 777.600 ;
    END
  END tx_flit[710]
  PIN tx_flit[711]
    DIRECTION INPUT ;
    USE SIGNAL ;
    SHAPE ABUTMENT ;
    PORT
      LAYER M5 ;
      RECT 372.936 777.408 372.960 777.600 ;
    END
  END tx_flit[711]
  PIN tx_flit[712]
    DIRECTION INPUT ;
    USE SIGNAL ;
    SHAPE ABUTMENT ;
    PORT
      LAYER M5 ;
      RECT 372.984 777.408 373.008 777.600 ;
    END
  END tx_flit[712]
  PIN tx_flit[713]
    DIRECTION INPUT ;
    USE SIGNAL ;
    SHAPE ABUTMENT ;
    PORT
      LAYER M5 ;
      RECT 373.032 777.408 373.056 777.600 ;
    END
  END tx_flit[713]
  PIN tx_flit[714]
    DIRECTION INPUT ;
    USE SIGNAL ;
    SHAPE ABUTMENT ;
    PORT
      LAYER M5 ;
      RECT 373.080 777.408 373.104 777.600 ;
    END
  END tx_flit[714]
  PIN tx_flit[715]
    DIRECTION INPUT ;
    USE SIGNAL ;
    SHAPE ABUTMENT ;
    PORT
      LAYER M5 ;
      RECT 373.128 777.408 373.152 777.600 ;
    END
  END tx_flit[715]
  PIN tx_flit[716]
    DIRECTION INPUT ;
    USE SIGNAL ;
    SHAPE ABUTMENT ;
    PORT
      LAYER M5 ;
      RECT 373.176 777.408 373.200 777.600 ;
    END
  END tx_flit[716]
  PIN tx_flit[717]
    DIRECTION INPUT ;
    USE SIGNAL ;
    SHAPE ABUTMENT ;
    PORT
      LAYER M5 ;
      RECT 373.224 777.408 373.248 777.600 ;
    END
  END tx_flit[717]
  PIN tx_flit[718]
    DIRECTION INPUT ;
    USE SIGNAL ;
    SHAPE ABUTMENT ;
    PORT
      LAYER M5 ;
      RECT 373.272 777.408 373.296 777.600 ;
    END
  END tx_flit[718]
  PIN tx_flit[719]
    DIRECTION INPUT ;
    USE SIGNAL ;
    SHAPE ABUTMENT ;
    PORT
      LAYER M5 ;
      RECT 373.320 777.408 373.344 777.600 ;
    END
  END tx_flit[719]
  PIN tx_flit[720]
    DIRECTION INPUT ;
    USE SIGNAL ;
    SHAPE ABUTMENT ;
    PORT
      LAYER M5 ;
      RECT 373.368 777.408 373.392 777.600 ;
    END
  END tx_flit[720]
  PIN tx_flit[721]
    DIRECTION INPUT ;
    USE SIGNAL ;
    SHAPE ABUTMENT ;
    PORT
      LAYER M5 ;
      RECT 373.416 777.408 373.440 777.600 ;
    END
  END tx_flit[721]
  PIN tx_flit[722]
    DIRECTION INPUT ;
    USE SIGNAL ;
    SHAPE ABUTMENT ;
    PORT
      LAYER M5 ;
      RECT 373.464 777.408 373.488 777.600 ;
    END
  END tx_flit[722]
  PIN tx_flit[723]
    DIRECTION INPUT ;
    USE SIGNAL ;
    SHAPE ABUTMENT ;
    PORT
      LAYER M5 ;
      RECT 373.512 777.408 373.536 777.600 ;
    END
  END tx_flit[723]
  PIN tx_flit[724]
    DIRECTION INPUT ;
    USE SIGNAL ;
    SHAPE ABUTMENT ;
    PORT
      LAYER M5 ;
      RECT 373.560 777.408 373.584 777.600 ;
    END
  END tx_flit[724]
  PIN tx_flit[725]
    DIRECTION INPUT ;
    USE SIGNAL ;
    SHAPE ABUTMENT ;
    PORT
      LAYER M5 ;
      RECT 373.608 777.408 373.632 777.600 ;
    END
  END tx_flit[725]
  PIN tx_flit[726]
    DIRECTION INPUT ;
    USE SIGNAL ;
    SHAPE ABUTMENT ;
    PORT
      LAYER M5 ;
      RECT 373.656 777.408 373.680 777.600 ;
    END
  END tx_flit[726]
  PIN tx_flit[727]
    DIRECTION INPUT ;
    USE SIGNAL ;
    SHAPE ABUTMENT ;
    PORT
      LAYER M5 ;
      RECT 373.704 777.408 373.728 777.600 ;
    END
  END tx_flit[727]
  PIN tx_flit[728]
    DIRECTION INPUT ;
    USE SIGNAL ;
    SHAPE ABUTMENT ;
    PORT
      LAYER M5 ;
      RECT 373.752 777.408 373.776 777.600 ;
    END
  END tx_flit[728]
  PIN tx_flit[729]
    DIRECTION INPUT ;
    USE SIGNAL ;
    SHAPE ABUTMENT ;
    PORT
      LAYER M5 ;
      RECT 373.800 777.408 373.824 777.600 ;
    END
  END tx_flit[729]
  PIN tx_flit[730]
    DIRECTION INPUT ;
    USE SIGNAL ;
    SHAPE ABUTMENT ;
    PORT
      LAYER M5 ;
      RECT 373.848 777.408 373.872 777.600 ;
    END
  END tx_flit[730]
  PIN tx_flit[731]
    DIRECTION INPUT ;
    USE SIGNAL ;
    SHAPE ABUTMENT ;
    PORT
      LAYER M5 ;
      RECT 373.896 777.408 373.920 777.600 ;
    END
  END tx_flit[731]
  PIN tx_flit[732]
    DIRECTION INPUT ;
    USE SIGNAL ;
    SHAPE ABUTMENT ;
    PORT
      LAYER M5 ;
      RECT 373.944 777.408 373.968 777.600 ;
    END
  END tx_flit[732]
  PIN tx_flit[733]
    DIRECTION INPUT ;
    USE SIGNAL ;
    SHAPE ABUTMENT ;
    PORT
      LAYER M5 ;
      RECT 373.992 777.408 374.016 777.600 ;
    END
  END tx_flit[733]
  PIN tx_flit[734]
    DIRECTION INPUT ;
    USE SIGNAL ;
    SHAPE ABUTMENT ;
    PORT
      LAYER M5 ;
      RECT 374.040 777.408 374.064 777.600 ;
    END
  END tx_flit[734]
  PIN tx_flit[735]
    DIRECTION INPUT ;
    USE SIGNAL ;
    SHAPE ABUTMENT ;
    PORT
      LAYER M5 ;
      RECT 374.088 777.408 374.112 777.600 ;
    END
  END tx_flit[735]
  PIN tx_flit[736]
    DIRECTION INPUT ;
    USE SIGNAL ;
    SHAPE ABUTMENT ;
    PORT
      LAYER M5 ;
      RECT 374.136 777.408 374.160 777.600 ;
    END
  END tx_flit[736]
  PIN tx_flit[737]
    DIRECTION INPUT ;
    USE SIGNAL ;
    SHAPE ABUTMENT ;
    PORT
      LAYER M5 ;
      RECT 374.184 777.408 374.208 777.600 ;
    END
  END tx_flit[737]
  PIN tx_flit[738]
    DIRECTION INPUT ;
    USE SIGNAL ;
    SHAPE ABUTMENT ;
    PORT
      LAYER M5 ;
      RECT 374.232 777.408 374.256 777.600 ;
    END
  END tx_flit[738]
  PIN tx_flit[739]
    DIRECTION INPUT ;
    USE SIGNAL ;
    SHAPE ABUTMENT ;
    PORT
      LAYER M5 ;
      RECT 374.280 777.408 374.304 777.600 ;
    END
  END tx_flit[739]
  PIN tx_flit[740]
    DIRECTION INPUT ;
    USE SIGNAL ;
    SHAPE ABUTMENT ;
    PORT
      LAYER M5 ;
      RECT 374.328 777.408 374.352 777.600 ;
    END
  END tx_flit[740]
  PIN tx_flit[741]
    DIRECTION INPUT ;
    USE SIGNAL ;
    SHAPE ABUTMENT ;
    PORT
      LAYER M5 ;
      RECT 374.376 777.408 374.400 777.600 ;
    END
  END tx_flit[741]
  PIN tx_flit[742]
    DIRECTION INPUT ;
    USE SIGNAL ;
    SHAPE ABUTMENT ;
    PORT
      LAYER M5 ;
      RECT 374.424 777.408 374.448 777.600 ;
    END
  END tx_flit[742]
  PIN tx_flit[743]
    DIRECTION INPUT ;
    USE SIGNAL ;
    SHAPE ABUTMENT ;
    PORT
      LAYER M5 ;
      RECT 374.472 777.408 374.496 777.600 ;
    END
  END tx_flit[743]
  PIN tx_flit[744]
    DIRECTION INPUT ;
    USE SIGNAL ;
    SHAPE ABUTMENT ;
    PORT
      LAYER M5 ;
      RECT 374.520 777.408 374.544 777.600 ;
    END
  END tx_flit[744]
  PIN tx_flit[745]
    DIRECTION INPUT ;
    USE SIGNAL ;
    SHAPE ABUTMENT ;
    PORT
      LAYER M5 ;
      RECT 374.568 777.408 374.592 777.600 ;
    END
  END tx_flit[745]
  PIN tx_flit[746]
    DIRECTION INPUT ;
    USE SIGNAL ;
    SHAPE ABUTMENT ;
    PORT
      LAYER M5 ;
      RECT 374.616 777.408 374.640 777.600 ;
    END
  END tx_flit[746]
  PIN tx_flit[747]
    DIRECTION INPUT ;
    USE SIGNAL ;
    SHAPE ABUTMENT ;
    PORT
      LAYER M5 ;
      RECT 374.664 777.408 374.688 777.600 ;
    END
  END tx_flit[747]
  PIN tx_flit[748]
    DIRECTION INPUT ;
    USE SIGNAL ;
    SHAPE ABUTMENT ;
    PORT
      LAYER M5 ;
      RECT 374.712 777.408 374.736 777.600 ;
    END
  END tx_flit[748]
  PIN tx_flit[749]
    DIRECTION INPUT ;
    USE SIGNAL ;
    SHAPE ABUTMENT ;
    PORT
      LAYER M5 ;
      RECT 374.760 777.408 374.784 777.600 ;
    END
  END tx_flit[749]
  PIN tx_flit[750]
    DIRECTION INPUT ;
    USE SIGNAL ;
    SHAPE ABUTMENT ;
    PORT
      LAYER M5 ;
      RECT 374.808 777.408 374.832 777.600 ;
    END
  END tx_flit[750]
  PIN tx_flit[751]
    DIRECTION INPUT ;
    USE SIGNAL ;
    SHAPE ABUTMENT ;
    PORT
      LAYER M5 ;
      RECT 374.856 777.408 374.880 777.600 ;
    END
  END tx_flit[751]
  PIN tx_flit[752]
    DIRECTION INPUT ;
    USE SIGNAL ;
    SHAPE ABUTMENT ;
    PORT
      LAYER M5 ;
      RECT 374.904 777.408 374.928 777.600 ;
    END
  END tx_flit[752]
  PIN tx_flit[753]
    DIRECTION INPUT ;
    USE SIGNAL ;
    SHAPE ABUTMENT ;
    PORT
      LAYER M5 ;
      RECT 374.952 777.408 374.976 777.600 ;
    END
  END tx_flit[753]
  PIN tx_flit[754]
    DIRECTION INPUT ;
    USE SIGNAL ;
    SHAPE ABUTMENT ;
    PORT
      LAYER M5 ;
      RECT 375.000 777.408 375.024 777.600 ;
    END
  END tx_flit[754]
  PIN tx_flit[755]
    DIRECTION INPUT ;
    USE SIGNAL ;
    SHAPE ABUTMENT ;
    PORT
      LAYER M5 ;
      RECT 375.048 777.408 375.072 777.600 ;
    END
  END tx_flit[755]
  PIN tx_flit[756]
    DIRECTION INPUT ;
    USE SIGNAL ;
    SHAPE ABUTMENT ;
    PORT
      LAYER M5 ;
      RECT 375.096 777.408 375.120 777.600 ;
    END
  END tx_flit[756]
  PIN tx_flit[757]
    DIRECTION INPUT ;
    USE SIGNAL ;
    SHAPE ABUTMENT ;
    PORT
      LAYER M5 ;
      RECT 375.144 777.408 375.168 777.600 ;
    END
  END tx_flit[757]
  PIN tx_flit[758]
    DIRECTION INPUT ;
    USE SIGNAL ;
    SHAPE ABUTMENT ;
    PORT
      LAYER M5 ;
      RECT 375.192 777.408 375.216 777.600 ;
    END
  END tx_flit[758]
  PIN tx_flit[759]
    DIRECTION INPUT ;
    USE SIGNAL ;
    SHAPE ABUTMENT ;
    PORT
      LAYER M5 ;
      RECT 375.240 777.408 375.264 777.600 ;
    END
  END tx_flit[759]
  PIN tx_flit[760]
    DIRECTION INPUT ;
    USE SIGNAL ;
    SHAPE ABUTMENT ;
    PORT
      LAYER M5 ;
      RECT 375.288 777.408 375.312 777.600 ;
    END
  END tx_flit[760]
  PIN tx_flit[761]
    DIRECTION INPUT ;
    USE SIGNAL ;
    SHAPE ABUTMENT ;
    PORT
      LAYER M5 ;
      RECT 375.336 777.408 375.360 777.600 ;
    END
  END tx_flit[761]
  PIN tx_flit[762]
    DIRECTION INPUT ;
    USE SIGNAL ;
    SHAPE ABUTMENT ;
    PORT
      LAYER M5 ;
      RECT 375.384 777.408 375.408 777.600 ;
    END
  END tx_flit[762]
  PIN tx_flit[763]
    DIRECTION INPUT ;
    USE SIGNAL ;
    SHAPE ABUTMENT ;
    PORT
      LAYER M5 ;
      RECT 375.432 777.408 375.456 777.600 ;
    END
  END tx_flit[763]
  PIN tx_flit[764]
    DIRECTION INPUT ;
    USE SIGNAL ;
    SHAPE ABUTMENT ;
    PORT
      LAYER M5 ;
      RECT 375.480 777.408 375.504 777.600 ;
    END
  END tx_flit[764]
  PIN tx_flit[765]
    DIRECTION INPUT ;
    USE SIGNAL ;
    SHAPE ABUTMENT ;
    PORT
      LAYER M5 ;
      RECT 375.528 777.408 375.552 777.600 ;
    END
  END tx_flit[765]
  PIN tx_flit[766]
    DIRECTION INPUT ;
    USE SIGNAL ;
    SHAPE ABUTMENT ;
    PORT
      LAYER M5 ;
      RECT 375.576 777.408 375.600 777.600 ;
    END
  END tx_flit[766]
  PIN tx_flit[767]
    DIRECTION INPUT ;
    USE SIGNAL ;
    SHAPE ABUTMENT ;
    PORT
      LAYER M5 ;
      RECT 375.624 777.408 375.648 777.600 ;
    END
  END tx_flit[767]
  PIN tx_flit[768]
    DIRECTION INPUT ;
    USE SIGNAL ;
    SHAPE ABUTMENT ;
    PORT
      LAYER M5 ;
      RECT 375.672 777.408 375.696 777.600 ;
    END
  END tx_flit[768]
  PIN tx_flit[769]
    DIRECTION INPUT ;
    USE SIGNAL ;
    SHAPE ABUTMENT ;
    PORT
      LAYER M5 ;
      RECT 375.720 777.408 375.744 777.600 ;
    END
  END tx_flit[769]
  PIN tx_flit[770]
    DIRECTION INPUT ;
    USE SIGNAL ;
    SHAPE ABUTMENT ;
    PORT
      LAYER M5 ;
      RECT 375.768 777.408 375.792 777.600 ;
    END
  END tx_flit[770]
  PIN tx_flit[771]
    DIRECTION INPUT ;
    USE SIGNAL ;
    SHAPE ABUTMENT ;
    PORT
      LAYER M5 ;
      RECT 375.816 777.408 375.840 777.600 ;
    END
  END tx_flit[771]
  PIN tx_flit[772]
    DIRECTION INPUT ;
    USE SIGNAL ;
    SHAPE ABUTMENT ;
    PORT
      LAYER M5 ;
      RECT 375.864 777.408 375.888 777.600 ;
    END
  END tx_flit[772]
  PIN tx_flit[773]
    DIRECTION INPUT ;
    USE SIGNAL ;
    SHAPE ABUTMENT ;
    PORT
      LAYER M5 ;
      RECT 375.912 777.408 375.936 777.600 ;
    END
  END tx_flit[773]
  PIN tx_flit[774]
    DIRECTION INPUT ;
    USE SIGNAL ;
    SHAPE ABUTMENT ;
    PORT
      LAYER M5 ;
      RECT 375.960 777.408 375.984 777.600 ;
    END
  END tx_flit[774]
  PIN tx_flit[775]
    DIRECTION INPUT ;
    USE SIGNAL ;
    SHAPE ABUTMENT ;
    PORT
      LAYER M5 ;
      RECT 376.008 777.408 376.032 777.600 ;
    END
  END tx_flit[775]
  PIN tx_flit[776]
    DIRECTION INPUT ;
    USE SIGNAL ;
    SHAPE ABUTMENT ;
    PORT
      LAYER M5 ;
      RECT 376.056 777.408 376.080 777.600 ;
    END
  END tx_flit[776]
  PIN tx_flit[777]
    DIRECTION INPUT ;
    USE SIGNAL ;
    SHAPE ABUTMENT ;
    PORT
      LAYER M5 ;
      RECT 376.104 777.408 376.128 777.600 ;
    END
  END tx_flit[777]
  PIN tx_flit[778]
    DIRECTION INPUT ;
    USE SIGNAL ;
    SHAPE ABUTMENT ;
    PORT
      LAYER M5 ;
      RECT 376.152 777.408 376.176 777.600 ;
    END
  END tx_flit[778]
  PIN tx_flit[779]
    DIRECTION INPUT ;
    USE SIGNAL ;
    SHAPE ABUTMENT ;
    PORT
      LAYER M5 ;
      RECT 376.200 777.408 376.224 777.600 ;
    END
  END tx_flit[779]
  PIN tx_flit[780]
    DIRECTION INPUT ;
    USE SIGNAL ;
    SHAPE ABUTMENT ;
    PORT
      LAYER M5 ;
      RECT 376.248 777.408 376.272 777.600 ;
    END
  END tx_flit[780]
  PIN tx_flit[781]
    DIRECTION INPUT ;
    USE SIGNAL ;
    SHAPE ABUTMENT ;
    PORT
      LAYER M5 ;
      RECT 376.296 777.408 376.320 777.600 ;
    END
  END tx_flit[781]
  PIN tx_flit[782]
    DIRECTION INPUT ;
    USE SIGNAL ;
    SHAPE ABUTMENT ;
    PORT
      LAYER M5 ;
      RECT 376.344 777.408 376.368 777.600 ;
    END
  END tx_flit[782]
  PIN tx_flit[783]
    DIRECTION INPUT ;
    USE SIGNAL ;
    SHAPE ABUTMENT ;
    PORT
      LAYER M5 ;
      RECT 376.392 777.408 376.416 777.600 ;
    END
  END tx_flit[783]
  PIN tx_flit[784]
    DIRECTION INPUT ;
    USE SIGNAL ;
    SHAPE ABUTMENT ;
    PORT
      LAYER M5 ;
      RECT 376.440 777.408 376.464 777.600 ;
    END
  END tx_flit[784]
  PIN tx_flit[785]
    DIRECTION INPUT ;
    USE SIGNAL ;
    SHAPE ABUTMENT ;
    PORT
      LAYER M5 ;
      RECT 376.488 777.408 376.512 777.600 ;
    END
  END tx_flit[785]
  PIN tx_flit[786]
    DIRECTION INPUT ;
    USE SIGNAL ;
    SHAPE ABUTMENT ;
    PORT
      LAYER M5 ;
      RECT 376.536 777.408 376.560 777.600 ;
    END
  END tx_flit[786]
  PIN tx_flit[787]
    DIRECTION INPUT ;
    USE SIGNAL ;
    SHAPE ABUTMENT ;
    PORT
      LAYER M5 ;
      RECT 376.584 777.408 376.608 777.600 ;
    END
  END tx_flit[787]
  PIN tx_flit[788]
    DIRECTION INPUT ;
    USE SIGNAL ;
    SHAPE ABUTMENT ;
    PORT
      LAYER M5 ;
      RECT 376.632 777.408 376.656 777.600 ;
    END
  END tx_flit[788]
  PIN tx_flit[789]
    DIRECTION INPUT ;
    USE SIGNAL ;
    SHAPE ABUTMENT ;
    PORT
      LAYER M5 ;
      RECT 376.680 777.408 376.704 777.600 ;
    END
  END tx_flit[789]
  PIN tx_flit[790]
    DIRECTION INPUT ;
    USE SIGNAL ;
    SHAPE ABUTMENT ;
    PORT
      LAYER M5 ;
      RECT 376.728 777.408 376.752 777.600 ;
    END
  END tx_flit[790]
  PIN tx_flit[791]
    DIRECTION INPUT ;
    USE SIGNAL ;
    SHAPE ABUTMENT ;
    PORT
      LAYER M5 ;
      RECT 376.776 777.408 376.800 777.600 ;
    END
  END tx_flit[791]
  PIN tx_flit[792]
    DIRECTION INPUT ;
    USE SIGNAL ;
    SHAPE ABUTMENT ;
    PORT
      LAYER M5 ;
      RECT 376.824 777.408 376.848 777.600 ;
    END
  END tx_flit[792]
  PIN tx_flit[793]
    DIRECTION INPUT ;
    USE SIGNAL ;
    SHAPE ABUTMENT ;
    PORT
      LAYER M5 ;
      RECT 376.872 777.408 376.896 777.600 ;
    END
  END tx_flit[793]
  PIN tx_flit[794]
    DIRECTION INPUT ;
    USE SIGNAL ;
    SHAPE ABUTMENT ;
    PORT
      LAYER M5 ;
      RECT 376.920 777.408 376.944 777.600 ;
    END
  END tx_flit[794]
  PIN tx_flit[795]
    DIRECTION INPUT ;
    USE SIGNAL ;
    SHAPE ABUTMENT ;
    PORT
      LAYER M5 ;
      RECT 376.968 777.408 376.992 777.600 ;
    END
  END tx_flit[795]
  PIN tx_flit[796]
    DIRECTION INPUT ;
    USE SIGNAL ;
    SHAPE ABUTMENT ;
    PORT
      LAYER M5 ;
      RECT 377.016 777.408 377.040 777.600 ;
    END
  END tx_flit[796]
  PIN tx_flit[797]
    DIRECTION INPUT ;
    USE SIGNAL ;
    SHAPE ABUTMENT ;
    PORT
      LAYER M5 ;
      RECT 377.064 777.408 377.088 777.600 ;
    END
  END tx_flit[797]
  PIN tx_flit[798]
    DIRECTION INPUT ;
    USE SIGNAL ;
    SHAPE ABUTMENT ;
    PORT
      LAYER M5 ;
      RECT 377.112 777.408 377.136 777.600 ;
    END
  END tx_flit[798]
  PIN tx_flit[799]
    DIRECTION INPUT ;
    USE SIGNAL ;
    SHAPE ABUTMENT ;
    PORT
      LAYER M5 ;
      RECT 377.160 777.408 377.184 777.600 ;
    END
  END tx_flit[799]
  PIN tx_flit[800]
    DIRECTION INPUT ;
    USE SIGNAL ;
    SHAPE ABUTMENT ;
    PORT
      LAYER M5 ;
      RECT 377.208 777.408 377.232 777.600 ;
    END
  END tx_flit[800]
  PIN tx_flit[801]
    DIRECTION INPUT ;
    USE SIGNAL ;
    SHAPE ABUTMENT ;
    PORT
      LAYER M5 ;
      RECT 377.256 777.408 377.280 777.600 ;
    END
  END tx_flit[801]
  PIN tx_flit[802]
    DIRECTION INPUT ;
    USE SIGNAL ;
    SHAPE ABUTMENT ;
    PORT
      LAYER M5 ;
      RECT 377.304 777.408 377.328 777.600 ;
    END
  END tx_flit[802]
  PIN tx_flit[803]
    DIRECTION INPUT ;
    USE SIGNAL ;
    SHAPE ABUTMENT ;
    PORT
      LAYER M5 ;
      RECT 377.352 777.408 377.376 777.600 ;
    END
  END tx_flit[803]
  PIN tx_flit[804]
    DIRECTION INPUT ;
    USE SIGNAL ;
    SHAPE ABUTMENT ;
    PORT
      LAYER M5 ;
      RECT 377.400 777.408 377.424 777.600 ;
    END
  END tx_flit[804]
  PIN tx_flit[805]
    DIRECTION INPUT ;
    USE SIGNAL ;
    SHAPE ABUTMENT ;
    PORT
      LAYER M5 ;
      RECT 377.448 777.408 377.472 777.600 ;
    END
  END tx_flit[805]
  PIN tx_flit[806]
    DIRECTION INPUT ;
    USE SIGNAL ;
    SHAPE ABUTMENT ;
    PORT
      LAYER M5 ;
      RECT 377.496 777.408 377.520 777.600 ;
    END
  END tx_flit[806]
  PIN tx_flit[807]
    DIRECTION INPUT ;
    USE SIGNAL ;
    SHAPE ABUTMENT ;
    PORT
      LAYER M5 ;
      RECT 377.544 777.408 377.568 777.600 ;
    END
  END tx_flit[807]
  PIN tx_flit[808]
    DIRECTION INPUT ;
    USE SIGNAL ;
    SHAPE ABUTMENT ;
    PORT
      LAYER M5 ;
      RECT 377.592 777.408 377.616 777.600 ;
    END
  END tx_flit[808]
  PIN tx_flit[809]
    DIRECTION INPUT ;
    USE SIGNAL ;
    SHAPE ABUTMENT ;
    PORT
      LAYER M5 ;
      RECT 377.640 777.408 377.664 777.600 ;
    END
  END tx_flit[809]
  PIN tx_flit[810]
    DIRECTION INPUT ;
    USE SIGNAL ;
    SHAPE ABUTMENT ;
    PORT
      LAYER M5 ;
      RECT 377.688 777.408 377.712 777.600 ;
    END
  END tx_flit[810]
  PIN tx_flit[811]
    DIRECTION INPUT ;
    USE SIGNAL ;
    SHAPE ABUTMENT ;
    PORT
      LAYER M5 ;
      RECT 377.736 777.408 377.760 777.600 ;
    END
  END tx_flit[811]
  PIN tx_flit[812]
    DIRECTION INPUT ;
    USE SIGNAL ;
    SHAPE ABUTMENT ;
    PORT
      LAYER M5 ;
      RECT 377.784 777.408 377.808 777.600 ;
    END
  END tx_flit[812]
  PIN tx_flit[813]
    DIRECTION INPUT ;
    USE SIGNAL ;
    SHAPE ABUTMENT ;
    PORT
      LAYER M5 ;
      RECT 377.832 777.408 377.856 777.600 ;
    END
  END tx_flit[813]
  PIN tx_flit[814]
    DIRECTION INPUT ;
    USE SIGNAL ;
    SHAPE ABUTMENT ;
    PORT
      LAYER M5 ;
      RECT 377.880 777.408 377.904 777.600 ;
    END
  END tx_flit[814]
  PIN tx_flit[815]
    DIRECTION INPUT ;
    USE SIGNAL ;
    SHAPE ABUTMENT ;
    PORT
      LAYER M5 ;
      RECT 377.928 777.408 377.952 777.600 ;
    END
  END tx_flit[815]
  PIN tx_flit[816]
    DIRECTION INPUT ;
    USE SIGNAL ;
    SHAPE ABUTMENT ;
    PORT
      LAYER M5 ;
      RECT 377.976 777.408 378.000 777.600 ;
    END
  END tx_flit[816]
  PIN tx_flit[817]
    DIRECTION INPUT ;
    USE SIGNAL ;
    SHAPE ABUTMENT ;
    PORT
      LAYER M5 ;
      RECT 378.024 777.408 378.048 777.600 ;
    END
  END tx_flit[817]
  PIN tx_flit[818]
    DIRECTION INPUT ;
    USE SIGNAL ;
    SHAPE ABUTMENT ;
    PORT
      LAYER M5 ;
      RECT 378.072 777.408 378.096 777.600 ;
    END
  END tx_flit[818]
  PIN tx_flit[819]
    DIRECTION INPUT ;
    USE SIGNAL ;
    SHAPE ABUTMENT ;
    PORT
      LAYER M5 ;
      RECT 378.120 777.408 378.144 777.600 ;
    END
  END tx_flit[819]
  PIN tx_flit[820]
    DIRECTION INPUT ;
    USE SIGNAL ;
    SHAPE ABUTMENT ;
    PORT
      LAYER M5 ;
      RECT 378.168 777.408 378.192 777.600 ;
    END
  END tx_flit[820]
  PIN tx_flit[821]
    DIRECTION INPUT ;
    USE SIGNAL ;
    SHAPE ABUTMENT ;
    PORT
      LAYER M5 ;
      RECT 378.216 777.408 378.240 777.600 ;
    END
  END tx_flit[821]
  PIN tx_flit[822]
    DIRECTION INPUT ;
    USE SIGNAL ;
    SHAPE ABUTMENT ;
    PORT
      LAYER M5 ;
      RECT 378.264 777.408 378.288 777.600 ;
    END
  END tx_flit[822]
  PIN tx_flit[823]
    DIRECTION INPUT ;
    USE SIGNAL ;
    SHAPE ABUTMENT ;
    PORT
      LAYER M5 ;
      RECT 378.312 777.408 378.336 777.600 ;
    END
  END tx_flit[823]
  PIN tx_flit[824]
    DIRECTION INPUT ;
    USE SIGNAL ;
    SHAPE ABUTMENT ;
    PORT
      LAYER M5 ;
      RECT 378.360 777.408 378.384 777.600 ;
    END
  END tx_flit[824]
  PIN tx_flit[825]
    DIRECTION INPUT ;
    USE SIGNAL ;
    SHAPE ABUTMENT ;
    PORT
      LAYER M5 ;
      RECT 378.408 777.408 378.432 777.600 ;
    END
  END tx_flit[825]
  PIN tx_flit[826]
    DIRECTION INPUT ;
    USE SIGNAL ;
    SHAPE ABUTMENT ;
    PORT
      LAYER M5 ;
      RECT 378.456 777.408 378.480 777.600 ;
    END
  END tx_flit[826]
  PIN tx_flit[827]
    DIRECTION INPUT ;
    USE SIGNAL ;
    SHAPE ABUTMENT ;
    PORT
      LAYER M5 ;
      RECT 378.504 777.408 378.528 777.600 ;
    END
  END tx_flit[827]
  PIN tx_flit[828]
    DIRECTION INPUT ;
    USE SIGNAL ;
    SHAPE ABUTMENT ;
    PORT
      LAYER M5 ;
      RECT 378.552 777.408 378.576 777.600 ;
    END
  END tx_flit[828]
  PIN tx_flit[829]
    DIRECTION INPUT ;
    USE SIGNAL ;
    SHAPE ABUTMENT ;
    PORT
      LAYER M5 ;
      RECT 378.600 777.408 378.624 777.600 ;
    END
  END tx_flit[829]
  PIN tx_flit[830]
    DIRECTION INPUT ;
    USE SIGNAL ;
    SHAPE ABUTMENT ;
    PORT
      LAYER M5 ;
      RECT 378.648 777.408 378.672 777.600 ;
    END
  END tx_flit[830]
  PIN tx_flit[831]
    DIRECTION INPUT ;
    USE SIGNAL ;
    SHAPE ABUTMENT ;
    PORT
      LAYER M5 ;
      RECT 378.696 777.408 378.720 777.600 ;
    END
  END tx_flit[831]
  PIN tx_flit[832]
    DIRECTION INPUT ;
    USE SIGNAL ;
    SHAPE ABUTMENT ;
    PORT
      LAYER M5 ;
      RECT 378.744 777.408 378.768 777.600 ;
    END
  END tx_flit[832]
  PIN tx_flit[833]
    DIRECTION INPUT ;
    USE SIGNAL ;
    SHAPE ABUTMENT ;
    PORT
      LAYER M5 ;
      RECT 378.792 777.408 378.816 777.600 ;
    END
  END tx_flit[833]
  PIN tx_flit[834]
    DIRECTION INPUT ;
    USE SIGNAL ;
    SHAPE ABUTMENT ;
    PORT
      LAYER M5 ;
      RECT 378.840 777.408 378.864 777.600 ;
    END
  END tx_flit[834]
  PIN tx_flit[835]
    DIRECTION INPUT ;
    USE SIGNAL ;
    SHAPE ABUTMENT ;
    PORT
      LAYER M5 ;
      RECT 378.888 777.408 378.912 777.600 ;
    END
  END tx_flit[835]
  PIN tx_flit[836]
    DIRECTION INPUT ;
    USE SIGNAL ;
    SHAPE ABUTMENT ;
    PORT
      LAYER M5 ;
      RECT 378.936 777.408 378.960 777.600 ;
    END
  END tx_flit[836]
  PIN tx_flit[837]
    DIRECTION INPUT ;
    USE SIGNAL ;
    SHAPE ABUTMENT ;
    PORT
      LAYER M5 ;
      RECT 378.984 777.408 379.008 777.600 ;
    END
  END tx_flit[837]
  PIN tx_flit[838]
    DIRECTION INPUT ;
    USE SIGNAL ;
    SHAPE ABUTMENT ;
    PORT
      LAYER M5 ;
      RECT 379.032 777.408 379.056 777.600 ;
    END
  END tx_flit[838]
  PIN tx_flit[839]
    DIRECTION INPUT ;
    USE SIGNAL ;
    SHAPE ABUTMENT ;
    PORT
      LAYER M5 ;
      RECT 379.080 777.408 379.104 777.600 ;
    END
  END tx_flit[839]
  PIN tx_flit[840]
    DIRECTION INPUT ;
    USE SIGNAL ;
    SHAPE ABUTMENT ;
    PORT
      LAYER M5 ;
      RECT 379.128 777.408 379.152 777.600 ;
    END
  END tx_flit[840]
  PIN tx_flit[841]
    DIRECTION INPUT ;
    USE SIGNAL ;
    SHAPE ABUTMENT ;
    PORT
      LAYER M5 ;
      RECT 379.176 777.408 379.200 777.600 ;
    END
  END tx_flit[841]
  PIN tx_flit[842]
    DIRECTION INPUT ;
    USE SIGNAL ;
    SHAPE ABUTMENT ;
    PORT
      LAYER M5 ;
      RECT 379.224 777.408 379.248 777.600 ;
    END
  END tx_flit[842]
  PIN tx_flit[843]
    DIRECTION INPUT ;
    USE SIGNAL ;
    SHAPE ABUTMENT ;
    PORT
      LAYER M5 ;
      RECT 379.272 777.408 379.296 777.600 ;
    END
  END tx_flit[843]
  PIN tx_flit[844]
    DIRECTION INPUT ;
    USE SIGNAL ;
    SHAPE ABUTMENT ;
    PORT
      LAYER M5 ;
      RECT 379.320 777.408 379.344 777.600 ;
    END
  END tx_flit[844]
  PIN tx_flit[845]
    DIRECTION INPUT ;
    USE SIGNAL ;
    SHAPE ABUTMENT ;
    PORT
      LAYER M5 ;
      RECT 379.368 777.408 379.392 777.600 ;
    END
  END tx_flit[845]
  PIN tx_flit[846]
    DIRECTION INPUT ;
    USE SIGNAL ;
    SHAPE ABUTMENT ;
    PORT
      LAYER M5 ;
      RECT 379.416 777.408 379.440 777.600 ;
    END
  END tx_flit[846]
  PIN tx_flit[847]
    DIRECTION INPUT ;
    USE SIGNAL ;
    SHAPE ABUTMENT ;
    PORT
      LAYER M5 ;
      RECT 379.464 777.408 379.488 777.600 ;
    END
  END tx_flit[847]
  PIN tx_flit[848]
    DIRECTION INPUT ;
    USE SIGNAL ;
    SHAPE ABUTMENT ;
    PORT
      LAYER M5 ;
      RECT 379.512 777.408 379.536 777.600 ;
    END
  END tx_flit[848]
  PIN tx_flit[849]
    DIRECTION INPUT ;
    USE SIGNAL ;
    SHAPE ABUTMENT ;
    PORT
      LAYER M5 ;
      RECT 379.560 777.408 379.584 777.600 ;
    END
  END tx_flit[849]
  PIN tx_flit[850]
    DIRECTION INPUT ;
    USE SIGNAL ;
    SHAPE ABUTMENT ;
    PORT
      LAYER M5 ;
      RECT 379.608 777.408 379.632 777.600 ;
    END
  END tx_flit[850]
  PIN tx_flit[851]
    DIRECTION INPUT ;
    USE SIGNAL ;
    SHAPE ABUTMENT ;
    PORT
      LAYER M5 ;
      RECT 379.656 777.408 379.680 777.600 ;
    END
  END tx_flit[851]
  PIN tx_flit[852]
    DIRECTION INPUT ;
    USE SIGNAL ;
    SHAPE ABUTMENT ;
    PORT
      LAYER M5 ;
      RECT 379.704 777.408 379.728 777.600 ;
    END
  END tx_flit[852]
  PIN tx_flit[853]
    DIRECTION INPUT ;
    USE SIGNAL ;
    SHAPE ABUTMENT ;
    PORT
      LAYER M5 ;
      RECT 379.752 777.408 379.776 777.600 ;
    END
  END tx_flit[853]
  PIN tx_flit[854]
    DIRECTION INPUT ;
    USE SIGNAL ;
    SHAPE ABUTMENT ;
    PORT
      LAYER M5 ;
      RECT 379.800 777.408 379.824 777.600 ;
    END
  END tx_flit[854]
  PIN tx_flit[855]
    DIRECTION INPUT ;
    USE SIGNAL ;
    SHAPE ABUTMENT ;
    PORT
      LAYER M5 ;
      RECT 379.848 777.408 379.872 777.600 ;
    END
  END tx_flit[855]
  PIN tx_flit[856]
    DIRECTION INPUT ;
    USE SIGNAL ;
    SHAPE ABUTMENT ;
    PORT
      LAYER M5 ;
      RECT 379.896 777.408 379.920 777.600 ;
    END
  END tx_flit[856]
  PIN tx_flit[857]
    DIRECTION INPUT ;
    USE SIGNAL ;
    SHAPE ABUTMENT ;
    PORT
      LAYER M5 ;
      RECT 379.944 777.408 379.968 777.600 ;
    END
  END tx_flit[857]
  PIN tx_flit[858]
    DIRECTION INPUT ;
    USE SIGNAL ;
    SHAPE ABUTMENT ;
    PORT
      LAYER M5 ;
      RECT 379.992 777.408 380.016 777.600 ;
    END
  END tx_flit[858]
  PIN tx_flit[859]
    DIRECTION INPUT ;
    USE SIGNAL ;
    SHAPE ABUTMENT ;
    PORT
      LAYER M5 ;
      RECT 380.040 777.408 380.064 777.600 ;
    END
  END tx_flit[859]
  PIN tx_flit[860]
    DIRECTION INPUT ;
    USE SIGNAL ;
    SHAPE ABUTMENT ;
    PORT
      LAYER M5 ;
      RECT 380.088 777.408 380.112 777.600 ;
    END
  END tx_flit[860]
  PIN tx_flit[861]
    DIRECTION INPUT ;
    USE SIGNAL ;
    SHAPE ABUTMENT ;
    PORT
      LAYER M5 ;
      RECT 380.136 777.408 380.160 777.600 ;
    END
  END tx_flit[861]
  PIN tx_flit[862]
    DIRECTION INPUT ;
    USE SIGNAL ;
    SHAPE ABUTMENT ;
    PORT
      LAYER M5 ;
      RECT 380.184 777.408 380.208 777.600 ;
    END
  END tx_flit[862]
  PIN tx_flit[863]
    DIRECTION INPUT ;
    USE SIGNAL ;
    SHAPE ABUTMENT ;
    PORT
      LAYER M5 ;
      RECT 380.232 777.408 380.256 777.600 ;
    END
  END tx_flit[863]
  PIN tx_flit[864]
    DIRECTION INPUT ;
    USE SIGNAL ;
    SHAPE ABUTMENT ;
    PORT
      LAYER M5 ;
      RECT 380.280 777.408 380.304 777.600 ;
    END
  END tx_flit[864]
  PIN tx_flit[865]
    DIRECTION INPUT ;
    USE SIGNAL ;
    SHAPE ABUTMENT ;
    PORT
      LAYER M5 ;
      RECT 380.328 777.408 380.352 777.600 ;
    END
  END tx_flit[865]
  PIN tx_flit[866]
    DIRECTION INPUT ;
    USE SIGNAL ;
    SHAPE ABUTMENT ;
    PORT
      LAYER M5 ;
      RECT 380.376 777.408 380.400 777.600 ;
    END
  END tx_flit[866]
  PIN tx_flit[867]
    DIRECTION INPUT ;
    USE SIGNAL ;
    SHAPE ABUTMENT ;
    PORT
      LAYER M5 ;
      RECT 380.424 777.408 380.448 777.600 ;
    END
  END tx_flit[867]
  PIN tx_flit[868]
    DIRECTION INPUT ;
    USE SIGNAL ;
    SHAPE ABUTMENT ;
    PORT
      LAYER M5 ;
      RECT 380.472 777.408 380.496 777.600 ;
    END
  END tx_flit[868]
  PIN tx_flit[869]
    DIRECTION INPUT ;
    USE SIGNAL ;
    SHAPE ABUTMENT ;
    PORT
      LAYER M5 ;
      RECT 380.520 777.408 380.544 777.600 ;
    END
  END tx_flit[869]
  PIN tx_flit[870]
    DIRECTION INPUT ;
    USE SIGNAL ;
    SHAPE ABUTMENT ;
    PORT
      LAYER M5 ;
      RECT 380.568 777.408 380.592 777.600 ;
    END
  END tx_flit[870]
  PIN tx_flit[871]
    DIRECTION INPUT ;
    USE SIGNAL ;
    SHAPE ABUTMENT ;
    PORT
      LAYER M5 ;
      RECT 380.616 777.408 380.640 777.600 ;
    END
  END tx_flit[871]
  PIN tx_flit[872]
    DIRECTION INPUT ;
    USE SIGNAL ;
    SHAPE ABUTMENT ;
    PORT
      LAYER M5 ;
      RECT 380.664 777.408 380.688 777.600 ;
    END
  END tx_flit[872]
  PIN tx_flit[873]
    DIRECTION INPUT ;
    USE SIGNAL ;
    SHAPE ABUTMENT ;
    PORT
      LAYER M5 ;
      RECT 380.712 777.408 380.736 777.600 ;
    END
  END tx_flit[873]
  PIN tx_flit[874]
    DIRECTION INPUT ;
    USE SIGNAL ;
    SHAPE ABUTMENT ;
    PORT
      LAYER M5 ;
      RECT 380.760 777.408 380.784 777.600 ;
    END
  END tx_flit[874]
  PIN tx_flit[875]
    DIRECTION INPUT ;
    USE SIGNAL ;
    SHAPE ABUTMENT ;
    PORT
      LAYER M5 ;
      RECT 380.808 777.408 380.832 777.600 ;
    END
  END tx_flit[875]
  PIN tx_flit[876]
    DIRECTION INPUT ;
    USE SIGNAL ;
    SHAPE ABUTMENT ;
    PORT
      LAYER M5 ;
      RECT 380.856 777.408 380.880 777.600 ;
    END
  END tx_flit[876]
  PIN tx_flit[877]
    DIRECTION INPUT ;
    USE SIGNAL ;
    SHAPE ABUTMENT ;
    PORT
      LAYER M5 ;
      RECT 380.904 777.408 380.928 777.600 ;
    END
  END tx_flit[877]
  PIN tx_flit[878]
    DIRECTION INPUT ;
    USE SIGNAL ;
    SHAPE ABUTMENT ;
    PORT
      LAYER M5 ;
      RECT 380.952 777.408 380.976 777.600 ;
    END
  END tx_flit[878]
  PIN tx_flit[879]
    DIRECTION INPUT ;
    USE SIGNAL ;
    SHAPE ABUTMENT ;
    PORT
      LAYER M5 ;
      RECT 381.000 777.408 381.024 777.600 ;
    END
  END tx_flit[879]
  PIN tx_flit[880]
    DIRECTION INPUT ;
    USE SIGNAL ;
    SHAPE ABUTMENT ;
    PORT
      LAYER M5 ;
      RECT 381.048 777.408 381.072 777.600 ;
    END
  END tx_flit[880]
  PIN tx_flit[881]
    DIRECTION INPUT ;
    USE SIGNAL ;
    SHAPE ABUTMENT ;
    PORT
      LAYER M5 ;
      RECT 381.096 777.408 381.120 777.600 ;
    END
  END tx_flit[881]
  PIN tx_flit[882]
    DIRECTION INPUT ;
    USE SIGNAL ;
    SHAPE ABUTMENT ;
    PORT
      LAYER M5 ;
      RECT 381.144 777.408 381.168 777.600 ;
    END
  END tx_flit[882]
  PIN tx_flit[883]
    DIRECTION INPUT ;
    USE SIGNAL ;
    SHAPE ABUTMENT ;
    PORT
      LAYER M5 ;
      RECT 381.192 777.408 381.216 777.600 ;
    END
  END tx_flit[883]
  PIN tx_flit[884]
    DIRECTION INPUT ;
    USE SIGNAL ;
    SHAPE ABUTMENT ;
    PORT
      LAYER M5 ;
      RECT 381.240 777.408 381.264 777.600 ;
    END
  END tx_flit[884]
  PIN tx_flit[885]
    DIRECTION INPUT ;
    USE SIGNAL ;
    SHAPE ABUTMENT ;
    PORT
      LAYER M5 ;
      RECT 381.288 777.408 381.312 777.600 ;
    END
  END tx_flit[885]
  PIN tx_flit[886]
    DIRECTION INPUT ;
    USE SIGNAL ;
    SHAPE ABUTMENT ;
    PORT
      LAYER M5 ;
      RECT 381.336 777.408 381.360 777.600 ;
    END
  END tx_flit[886]
  PIN tx_flit[887]
    DIRECTION INPUT ;
    USE SIGNAL ;
    SHAPE ABUTMENT ;
    PORT
      LAYER M5 ;
      RECT 381.384 777.408 381.408 777.600 ;
    END
  END tx_flit[887]
  PIN tx_flit[888]
    DIRECTION INPUT ;
    USE SIGNAL ;
    SHAPE ABUTMENT ;
    PORT
      LAYER M5 ;
      RECT 381.432 777.408 381.456 777.600 ;
    END
  END tx_flit[888]
  PIN tx_flit[889]
    DIRECTION INPUT ;
    USE SIGNAL ;
    SHAPE ABUTMENT ;
    PORT
      LAYER M5 ;
      RECT 381.480 777.408 381.504 777.600 ;
    END
  END tx_flit[889]
  PIN tx_flit[890]
    DIRECTION INPUT ;
    USE SIGNAL ;
    SHAPE ABUTMENT ;
    PORT
      LAYER M5 ;
      RECT 381.528 777.408 381.552 777.600 ;
    END
  END tx_flit[890]
  PIN tx_flit[891]
    DIRECTION INPUT ;
    USE SIGNAL ;
    SHAPE ABUTMENT ;
    PORT
      LAYER M5 ;
      RECT 381.576 777.408 381.600 777.600 ;
    END
  END tx_flit[891]
  PIN tx_flit[892]
    DIRECTION INPUT ;
    USE SIGNAL ;
    SHAPE ABUTMENT ;
    PORT
      LAYER M5 ;
      RECT 381.624 777.408 381.648 777.600 ;
    END
  END tx_flit[892]
  PIN tx_flit[893]
    DIRECTION INPUT ;
    USE SIGNAL ;
    SHAPE ABUTMENT ;
    PORT
      LAYER M5 ;
      RECT 381.672 777.408 381.696 777.600 ;
    END
  END tx_flit[893]
  PIN tx_flit[894]
    DIRECTION INPUT ;
    USE SIGNAL ;
    SHAPE ABUTMENT ;
    PORT
      LAYER M5 ;
      RECT 381.720 777.408 381.744 777.600 ;
    END
  END tx_flit[894]
  PIN tx_flit[895]
    DIRECTION INPUT ;
    USE SIGNAL ;
    SHAPE ABUTMENT ;
    PORT
      LAYER M5 ;
      RECT 381.768 777.408 381.792 777.600 ;
    END
  END tx_flit[895]
  PIN tx_flit[896]
    DIRECTION INPUT ;
    USE SIGNAL ;
    SHAPE ABUTMENT ;
    PORT
      LAYER M5 ;
      RECT 381.816 777.408 381.840 777.600 ;
    END
  END tx_flit[896]
  PIN tx_flit[897]
    DIRECTION INPUT ;
    USE SIGNAL ;
    SHAPE ABUTMENT ;
    PORT
      LAYER M5 ;
      RECT 381.864 777.408 381.888 777.600 ;
    END
  END tx_flit[897]
  PIN tx_flit[898]
    DIRECTION INPUT ;
    USE SIGNAL ;
    SHAPE ABUTMENT ;
    PORT
      LAYER M5 ;
      RECT 381.912 777.408 381.936 777.600 ;
    END
  END tx_flit[898]
  PIN tx_flit[899]
    DIRECTION INPUT ;
    USE SIGNAL ;
    SHAPE ABUTMENT ;
    PORT
      LAYER M5 ;
      RECT 381.960 777.408 381.984 777.600 ;
    END
  END tx_flit[899]
  PIN tx_flit[900]
    DIRECTION INPUT ;
    USE SIGNAL ;
    SHAPE ABUTMENT ;
    PORT
      LAYER M5 ;
      RECT 382.008 777.408 382.032 777.600 ;
    END
  END tx_flit[900]
  PIN tx_flit[901]
    DIRECTION INPUT ;
    USE SIGNAL ;
    SHAPE ABUTMENT ;
    PORT
      LAYER M5 ;
      RECT 382.056 777.408 382.080 777.600 ;
    END
  END tx_flit[901]
  PIN tx_flit[902]
    DIRECTION INPUT ;
    USE SIGNAL ;
    SHAPE ABUTMENT ;
    PORT
      LAYER M5 ;
      RECT 382.104 777.408 382.128 777.600 ;
    END
  END tx_flit[902]
  PIN tx_flit[903]
    DIRECTION INPUT ;
    USE SIGNAL ;
    SHAPE ABUTMENT ;
    PORT
      LAYER M5 ;
      RECT 382.152 777.408 382.176 777.600 ;
    END
  END tx_flit[903]
  PIN tx_flit[904]
    DIRECTION INPUT ;
    USE SIGNAL ;
    SHAPE ABUTMENT ;
    PORT
      LAYER M5 ;
      RECT 382.200 777.408 382.224 777.600 ;
    END
  END tx_flit[904]
  PIN tx_flit[905]
    DIRECTION INPUT ;
    USE SIGNAL ;
    SHAPE ABUTMENT ;
    PORT
      LAYER M5 ;
      RECT 382.248 777.408 382.272 777.600 ;
    END
  END tx_flit[905]
  PIN tx_flit[906]
    DIRECTION INPUT ;
    USE SIGNAL ;
    SHAPE ABUTMENT ;
    PORT
      LAYER M5 ;
      RECT 382.296 777.408 382.320 777.600 ;
    END
  END tx_flit[906]
  PIN tx_flit[907]
    DIRECTION INPUT ;
    USE SIGNAL ;
    SHAPE ABUTMENT ;
    PORT
      LAYER M5 ;
      RECT 382.344 777.408 382.368 777.600 ;
    END
  END tx_flit[907]
  PIN tx_flit[908]
    DIRECTION INPUT ;
    USE SIGNAL ;
    SHAPE ABUTMENT ;
    PORT
      LAYER M5 ;
      RECT 382.392 777.408 382.416 777.600 ;
    END
  END tx_flit[908]
  PIN tx_flit[909]
    DIRECTION INPUT ;
    USE SIGNAL ;
    SHAPE ABUTMENT ;
    PORT
      LAYER M5 ;
      RECT 382.440 777.408 382.464 777.600 ;
    END
  END tx_flit[909]
  PIN tx_flit[910]
    DIRECTION INPUT ;
    USE SIGNAL ;
    SHAPE ABUTMENT ;
    PORT
      LAYER M5 ;
      RECT 382.488 777.408 382.512 777.600 ;
    END
  END tx_flit[910]
  PIN tx_flit[911]
    DIRECTION INPUT ;
    USE SIGNAL ;
    SHAPE ABUTMENT ;
    PORT
      LAYER M5 ;
      RECT 382.536 777.408 382.560 777.600 ;
    END
  END tx_flit[911]
  PIN tx_flit[912]
    DIRECTION INPUT ;
    USE SIGNAL ;
    SHAPE ABUTMENT ;
    PORT
      LAYER M5 ;
      RECT 382.584 777.408 382.608 777.600 ;
    END
  END tx_flit[912]
  PIN tx_flit[913]
    DIRECTION INPUT ;
    USE SIGNAL ;
    SHAPE ABUTMENT ;
    PORT
      LAYER M5 ;
      RECT 382.632 777.408 382.656 777.600 ;
    END
  END tx_flit[913]
  PIN tx_flit[914]
    DIRECTION INPUT ;
    USE SIGNAL ;
    SHAPE ABUTMENT ;
    PORT
      LAYER M5 ;
      RECT 382.680 777.408 382.704 777.600 ;
    END
  END tx_flit[914]
  PIN tx_flit[915]
    DIRECTION INPUT ;
    USE SIGNAL ;
    SHAPE ABUTMENT ;
    PORT
      LAYER M5 ;
      RECT 382.728 777.408 382.752 777.600 ;
    END
  END tx_flit[915]
  PIN tx_flit[916]
    DIRECTION INPUT ;
    USE SIGNAL ;
    SHAPE ABUTMENT ;
    PORT
      LAYER M5 ;
      RECT 382.776 777.408 382.800 777.600 ;
    END
  END tx_flit[916]
  PIN tx_flit[917]
    DIRECTION INPUT ;
    USE SIGNAL ;
    SHAPE ABUTMENT ;
    PORT
      LAYER M5 ;
      RECT 382.824 777.408 382.848 777.600 ;
    END
  END tx_flit[917]
  PIN tx_flit[918]
    DIRECTION INPUT ;
    USE SIGNAL ;
    SHAPE ABUTMENT ;
    PORT
      LAYER M5 ;
      RECT 382.872 777.408 382.896 777.600 ;
    END
  END tx_flit[918]
  PIN tx_flit[919]
    DIRECTION INPUT ;
    USE SIGNAL ;
    SHAPE ABUTMENT ;
    PORT
      LAYER M5 ;
      RECT 382.920 777.408 382.944 777.600 ;
    END
  END tx_flit[919]
  PIN tx_flit[920]
    DIRECTION INPUT ;
    USE SIGNAL ;
    SHAPE ABUTMENT ;
    PORT
      LAYER M5 ;
      RECT 382.968 777.408 382.992 777.600 ;
    END
  END tx_flit[920]
  PIN tx_flit[921]
    DIRECTION INPUT ;
    USE SIGNAL ;
    SHAPE ABUTMENT ;
    PORT
      LAYER M5 ;
      RECT 383.016 777.408 383.040 777.600 ;
    END
  END tx_flit[921]
  PIN tx_flit[922]
    DIRECTION INPUT ;
    USE SIGNAL ;
    SHAPE ABUTMENT ;
    PORT
      LAYER M5 ;
      RECT 383.064 777.408 383.088 777.600 ;
    END
  END tx_flit[922]
  PIN tx_flit[923]
    DIRECTION INPUT ;
    USE SIGNAL ;
    SHAPE ABUTMENT ;
    PORT
      LAYER M5 ;
      RECT 383.112 777.408 383.136 777.600 ;
    END
  END tx_flit[923]
  PIN tx_flit[924]
    DIRECTION INPUT ;
    USE SIGNAL ;
    SHAPE ABUTMENT ;
    PORT
      LAYER M5 ;
      RECT 383.160 777.408 383.184 777.600 ;
    END
  END tx_flit[924]
  PIN tx_flit[925]
    DIRECTION INPUT ;
    USE SIGNAL ;
    SHAPE ABUTMENT ;
    PORT
      LAYER M5 ;
      RECT 383.208 777.408 383.232 777.600 ;
    END
  END tx_flit[925]
  PIN tx_flit[926]
    DIRECTION INPUT ;
    USE SIGNAL ;
    SHAPE ABUTMENT ;
    PORT
      LAYER M5 ;
      RECT 383.256 777.408 383.280 777.600 ;
    END
  END tx_flit[926]
  PIN tx_flit[927]
    DIRECTION INPUT ;
    USE SIGNAL ;
    SHAPE ABUTMENT ;
    PORT
      LAYER M5 ;
      RECT 383.304 777.408 383.328 777.600 ;
    END
  END tx_flit[927]
  PIN tx_flit[928]
    DIRECTION INPUT ;
    USE SIGNAL ;
    SHAPE ABUTMENT ;
    PORT
      LAYER M5 ;
      RECT 383.352 777.408 383.376 777.600 ;
    END
  END tx_flit[928]
  PIN tx_flit[929]
    DIRECTION INPUT ;
    USE SIGNAL ;
    SHAPE ABUTMENT ;
    PORT
      LAYER M5 ;
      RECT 383.400 777.408 383.424 777.600 ;
    END
  END tx_flit[929]
  PIN tx_flit[930]
    DIRECTION INPUT ;
    USE SIGNAL ;
    SHAPE ABUTMENT ;
    PORT
      LAYER M5 ;
      RECT 383.448 777.408 383.472 777.600 ;
    END
  END tx_flit[930]
  PIN tx_flit[931]
    DIRECTION INPUT ;
    USE SIGNAL ;
    SHAPE ABUTMENT ;
    PORT
      LAYER M5 ;
      RECT 383.496 777.408 383.520 777.600 ;
    END
  END tx_flit[931]
  PIN tx_flit[932]
    DIRECTION INPUT ;
    USE SIGNAL ;
    SHAPE ABUTMENT ;
    PORT
      LAYER M5 ;
      RECT 383.544 777.408 383.568 777.600 ;
    END
  END tx_flit[932]
  PIN tx_flit[933]
    DIRECTION INPUT ;
    USE SIGNAL ;
    SHAPE ABUTMENT ;
    PORT
      LAYER M5 ;
      RECT 383.592 777.408 383.616 777.600 ;
    END
  END tx_flit[933]
  PIN tx_flit[934]
    DIRECTION INPUT ;
    USE SIGNAL ;
    SHAPE ABUTMENT ;
    PORT
      LAYER M5 ;
      RECT 383.640 777.408 383.664 777.600 ;
    END
  END tx_flit[934]
  PIN tx_flit[935]
    DIRECTION INPUT ;
    USE SIGNAL ;
    SHAPE ABUTMENT ;
    PORT
      LAYER M5 ;
      RECT 383.688 777.408 383.712 777.600 ;
    END
  END tx_flit[935]
  PIN tx_flit[936]
    DIRECTION INPUT ;
    USE SIGNAL ;
    SHAPE ABUTMENT ;
    PORT
      LAYER M5 ;
      RECT 383.736 777.408 383.760 777.600 ;
    END
  END tx_flit[936]
  PIN tx_flit[937]
    DIRECTION INPUT ;
    USE SIGNAL ;
    SHAPE ABUTMENT ;
    PORT
      LAYER M5 ;
      RECT 383.784 777.408 383.808 777.600 ;
    END
  END tx_flit[937]
  PIN tx_flit[938]
    DIRECTION INPUT ;
    USE SIGNAL ;
    SHAPE ABUTMENT ;
    PORT
      LAYER M5 ;
      RECT 383.832 777.408 383.856 777.600 ;
    END
  END tx_flit[938]
  PIN tx_flit[939]
    DIRECTION INPUT ;
    USE SIGNAL ;
    SHAPE ABUTMENT ;
    PORT
      LAYER M5 ;
      RECT 383.880 777.408 383.904 777.600 ;
    END
  END tx_flit[939]
  PIN tx_flit[940]
    DIRECTION INPUT ;
    USE SIGNAL ;
    SHAPE ABUTMENT ;
    PORT
      LAYER M5 ;
      RECT 383.928 777.408 383.952 777.600 ;
    END
  END tx_flit[940]
  PIN tx_flit[941]
    DIRECTION INPUT ;
    USE SIGNAL ;
    SHAPE ABUTMENT ;
    PORT
      LAYER M5 ;
      RECT 383.976 777.408 384.000 777.600 ;
    END
  END tx_flit[941]
  PIN tx_flit[942]
    DIRECTION INPUT ;
    USE SIGNAL ;
    SHAPE ABUTMENT ;
    PORT
      LAYER M5 ;
      RECT 384.024 777.408 384.048 777.600 ;
    END
  END tx_flit[942]
  PIN tx_flit[943]
    DIRECTION INPUT ;
    USE SIGNAL ;
    SHAPE ABUTMENT ;
    PORT
      LAYER M5 ;
      RECT 384.072 777.408 384.096 777.600 ;
    END
  END tx_flit[943]
  PIN tx_flit[944]
    DIRECTION INPUT ;
    USE SIGNAL ;
    SHAPE ABUTMENT ;
    PORT
      LAYER M5 ;
      RECT 384.120 777.408 384.144 777.600 ;
    END
  END tx_flit[944]
  PIN tx_flit[945]
    DIRECTION INPUT ;
    USE SIGNAL ;
    SHAPE ABUTMENT ;
    PORT
      LAYER M5 ;
      RECT 384.168 777.408 384.192 777.600 ;
    END
  END tx_flit[945]
  PIN tx_flit[946]
    DIRECTION INPUT ;
    USE SIGNAL ;
    SHAPE ABUTMENT ;
    PORT
      LAYER M5 ;
      RECT 384.216 777.408 384.240 777.600 ;
    END
  END tx_flit[946]
  PIN tx_flit[947]
    DIRECTION INPUT ;
    USE SIGNAL ;
    SHAPE ABUTMENT ;
    PORT
      LAYER M5 ;
      RECT 384.264 777.408 384.288 777.600 ;
    END
  END tx_flit[947]
  PIN tx_flit[948]
    DIRECTION INPUT ;
    USE SIGNAL ;
    SHAPE ABUTMENT ;
    PORT
      LAYER M5 ;
      RECT 384.312 777.408 384.336 777.600 ;
    END
  END tx_flit[948]
  PIN tx_flit[949]
    DIRECTION INPUT ;
    USE SIGNAL ;
    SHAPE ABUTMENT ;
    PORT
      LAYER M5 ;
      RECT 384.360 777.408 384.384 777.600 ;
    END
  END tx_flit[949]
  PIN tx_flit[950]
    DIRECTION INPUT ;
    USE SIGNAL ;
    SHAPE ABUTMENT ;
    PORT
      LAYER M5 ;
      RECT 384.408 777.408 384.432 777.600 ;
    END
  END tx_flit[950]
  PIN tx_flit[951]
    DIRECTION INPUT ;
    USE SIGNAL ;
    SHAPE ABUTMENT ;
    PORT
      LAYER M5 ;
      RECT 384.456 777.408 384.480 777.600 ;
    END
  END tx_flit[951]
  PIN tx_flit[952]
    DIRECTION INPUT ;
    USE SIGNAL ;
    SHAPE ABUTMENT ;
    PORT
      LAYER M5 ;
      RECT 384.504 777.408 384.528 777.600 ;
    END
  END tx_flit[952]
  PIN tx_flit[953]
    DIRECTION INPUT ;
    USE SIGNAL ;
    SHAPE ABUTMENT ;
    PORT
      LAYER M5 ;
      RECT 384.552 777.408 384.576 777.600 ;
    END
  END tx_flit[953]
  PIN tx_flit[954]
    DIRECTION INPUT ;
    USE SIGNAL ;
    SHAPE ABUTMENT ;
    PORT
      LAYER M5 ;
      RECT 384.600 777.408 384.624 777.600 ;
    END
  END tx_flit[954]
  PIN tx_flit[955]
    DIRECTION INPUT ;
    USE SIGNAL ;
    SHAPE ABUTMENT ;
    PORT
      LAYER M5 ;
      RECT 384.648 777.408 384.672 777.600 ;
    END
  END tx_flit[955]
  PIN tx_flit[956]
    DIRECTION INPUT ;
    USE SIGNAL ;
    SHAPE ABUTMENT ;
    PORT
      LAYER M5 ;
      RECT 384.696 777.408 384.720 777.600 ;
    END
  END tx_flit[956]
  PIN tx_flit[957]
    DIRECTION INPUT ;
    USE SIGNAL ;
    SHAPE ABUTMENT ;
    PORT
      LAYER M5 ;
      RECT 384.744 777.408 384.768 777.600 ;
    END
  END tx_flit[957]
  PIN tx_flit[958]
    DIRECTION INPUT ;
    USE SIGNAL ;
    SHAPE ABUTMENT ;
    PORT
      LAYER M5 ;
      RECT 384.792 777.408 384.816 777.600 ;
    END
  END tx_flit[958]
  PIN tx_flit[959]
    DIRECTION INPUT ;
    USE SIGNAL ;
    SHAPE ABUTMENT ;
    PORT
      LAYER M5 ;
      RECT 384.840 777.408 384.864 777.600 ;
    END
  END tx_flit[959]
  PIN tx_flit[960]
    DIRECTION INPUT ;
    USE SIGNAL ;
    SHAPE ABUTMENT ;
    PORT
      LAYER M5 ;
      RECT 384.888 777.408 384.912 777.600 ;
    END
  END tx_flit[960]
  PIN tx_flit[961]
    DIRECTION INPUT ;
    USE SIGNAL ;
    SHAPE ABUTMENT ;
    PORT
      LAYER M5 ;
      RECT 384.936 777.408 384.960 777.600 ;
    END
  END tx_flit[961]
  PIN tx_flit[962]
    DIRECTION INPUT ;
    USE SIGNAL ;
    SHAPE ABUTMENT ;
    PORT
      LAYER M5 ;
      RECT 384.984 777.408 385.008 777.600 ;
    END
  END tx_flit[962]
  PIN tx_flit[963]
    DIRECTION INPUT ;
    USE SIGNAL ;
    SHAPE ABUTMENT ;
    PORT
      LAYER M5 ;
      RECT 385.032 777.408 385.056 777.600 ;
    END
  END tx_flit[963]
  PIN tx_flit[964]
    DIRECTION INPUT ;
    USE SIGNAL ;
    SHAPE ABUTMENT ;
    PORT
      LAYER M5 ;
      RECT 385.080 777.408 385.104 777.600 ;
    END
  END tx_flit[964]
  PIN tx_flit[965]
    DIRECTION INPUT ;
    USE SIGNAL ;
    SHAPE ABUTMENT ;
    PORT
      LAYER M5 ;
      RECT 385.128 777.408 385.152 777.600 ;
    END
  END tx_flit[965]
  PIN tx_flit[966]
    DIRECTION INPUT ;
    USE SIGNAL ;
    SHAPE ABUTMENT ;
    PORT
      LAYER M5 ;
      RECT 385.176 777.408 385.200 777.600 ;
    END
  END tx_flit[966]
  PIN tx_flit[967]
    DIRECTION INPUT ;
    USE SIGNAL ;
    SHAPE ABUTMENT ;
    PORT
      LAYER M5 ;
      RECT 385.224 777.408 385.248 777.600 ;
    END
  END tx_flit[967]
  PIN tx_flit[968]
    DIRECTION INPUT ;
    USE SIGNAL ;
    SHAPE ABUTMENT ;
    PORT
      LAYER M5 ;
      RECT 385.272 777.408 385.296 777.600 ;
    END
  END tx_flit[968]
  PIN tx_flit[969]
    DIRECTION INPUT ;
    USE SIGNAL ;
    SHAPE ABUTMENT ;
    PORT
      LAYER M5 ;
      RECT 385.320 777.408 385.344 777.600 ;
    END
  END tx_flit[969]
  PIN tx_flit[970]
    DIRECTION INPUT ;
    USE SIGNAL ;
    SHAPE ABUTMENT ;
    PORT
      LAYER M5 ;
      RECT 385.368 777.408 385.392 777.600 ;
    END
  END tx_flit[970]
  PIN tx_flit[971]
    DIRECTION INPUT ;
    USE SIGNAL ;
    SHAPE ABUTMENT ;
    PORT
      LAYER M5 ;
      RECT 385.416 777.408 385.440 777.600 ;
    END
  END tx_flit[971]
  PIN tx_flit[972]
    DIRECTION INPUT ;
    USE SIGNAL ;
    SHAPE ABUTMENT ;
    PORT
      LAYER M5 ;
      RECT 385.464 777.408 385.488 777.600 ;
    END
  END tx_flit[972]
  PIN tx_flit[973]
    DIRECTION INPUT ;
    USE SIGNAL ;
    SHAPE ABUTMENT ;
    PORT
      LAYER M5 ;
      RECT 385.512 777.408 385.536 777.600 ;
    END
  END tx_flit[973]
  PIN tx_flit[974]
    DIRECTION INPUT ;
    USE SIGNAL ;
    SHAPE ABUTMENT ;
    PORT
      LAYER M5 ;
      RECT 385.560 777.408 385.584 777.600 ;
    END
  END tx_flit[974]
  PIN tx_flit[975]
    DIRECTION INPUT ;
    USE SIGNAL ;
    SHAPE ABUTMENT ;
    PORT
      LAYER M5 ;
      RECT 385.608 777.408 385.632 777.600 ;
    END
  END tx_flit[975]
  PIN tx_flit[976]
    DIRECTION INPUT ;
    USE SIGNAL ;
    SHAPE ABUTMENT ;
    PORT
      LAYER M5 ;
      RECT 385.656 777.408 385.680 777.600 ;
    END
  END tx_flit[976]
  PIN tx_flit[977]
    DIRECTION INPUT ;
    USE SIGNAL ;
    SHAPE ABUTMENT ;
    PORT
      LAYER M5 ;
      RECT 385.704 777.408 385.728 777.600 ;
    END
  END tx_flit[977]
  PIN tx_flit[978]
    DIRECTION INPUT ;
    USE SIGNAL ;
    SHAPE ABUTMENT ;
    PORT
      LAYER M5 ;
      RECT 385.752 777.408 385.776 777.600 ;
    END
  END tx_flit[978]
  PIN tx_flit[979]
    DIRECTION INPUT ;
    USE SIGNAL ;
    SHAPE ABUTMENT ;
    PORT
      LAYER M5 ;
      RECT 385.800 777.408 385.824 777.600 ;
    END
  END tx_flit[979]
  PIN tx_flit[980]
    DIRECTION INPUT ;
    USE SIGNAL ;
    SHAPE ABUTMENT ;
    PORT
      LAYER M5 ;
      RECT 385.848 777.408 385.872 777.600 ;
    END
  END tx_flit[980]
  PIN tx_flit[981]
    DIRECTION INPUT ;
    USE SIGNAL ;
    SHAPE ABUTMENT ;
    PORT
      LAYER M5 ;
      RECT 385.896 777.408 385.920 777.600 ;
    END
  END tx_flit[981]
  PIN tx_flit[982]
    DIRECTION INPUT ;
    USE SIGNAL ;
    SHAPE ABUTMENT ;
    PORT
      LAYER M5 ;
      RECT 385.944 777.408 385.968 777.600 ;
    END
  END tx_flit[982]
  PIN tx_flit[983]
    DIRECTION INPUT ;
    USE SIGNAL ;
    SHAPE ABUTMENT ;
    PORT
      LAYER M5 ;
      RECT 385.992 777.408 386.016 777.600 ;
    END
  END tx_flit[983]
  PIN tx_flit[984]
    DIRECTION INPUT ;
    USE SIGNAL ;
    SHAPE ABUTMENT ;
    PORT
      LAYER M5 ;
      RECT 386.040 777.408 386.064 777.600 ;
    END
  END tx_flit[984]
  PIN tx_flit[985]
    DIRECTION INPUT ;
    USE SIGNAL ;
    SHAPE ABUTMENT ;
    PORT
      LAYER M5 ;
      RECT 386.088 777.408 386.112 777.600 ;
    END
  END tx_flit[985]
  PIN tx_flit[986]
    DIRECTION INPUT ;
    USE SIGNAL ;
    SHAPE ABUTMENT ;
    PORT
      LAYER M5 ;
      RECT 386.136 777.408 386.160 777.600 ;
    END
  END tx_flit[986]
  PIN tx_flit[987]
    DIRECTION INPUT ;
    USE SIGNAL ;
    SHAPE ABUTMENT ;
    PORT
      LAYER M5 ;
      RECT 386.184 777.408 386.208 777.600 ;
    END
  END tx_flit[987]
  PIN tx_flit[988]
    DIRECTION INPUT ;
    USE SIGNAL ;
    SHAPE ABUTMENT ;
    PORT
      LAYER M5 ;
      RECT 386.232 777.408 386.256 777.600 ;
    END
  END tx_flit[988]
  PIN tx_flit[989]
    DIRECTION INPUT ;
    USE SIGNAL ;
    SHAPE ABUTMENT ;
    PORT
      LAYER M5 ;
      RECT 386.280 777.408 386.304 777.600 ;
    END
  END tx_flit[989]
  PIN tx_flit[990]
    DIRECTION INPUT ;
    USE SIGNAL ;
    SHAPE ABUTMENT ;
    PORT
      LAYER M5 ;
      RECT 386.328 777.408 386.352 777.600 ;
    END
  END tx_flit[990]
  PIN tx_flit[991]
    DIRECTION INPUT ;
    USE SIGNAL ;
    SHAPE ABUTMENT ;
    PORT
      LAYER M5 ;
      RECT 386.376 777.408 386.400 777.600 ;
    END
  END tx_flit[991]
  PIN tx_flit[992]
    DIRECTION INPUT ;
    USE SIGNAL ;
    SHAPE ABUTMENT ;
    PORT
      LAYER M5 ;
      RECT 386.424 777.408 386.448 777.600 ;
    END
  END tx_flit[992]
  PIN tx_flit[993]
    DIRECTION INPUT ;
    USE SIGNAL ;
    SHAPE ABUTMENT ;
    PORT
      LAYER M5 ;
      RECT 386.472 777.408 386.496 777.600 ;
    END
  END tx_flit[993]
  PIN tx_flit[994]
    DIRECTION INPUT ;
    USE SIGNAL ;
    SHAPE ABUTMENT ;
    PORT
      LAYER M5 ;
      RECT 386.520 777.408 386.544 777.600 ;
    END
  END tx_flit[994]
  PIN tx_flit[995]
    DIRECTION INPUT ;
    USE SIGNAL ;
    SHAPE ABUTMENT ;
    PORT
      LAYER M5 ;
      RECT 386.568 777.408 386.592 777.600 ;
    END
  END tx_flit[995]
  PIN tx_flit[996]
    DIRECTION INPUT ;
    USE SIGNAL ;
    SHAPE ABUTMENT ;
    PORT
      LAYER M5 ;
      RECT 386.616 777.408 386.640 777.600 ;
    END
  END tx_flit[996]
  PIN tx_flit[997]
    DIRECTION INPUT ;
    USE SIGNAL ;
    SHAPE ABUTMENT ;
    PORT
      LAYER M5 ;
      RECT 386.664 777.408 386.688 777.600 ;
    END
  END tx_flit[997]
  PIN tx_flit[998]
    DIRECTION INPUT ;
    USE SIGNAL ;
    SHAPE ABUTMENT ;
    PORT
      LAYER M5 ;
      RECT 386.712 777.408 386.736 777.600 ;
    END
  END tx_flit[998]
  PIN tx_flit[999]
    DIRECTION INPUT ;
    USE SIGNAL ;
    SHAPE ABUTMENT ;
    PORT
      LAYER M5 ;
      RECT 386.760 777.408 386.784 777.600 ;
    END
  END tx_flit[999]
  PIN tx_flit[1000]
    DIRECTION INPUT ;
    USE SIGNAL ;
    SHAPE ABUTMENT ;
    PORT
      LAYER M5 ;
      RECT 386.808 777.408 386.832 777.600 ;
    END
  END tx_flit[1000]
  PIN tx_flit[1001]
    DIRECTION INPUT ;
    USE SIGNAL ;
    SHAPE ABUTMENT ;
    PORT
      LAYER M5 ;
      RECT 386.856 777.408 386.880 777.600 ;
    END
  END tx_flit[1001]
  PIN tx_flit[1002]
    DIRECTION INPUT ;
    USE SIGNAL ;
    SHAPE ABUTMENT ;
    PORT
      LAYER M5 ;
      RECT 386.904 777.408 386.928 777.600 ;
    END
  END tx_flit[1002]
  PIN tx_flit[1003]
    DIRECTION INPUT ;
    USE SIGNAL ;
    SHAPE ABUTMENT ;
    PORT
      LAYER M5 ;
      RECT 386.952 777.408 386.976 777.600 ;
    END
  END tx_flit[1003]
  PIN tx_flit[1004]
    DIRECTION INPUT ;
    USE SIGNAL ;
    SHAPE ABUTMENT ;
    PORT
      LAYER M5 ;
      RECT 387.000 777.408 387.024 777.600 ;
    END
  END tx_flit[1004]
  PIN tx_flit[1005]
    DIRECTION INPUT ;
    USE SIGNAL ;
    SHAPE ABUTMENT ;
    PORT
      LAYER M5 ;
      RECT 387.048 777.408 387.072 777.600 ;
    END
  END tx_flit[1005]
  PIN tx_flit[1006]
    DIRECTION INPUT ;
    USE SIGNAL ;
    SHAPE ABUTMENT ;
    PORT
      LAYER M5 ;
      RECT 387.096 777.408 387.120 777.600 ;
    END
  END tx_flit[1006]
  PIN tx_flit[1007]
    DIRECTION INPUT ;
    USE SIGNAL ;
    SHAPE ABUTMENT ;
    PORT
      LAYER M5 ;
      RECT 387.144 777.408 387.168 777.600 ;
    END
  END tx_flit[1007]
  PIN tx_flit[1008]
    DIRECTION INPUT ;
    USE SIGNAL ;
    SHAPE ABUTMENT ;
    PORT
      LAYER M5 ;
      RECT 387.192 777.408 387.216 777.600 ;
    END
  END tx_flit[1008]
  PIN tx_flit[1009]
    DIRECTION INPUT ;
    USE SIGNAL ;
    SHAPE ABUTMENT ;
    PORT
      LAYER M5 ;
      RECT 387.240 777.408 387.264 777.600 ;
    END
  END tx_flit[1009]
  PIN tx_flit[1010]
    DIRECTION INPUT ;
    USE SIGNAL ;
    SHAPE ABUTMENT ;
    PORT
      LAYER M5 ;
      RECT 387.288 777.408 387.312 777.600 ;
    END
  END tx_flit[1010]
  PIN tx_flit[1011]
    DIRECTION INPUT ;
    USE SIGNAL ;
    SHAPE ABUTMENT ;
    PORT
      LAYER M5 ;
      RECT 387.336 777.408 387.360 777.600 ;
    END
  END tx_flit[1011]
  PIN tx_flit[1012]
    DIRECTION INPUT ;
    USE SIGNAL ;
    SHAPE ABUTMENT ;
    PORT
      LAYER M5 ;
      RECT 387.384 777.408 387.408 777.600 ;
    END
  END tx_flit[1012]
  PIN tx_flit[1013]
    DIRECTION INPUT ;
    USE SIGNAL ;
    SHAPE ABUTMENT ;
    PORT
      LAYER M5 ;
      RECT 387.432 777.408 387.456 777.600 ;
    END
  END tx_flit[1013]
  PIN tx_flit[1014]
    DIRECTION INPUT ;
    USE SIGNAL ;
    SHAPE ABUTMENT ;
    PORT
      LAYER M5 ;
      RECT 387.480 777.408 387.504 777.600 ;
    END
  END tx_flit[1014]
  PIN tx_flit[1015]
    DIRECTION INPUT ;
    USE SIGNAL ;
    SHAPE ABUTMENT ;
    PORT
      LAYER M5 ;
      RECT 387.528 777.408 387.552 777.600 ;
    END
  END tx_flit[1015]
  PIN tx_flit[1016]
    DIRECTION INPUT ;
    USE SIGNAL ;
    SHAPE ABUTMENT ;
    PORT
      LAYER M5 ;
      RECT 387.576 777.408 387.600 777.600 ;
    END
  END tx_flit[1016]
  PIN tx_flit[1017]
    DIRECTION INPUT ;
    USE SIGNAL ;
    SHAPE ABUTMENT ;
    PORT
      LAYER M5 ;
      RECT 387.624 777.408 387.648 777.600 ;
    END
  END tx_flit[1017]
  PIN tx_flit[1018]
    DIRECTION INPUT ;
    USE SIGNAL ;
    SHAPE ABUTMENT ;
    PORT
      LAYER M5 ;
      RECT 387.672 777.408 387.696 777.600 ;
    END
  END tx_flit[1018]
  PIN tx_flit[1019]
    DIRECTION INPUT ;
    USE SIGNAL ;
    SHAPE ABUTMENT ;
    PORT
      LAYER M5 ;
      RECT 387.720 777.408 387.744 777.600 ;
    END
  END tx_flit[1019]
  PIN tx_flit[1020]
    DIRECTION INPUT ;
    USE SIGNAL ;
    SHAPE ABUTMENT ;
    PORT
      LAYER M5 ;
      RECT 387.768 777.408 387.792 777.600 ;
    END
  END tx_flit[1020]
  PIN tx_flit[1021]
    DIRECTION INPUT ;
    USE SIGNAL ;
    SHAPE ABUTMENT ;
    PORT
      LAYER M5 ;
      RECT 387.816 777.408 387.840 777.600 ;
    END
  END tx_flit[1021]
  PIN tx_flit[1022]
    DIRECTION INPUT ;
    USE SIGNAL ;
    SHAPE ABUTMENT ;
    PORT
      LAYER M5 ;
      RECT 387.864 777.408 387.888 777.600 ;
    END
  END tx_flit[1022]
  PIN tx_flit[1023]
    DIRECTION INPUT ;
    USE SIGNAL ;
    SHAPE ABUTMENT ;
    PORT
      LAYER M5 ;
      RECT 387.912 777.408 387.936 777.600 ;
    END
  END tx_flit[1023]
  PIN tx_flit[1024]
    DIRECTION INPUT ;
    USE SIGNAL ;
    SHAPE ABUTMENT ;
    PORT
      LAYER M5 ;
      RECT 387.960 777.408 387.984 777.600 ;
    END
  END tx_flit[1024]
  PIN tx_flit[1025]
    DIRECTION INPUT ;
    USE SIGNAL ;
    SHAPE ABUTMENT ;
    PORT
      LAYER M5 ;
      RECT 388.008 777.408 388.032 777.600 ;
    END
  END tx_flit[1025]
  PIN tx_flit[1026]
    DIRECTION INPUT ;
    USE SIGNAL ;
    SHAPE ABUTMENT ;
    PORT
      LAYER M5 ;
      RECT 388.056 777.408 388.080 777.600 ;
    END
  END tx_flit[1026]
  PIN tx_flit[1027]
    DIRECTION INPUT ;
    USE SIGNAL ;
    SHAPE ABUTMENT ;
    PORT
      LAYER M5 ;
      RECT 388.104 777.408 388.128 777.600 ;
    END
  END tx_flit[1027]
  PIN tx_flit[1028]
    DIRECTION INPUT ;
    USE SIGNAL ;
    SHAPE ABUTMENT ;
    PORT
      LAYER M5 ;
      RECT 388.152 777.408 388.176 777.600 ;
    END
  END tx_flit[1028]
  PIN tx_flit[1029]
    DIRECTION INPUT ;
    USE SIGNAL ;
    SHAPE ABUTMENT ;
    PORT
      LAYER M5 ;
      RECT 388.200 777.408 388.224 777.600 ;
    END
  END tx_flit[1029]
  PIN tx_flit[1030]
    DIRECTION INPUT ;
    USE SIGNAL ;
    SHAPE ABUTMENT ;
    PORT
      LAYER M5 ;
      RECT 388.248 777.408 388.272 777.600 ;
    END
  END tx_flit[1030]
  PIN tx_flit[1031]
    DIRECTION INPUT ;
    USE SIGNAL ;
    SHAPE ABUTMENT ;
    PORT
      LAYER M5 ;
      RECT 388.296 777.408 388.320 777.600 ;
    END
  END tx_flit[1031]
  PIN tx_flit[1032]
    DIRECTION INPUT ;
    USE SIGNAL ;
    SHAPE ABUTMENT ;
    PORT
      LAYER M5 ;
      RECT 388.344 777.408 388.368 777.600 ;
    END
  END tx_flit[1032]
  PIN tx_flit[1033]
    DIRECTION INPUT ;
    USE SIGNAL ;
    SHAPE ABUTMENT ;
    PORT
      LAYER M5 ;
      RECT 388.392 777.408 388.416 777.600 ;
    END
  END tx_flit[1033]
  PIN tx_flit[1034]
    DIRECTION INPUT ;
    USE SIGNAL ;
    SHAPE ABUTMENT ;
    PORT
      LAYER M5 ;
      RECT 388.440 777.408 388.464 777.600 ;
    END
  END tx_flit[1034]
  PIN tx_flit[1035]
    DIRECTION INPUT ;
    USE SIGNAL ;
    SHAPE ABUTMENT ;
    PORT
      LAYER M5 ;
      RECT 388.488 777.408 388.512 777.600 ;
    END
  END tx_flit[1035]
  PIN tx_flit[1036]
    DIRECTION INPUT ;
    USE SIGNAL ;
    SHAPE ABUTMENT ;
    PORT
      LAYER M5 ;
      RECT 388.536 777.408 388.560 777.600 ;
    END
  END tx_flit[1036]
  PIN tx_flit[1037]
    DIRECTION INPUT ;
    USE SIGNAL ;
    SHAPE ABUTMENT ;
    PORT
      LAYER M5 ;
      RECT 388.584 777.408 388.608 777.600 ;
    END
  END tx_flit[1037]
  PIN tx_flit[1038]
    DIRECTION INPUT ;
    USE SIGNAL ;
    SHAPE ABUTMENT ;
    PORT
      LAYER M5 ;
      RECT 388.632 777.408 388.656 777.600 ;
    END
  END tx_flit[1038]
  PIN tx_flit[1039]
    DIRECTION INPUT ;
    USE SIGNAL ;
    SHAPE ABUTMENT ;
    PORT
      LAYER M5 ;
      RECT 388.680 777.408 388.704 777.600 ;
    END
  END tx_flit[1039]
  PIN tx_flit[1040]
    DIRECTION INPUT ;
    USE SIGNAL ;
    SHAPE ABUTMENT ;
    PORT
      LAYER M5 ;
      RECT 388.728 777.408 388.752 777.600 ;
    END
  END tx_flit[1040]
  PIN tx_flit[1041]
    DIRECTION INPUT ;
    USE SIGNAL ;
    SHAPE ABUTMENT ;
    PORT
      LAYER M5 ;
      RECT 388.776 777.408 388.800 777.600 ;
    END
  END tx_flit[1041]
  PIN tx_flit[1042]
    DIRECTION INPUT ;
    USE SIGNAL ;
    SHAPE ABUTMENT ;
    PORT
      LAYER M5 ;
      RECT 388.824 777.408 388.848 777.600 ;
    END
  END tx_flit[1042]
  PIN rx_v
    DIRECTION OUTPUT ;
    USE SIGNAL ;
    SHAPE ABUTMENT ;
    PORT
      LAYER M5 ;
      RECT 388.872 777.408 388.896 777.600 ;
    END
  END rx_v
  PIN rx_flit[0]
    DIRECTION OUTPUT ;
    USE SIGNAL ;
    SHAPE ABUTMENT ;
    PORT
      LAYER M5 ;
      RECT 388.920 777.408 388.944 777.600 ;
    END
  END rx_flit[0]
  PIN rx_flit[1]
    DIRECTION OUTPUT ;
    USE SIGNAL ;
    SHAPE ABUTMENT ;
    PORT
      LAYER M5 ;
      RECT 388.968 777.408 388.992 777.600 ;
    END
  END rx_flit[1]
  PIN rx_flit[2]
    DIRECTION OUTPUT ;
    USE SIGNAL ;
    SHAPE ABUTMENT ;
    PORT
      LAYER M5 ;
      RECT 389.016 777.408 389.040 777.600 ;
    END
  END rx_flit[2]
  PIN rx_flit[3]
    DIRECTION OUTPUT ;
    USE SIGNAL ;
    SHAPE ABUTMENT ;
    PORT
      LAYER M5 ;
      RECT 389.064 777.408 389.088 777.600 ;
    END
  END rx_flit[3]
  PIN rx_flit[4]
    DIRECTION OUTPUT ;
    USE SIGNAL ;
    SHAPE ABUTMENT ;
    PORT
      LAYER M5 ;
      RECT 389.112 777.408 389.136 777.600 ;
    END
  END rx_flit[4]
  PIN rx_flit[5]
    DIRECTION OUTPUT ;
    USE SIGNAL ;
    SHAPE ABUTMENT ;
    PORT
      LAYER M5 ;
      RECT 389.160 777.408 389.184 777.600 ;
    END
  END rx_flit[5]
  PIN rx_flit[6]
    DIRECTION OUTPUT ;
    USE SIGNAL ;
    SHAPE ABUTMENT ;
    PORT
      LAYER M5 ;
      RECT 389.208 777.408 389.232 777.600 ;
    END
  END rx_flit[6]
  PIN rx_flit[7]
    DIRECTION OUTPUT ;
    USE SIGNAL ;
    SHAPE ABUTMENT ;
    PORT
      LAYER M5 ;
      RECT 389.256 777.408 389.280 777.600 ;
    END
  END rx_flit[7]
  PIN rx_flit[8]
    DIRECTION OUTPUT ;
    USE SIGNAL ;
    SHAPE ABUTMENT ;
    PORT
      LAYER M5 ;
      RECT 389.304 777.408 389.328 777.600 ;
    END
  END rx_flit[8]
  PIN rx_flit[9]
    DIRECTION OUTPUT ;
    USE SIGNAL ;
    SHAPE ABUTMENT ;
    PORT
      LAYER M5 ;
      RECT 389.352 777.408 389.376 777.600 ;
    END
  END rx_flit[9]
  PIN rx_flit[10]
    DIRECTION OUTPUT ;
    USE SIGNAL ;
    SHAPE ABUTMENT ;
    PORT
      LAYER M5 ;
      RECT 389.400 777.408 389.424 777.600 ;
    END
  END rx_flit[10]
  PIN rx_flit[11]
    DIRECTION OUTPUT ;
    USE SIGNAL ;
    SHAPE ABUTMENT ;
    PORT
      LAYER M5 ;
      RECT 389.448 777.408 389.472 777.600 ;
    END
  END rx_flit[11]
  PIN rx_flit[12]
    DIRECTION OUTPUT ;
    USE SIGNAL ;
    SHAPE ABUTMENT ;
    PORT
      LAYER M5 ;
      RECT 389.496 777.408 389.520 777.600 ;
    END
  END rx_flit[12]
  PIN rx_flit[13]
    DIRECTION OUTPUT ;
    USE SIGNAL ;
    SHAPE ABUTMENT ;
    PORT
      LAYER M5 ;
      RECT 389.544 777.408 389.568 777.600 ;
    END
  END rx_flit[13]
  PIN rx_flit[14]
    DIRECTION OUTPUT ;
    USE SIGNAL ;
    SHAPE ABUTMENT ;
    PORT
      LAYER M5 ;
      RECT 389.592 777.408 389.616 777.600 ;
    END
  END rx_flit[14]
  PIN rx_flit[15]
    DIRECTION OUTPUT ;
    USE SIGNAL ;
    SHAPE ABUTMENT ;
    PORT
      LAYER M5 ;
      RECT 389.640 777.408 389.664 777.600 ;
    END
  END rx_flit[15]
  PIN rx_flit[16]
    DIRECTION OUTPUT ;
    USE SIGNAL ;
    SHAPE ABUTMENT ;
    PORT
      LAYER M5 ;
      RECT 389.688 777.408 389.712 777.600 ;
    END
  END rx_flit[16]
  PIN rx_flit[17]
    DIRECTION OUTPUT ;
    USE SIGNAL ;
    SHAPE ABUTMENT ;
    PORT
      LAYER M5 ;
      RECT 389.736 777.408 389.760 777.600 ;
    END
  END rx_flit[17]
  PIN rx_flit[18]
    DIRECTION OUTPUT ;
    USE SIGNAL ;
    SHAPE ABUTMENT ;
    PORT
      LAYER M5 ;
      RECT 389.784 777.408 389.808 777.600 ;
    END
  END rx_flit[18]
  PIN rx_flit[19]
    DIRECTION OUTPUT ;
    USE SIGNAL ;
    SHAPE ABUTMENT ;
    PORT
      LAYER M5 ;
      RECT 389.832 777.408 389.856 777.600 ;
    END
  END rx_flit[19]
  PIN rx_flit[20]
    DIRECTION OUTPUT ;
    USE SIGNAL ;
    SHAPE ABUTMENT ;
    PORT
      LAYER M5 ;
      RECT 389.880 777.408 389.904 777.600 ;
    END
  END rx_flit[20]
  PIN rx_flit[21]
    DIRECTION OUTPUT ;
    USE SIGNAL ;
    SHAPE ABUTMENT ;
    PORT
      LAYER M5 ;
      RECT 389.928 777.408 389.952 777.600 ;
    END
  END rx_flit[21]
  PIN rx_flit[22]
    DIRECTION OUTPUT ;
    USE SIGNAL ;
    SHAPE ABUTMENT ;
    PORT
      LAYER M5 ;
      RECT 389.976 777.408 390.000 777.600 ;
    END
  END rx_flit[22]
  PIN rx_flit[23]
    DIRECTION OUTPUT ;
    USE SIGNAL ;
    SHAPE ABUTMENT ;
    PORT
      LAYER M5 ;
      RECT 390.024 777.408 390.048 777.600 ;
    END
  END rx_flit[23]
  PIN rx_flit[24]
    DIRECTION OUTPUT ;
    USE SIGNAL ;
    SHAPE ABUTMENT ;
    PORT
      LAYER M5 ;
      RECT 390.072 777.408 390.096 777.600 ;
    END
  END rx_flit[24]
  PIN rx_flit[25]
    DIRECTION OUTPUT ;
    USE SIGNAL ;
    SHAPE ABUTMENT ;
    PORT
      LAYER M5 ;
      RECT 390.120 777.408 390.144 777.600 ;
    END
  END rx_flit[25]
  PIN rx_flit[26]
    DIRECTION OUTPUT ;
    USE SIGNAL ;
    SHAPE ABUTMENT ;
    PORT
      LAYER M5 ;
      RECT 390.168 777.408 390.192 777.600 ;
    END
  END rx_flit[26]
  PIN rx_flit[27]
    DIRECTION OUTPUT ;
    USE SIGNAL ;
    SHAPE ABUTMENT ;
    PORT
      LAYER M5 ;
      RECT 390.216 777.408 390.240 777.600 ;
    END
  END rx_flit[27]
  PIN rx_flit[28]
    DIRECTION OUTPUT ;
    USE SIGNAL ;
    SHAPE ABUTMENT ;
    PORT
      LAYER M5 ;
      RECT 390.264 777.408 390.288 777.600 ;
    END
  END rx_flit[28]
  PIN rx_flit[29]
    DIRECTION OUTPUT ;
    USE SIGNAL ;
    SHAPE ABUTMENT ;
    PORT
      LAYER M5 ;
      RECT 390.312 777.408 390.336 777.600 ;
    END
  END rx_flit[29]
  PIN rx_flit[30]
    DIRECTION OUTPUT ;
    USE SIGNAL ;
    SHAPE ABUTMENT ;
    PORT
      LAYER M5 ;
      RECT 390.360 777.408 390.384 777.600 ;
    END
  END rx_flit[30]
  PIN rx_flit[31]
    DIRECTION OUTPUT ;
    USE SIGNAL ;
    SHAPE ABUTMENT ;
    PORT
      LAYER M5 ;
      RECT 390.408 777.408 390.432 777.600 ;
    END
  END rx_flit[31]
  PIN rx_flit[32]
    DIRECTION OUTPUT ;
    USE SIGNAL ;
    SHAPE ABUTMENT ;
    PORT
      LAYER M5 ;
      RECT 390.456 777.408 390.480 777.600 ;
    END
  END rx_flit[32]
  PIN rx_flit[33]
    DIRECTION OUTPUT ;
    USE SIGNAL ;
    SHAPE ABUTMENT ;
    PORT
      LAYER M5 ;
      RECT 390.504 777.408 390.528 777.600 ;
    END
  END rx_flit[33]
  PIN rx_flit[34]
    DIRECTION OUTPUT ;
    USE SIGNAL ;
    SHAPE ABUTMENT ;
    PORT
      LAYER M5 ;
      RECT 390.552 777.408 390.576 777.600 ;
    END
  END rx_flit[34]
  PIN rx_flit[35]
    DIRECTION OUTPUT ;
    USE SIGNAL ;
    SHAPE ABUTMENT ;
    PORT
      LAYER M5 ;
      RECT 390.600 777.408 390.624 777.600 ;
    END
  END rx_flit[35]
  PIN rx_flit[36]
    DIRECTION OUTPUT ;
    USE SIGNAL ;
    SHAPE ABUTMENT ;
    PORT
      LAYER M5 ;
      RECT 390.648 777.408 390.672 777.600 ;
    END
  END rx_flit[36]
  PIN rx_flit[37]
    DIRECTION OUTPUT ;
    USE SIGNAL ;
    SHAPE ABUTMENT ;
    PORT
      LAYER M5 ;
      RECT 390.696 777.408 390.720 777.600 ;
    END
  END rx_flit[37]
  PIN rx_flit[38]
    DIRECTION OUTPUT ;
    USE SIGNAL ;
    SHAPE ABUTMENT ;
    PORT
      LAYER M5 ;
      RECT 390.744 777.408 390.768 777.600 ;
    END
  END rx_flit[38]
  PIN rx_flit[39]
    DIRECTION OUTPUT ;
    USE SIGNAL ;
    SHAPE ABUTMENT ;
    PORT
      LAYER M5 ;
      RECT 390.792 777.408 390.816 777.600 ;
    END
  END rx_flit[39]
  PIN rx_flit[40]
    DIRECTION OUTPUT ;
    USE SIGNAL ;
    SHAPE ABUTMENT ;
    PORT
      LAYER M5 ;
      RECT 390.840 777.408 390.864 777.600 ;
    END
  END rx_flit[40]
  PIN rx_flit[41]
    DIRECTION OUTPUT ;
    USE SIGNAL ;
    SHAPE ABUTMENT ;
    PORT
      LAYER M5 ;
      RECT 390.888 777.408 390.912 777.600 ;
    END
  END rx_flit[41]
  PIN rx_flit[42]
    DIRECTION OUTPUT ;
    USE SIGNAL ;
    SHAPE ABUTMENT ;
    PORT
      LAYER M5 ;
      RECT 390.936 777.408 390.960 777.600 ;
    END
  END rx_flit[42]
  PIN rx_flit[43]
    DIRECTION OUTPUT ;
    USE SIGNAL ;
    SHAPE ABUTMENT ;
    PORT
      LAYER M5 ;
      RECT 390.984 777.408 391.008 777.600 ;
    END
  END rx_flit[43]
  PIN rx_flit[44]
    DIRECTION OUTPUT ;
    USE SIGNAL ;
    SHAPE ABUTMENT ;
    PORT
      LAYER M5 ;
      RECT 391.032 777.408 391.056 777.600 ;
    END
  END rx_flit[44]
  PIN rx_flit[45]
    DIRECTION OUTPUT ;
    USE SIGNAL ;
    SHAPE ABUTMENT ;
    PORT
      LAYER M5 ;
      RECT 391.080 777.408 391.104 777.600 ;
    END
  END rx_flit[45]
  PIN rx_flit[46]
    DIRECTION OUTPUT ;
    USE SIGNAL ;
    SHAPE ABUTMENT ;
    PORT
      LAYER M5 ;
      RECT 391.128 777.408 391.152 777.600 ;
    END
  END rx_flit[46]
  PIN rx_flit[47]
    DIRECTION OUTPUT ;
    USE SIGNAL ;
    SHAPE ABUTMENT ;
    PORT
      LAYER M5 ;
      RECT 391.176 777.408 391.200 777.600 ;
    END
  END rx_flit[47]
  PIN rx_flit[48]
    DIRECTION OUTPUT ;
    USE SIGNAL ;
    SHAPE ABUTMENT ;
    PORT
      LAYER M5 ;
      RECT 391.224 777.408 391.248 777.600 ;
    END
  END rx_flit[48]
  PIN rx_flit[49]
    DIRECTION OUTPUT ;
    USE SIGNAL ;
    SHAPE ABUTMENT ;
    PORT
      LAYER M5 ;
      RECT 391.272 777.408 391.296 777.600 ;
    END
  END rx_flit[49]
  PIN rx_flit[50]
    DIRECTION OUTPUT ;
    USE SIGNAL ;
    SHAPE ABUTMENT ;
    PORT
      LAYER M5 ;
      RECT 391.320 777.408 391.344 777.600 ;
    END
  END rx_flit[50]
  PIN rx_flit[51]
    DIRECTION OUTPUT ;
    USE SIGNAL ;
    SHAPE ABUTMENT ;
    PORT
      LAYER M5 ;
      RECT 391.368 777.408 391.392 777.600 ;
    END
  END rx_flit[51]
  PIN rx_flit[52]
    DIRECTION OUTPUT ;
    USE SIGNAL ;
    SHAPE ABUTMENT ;
    PORT
      LAYER M5 ;
      RECT 391.416 777.408 391.440 777.600 ;
    END
  END rx_flit[52]
  PIN rx_flit[53]
    DIRECTION OUTPUT ;
    USE SIGNAL ;
    SHAPE ABUTMENT ;
    PORT
      LAYER M5 ;
      RECT 391.464 777.408 391.488 777.600 ;
    END
  END rx_flit[53]
  PIN rx_flit[54]
    DIRECTION OUTPUT ;
    USE SIGNAL ;
    SHAPE ABUTMENT ;
    PORT
      LAYER M5 ;
      RECT 391.512 777.408 391.536 777.600 ;
    END
  END rx_flit[54]
  PIN rx_flit[55]
    DIRECTION OUTPUT ;
    USE SIGNAL ;
    SHAPE ABUTMENT ;
    PORT
      LAYER M5 ;
      RECT 391.560 777.408 391.584 777.600 ;
    END
  END rx_flit[55]
  PIN rx_flit[56]
    DIRECTION OUTPUT ;
    USE SIGNAL ;
    SHAPE ABUTMENT ;
    PORT
      LAYER M5 ;
      RECT 391.608 777.408 391.632 777.600 ;
    END
  END rx_flit[56]
  PIN rx_flit[57]
    DIRECTION OUTPUT ;
    USE SIGNAL ;
    SHAPE ABUTMENT ;
    PORT
      LAYER M5 ;
      RECT 391.656 777.408 391.680 777.600 ;
    END
  END rx_flit[57]
  PIN rx_flit[58]
    DIRECTION OUTPUT ;
    USE SIGNAL ;
    SHAPE ABUTMENT ;
    PORT
      LAYER M5 ;
      RECT 391.704 777.408 391.728 777.600 ;
    END
  END rx_flit[58]
  PIN rx_flit[59]
    DIRECTION OUTPUT ;
    USE SIGNAL ;
    SHAPE ABUTMENT ;
    PORT
      LAYER M5 ;
      RECT 391.752 777.408 391.776 777.600 ;
    END
  END rx_flit[59]
  PIN rx_flit[60]
    DIRECTION OUTPUT ;
    USE SIGNAL ;
    SHAPE ABUTMENT ;
    PORT
      LAYER M5 ;
      RECT 391.800 777.408 391.824 777.600 ;
    END
  END rx_flit[60]
  PIN rx_flit[61]
    DIRECTION OUTPUT ;
    USE SIGNAL ;
    SHAPE ABUTMENT ;
    PORT
      LAYER M5 ;
      RECT 391.848 777.408 391.872 777.600 ;
    END
  END rx_flit[61]
  PIN rx_flit[62]
    DIRECTION OUTPUT ;
    USE SIGNAL ;
    SHAPE ABUTMENT ;
    PORT
      LAYER M5 ;
      RECT 391.896 777.408 391.920 777.600 ;
    END
  END rx_flit[62]
  PIN rx_flit[63]
    DIRECTION OUTPUT ;
    USE SIGNAL ;
    SHAPE ABUTMENT ;
    PORT
      LAYER M5 ;
      RECT 391.944 777.408 391.968 777.600 ;
    END
  END rx_flit[63]
  PIN rx_flit[64]
    DIRECTION OUTPUT ;
    USE SIGNAL ;
    SHAPE ABUTMENT ;
    PORT
      LAYER M5 ;
      RECT 391.992 777.408 392.016 777.600 ;
    END
  END rx_flit[64]
  PIN rx_flit[65]
    DIRECTION OUTPUT ;
    USE SIGNAL ;
    SHAPE ABUTMENT ;
    PORT
      LAYER M5 ;
      RECT 392.040 777.408 392.064 777.600 ;
    END
  END rx_flit[65]
  PIN rx_flit[66]
    DIRECTION OUTPUT ;
    USE SIGNAL ;
    SHAPE ABUTMENT ;
    PORT
      LAYER M5 ;
      RECT 392.088 777.408 392.112 777.600 ;
    END
  END rx_flit[66]
  PIN rx_flit[67]
    DIRECTION OUTPUT ;
    USE SIGNAL ;
    SHAPE ABUTMENT ;
    PORT
      LAYER M5 ;
      RECT 392.136 777.408 392.160 777.600 ;
    END
  END rx_flit[67]
  PIN rx_flit[68]
    DIRECTION OUTPUT ;
    USE SIGNAL ;
    SHAPE ABUTMENT ;
    PORT
      LAYER M5 ;
      RECT 392.184 777.408 392.208 777.600 ;
    END
  END rx_flit[68]
  PIN rx_flit[69]
    DIRECTION OUTPUT ;
    USE SIGNAL ;
    SHAPE ABUTMENT ;
    PORT
      LAYER M5 ;
      RECT 392.232 777.408 392.256 777.600 ;
    END
  END rx_flit[69]
  PIN rx_flit[70]
    DIRECTION OUTPUT ;
    USE SIGNAL ;
    SHAPE ABUTMENT ;
    PORT
      LAYER M5 ;
      RECT 392.280 777.408 392.304 777.600 ;
    END
  END rx_flit[70]
  PIN rx_flit[71]
    DIRECTION OUTPUT ;
    USE SIGNAL ;
    SHAPE ABUTMENT ;
    PORT
      LAYER M5 ;
      RECT 392.328 777.408 392.352 777.600 ;
    END
  END rx_flit[71]
  PIN rx_flit[72]
    DIRECTION OUTPUT ;
    USE SIGNAL ;
    SHAPE ABUTMENT ;
    PORT
      LAYER M5 ;
      RECT 392.376 777.408 392.400 777.600 ;
    END
  END rx_flit[72]
  PIN rx_flit[73]
    DIRECTION OUTPUT ;
    USE SIGNAL ;
    SHAPE ABUTMENT ;
    PORT
      LAYER M5 ;
      RECT 392.424 777.408 392.448 777.600 ;
    END
  END rx_flit[73]
  PIN rx_flit[74]
    DIRECTION OUTPUT ;
    USE SIGNAL ;
    SHAPE ABUTMENT ;
    PORT
      LAYER M5 ;
      RECT 392.472 777.408 392.496 777.600 ;
    END
  END rx_flit[74]
  PIN rx_flit[75]
    DIRECTION OUTPUT ;
    USE SIGNAL ;
    SHAPE ABUTMENT ;
    PORT
      LAYER M5 ;
      RECT 392.520 777.408 392.544 777.600 ;
    END
  END rx_flit[75]
  PIN rx_flit[76]
    DIRECTION OUTPUT ;
    USE SIGNAL ;
    SHAPE ABUTMENT ;
    PORT
      LAYER M5 ;
      RECT 392.568 777.408 392.592 777.600 ;
    END
  END rx_flit[76]
  PIN rx_flit[77]
    DIRECTION OUTPUT ;
    USE SIGNAL ;
    SHAPE ABUTMENT ;
    PORT
      LAYER M5 ;
      RECT 392.616 777.408 392.640 777.600 ;
    END
  END rx_flit[77]
  PIN rx_flit[78]
    DIRECTION OUTPUT ;
    USE SIGNAL ;
    SHAPE ABUTMENT ;
    PORT
      LAYER M5 ;
      RECT 392.664 777.408 392.688 777.600 ;
    END
  END rx_flit[78]
  PIN rx_flit[79]
    DIRECTION OUTPUT ;
    USE SIGNAL ;
    SHAPE ABUTMENT ;
    PORT
      LAYER M5 ;
      RECT 392.712 777.408 392.736 777.600 ;
    END
  END rx_flit[79]
  PIN rx_flit[80]
    DIRECTION OUTPUT ;
    USE SIGNAL ;
    SHAPE ABUTMENT ;
    PORT
      LAYER M5 ;
      RECT 392.760 777.408 392.784 777.600 ;
    END
  END rx_flit[80]
  PIN rx_flit[81]
    DIRECTION OUTPUT ;
    USE SIGNAL ;
    SHAPE ABUTMENT ;
    PORT
      LAYER M5 ;
      RECT 392.808 777.408 392.832 777.600 ;
    END
  END rx_flit[81]
  PIN rx_flit[82]
    DIRECTION OUTPUT ;
    USE SIGNAL ;
    SHAPE ABUTMENT ;
    PORT
      LAYER M5 ;
      RECT 392.856 777.408 392.880 777.600 ;
    END
  END rx_flit[82]
  PIN rx_flit[83]
    DIRECTION OUTPUT ;
    USE SIGNAL ;
    SHAPE ABUTMENT ;
    PORT
      LAYER M5 ;
      RECT 392.904 777.408 392.928 777.600 ;
    END
  END rx_flit[83]
  PIN rx_flit[84]
    DIRECTION OUTPUT ;
    USE SIGNAL ;
    SHAPE ABUTMENT ;
    PORT
      LAYER M5 ;
      RECT 392.952 777.408 392.976 777.600 ;
    END
  END rx_flit[84]
  PIN rx_flit[85]
    DIRECTION OUTPUT ;
    USE SIGNAL ;
    SHAPE ABUTMENT ;
    PORT
      LAYER M5 ;
      RECT 393.000 777.408 393.024 777.600 ;
    END
  END rx_flit[85]
  PIN rx_flit[86]
    DIRECTION OUTPUT ;
    USE SIGNAL ;
    SHAPE ABUTMENT ;
    PORT
      LAYER M5 ;
      RECT 393.048 777.408 393.072 777.600 ;
    END
  END rx_flit[86]
  PIN rx_flit[87]
    DIRECTION OUTPUT ;
    USE SIGNAL ;
    SHAPE ABUTMENT ;
    PORT
      LAYER M5 ;
      RECT 393.096 777.408 393.120 777.600 ;
    END
  END rx_flit[87]
  PIN rx_flit[88]
    DIRECTION OUTPUT ;
    USE SIGNAL ;
    SHAPE ABUTMENT ;
    PORT
      LAYER M5 ;
      RECT 393.144 777.408 393.168 777.600 ;
    END
  END rx_flit[88]
  PIN rx_flit[89]
    DIRECTION OUTPUT ;
    USE SIGNAL ;
    SHAPE ABUTMENT ;
    PORT
      LAYER M5 ;
      RECT 393.192 777.408 393.216 777.600 ;
    END
  END rx_flit[89]
  PIN rx_flit[90]
    DIRECTION OUTPUT ;
    USE SIGNAL ;
    SHAPE ABUTMENT ;
    PORT
      LAYER M5 ;
      RECT 393.240 777.408 393.264 777.600 ;
    END
  END rx_flit[90]
  PIN rx_flit[91]
    DIRECTION OUTPUT ;
    USE SIGNAL ;
    SHAPE ABUTMENT ;
    PORT
      LAYER M5 ;
      RECT 393.288 777.408 393.312 777.600 ;
    END
  END rx_flit[91]
  PIN rx_flit[92]
    DIRECTION OUTPUT ;
    USE SIGNAL ;
    SHAPE ABUTMENT ;
    PORT
      LAYER M5 ;
      RECT 393.336 777.408 393.360 777.600 ;
    END
  END rx_flit[92]
  PIN rx_flit[93]
    DIRECTION OUTPUT ;
    USE SIGNAL ;
    SHAPE ABUTMENT ;
    PORT
      LAYER M5 ;
      RECT 393.384 777.408 393.408 777.600 ;
    END
  END rx_flit[93]
  PIN rx_flit[94]
    DIRECTION OUTPUT ;
    USE SIGNAL ;
    SHAPE ABUTMENT ;
    PORT
      LAYER M5 ;
      RECT 393.432 777.408 393.456 777.600 ;
    END
  END rx_flit[94]
  PIN rx_flit[95]
    DIRECTION OUTPUT ;
    USE SIGNAL ;
    SHAPE ABUTMENT ;
    PORT
      LAYER M5 ;
      RECT 393.480 777.408 393.504 777.600 ;
    END
  END rx_flit[95]
  PIN rx_flit[96]
    DIRECTION OUTPUT ;
    USE SIGNAL ;
    SHAPE ABUTMENT ;
    PORT
      LAYER M5 ;
      RECT 393.528 777.408 393.552 777.600 ;
    END
  END rx_flit[96]
  PIN rx_flit[97]
    DIRECTION OUTPUT ;
    USE SIGNAL ;
    SHAPE ABUTMENT ;
    PORT
      LAYER M5 ;
      RECT 393.576 777.408 393.600 777.600 ;
    END
  END rx_flit[97]
  PIN rx_flit[98]
    DIRECTION OUTPUT ;
    USE SIGNAL ;
    SHAPE ABUTMENT ;
    PORT
      LAYER M5 ;
      RECT 393.624 777.408 393.648 777.600 ;
    END
  END rx_flit[98]
  PIN rx_flit[99]
    DIRECTION OUTPUT ;
    USE SIGNAL ;
    SHAPE ABUTMENT ;
    PORT
      LAYER M5 ;
      RECT 393.672 777.408 393.696 777.600 ;
    END
  END rx_flit[99]
  PIN rx_flit[100]
    DIRECTION OUTPUT ;
    USE SIGNAL ;
    SHAPE ABUTMENT ;
    PORT
      LAYER M5 ;
      RECT 393.720 777.408 393.744 777.600 ;
    END
  END rx_flit[100]
  PIN rx_flit[101]
    DIRECTION OUTPUT ;
    USE SIGNAL ;
    SHAPE ABUTMENT ;
    PORT
      LAYER M5 ;
      RECT 393.768 777.408 393.792 777.600 ;
    END
  END rx_flit[101]
  PIN rx_flit[102]
    DIRECTION OUTPUT ;
    USE SIGNAL ;
    SHAPE ABUTMENT ;
    PORT
      LAYER M5 ;
      RECT 393.816 777.408 393.840 777.600 ;
    END
  END rx_flit[102]
  PIN rx_flit[103]
    DIRECTION OUTPUT ;
    USE SIGNAL ;
    SHAPE ABUTMENT ;
    PORT
      LAYER M5 ;
      RECT 393.864 777.408 393.888 777.600 ;
    END
  END rx_flit[103]
  PIN rx_flit[104]
    DIRECTION OUTPUT ;
    USE SIGNAL ;
    SHAPE ABUTMENT ;
    PORT
      LAYER M5 ;
      RECT 393.912 777.408 393.936 777.600 ;
    END
  END rx_flit[104]
  PIN rx_flit[105]
    DIRECTION OUTPUT ;
    USE SIGNAL ;
    SHAPE ABUTMENT ;
    PORT
      LAYER M5 ;
      RECT 393.960 777.408 393.984 777.600 ;
    END
  END rx_flit[105]
  PIN rx_flit[106]
    DIRECTION OUTPUT ;
    USE SIGNAL ;
    SHAPE ABUTMENT ;
    PORT
      LAYER M5 ;
      RECT 394.008 777.408 394.032 777.600 ;
    END
  END rx_flit[106]
  PIN rx_flit[107]
    DIRECTION OUTPUT ;
    USE SIGNAL ;
    SHAPE ABUTMENT ;
    PORT
      LAYER M5 ;
      RECT 394.056 777.408 394.080 777.600 ;
    END
  END rx_flit[107]
  PIN rx_flit[108]
    DIRECTION OUTPUT ;
    USE SIGNAL ;
    SHAPE ABUTMENT ;
    PORT
      LAYER M5 ;
      RECT 394.104 777.408 394.128 777.600 ;
    END
  END rx_flit[108]
  PIN rx_flit[109]
    DIRECTION OUTPUT ;
    USE SIGNAL ;
    SHAPE ABUTMENT ;
    PORT
      LAYER M5 ;
      RECT 394.152 777.408 394.176 777.600 ;
    END
  END rx_flit[109]
  PIN rx_flit[110]
    DIRECTION OUTPUT ;
    USE SIGNAL ;
    SHAPE ABUTMENT ;
    PORT
      LAYER M5 ;
      RECT 394.200 777.408 394.224 777.600 ;
    END
  END rx_flit[110]
  PIN rx_flit[111]
    DIRECTION OUTPUT ;
    USE SIGNAL ;
    SHAPE ABUTMENT ;
    PORT
      LAYER M5 ;
      RECT 394.248 777.408 394.272 777.600 ;
    END
  END rx_flit[111]
  PIN rx_flit[112]
    DIRECTION OUTPUT ;
    USE SIGNAL ;
    SHAPE ABUTMENT ;
    PORT
      LAYER M5 ;
      RECT 394.296 777.408 394.320 777.600 ;
    END
  END rx_flit[112]
  PIN rx_flit[113]
    DIRECTION OUTPUT ;
    USE SIGNAL ;
    SHAPE ABUTMENT ;
    PORT
      LAYER M5 ;
      RECT 394.344 777.408 394.368 777.600 ;
    END
  END rx_flit[113]
  PIN rx_flit[114]
    DIRECTION OUTPUT ;
    USE SIGNAL ;
    SHAPE ABUTMENT ;
    PORT
      LAYER M5 ;
      RECT 394.392 777.408 394.416 777.600 ;
    END
  END rx_flit[114]
  PIN rx_flit[115]
    DIRECTION OUTPUT ;
    USE SIGNAL ;
    SHAPE ABUTMENT ;
    PORT
      LAYER M5 ;
      RECT 394.440 777.408 394.464 777.600 ;
    END
  END rx_flit[115]
  PIN rx_flit[116]
    DIRECTION OUTPUT ;
    USE SIGNAL ;
    SHAPE ABUTMENT ;
    PORT
      LAYER M5 ;
      RECT 394.488 777.408 394.512 777.600 ;
    END
  END rx_flit[116]
  PIN rx_flit[117]
    DIRECTION OUTPUT ;
    USE SIGNAL ;
    SHAPE ABUTMENT ;
    PORT
      LAYER M5 ;
      RECT 394.536 777.408 394.560 777.600 ;
    END
  END rx_flit[117]
  PIN rx_flit[118]
    DIRECTION OUTPUT ;
    USE SIGNAL ;
    SHAPE ABUTMENT ;
    PORT
      LAYER M5 ;
      RECT 394.584 777.408 394.608 777.600 ;
    END
  END rx_flit[118]
  PIN rx_flit[119]
    DIRECTION OUTPUT ;
    USE SIGNAL ;
    SHAPE ABUTMENT ;
    PORT
      LAYER M5 ;
      RECT 394.632 777.408 394.656 777.600 ;
    END
  END rx_flit[119]
  PIN rx_flit[120]
    DIRECTION OUTPUT ;
    USE SIGNAL ;
    SHAPE ABUTMENT ;
    PORT
      LAYER M5 ;
      RECT 394.680 777.408 394.704 777.600 ;
    END
  END rx_flit[120]
  PIN rx_flit[121]
    DIRECTION OUTPUT ;
    USE SIGNAL ;
    SHAPE ABUTMENT ;
    PORT
      LAYER M5 ;
      RECT 394.728 777.408 394.752 777.600 ;
    END
  END rx_flit[121]
  PIN rx_flit[122]
    DIRECTION OUTPUT ;
    USE SIGNAL ;
    SHAPE ABUTMENT ;
    PORT
      LAYER M5 ;
      RECT 394.776 777.408 394.800 777.600 ;
    END
  END rx_flit[122]
  PIN rx_flit[123]
    DIRECTION OUTPUT ;
    USE SIGNAL ;
    SHAPE ABUTMENT ;
    PORT
      LAYER M5 ;
      RECT 394.824 777.408 394.848 777.600 ;
    END
  END rx_flit[123]
  PIN rx_flit[124]
    DIRECTION OUTPUT ;
    USE SIGNAL ;
    SHAPE ABUTMENT ;
    PORT
      LAYER M5 ;
      RECT 394.872 777.408 394.896 777.600 ;
    END
  END rx_flit[124]
  PIN rx_flit[125]
    DIRECTION OUTPUT ;
    USE SIGNAL ;
    SHAPE ABUTMENT ;
    PORT
      LAYER M5 ;
      RECT 394.920 777.408 394.944 777.600 ;
    END
  END rx_flit[125]
  PIN rx_flit[126]
    DIRECTION OUTPUT ;
    USE SIGNAL ;
    SHAPE ABUTMENT ;
    PORT
      LAYER M5 ;
      RECT 394.968 777.408 394.992 777.600 ;
    END
  END rx_flit[126]
  PIN rx_flit[127]
    DIRECTION OUTPUT ;
    USE SIGNAL ;
    SHAPE ABUTMENT ;
    PORT
      LAYER M5 ;
      RECT 395.016 777.408 395.040 777.600 ;
    END
  END rx_flit[127]
  PIN rx_flit[128]
    DIRECTION OUTPUT ;
    USE SIGNAL ;
    SHAPE ABUTMENT ;
    PORT
      LAYER M5 ;
      RECT 395.064 777.408 395.088 777.600 ;
    END
  END rx_flit[128]
  PIN rx_flit[129]
    DIRECTION OUTPUT ;
    USE SIGNAL ;
    SHAPE ABUTMENT ;
    PORT
      LAYER M5 ;
      RECT 395.112 777.408 395.136 777.600 ;
    END
  END rx_flit[129]
  PIN rx_flit[130]
    DIRECTION OUTPUT ;
    USE SIGNAL ;
    SHAPE ABUTMENT ;
    PORT
      LAYER M5 ;
      RECT 395.160 777.408 395.184 777.600 ;
    END
  END rx_flit[130]
  PIN rx_flit[131]
    DIRECTION OUTPUT ;
    USE SIGNAL ;
    SHAPE ABUTMENT ;
    PORT
      LAYER M5 ;
      RECT 395.208 777.408 395.232 777.600 ;
    END
  END rx_flit[131]
  PIN rx_flit[132]
    DIRECTION OUTPUT ;
    USE SIGNAL ;
    SHAPE ABUTMENT ;
    PORT
      LAYER M5 ;
      RECT 395.256 777.408 395.280 777.600 ;
    END
  END rx_flit[132]
  PIN rx_flit[133]
    DIRECTION OUTPUT ;
    USE SIGNAL ;
    SHAPE ABUTMENT ;
    PORT
      LAYER M5 ;
      RECT 395.304 777.408 395.328 777.600 ;
    END
  END rx_flit[133]
  PIN rx_flit[134]
    DIRECTION OUTPUT ;
    USE SIGNAL ;
    SHAPE ABUTMENT ;
    PORT
      LAYER M5 ;
      RECT 395.352 777.408 395.376 777.600 ;
    END
  END rx_flit[134]
  PIN rx_flit[135]
    DIRECTION OUTPUT ;
    USE SIGNAL ;
    SHAPE ABUTMENT ;
    PORT
      LAYER M5 ;
      RECT 395.400 777.408 395.424 777.600 ;
    END
  END rx_flit[135]
  PIN rx_flit[136]
    DIRECTION OUTPUT ;
    USE SIGNAL ;
    SHAPE ABUTMENT ;
    PORT
      LAYER M5 ;
      RECT 395.448 777.408 395.472 777.600 ;
    END
  END rx_flit[136]
  PIN rx_flit[137]
    DIRECTION OUTPUT ;
    USE SIGNAL ;
    SHAPE ABUTMENT ;
    PORT
      LAYER M5 ;
      RECT 395.496 777.408 395.520 777.600 ;
    END
  END rx_flit[137]
  PIN rx_flit[138]
    DIRECTION OUTPUT ;
    USE SIGNAL ;
    SHAPE ABUTMENT ;
    PORT
      LAYER M5 ;
      RECT 395.544 777.408 395.568 777.600 ;
    END
  END rx_flit[138]
  PIN rx_flit[139]
    DIRECTION OUTPUT ;
    USE SIGNAL ;
    SHAPE ABUTMENT ;
    PORT
      LAYER M5 ;
      RECT 395.592 777.408 395.616 777.600 ;
    END
  END rx_flit[139]
  PIN rx_flit[140]
    DIRECTION OUTPUT ;
    USE SIGNAL ;
    SHAPE ABUTMENT ;
    PORT
      LAYER M5 ;
      RECT 395.640 777.408 395.664 777.600 ;
    END
  END rx_flit[140]
  PIN rx_flit[141]
    DIRECTION OUTPUT ;
    USE SIGNAL ;
    SHAPE ABUTMENT ;
    PORT
      LAYER M5 ;
      RECT 395.688 777.408 395.712 777.600 ;
    END
  END rx_flit[141]
  PIN rx_flit[142]
    DIRECTION OUTPUT ;
    USE SIGNAL ;
    SHAPE ABUTMENT ;
    PORT
      LAYER M5 ;
      RECT 395.736 777.408 395.760 777.600 ;
    END
  END rx_flit[142]
  PIN rx_flit[143]
    DIRECTION OUTPUT ;
    USE SIGNAL ;
    SHAPE ABUTMENT ;
    PORT
      LAYER M5 ;
      RECT 395.784 777.408 395.808 777.600 ;
    END
  END rx_flit[143]
  PIN rx_flit[144]
    DIRECTION OUTPUT ;
    USE SIGNAL ;
    SHAPE ABUTMENT ;
    PORT
      LAYER M5 ;
      RECT 395.832 777.408 395.856 777.600 ;
    END
  END rx_flit[144]
  PIN rx_flit[145]
    DIRECTION OUTPUT ;
    USE SIGNAL ;
    SHAPE ABUTMENT ;
    PORT
      LAYER M5 ;
      RECT 395.880 777.408 395.904 777.600 ;
    END
  END rx_flit[145]
  PIN rx_flit[146]
    DIRECTION OUTPUT ;
    USE SIGNAL ;
    SHAPE ABUTMENT ;
    PORT
      LAYER M5 ;
      RECT 395.928 777.408 395.952 777.600 ;
    END
  END rx_flit[146]
  PIN rx_flit[147]
    DIRECTION OUTPUT ;
    USE SIGNAL ;
    SHAPE ABUTMENT ;
    PORT
      LAYER M5 ;
      RECT 395.976 777.408 396.000 777.600 ;
    END
  END rx_flit[147]
  PIN rx_flit[148]
    DIRECTION OUTPUT ;
    USE SIGNAL ;
    SHAPE ABUTMENT ;
    PORT
      LAYER M5 ;
      RECT 396.024 777.408 396.048 777.600 ;
    END
  END rx_flit[148]
  PIN rx_flit[149]
    DIRECTION OUTPUT ;
    USE SIGNAL ;
    SHAPE ABUTMENT ;
    PORT
      LAYER M5 ;
      RECT 396.072 777.408 396.096 777.600 ;
    END
  END rx_flit[149]
  PIN rx_flit[150]
    DIRECTION OUTPUT ;
    USE SIGNAL ;
    SHAPE ABUTMENT ;
    PORT
      LAYER M5 ;
      RECT 396.120 777.408 396.144 777.600 ;
    END
  END rx_flit[150]
  PIN rx_flit[151]
    DIRECTION OUTPUT ;
    USE SIGNAL ;
    SHAPE ABUTMENT ;
    PORT
      LAYER M5 ;
      RECT 396.168 777.408 396.192 777.600 ;
    END
  END rx_flit[151]
  PIN rx_flit[152]
    DIRECTION OUTPUT ;
    USE SIGNAL ;
    SHAPE ABUTMENT ;
    PORT
      LAYER M5 ;
      RECT 396.216 777.408 396.240 777.600 ;
    END
  END rx_flit[152]
  PIN rx_flit[153]
    DIRECTION OUTPUT ;
    USE SIGNAL ;
    SHAPE ABUTMENT ;
    PORT
      LAYER M5 ;
      RECT 396.264 777.408 396.288 777.600 ;
    END
  END rx_flit[153]
  PIN rx_flit[154]
    DIRECTION OUTPUT ;
    USE SIGNAL ;
    SHAPE ABUTMENT ;
    PORT
      LAYER M5 ;
      RECT 396.312 777.408 396.336 777.600 ;
    END
  END rx_flit[154]
  PIN rx_flit[155]
    DIRECTION OUTPUT ;
    USE SIGNAL ;
    SHAPE ABUTMENT ;
    PORT
      LAYER M5 ;
      RECT 396.360 777.408 396.384 777.600 ;
    END
  END rx_flit[155]
  PIN rx_flit[156]
    DIRECTION OUTPUT ;
    USE SIGNAL ;
    SHAPE ABUTMENT ;
    PORT
      LAYER M5 ;
      RECT 396.408 777.408 396.432 777.600 ;
    END
  END rx_flit[156]
  PIN rx_flit[157]
    DIRECTION OUTPUT ;
    USE SIGNAL ;
    SHAPE ABUTMENT ;
    PORT
      LAYER M5 ;
      RECT 396.456 777.408 396.480 777.600 ;
    END
  END rx_flit[157]
  PIN rx_flit[158]
    DIRECTION OUTPUT ;
    USE SIGNAL ;
    SHAPE ABUTMENT ;
    PORT
      LAYER M5 ;
      RECT 396.504 777.408 396.528 777.600 ;
    END
  END rx_flit[158]
  PIN rx_flit[159]
    DIRECTION OUTPUT ;
    USE SIGNAL ;
    SHAPE ABUTMENT ;
    PORT
      LAYER M5 ;
      RECT 396.552 777.408 396.576 777.600 ;
    END
  END rx_flit[159]
  PIN rx_flit[160]
    DIRECTION OUTPUT ;
    USE SIGNAL ;
    SHAPE ABUTMENT ;
    PORT
      LAYER M5 ;
      RECT 396.600 777.408 396.624 777.600 ;
    END
  END rx_flit[160]
  PIN rx_flit[161]
    DIRECTION OUTPUT ;
    USE SIGNAL ;
    SHAPE ABUTMENT ;
    PORT
      LAYER M5 ;
      RECT 396.648 777.408 396.672 777.600 ;
    END
  END rx_flit[161]
  PIN rx_flit[162]
    DIRECTION OUTPUT ;
    USE SIGNAL ;
    SHAPE ABUTMENT ;
    PORT
      LAYER M5 ;
      RECT 396.696 777.408 396.720 777.600 ;
    END
  END rx_flit[162]
  PIN rx_flit[163]
    DIRECTION OUTPUT ;
    USE SIGNAL ;
    SHAPE ABUTMENT ;
    PORT
      LAYER M5 ;
      RECT 396.744 777.408 396.768 777.600 ;
    END
  END rx_flit[163]
  PIN rx_flit[164]
    DIRECTION OUTPUT ;
    USE SIGNAL ;
    SHAPE ABUTMENT ;
    PORT
      LAYER M5 ;
      RECT 396.792 777.408 396.816 777.600 ;
    END
  END rx_flit[164]
  PIN rx_flit[165]
    DIRECTION OUTPUT ;
    USE SIGNAL ;
    SHAPE ABUTMENT ;
    PORT
      LAYER M5 ;
      RECT 396.840 777.408 396.864 777.600 ;
    END
  END rx_flit[165]
  PIN rx_flit[166]
    DIRECTION OUTPUT ;
    USE SIGNAL ;
    SHAPE ABUTMENT ;
    PORT
      LAYER M5 ;
      RECT 396.888 777.408 396.912 777.600 ;
    END
  END rx_flit[166]
  PIN rx_flit[167]
    DIRECTION OUTPUT ;
    USE SIGNAL ;
    SHAPE ABUTMENT ;
    PORT
      LAYER M5 ;
      RECT 396.936 777.408 396.960 777.600 ;
    END
  END rx_flit[167]
  PIN rx_flit[168]
    DIRECTION OUTPUT ;
    USE SIGNAL ;
    SHAPE ABUTMENT ;
    PORT
      LAYER M5 ;
      RECT 396.984 777.408 397.008 777.600 ;
    END
  END rx_flit[168]
  PIN rx_flit[169]
    DIRECTION OUTPUT ;
    USE SIGNAL ;
    SHAPE ABUTMENT ;
    PORT
      LAYER M5 ;
      RECT 397.032 777.408 397.056 777.600 ;
    END
  END rx_flit[169]
  PIN rx_flit[170]
    DIRECTION OUTPUT ;
    USE SIGNAL ;
    SHAPE ABUTMENT ;
    PORT
      LAYER M5 ;
      RECT 397.080 777.408 397.104 777.600 ;
    END
  END rx_flit[170]
  PIN rx_flit[171]
    DIRECTION OUTPUT ;
    USE SIGNAL ;
    SHAPE ABUTMENT ;
    PORT
      LAYER M5 ;
      RECT 397.128 777.408 397.152 777.600 ;
    END
  END rx_flit[171]
  PIN rx_flit[172]
    DIRECTION OUTPUT ;
    USE SIGNAL ;
    SHAPE ABUTMENT ;
    PORT
      LAYER M5 ;
      RECT 397.176 777.408 397.200 777.600 ;
    END
  END rx_flit[172]
  PIN rx_flit[173]
    DIRECTION OUTPUT ;
    USE SIGNAL ;
    SHAPE ABUTMENT ;
    PORT
      LAYER M5 ;
      RECT 397.224 777.408 397.248 777.600 ;
    END
  END rx_flit[173]
  PIN rx_flit[174]
    DIRECTION OUTPUT ;
    USE SIGNAL ;
    SHAPE ABUTMENT ;
    PORT
      LAYER M5 ;
      RECT 397.272 777.408 397.296 777.600 ;
    END
  END rx_flit[174]
  PIN rx_flit[175]
    DIRECTION OUTPUT ;
    USE SIGNAL ;
    SHAPE ABUTMENT ;
    PORT
      LAYER M5 ;
      RECT 397.320 777.408 397.344 777.600 ;
    END
  END rx_flit[175]
  PIN rx_flit[176]
    DIRECTION OUTPUT ;
    USE SIGNAL ;
    SHAPE ABUTMENT ;
    PORT
      LAYER M5 ;
      RECT 397.368 777.408 397.392 777.600 ;
    END
  END rx_flit[176]
  PIN rx_flit[177]
    DIRECTION OUTPUT ;
    USE SIGNAL ;
    SHAPE ABUTMENT ;
    PORT
      LAYER M5 ;
      RECT 397.416 777.408 397.440 777.600 ;
    END
  END rx_flit[177]
  PIN rx_flit[178]
    DIRECTION OUTPUT ;
    USE SIGNAL ;
    SHAPE ABUTMENT ;
    PORT
      LAYER M5 ;
      RECT 397.464 777.408 397.488 777.600 ;
    END
  END rx_flit[178]
  PIN rx_flit[179]
    DIRECTION OUTPUT ;
    USE SIGNAL ;
    SHAPE ABUTMENT ;
    PORT
      LAYER M5 ;
      RECT 397.512 777.408 397.536 777.600 ;
    END
  END rx_flit[179]
  PIN rx_flit[180]
    DIRECTION OUTPUT ;
    USE SIGNAL ;
    SHAPE ABUTMENT ;
    PORT
      LAYER M5 ;
      RECT 397.560 777.408 397.584 777.600 ;
    END
  END rx_flit[180]
  PIN rx_flit[181]
    DIRECTION OUTPUT ;
    USE SIGNAL ;
    SHAPE ABUTMENT ;
    PORT
      LAYER M5 ;
      RECT 397.608 777.408 397.632 777.600 ;
    END
  END rx_flit[181]
  PIN rx_flit[182]
    DIRECTION OUTPUT ;
    USE SIGNAL ;
    SHAPE ABUTMENT ;
    PORT
      LAYER M5 ;
      RECT 397.656 777.408 397.680 777.600 ;
    END
  END rx_flit[182]
  PIN rx_flit[183]
    DIRECTION OUTPUT ;
    USE SIGNAL ;
    SHAPE ABUTMENT ;
    PORT
      LAYER M5 ;
      RECT 397.704 777.408 397.728 777.600 ;
    END
  END rx_flit[183]
  PIN rx_flit[184]
    DIRECTION OUTPUT ;
    USE SIGNAL ;
    SHAPE ABUTMENT ;
    PORT
      LAYER M5 ;
      RECT 397.752 777.408 397.776 777.600 ;
    END
  END rx_flit[184]
  PIN rx_flit[185]
    DIRECTION OUTPUT ;
    USE SIGNAL ;
    SHAPE ABUTMENT ;
    PORT
      LAYER M5 ;
      RECT 397.800 777.408 397.824 777.600 ;
    END
  END rx_flit[185]
  PIN rx_flit[186]
    DIRECTION OUTPUT ;
    USE SIGNAL ;
    SHAPE ABUTMENT ;
    PORT
      LAYER M5 ;
      RECT 397.848 777.408 397.872 777.600 ;
    END
  END rx_flit[186]
  PIN rx_flit[187]
    DIRECTION OUTPUT ;
    USE SIGNAL ;
    SHAPE ABUTMENT ;
    PORT
      LAYER M5 ;
      RECT 397.896 777.408 397.920 777.600 ;
    END
  END rx_flit[187]
  PIN rx_flit[188]
    DIRECTION OUTPUT ;
    USE SIGNAL ;
    SHAPE ABUTMENT ;
    PORT
      LAYER M5 ;
      RECT 397.944 777.408 397.968 777.600 ;
    END
  END rx_flit[188]
  PIN rx_flit[189]
    DIRECTION OUTPUT ;
    USE SIGNAL ;
    SHAPE ABUTMENT ;
    PORT
      LAYER M5 ;
      RECT 397.992 777.408 398.016 777.600 ;
    END
  END rx_flit[189]
  PIN rx_flit[190]
    DIRECTION OUTPUT ;
    USE SIGNAL ;
    SHAPE ABUTMENT ;
    PORT
      LAYER M5 ;
      RECT 398.040 777.408 398.064 777.600 ;
    END
  END rx_flit[190]
  PIN rx_flit[191]
    DIRECTION OUTPUT ;
    USE SIGNAL ;
    SHAPE ABUTMENT ;
    PORT
      LAYER M5 ;
      RECT 398.088 777.408 398.112 777.600 ;
    END
  END rx_flit[191]
  PIN rx_flit[192]
    DIRECTION OUTPUT ;
    USE SIGNAL ;
    SHAPE ABUTMENT ;
    PORT
      LAYER M5 ;
      RECT 398.136 777.408 398.160 777.600 ;
    END
  END rx_flit[192]
  PIN rx_flit[193]
    DIRECTION OUTPUT ;
    USE SIGNAL ;
    SHAPE ABUTMENT ;
    PORT
      LAYER M5 ;
      RECT 398.184 777.408 398.208 777.600 ;
    END
  END rx_flit[193]
  PIN rx_flit[194]
    DIRECTION OUTPUT ;
    USE SIGNAL ;
    SHAPE ABUTMENT ;
    PORT
      LAYER M5 ;
      RECT 398.232 777.408 398.256 777.600 ;
    END
  END rx_flit[194]
  PIN rx_flit[195]
    DIRECTION OUTPUT ;
    USE SIGNAL ;
    SHAPE ABUTMENT ;
    PORT
      LAYER M5 ;
      RECT 398.280 777.408 398.304 777.600 ;
    END
  END rx_flit[195]
  PIN rx_flit[196]
    DIRECTION OUTPUT ;
    USE SIGNAL ;
    SHAPE ABUTMENT ;
    PORT
      LAYER M5 ;
      RECT 398.328 777.408 398.352 777.600 ;
    END
  END rx_flit[196]
  PIN rx_flit[197]
    DIRECTION OUTPUT ;
    USE SIGNAL ;
    SHAPE ABUTMENT ;
    PORT
      LAYER M5 ;
      RECT 398.376 777.408 398.400 777.600 ;
    END
  END rx_flit[197]
  PIN rx_flit[198]
    DIRECTION OUTPUT ;
    USE SIGNAL ;
    SHAPE ABUTMENT ;
    PORT
      LAYER M5 ;
      RECT 398.424 777.408 398.448 777.600 ;
    END
  END rx_flit[198]
  PIN rx_flit[199]
    DIRECTION OUTPUT ;
    USE SIGNAL ;
    SHAPE ABUTMENT ;
    PORT
      LAYER M5 ;
      RECT 398.472 777.408 398.496 777.600 ;
    END
  END rx_flit[199]
  PIN rx_flit[200]
    DIRECTION OUTPUT ;
    USE SIGNAL ;
    SHAPE ABUTMENT ;
    PORT
      LAYER M5 ;
      RECT 398.520 777.408 398.544 777.600 ;
    END
  END rx_flit[200]
  PIN rx_flit[201]
    DIRECTION OUTPUT ;
    USE SIGNAL ;
    SHAPE ABUTMENT ;
    PORT
      LAYER M5 ;
      RECT 398.568 777.408 398.592 777.600 ;
    END
  END rx_flit[201]
  PIN rx_flit[202]
    DIRECTION OUTPUT ;
    USE SIGNAL ;
    SHAPE ABUTMENT ;
    PORT
      LAYER M5 ;
      RECT 398.616 777.408 398.640 777.600 ;
    END
  END rx_flit[202]
  PIN rx_flit[203]
    DIRECTION OUTPUT ;
    USE SIGNAL ;
    SHAPE ABUTMENT ;
    PORT
      LAYER M5 ;
      RECT 398.664 777.408 398.688 777.600 ;
    END
  END rx_flit[203]
  PIN rx_flit[204]
    DIRECTION OUTPUT ;
    USE SIGNAL ;
    SHAPE ABUTMENT ;
    PORT
      LAYER M5 ;
      RECT 398.712 777.408 398.736 777.600 ;
    END
  END rx_flit[204]
  PIN rx_flit[205]
    DIRECTION OUTPUT ;
    USE SIGNAL ;
    SHAPE ABUTMENT ;
    PORT
      LAYER M5 ;
      RECT 398.760 777.408 398.784 777.600 ;
    END
  END rx_flit[205]
  PIN rx_flit[206]
    DIRECTION OUTPUT ;
    USE SIGNAL ;
    SHAPE ABUTMENT ;
    PORT
      LAYER M5 ;
      RECT 398.808 777.408 398.832 777.600 ;
    END
  END rx_flit[206]
  PIN rx_flit[207]
    DIRECTION OUTPUT ;
    USE SIGNAL ;
    SHAPE ABUTMENT ;
    PORT
      LAYER M5 ;
      RECT 398.856 777.408 398.880 777.600 ;
    END
  END rx_flit[207]
  PIN rx_flit[208]
    DIRECTION OUTPUT ;
    USE SIGNAL ;
    SHAPE ABUTMENT ;
    PORT
      LAYER M5 ;
      RECT 398.904 777.408 398.928 777.600 ;
    END
  END rx_flit[208]
  PIN rx_flit[209]
    DIRECTION OUTPUT ;
    USE SIGNAL ;
    SHAPE ABUTMENT ;
    PORT
      LAYER M5 ;
      RECT 398.952 777.408 398.976 777.600 ;
    END
  END rx_flit[209]
  PIN rx_flit[210]
    DIRECTION OUTPUT ;
    USE SIGNAL ;
    SHAPE ABUTMENT ;
    PORT
      LAYER M5 ;
      RECT 399.000 777.408 399.024 777.600 ;
    END
  END rx_flit[210]
  PIN rx_flit[211]
    DIRECTION OUTPUT ;
    USE SIGNAL ;
    SHAPE ABUTMENT ;
    PORT
      LAYER M5 ;
      RECT 399.048 777.408 399.072 777.600 ;
    END
  END rx_flit[211]
  PIN rx_flit[212]
    DIRECTION OUTPUT ;
    USE SIGNAL ;
    SHAPE ABUTMENT ;
    PORT
      LAYER M5 ;
      RECT 399.096 777.408 399.120 777.600 ;
    END
  END rx_flit[212]
  PIN rx_flit[213]
    DIRECTION OUTPUT ;
    USE SIGNAL ;
    SHAPE ABUTMENT ;
    PORT
      LAYER M5 ;
      RECT 399.144 777.408 399.168 777.600 ;
    END
  END rx_flit[213]
  PIN rx_flit[214]
    DIRECTION OUTPUT ;
    USE SIGNAL ;
    SHAPE ABUTMENT ;
    PORT
      LAYER M5 ;
      RECT 399.192 777.408 399.216 777.600 ;
    END
  END rx_flit[214]
  PIN rx_flit[215]
    DIRECTION OUTPUT ;
    USE SIGNAL ;
    SHAPE ABUTMENT ;
    PORT
      LAYER M5 ;
      RECT 399.240 777.408 399.264 777.600 ;
    END
  END rx_flit[215]
  PIN rx_flit[216]
    DIRECTION OUTPUT ;
    USE SIGNAL ;
    SHAPE ABUTMENT ;
    PORT
      LAYER M5 ;
      RECT 399.288 777.408 399.312 777.600 ;
    END
  END rx_flit[216]
  PIN rx_flit[217]
    DIRECTION OUTPUT ;
    USE SIGNAL ;
    SHAPE ABUTMENT ;
    PORT
      LAYER M5 ;
      RECT 399.336 777.408 399.360 777.600 ;
    END
  END rx_flit[217]
  PIN rx_flit[218]
    DIRECTION OUTPUT ;
    USE SIGNAL ;
    SHAPE ABUTMENT ;
    PORT
      LAYER M5 ;
      RECT 399.384 777.408 399.408 777.600 ;
    END
  END rx_flit[218]
  PIN rx_flit[219]
    DIRECTION OUTPUT ;
    USE SIGNAL ;
    SHAPE ABUTMENT ;
    PORT
      LAYER M5 ;
      RECT 399.432 777.408 399.456 777.600 ;
    END
  END rx_flit[219]
  PIN rx_flit[220]
    DIRECTION OUTPUT ;
    USE SIGNAL ;
    SHAPE ABUTMENT ;
    PORT
      LAYER M5 ;
      RECT 399.480 777.408 399.504 777.600 ;
    END
  END rx_flit[220]
  PIN rx_flit[221]
    DIRECTION OUTPUT ;
    USE SIGNAL ;
    SHAPE ABUTMENT ;
    PORT
      LAYER M5 ;
      RECT 399.528 777.408 399.552 777.600 ;
    END
  END rx_flit[221]
  PIN rx_flit[222]
    DIRECTION OUTPUT ;
    USE SIGNAL ;
    SHAPE ABUTMENT ;
    PORT
      LAYER M5 ;
      RECT 399.576 777.408 399.600 777.600 ;
    END
  END rx_flit[222]
  PIN rx_flit[223]
    DIRECTION OUTPUT ;
    USE SIGNAL ;
    SHAPE ABUTMENT ;
    PORT
      LAYER M5 ;
      RECT 399.624 777.408 399.648 777.600 ;
    END
  END rx_flit[223]
  PIN rx_flit[224]
    DIRECTION OUTPUT ;
    USE SIGNAL ;
    SHAPE ABUTMENT ;
    PORT
      LAYER M5 ;
      RECT 399.672 777.408 399.696 777.600 ;
    END
  END rx_flit[224]
  PIN rx_flit[225]
    DIRECTION OUTPUT ;
    USE SIGNAL ;
    SHAPE ABUTMENT ;
    PORT
      LAYER M5 ;
      RECT 399.720 777.408 399.744 777.600 ;
    END
  END rx_flit[225]
  PIN rx_flit[226]
    DIRECTION OUTPUT ;
    USE SIGNAL ;
    SHAPE ABUTMENT ;
    PORT
      LAYER M5 ;
      RECT 399.768 777.408 399.792 777.600 ;
    END
  END rx_flit[226]
  PIN rx_flit[227]
    DIRECTION OUTPUT ;
    USE SIGNAL ;
    SHAPE ABUTMENT ;
    PORT
      LAYER M5 ;
      RECT 399.816 777.408 399.840 777.600 ;
    END
  END rx_flit[227]
  PIN rx_flit[228]
    DIRECTION OUTPUT ;
    USE SIGNAL ;
    SHAPE ABUTMENT ;
    PORT
      LAYER M5 ;
      RECT 399.864 777.408 399.888 777.600 ;
    END
  END rx_flit[228]
  PIN rx_flit[229]
    DIRECTION OUTPUT ;
    USE SIGNAL ;
    SHAPE ABUTMENT ;
    PORT
      LAYER M5 ;
      RECT 399.912 777.408 399.936 777.600 ;
    END
  END rx_flit[229]
  PIN rx_flit[230]
    DIRECTION OUTPUT ;
    USE SIGNAL ;
    SHAPE ABUTMENT ;
    PORT
      LAYER M5 ;
      RECT 399.960 777.408 399.984 777.600 ;
    END
  END rx_flit[230]
  PIN rx_flit[231]
    DIRECTION OUTPUT ;
    USE SIGNAL ;
    SHAPE ABUTMENT ;
    PORT
      LAYER M5 ;
      RECT 400.008 777.408 400.032 777.600 ;
    END
  END rx_flit[231]
  PIN rx_flit[232]
    DIRECTION OUTPUT ;
    USE SIGNAL ;
    SHAPE ABUTMENT ;
    PORT
      LAYER M5 ;
      RECT 400.056 777.408 400.080 777.600 ;
    END
  END rx_flit[232]
  PIN rx_flit[233]
    DIRECTION OUTPUT ;
    USE SIGNAL ;
    SHAPE ABUTMENT ;
    PORT
      LAYER M5 ;
      RECT 400.104 777.408 400.128 777.600 ;
    END
  END rx_flit[233]
  PIN rx_flit[234]
    DIRECTION OUTPUT ;
    USE SIGNAL ;
    SHAPE ABUTMENT ;
    PORT
      LAYER M5 ;
      RECT 400.152 777.408 400.176 777.600 ;
    END
  END rx_flit[234]
  PIN rx_flit[235]
    DIRECTION OUTPUT ;
    USE SIGNAL ;
    SHAPE ABUTMENT ;
    PORT
      LAYER M5 ;
      RECT 400.200 777.408 400.224 777.600 ;
    END
  END rx_flit[235]
  PIN rx_flit[236]
    DIRECTION OUTPUT ;
    USE SIGNAL ;
    SHAPE ABUTMENT ;
    PORT
      LAYER M5 ;
      RECT 400.248 777.408 400.272 777.600 ;
    END
  END rx_flit[236]
  PIN rx_flit[237]
    DIRECTION OUTPUT ;
    USE SIGNAL ;
    SHAPE ABUTMENT ;
    PORT
      LAYER M5 ;
      RECT 400.296 777.408 400.320 777.600 ;
    END
  END rx_flit[237]
  PIN rx_flit[238]
    DIRECTION OUTPUT ;
    USE SIGNAL ;
    SHAPE ABUTMENT ;
    PORT
      LAYER M5 ;
      RECT 400.344 777.408 400.368 777.600 ;
    END
  END rx_flit[238]
  PIN rx_flit[239]
    DIRECTION OUTPUT ;
    USE SIGNAL ;
    SHAPE ABUTMENT ;
    PORT
      LAYER M5 ;
      RECT 400.392 777.408 400.416 777.600 ;
    END
  END rx_flit[239]
  PIN rx_flit[240]
    DIRECTION OUTPUT ;
    USE SIGNAL ;
    SHAPE ABUTMENT ;
    PORT
      LAYER M5 ;
      RECT 400.440 777.408 400.464 777.600 ;
    END
  END rx_flit[240]
  PIN rx_flit[241]
    DIRECTION OUTPUT ;
    USE SIGNAL ;
    SHAPE ABUTMENT ;
    PORT
      LAYER M5 ;
      RECT 400.488 777.408 400.512 777.600 ;
    END
  END rx_flit[241]
  PIN rx_flit[242]
    DIRECTION OUTPUT ;
    USE SIGNAL ;
    SHAPE ABUTMENT ;
    PORT
      LAYER M5 ;
      RECT 400.536 777.408 400.560 777.600 ;
    END
  END rx_flit[242]
  PIN rx_flit[243]
    DIRECTION OUTPUT ;
    USE SIGNAL ;
    SHAPE ABUTMENT ;
    PORT
      LAYER M5 ;
      RECT 400.584 777.408 400.608 777.600 ;
    END
  END rx_flit[243]
  PIN rx_flit[244]
    DIRECTION OUTPUT ;
    USE SIGNAL ;
    SHAPE ABUTMENT ;
    PORT
      LAYER M5 ;
      RECT 400.632 777.408 400.656 777.600 ;
    END
  END rx_flit[244]
  PIN rx_flit[245]
    DIRECTION OUTPUT ;
    USE SIGNAL ;
    SHAPE ABUTMENT ;
    PORT
      LAYER M5 ;
      RECT 400.680 777.408 400.704 777.600 ;
    END
  END rx_flit[245]
  PIN rx_flit[246]
    DIRECTION OUTPUT ;
    USE SIGNAL ;
    SHAPE ABUTMENT ;
    PORT
      LAYER M5 ;
      RECT 400.728 777.408 400.752 777.600 ;
    END
  END rx_flit[246]
  PIN rx_flit[247]
    DIRECTION OUTPUT ;
    USE SIGNAL ;
    SHAPE ABUTMENT ;
    PORT
      LAYER M5 ;
      RECT 400.776 777.408 400.800 777.600 ;
    END
  END rx_flit[247]
  PIN rx_flit[248]
    DIRECTION OUTPUT ;
    USE SIGNAL ;
    SHAPE ABUTMENT ;
    PORT
      LAYER M5 ;
      RECT 400.824 777.408 400.848 777.600 ;
    END
  END rx_flit[248]
  PIN rx_flit[249]
    DIRECTION OUTPUT ;
    USE SIGNAL ;
    SHAPE ABUTMENT ;
    PORT
      LAYER M5 ;
      RECT 400.872 777.408 400.896 777.600 ;
    END
  END rx_flit[249]
  PIN rx_flit[250]
    DIRECTION OUTPUT ;
    USE SIGNAL ;
    SHAPE ABUTMENT ;
    PORT
      LAYER M5 ;
      RECT 400.920 777.408 400.944 777.600 ;
    END
  END rx_flit[250]
  PIN rx_flit[251]
    DIRECTION OUTPUT ;
    USE SIGNAL ;
    SHAPE ABUTMENT ;
    PORT
      LAYER M5 ;
      RECT 400.968 777.408 400.992 777.600 ;
    END
  END rx_flit[251]
  PIN rx_flit[252]
    DIRECTION OUTPUT ;
    USE SIGNAL ;
    SHAPE ABUTMENT ;
    PORT
      LAYER M5 ;
      RECT 401.016 777.408 401.040 777.600 ;
    END
  END rx_flit[252]
  PIN rx_flit[253]
    DIRECTION OUTPUT ;
    USE SIGNAL ;
    SHAPE ABUTMENT ;
    PORT
      LAYER M5 ;
      RECT 401.064 777.408 401.088 777.600 ;
    END
  END rx_flit[253]
  PIN rx_flit[254]
    DIRECTION OUTPUT ;
    USE SIGNAL ;
    SHAPE ABUTMENT ;
    PORT
      LAYER M5 ;
      RECT 401.112 777.408 401.136 777.600 ;
    END
  END rx_flit[254]
  PIN rx_flit[255]
    DIRECTION OUTPUT ;
    USE SIGNAL ;
    SHAPE ABUTMENT ;
    PORT
      LAYER M5 ;
      RECT 401.160 777.408 401.184 777.600 ;
    END
  END rx_flit[255]
  PIN rx_flit[256]
    DIRECTION OUTPUT ;
    USE SIGNAL ;
    SHAPE ABUTMENT ;
    PORT
      LAYER M5 ;
      RECT 401.208 777.408 401.232 777.600 ;
    END
  END rx_flit[256]
  PIN rx_flit[257]
    DIRECTION OUTPUT ;
    USE SIGNAL ;
    SHAPE ABUTMENT ;
    PORT
      LAYER M5 ;
      RECT 401.256 777.408 401.280 777.600 ;
    END
  END rx_flit[257]
  PIN rx_flit[258]
    DIRECTION OUTPUT ;
    USE SIGNAL ;
    SHAPE ABUTMENT ;
    PORT
      LAYER M5 ;
      RECT 401.304 777.408 401.328 777.600 ;
    END
  END rx_flit[258]
  PIN rx_flit[259]
    DIRECTION OUTPUT ;
    USE SIGNAL ;
    SHAPE ABUTMENT ;
    PORT
      LAYER M5 ;
      RECT 401.352 777.408 401.376 777.600 ;
    END
  END rx_flit[259]
  PIN rx_flit[260]
    DIRECTION OUTPUT ;
    USE SIGNAL ;
    SHAPE ABUTMENT ;
    PORT
      LAYER M5 ;
      RECT 401.400 777.408 401.424 777.600 ;
    END
  END rx_flit[260]
  PIN rx_flit[261]
    DIRECTION OUTPUT ;
    USE SIGNAL ;
    SHAPE ABUTMENT ;
    PORT
      LAYER M5 ;
      RECT 401.448 777.408 401.472 777.600 ;
    END
  END rx_flit[261]
  PIN rx_flit[262]
    DIRECTION OUTPUT ;
    USE SIGNAL ;
    SHAPE ABUTMENT ;
    PORT
      LAYER M5 ;
      RECT 401.496 777.408 401.520 777.600 ;
    END
  END rx_flit[262]
  PIN rx_flit[263]
    DIRECTION OUTPUT ;
    USE SIGNAL ;
    SHAPE ABUTMENT ;
    PORT
      LAYER M5 ;
      RECT 401.544 777.408 401.568 777.600 ;
    END
  END rx_flit[263]
  PIN rx_flit[264]
    DIRECTION OUTPUT ;
    USE SIGNAL ;
    SHAPE ABUTMENT ;
    PORT
      LAYER M5 ;
      RECT 401.592 777.408 401.616 777.600 ;
    END
  END rx_flit[264]
  PIN rx_flit[265]
    DIRECTION OUTPUT ;
    USE SIGNAL ;
    SHAPE ABUTMENT ;
    PORT
      LAYER M5 ;
      RECT 401.640 777.408 401.664 777.600 ;
    END
  END rx_flit[265]
  PIN rx_flit[266]
    DIRECTION OUTPUT ;
    USE SIGNAL ;
    SHAPE ABUTMENT ;
    PORT
      LAYER M5 ;
      RECT 401.688 777.408 401.712 777.600 ;
    END
  END rx_flit[266]
  PIN rx_flit[267]
    DIRECTION OUTPUT ;
    USE SIGNAL ;
    SHAPE ABUTMENT ;
    PORT
      LAYER M5 ;
      RECT 401.736 777.408 401.760 777.600 ;
    END
  END rx_flit[267]
  PIN rx_flit[268]
    DIRECTION OUTPUT ;
    USE SIGNAL ;
    SHAPE ABUTMENT ;
    PORT
      LAYER M5 ;
      RECT 401.784 777.408 401.808 777.600 ;
    END
  END rx_flit[268]
  PIN rx_flit[269]
    DIRECTION OUTPUT ;
    USE SIGNAL ;
    SHAPE ABUTMENT ;
    PORT
      LAYER M5 ;
      RECT 401.832 777.408 401.856 777.600 ;
    END
  END rx_flit[269]
  PIN rx_flit[270]
    DIRECTION OUTPUT ;
    USE SIGNAL ;
    SHAPE ABUTMENT ;
    PORT
      LAYER M5 ;
      RECT 401.880 777.408 401.904 777.600 ;
    END
  END rx_flit[270]
  PIN rx_flit[271]
    DIRECTION OUTPUT ;
    USE SIGNAL ;
    SHAPE ABUTMENT ;
    PORT
      LAYER M5 ;
      RECT 401.928 777.408 401.952 777.600 ;
    END
  END rx_flit[271]
  PIN rx_flit[272]
    DIRECTION OUTPUT ;
    USE SIGNAL ;
    SHAPE ABUTMENT ;
    PORT
      LAYER M5 ;
      RECT 401.976 777.408 402.000 777.600 ;
    END
  END rx_flit[272]
  PIN rx_flit[273]
    DIRECTION OUTPUT ;
    USE SIGNAL ;
    SHAPE ABUTMENT ;
    PORT
      LAYER M5 ;
      RECT 402.024 777.408 402.048 777.600 ;
    END
  END rx_flit[273]
  PIN rx_flit[274]
    DIRECTION OUTPUT ;
    USE SIGNAL ;
    SHAPE ABUTMENT ;
    PORT
      LAYER M5 ;
      RECT 402.072 777.408 402.096 777.600 ;
    END
  END rx_flit[274]
  PIN rx_flit[275]
    DIRECTION OUTPUT ;
    USE SIGNAL ;
    SHAPE ABUTMENT ;
    PORT
      LAYER M5 ;
      RECT 402.120 777.408 402.144 777.600 ;
    END
  END rx_flit[275]
  PIN rx_flit[276]
    DIRECTION OUTPUT ;
    USE SIGNAL ;
    SHAPE ABUTMENT ;
    PORT
      LAYER M5 ;
      RECT 402.168 777.408 402.192 777.600 ;
    END
  END rx_flit[276]
  PIN rx_flit[277]
    DIRECTION OUTPUT ;
    USE SIGNAL ;
    SHAPE ABUTMENT ;
    PORT
      LAYER M5 ;
      RECT 402.216 777.408 402.240 777.600 ;
    END
  END rx_flit[277]
  PIN rx_flit[278]
    DIRECTION OUTPUT ;
    USE SIGNAL ;
    SHAPE ABUTMENT ;
    PORT
      LAYER M5 ;
      RECT 402.264 777.408 402.288 777.600 ;
    END
  END rx_flit[278]
  PIN rx_flit[279]
    DIRECTION OUTPUT ;
    USE SIGNAL ;
    SHAPE ABUTMENT ;
    PORT
      LAYER M5 ;
      RECT 402.312 777.408 402.336 777.600 ;
    END
  END rx_flit[279]
  PIN rx_flit[280]
    DIRECTION OUTPUT ;
    USE SIGNAL ;
    SHAPE ABUTMENT ;
    PORT
      LAYER M5 ;
      RECT 402.360 777.408 402.384 777.600 ;
    END
  END rx_flit[280]
  PIN rx_flit[281]
    DIRECTION OUTPUT ;
    USE SIGNAL ;
    SHAPE ABUTMENT ;
    PORT
      LAYER M5 ;
      RECT 402.408 777.408 402.432 777.600 ;
    END
  END rx_flit[281]
  PIN rx_flit[282]
    DIRECTION OUTPUT ;
    USE SIGNAL ;
    SHAPE ABUTMENT ;
    PORT
      LAYER M5 ;
      RECT 402.456 777.408 402.480 777.600 ;
    END
  END rx_flit[282]
  PIN rx_flit[283]
    DIRECTION OUTPUT ;
    USE SIGNAL ;
    SHAPE ABUTMENT ;
    PORT
      LAYER M5 ;
      RECT 402.504 777.408 402.528 777.600 ;
    END
  END rx_flit[283]
  PIN rx_flit[284]
    DIRECTION OUTPUT ;
    USE SIGNAL ;
    SHAPE ABUTMENT ;
    PORT
      LAYER M5 ;
      RECT 402.552 777.408 402.576 777.600 ;
    END
  END rx_flit[284]
  PIN rx_flit[285]
    DIRECTION OUTPUT ;
    USE SIGNAL ;
    SHAPE ABUTMENT ;
    PORT
      LAYER M5 ;
      RECT 402.600 777.408 402.624 777.600 ;
    END
  END rx_flit[285]
  PIN rx_flit[286]
    DIRECTION OUTPUT ;
    USE SIGNAL ;
    SHAPE ABUTMENT ;
    PORT
      LAYER M5 ;
      RECT 402.648 777.408 402.672 777.600 ;
    END
  END rx_flit[286]
  PIN rx_flit[287]
    DIRECTION OUTPUT ;
    USE SIGNAL ;
    SHAPE ABUTMENT ;
    PORT
      LAYER M5 ;
      RECT 402.696 777.408 402.720 777.600 ;
    END
  END rx_flit[287]
  PIN rx_flit[288]
    DIRECTION OUTPUT ;
    USE SIGNAL ;
    SHAPE ABUTMENT ;
    PORT
      LAYER M5 ;
      RECT 402.744 777.408 402.768 777.600 ;
    END
  END rx_flit[288]
  PIN rx_flit[289]
    DIRECTION OUTPUT ;
    USE SIGNAL ;
    SHAPE ABUTMENT ;
    PORT
      LAYER M5 ;
      RECT 402.792 777.408 402.816 777.600 ;
    END
  END rx_flit[289]
  PIN rx_flit[290]
    DIRECTION OUTPUT ;
    USE SIGNAL ;
    SHAPE ABUTMENT ;
    PORT
      LAYER M5 ;
      RECT 402.840 777.408 402.864 777.600 ;
    END
  END rx_flit[290]
  PIN rx_flit[291]
    DIRECTION OUTPUT ;
    USE SIGNAL ;
    SHAPE ABUTMENT ;
    PORT
      LAYER M5 ;
      RECT 402.888 777.408 402.912 777.600 ;
    END
  END rx_flit[291]
  PIN rx_flit[292]
    DIRECTION OUTPUT ;
    USE SIGNAL ;
    SHAPE ABUTMENT ;
    PORT
      LAYER M5 ;
      RECT 402.936 777.408 402.960 777.600 ;
    END
  END rx_flit[292]
  PIN rx_flit[293]
    DIRECTION OUTPUT ;
    USE SIGNAL ;
    SHAPE ABUTMENT ;
    PORT
      LAYER M5 ;
      RECT 402.984 777.408 403.008 777.600 ;
    END
  END rx_flit[293]
  PIN rx_flit[294]
    DIRECTION OUTPUT ;
    USE SIGNAL ;
    SHAPE ABUTMENT ;
    PORT
      LAYER M5 ;
      RECT 403.032 777.408 403.056 777.600 ;
    END
  END rx_flit[294]
  PIN rx_flit[295]
    DIRECTION OUTPUT ;
    USE SIGNAL ;
    SHAPE ABUTMENT ;
    PORT
      LAYER M5 ;
      RECT 403.080 777.408 403.104 777.600 ;
    END
  END rx_flit[295]
  PIN rx_flit[296]
    DIRECTION OUTPUT ;
    USE SIGNAL ;
    SHAPE ABUTMENT ;
    PORT
      LAYER M5 ;
      RECT 403.128 777.408 403.152 777.600 ;
    END
  END rx_flit[296]
  PIN rx_flit[297]
    DIRECTION OUTPUT ;
    USE SIGNAL ;
    SHAPE ABUTMENT ;
    PORT
      LAYER M5 ;
      RECT 403.176 777.408 403.200 777.600 ;
    END
  END rx_flit[297]
  PIN rx_flit[298]
    DIRECTION OUTPUT ;
    USE SIGNAL ;
    SHAPE ABUTMENT ;
    PORT
      LAYER M5 ;
      RECT 403.224 777.408 403.248 777.600 ;
    END
  END rx_flit[298]
  PIN rx_flit[299]
    DIRECTION OUTPUT ;
    USE SIGNAL ;
    SHAPE ABUTMENT ;
    PORT
      LAYER M5 ;
      RECT 403.272 777.408 403.296 777.600 ;
    END
  END rx_flit[299]
  PIN rx_flit[300]
    DIRECTION OUTPUT ;
    USE SIGNAL ;
    SHAPE ABUTMENT ;
    PORT
      LAYER M5 ;
      RECT 403.320 777.408 403.344 777.600 ;
    END
  END rx_flit[300]
  PIN rx_flit[301]
    DIRECTION OUTPUT ;
    USE SIGNAL ;
    SHAPE ABUTMENT ;
    PORT
      LAYER M5 ;
      RECT 403.368 777.408 403.392 777.600 ;
    END
  END rx_flit[301]
  PIN rx_flit[302]
    DIRECTION OUTPUT ;
    USE SIGNAL ;
    SHAPE ABUTMENT ;
    PORT
      LAYER M5 ;
      RECT 403.416 777.408 403.440 777.600 ;
    END
  END rx_flit[302]
  PIN rx_flit[303]
    DIRECTION OUTPUT ;
    USE SIGNAL ;
    SHAPE ABUTMENT ;
    PORT
      LAYER M5 ;
      RECT 403.464 777.408 403.488 777.600 ;
    END
  END rx_flit[303]
  PIN rx_flit[304]
    DIRECTION OUTPUT ;
    USE SIGNAL ;
    SHAPE ABUTMENT ;
    PORT
      LAYER M5 ;
      RECT 403.512 777.408 403.536 777.600 ;
    END
  END rx_flit[304]
  PIN rx_flit[305]
    DIRECTION OUTPUT ;
    USE SIGNAL ;
    SHAPE ABUTMENT ;
    PORT
      LAYER M5 ;
      RECT 403.560 777.408 403.584 777.600 ;
    END
  END rx_flit[305]
  PIN rx_flit[306]
    DIRECTION OUTPUT ;
    USE SIGNAL ;
    SHAPE ABUTMENT ;
    PORT
      LAYER M5 ;
      RECT 403.608 777.408 403.632 777.600 ;
    END
  END rx_flit[306]
  PIN rx_flit[307]
    DIRECTION OUTPUT ;
    USE SIGNAL ;
    SHAPE ABUTMENT ;
    PORT
      LAYER M5 ;
      RECT 403.656 777.408 403.680 777.600 ;
    END
  END rx_flit[307]
  PIN rx_flit[308]
    DIRECTION OUTPUT ;
    USE SIGNAL ;
    SHAPE ABUTMENT ;
    PORT
      LAYER M5 ;
      RECT 403.704 777.408 403.728 777.600 ;
    END
  END rx_flit[308]
  PIN rx_flit[309]
    DIRECTION OUTPUT ;
    USE SIGNAL ;
    SHAPE ABUTMENT ;
    PORT
      LAYER M5 ;
      RECT 403.752 777.408 403.776 777.600 ;
    END
  END rx_flit[309]
  PIN rx_flit[310]
    DIRECTION OUTPUT ;
    USE SIGNAL ;
    SHAPE ABUTMENT ;
    PORT
      LAYER M5 ;
      RECT 403.800 777.408 403.824 777.600 ;
    END
  END rx_flit[310]
  PIN rx_flit[311]
    DIRECTION OUTPUT ;
    USE SIGNAL ;
    SHAPE ABUTMENT ;
    PORT
      LAYER M5 ;
      RECT 403.848 777.408 403.872 777.600 ;
    END
  END rx_flit[311]
  PIN rx_flit[312]
    DIRECTION OUTPUT ;
    USE SIGNAL ;
    SHAPE ABUTMENT ;
    PORT
      LAYER M5 ;
      RECT 403.896 777.408 403.920 777.600 ;
    END
  END rx_flit[312]
  PIN rx_flit[313]
    DIRECTION OUTPUT ;
    USE SIGNAL ;
    SHAPE ABUTMENT ;
    PORT
      LAYER M5 ;
      RECT 403.944 777.408 403.968 777.600 ;
    END
  END rx_flit[313]
  PIN rx_flit[314]
    DIRECTION OUTPUT ;
    USE SIGNAL ;
    SHAPE ABUTMENT ;
    PORT
      LAYER M5 ;
      RECT 403.992 777.408 404.016 777.600 ;
    END
  END rx_flit[314]
  PIN rx_flit[315]
    DIRECTION OUTPUT ;
    USE SIGNAL ;
    SHAPE ABUTMENT ;
    PORT
      LAYER M5 ;
      RECT 404.040 777.408 404.064 777.600 ;
    END
  END rx_flit[315]
  PIN rx_flit[316]
    DIRECTION OUTPUT ;
    USE SIGNAL ;
    SHAPE ABUTMENT ;
    PORT
      LAYER M5 ;
      RECT 404.088 777.408 404.112 777.600 ;
    END
  END rx_flit[316]
  PIN rx_flit[317]
    DIRECTION OUTPUT ;
    USE SIGNAL ;
    SHAPE ABUTMENT ;
    PORT
      LAYER M5 ;
      RECT 404.136 777.408 404.160 777.600 ;
    END
  END rx_flit[317]
  PIN rx_flit[318]
    DIRECTION OUTPUT ;
    USE SIGNAL ;
    SHAPE ABUTMENT ;
    PORT
      LAYER M5 ;
      RECT 404.184 777.408 404.208 777.600 ;
    END
  END rx_flit[318]
  PIN rx_flit[319]
    DIRECTION OUTPUT ;
    USE SIGNAL ;
    SHAPE ABUTMENT ;
    PORT
      LAYER M5 ;
      RECT 404.232 777.408 404.256 777.600 ;
    END
  END rx_flit[319]
  PIN rx_flit[320]
    DIRECTION OUTPUT ;
    USE SIGNAL ;
    SHAPE ABUTMENT ;
    PORT
      LAYER M5 ;
      RECT 404.280 777.408 404.304 777.600 ;
    END
  END rx_flit[320]
  PIN rx_flit[321]
    DIRECTION OUTPUT ;
    USE SIGNAL ;
    SHAPE ABUTMENT ;
    PORT
      LAYER M5 ;
      RECT 404.328 777.408 404.352 777.600 ;
    END
  END rx_flit[321]
  PIN rx_flit[322]
    DIRECTION OUTPUT ;
    USE SIGNAL ;
    SHAPE ABUTMENT ;
    PORT
      LAYER M5 ;
      RECT 404.376 777.408 404.400 777.600 ;
    END
  END rx_flit[322]
  PIN rx_flit[323]
    DIRECTION OUTPUT ;
    USE SIGNAL ;
    SHAPE ABUTMENT ;
    PORT
      LAYER M5 ;
      RECT 404.424 777.408 404.448 777.600 ;
    END
  END rx_flit[323]
  PIN rx_flit[324]
    DIRECTION OUTPUT ;
    USE SIGNAL ;
    SHAPE ABUTMENT ;
    PORT
      LAYER M5 ;
      RECT 404.472 777.408 404.496 777.600 ;
    END
  END rx_flit[324]
  PIN rx_flit[325]
    DIRECTION OUTPUT ;
    USE SIGNAL ;
    SHAPE ABUTMENT ;
    PORT
      LAYER M5 ;
      RECT 404.520 777.408 404.544 777.600 ;
    END
  END rx_flit[325]
  PIN rx_flit[326]
    DIRECTION OUTPUT ;
    USE SIGNAL ;
    SHAPE ABUTMENT ;
    PORT
      LAYER M5 ;
      RECT 404.568 777.408 404.592 777.600 ;
    END
  END rx_flit[326]
  PIN rx_flit[327]
    DIRECTION OUTPUT ;
    USE SIGNAL ;
    SHAPE ABUTMENT ;
    PORT
      LAYER M5 ;
      RECT 404.616 777.408 404.640 777.600 ;
    END
  END rx_flit[327]
  PIN rx_flit[328]
    DIRECTION OUTPUT ;
    USE SIGNAL ;
    SHAPE ABUTMENT ;
    PORT
      LAYER M5 ;
      RECT 404.664 777.408 404.688 777.600 ;
    END
  END rx_flit[328]
  PIN rx_flit[329]
    DIRECTION OUTPUT ;
    USE SIGNAL ;
    SHAPE ABUTMENT ;
    PORT
      LAYER M5 ;
      RECT 404.712 777.408 404.736 777.600 ;
    END
  END rx_flit[329]
  PIN rx_flit[330]
    DIRECTION OUTPUT ;
    USE SIGNAL ;
    SHAPE ABUTMENT ;
    PORT
      LAYER M5 ;
      RECT 404.760 777.408 404.784 777.600 ;
    END
  END rx_flit[330]
  PIN rx_flit[331]
    DIRECTION OUTPUT ;
    USE SIGNAL ;
    SHAPE ABUTMENT ;
    PORT
      LAYER M5 ;
      RECT 404.808 777.408 404.832 777.600 ;
    END
  END rx_flit[331]
  PIN rx_flit[332]
    DIRECTION OUTPUT ;
    USE SIGNAL ;
    SHAPE ABUTMENT ;
    PORT
      LAYER M5 ;
      RECT 404.856 777.408 404.880 777.600 ;
    END
  END rx_flit[332]
  PIN rx_flit[333]
    DIRECTION OUTPUT ;
    USE SIGNAL ;
    SHAPE ABUTMENT ;
    PORT
      LAYER M5 ;
      RECT 404.904 777.408 404.928 777.600 ;
    END
  END rx_flit[333]
  PIN rx_flit[334]
    DIRECTION OUTPUT ;
    USE SIGNAL ;
    SHAPE ABUTMENT ;
    PORT
      LAYER M5 ;
      RECT 404.952 777.408 404.976 777.600 ;
    END
  END rx_flit[334]
  PIN rx_flit[335]
    DIRECTION OUTPUT ;
    USE SIGNAL ;
    SHAPE ABUTMENT ;
    PORT
      LAYER M5 ;
      RECT 405.000 777.408 405.024 777.600 ;
    END
  END rx_flit[335]
  PIN rx_flit[336]
    DIRECTION OUTPUT ;
    USE SIGNAL ;
    SHAPE ABUTMENT ;
    PORT
      LAYER M5 ;
      RECT 405.048 777.408 405.072 777.600 ;
    END
  END rx_flit[336]
  PIN rx_flit[337]
    DIRECTION OUTPUT ;
    USE SIGNAL ;
    SHAPE ABUTMENT ;
    PORT
      LAYER M5 ;
      RECT 405.096 777.408 405.120 777.600 ;
    END
  END rx_flit[337]
  PIN rx_flit[338]
    DIRECTION OUTPUT ;
    USE SIGNAL ;
    SHAPE ABUTMENT ;
    PORT
      LAYER M5 ;
      RECT 405.144 777.408 405.168 777.600 ;
    END
  END rx_flit[338]
  PIN rx_flit[339]
    DIRECTION OUTPUT ;
    USE SIGNAL ;
    SHAPE ABUTMENT ;
    PORT
      LAYER M5 ;
      RECT 405.192 777.408 405.216 777.600 ;
    END
  END rx_flit[339]
  PIN rx_flit[340]
    DIRECTION OUTPUT ;
    USE SIGNAL ;
    SHAPE ABUTMENT ;
    PORT
      LAYER M5 ;
      RECT 405.240 777.408 405.264 777.600 ;
    END
  END rx_flit[340]
  PIN rx_flit[341]
    DIRECTION OUTPUT ;
    USE SIGNAL ;
    SHAPE ABUTMENT ;
    PORT
      LAYER M5 ;
      RECT 405.288 777.408 405.312 777.600 ;
    END
  END rx_flit[341]
  PIN rx_flit[342]
    DIRECTION OUTPUT ;
    USE SIGNAL ;
    SHAPE ABUTMENT ;
    PORT
      LAYER M5 ;
      RECT 405.336 777.408 405.360 777.600 ;
    END
  END rx_flit[342]
  PIN rx_flit[343]
    DIRECTION OUTPUT ;
    USE SIGNAL ;
    SHAPE ABUTMENT ;
    PORT
      LAYER M5 ;
      RECT 405.384 777.408 405.408 777.600 ;
    END
  END rx_flit[343]
  PIN rx_flit[344]
    DIRECTION OUTPUT ;
    USE SIGNAL ;
    SHAPE ABUTMENT ;
    PORT
      LAYER M5 ;
      RECT 405.432 777.408 405.456 777.600 ;
    END
  END rx_flit[344]
  PIN rx_flit[345]
    DIRECTION OUTPUT ;
    USE SIGNAL ;
    SHAPE ABUTMENT ;
    PORT
      LAYER M5 ;
      RECT 405.480 777.408 405.504 777.600 ;
    END
  END rx_flit[345]
  PIN rx_flit[346]
    DIRECTION OUTPUT ;
    USE SIGNAL ;
    SHAPE ABUTMENT ;
    PORT
      LAYER M5 ;
      RECT 405.528 777.408 405.552 777.600 ;
    END
  END rx_flit[346]
  PIN rx_flit[347]
    DIRECTION OUTPUT ;
    USE SIGNAL ;
    SHAPE ABUTMENT ;
    PORT
      LAYER M5 ;
      RECT 405.576 777.408 405.600 777.600 ;
    END
  END rx_flit[347]
  PIN rx_flit[348]
    DIRECTION OUTPUT ;
    USE SIGNAL ;
    SHAPE ABUTMENT ;
    PORT
      LAYER M5 ;
      RECT 405.624 777.408 405.648 777.600 ;
    END
  END rx_flit[348]
  PIN rx_flit[349]
    DIRECTION OUTPUT ;
    USE SIGNAL ;
    SHAPE ABUTMENT ;
    PORT
      LAYER M5 ;
      RECT 405.672 777.408 405.696 777.600 ;
    END
  END rx_flit[349]
  PIN rx_flit[350]
    DIRECTION OUTPUT ;
    USE SIGNAL ;
    SHAPE ABUTMENT ;
    PORT
      LAYER M5 ;
      RECT 405.720 777.408 405.744 777.600 ;
    END
  END rx_flit[350]
  PIN rx_flit[351]
    DIRECTION OUTPUT ;
    USE SIGNAL ;
    SHAPE ABUTMENT ;
    PORT
      LAYER M5 ;
      RECT 405.768 777.408 405.792 777.600 ;
    END
  END rx_flit[351]
  PIN rx_flit[352]
    DIRECTION OUTPUT ;
    USE SIGNAL ;
    SHAPE ABUTMENT ;
    PORT
      LAYER M5 ;
      RECT 405.816 777.408 405.840 777.600 ;
    END
  END rx_flit[352]
  PIN rx_flit[353]
    DIRECTION OUTPUT ;
    USE SIGNAL ;
    SHAPE ABUTMENT ;
    PORT
      LAYER M5 ;
      RECT 405.864 777.408 405.888 777.600 ;
    END
  END rx_flit[353]
  PIN rx_flit[354]
    DIRECTION OUTPUT ;
    USE SIGNAL ;
    SHAPE ABUTMENT ;
    PORT
      LAYER M5 ;
      RECT 405.912 777.408 405.936 777.600 ;
    END
  END rx_flit[354]
  PIN rx_flit[355]
    DIRECTION OUTPUT ;
    USE SIGNAL ;
    SHAPE ABUTMENT ;
    PORT
      LAYER M5 ;
      RECT 405.960 777.408 405.984 777.600 ;
    END
  END rx_flit[355]
  PIN rx_flit[356]
    DIRECTION OUTPUT ;
    USE SIGNAL ;
    SHAPE ABUTMENT ;
    PORT
      LAYER M5 ;
      RECT 406.008 777.408 406.032 777.600 ;
    END
  END rx_flit[356]
  PIN rx_flit[357]
    DIRECTION OUTPUT ;
    USE SIGNAL ;
    SHAPE ABUTMENT ;
    PORT
      LAYER M5 ;
      RECT 406.056 777.408 406.080 777.600 ;
    END
  END rx_flit[357]
  PIN rx_flit[358]
    DIRECTION OUTPUT ;
    USE SIGNAL ;
    SHAPE ABUTMENT ;
    PORT
      LAYER M5 ;
      RECT 406.104 777.408 406.128 777.600 ;
    END
  END rx_flit[358]
  PIN rx_flit[359]
    DIRECTION OUTPUT ;
    USE SIGNAL ;
    SHAPE ABUTMENT ;
    PORT
      LAYER M5 ;
      RECT 406.152 777.408 406.176 777.600 ;
    END
  END rx_flit[359]
  PIN rx_flit[360]
    DIRECTION OUTPUT ;
    USE SIGNAL ;
    SHAPE ABUTMENT ;
    PORT
      LAYER M5 ;
      RECT 406.200 777.408 406.224 777.600 ;
    END
  END rx_flit[360]
  PIN rx_flit[361]
    DIRECTION OUTPUT ;
    USE SIGNAL ;
    SHAPE ABUTMENT ;
    PORT
      LAYER M5 ;
      RECT 406.248 777.408 406.272 777.600 ;
    END
  END rx_flit[361]
  PIN rx_flit[362]
    DIRECTION OUTPUT ;
    USE SIGNAL ;
    SHAPE ABUTMENT ;
    PORT
      LAYER M5 ;
      RECT 406.296 777.408 406.320 777.600 ;
    END
  END rx_flit[362]
  PIN rx_flit[363]
    DIRECTION OUTPUT ;
    USE SIGNAL ;
    SHAPE ABUTMENT ;
    PORT
      LAYER M5 ;
      RECT 406.344 777.408 406.368 777.600 ;
    END
  END rx_flit[363]
  PIN rx_flit[364]
    DIRECTION OUTPUT ;
    USE SIGNAL ;
    SHAPE ABUTMENT ;
    PORT
      LAYER M5 ;
      RECT 406.392 777.408 406.416 777.600 ;
    END
  END rx_flit[364]
  PIN rx_flit[365]
    DIRECTION OUTPUT ;
    USE SIGNAL ;
    SHAPE ABUTMENT ;
    PORT
      LAYER M5 ;
      RECT 406.440 777.408 406.464 777.600 ;
    END
  END rx_flit[365]
  PIN rx_flit[366]
    DIRECTION OUTPUT ;
    USE SIGNAL ;
    SHAPE ABUTMENT ;
    PORT
      LAYER M5 ;
      RECT 406.488 777.408 406.512 777.600 ;
    END
  END rx_flit[366]
  PIN rx_flit[367]
    DIRECTION OUTPUT ;
    USE SIGNAL ;
    SHAPE ABUTMENT ;
    PORT
      LAYER M5 ;
      RECT 406.536 777.408 406.560 777.600 ;
    END
  END rx_flit[367]
  PIN rx_flit[368]
    DIRECTION OUTPUT ;
    USE SIGNAL ;
    SHAPE ABUTMENT ;
    PORT
      LAYER M5 ;
      RECT 406.584 777.408 406.608 777.600 ;
    END
  END rx_flit[368]
  PIN rx_flit[369]
    DIRECTION OUTPUT ;
    USE SIGNAL ;
    SHAPE ABUTMENT ;
    PORT
      LAYER M5 ;
      RECT 406.632 777.408 406.656 777.600 ;
    END
  END rx_flit[369]
  PIN rx_flit[370]
    DIRECTION OUTPUT ;
    USE SIGNAL ;
    SHAPE ABUTMENT ;
    PORT
      LAYER M5 ;
      RECT 406.680 777.408 406.704 777.600 ;
    END
  END rx_flit[370]
  PIN rx_flit[371]
    DIRECTION OUTPUT ;
    USE SIGNAL ;
    SHAPE ABUTMENT ;
    PORT
      LAYER M5 ;
      RECT 406.728 777.408 406.752 777.600 ;
    END
  END rx_flit[371]
  PIN rx_flit[372]
    DIRECTION OUTPUT ;
    USE SIGNAL ;
    SHAPE ABUTMENT ;
    PORT
      LAYER M5 ;
      RECT 406.776 777.408 406.800 777.600 ;
    END
  END rx_flit[372]
  PIN rx_flit[373]
    DIRECTION OUTPUT ;
    USE SIGNAL ;
    SHAPE ABUTMENT ;
    PORT
      LAYER M5 ;
      RECT 406.824 777.408 406.848 777.600 ;
    END
  END rx_flit[373]
  PIN rx_flit[374]
    DIRECTION OUTPUT ;
    USE SIGNAL ;
    SHAPE ABUTMENT ;
    PORT
      LAYER M5 ;
      RECT 406.872 777.408 406.896 777.600 ;
    END
  END rx_flit[374]
  PIN rx_flit[375]
    DIRECTION OUTPUT ;
    USE SIGNAL ;
    SHAPE ABUTMENT ;
    PORT
      LAYER M5 ;
      RECT 406.920 777.408 406.944 777.600 ;
    END
  END rx_flit[375]
  PIN rx_flit[376]
    DIRECTION OUTPUT ;
    USE SIGNAL ;
    SHAPE ABUTMENT ;
    PORT
      LAYER M5 ;
      RECT 406.968 777.408 406.992 777.600 ;
    END
  END rx_flit[376]
  PIN rx_flit[377]
    DIRECTION OUTPUT ;
    USE SIGNAL ;
    SHAPE ABUTMENT ;
    PORT
      LAYER M5 ;
      RECT 407.016 777.408 407.040 777.600 ;
    END
  END rx_flit[377]
  PIN rx_flit[378]
    DIRECTION OUTPUT ;
    USE SIGNAL ;
    SHAPE ABUTMENT ;
    PORT
      LAYER M5 ;
      RECT 407.064 777.408 407.088 777.600 ;
    END
  END rx_flit[378]
  PIN rx_flit[379]
    DIRECTION OUTPUT ;
    USE SIGNAL ;
    SHAPE ABUTMENT ;
    PORT
      LAYER M5 ;
      RECT 407.112 777.408 407.136 777.600 ;
    END
  END rx_flit[379]
  PIN rx_flit[380]
    DIRECTION OUTPUT ;
    USE SIGNAL ;
    SHAPE ABUTMENT ;
    PORT
      LAYER M5 ;
      RECT 407.160 777.408 407.184 777.600 ;
    END
  END rx_flit[380]
  PIN rx_flit[381]
    DIRECTION OUTPUT ;
    USE SIGNAL ;
    SHAPE ABUTMENT ;
    PORT
      LAYER M5 ;
      RECT 407.208 777.408 407.232 777.600 ;
    END
  END rx_flit[381]
  PIN rx_flit[382]
    DIRECTION OUTPUT ;
    USE SIGNAL ;
    SHAPE ABUTMENT ;
    PORT
      LAYER M5 ;
      RECT 407.256 777.408 407.280 777.600 ;
    END
  END rx_flit[382]
  PIN rx_flit[383]
    DIRECTION OUTPUT ;
    USE SIGNAL ;
    SHAPE ABUTMENT ;
    PORT
      LAYER M5 ;
      RECT 407.304 777.408 407.328 777.600 ;
    END
  END rx_flit[383]
  PIN rx_flit[384]
    DIRECTION OUTPUT ;
    USE SIGNAL ;
    SHAPE ABUTMENT ;
    PORT
      LAYER M5 ;
      RECT 407.352 777.408 407.376 777.600 ;
    END
  END rx_flit[384]
  PIN rx_flit[385]
    DIRECTION OUTPUT ;
    USE SIGNAL ;
    SHAPE ABUTMENT ;
    PORT
      LAYER M5 ;
      RECT 407.400 777.408 407.424 777.600 ;
    END
  END rx_flit[385]
  PIN rx_flit[386]
    DIRECTION OUTPUT ;
    USE SIGNAL ;
    SHAPE ABUTMENT ;
    PORT
      LAYER M5 ;
      RECT 407.448 777.408 407.472 777.600 ;
    END
  END rx_flit[386]
  PIN rx_flit[387]
    DIRECTION OUTPUT ;
    USE SIGNAL ;
    SHAPE ABUTMENT ;
    PORT
      LAYER M5 ;
      RECT 407.496 777.408 407.520 777.600 ;
    END
  END rx_flit[387]
  PIN rx_flit[388]
    DIRECTION OUTPUT ;
    USE SIGNAL ;
    SHAPE ABUTMENT ;
    PORT
      LAYER M5 ;
      RECT 407.544 777.408 407.568 777.600 ;
    END
  END rx_flit[388]
  PIN rx_flit[389]
    DIRECTION OUTPUT ;
    USE SIGNAL ;
    SHAPE ABUTMENT ;
    PORT
      LAYER M5 ;
      RECT 407.592 777.408 407.616 777.600 ;
    END
  END rx_flit[389]
  PIN rx_flit[390]
    DIRECTION OUTPUT ;
    USE SIGNAL ;
    SHAPE ABUTMENT ;
    PORT
      LAYER M5 ;
      RECT 407.640 777.408 407.664 777.600 ;
    END
  END rx_flit[390]
  PIN rx_flit[391]
    DIRECTION OUTPUT ;
    USE SIGNAL ;
    SHAPE ABUTMENT ;
    PORT
      LAYER M5 ;
      RECT 407.688 777.408 407.712 777.600 ;
    END
  END rx_flit[391]
  PIN rx_flit[392]
    DIRECTION OUTPUT ;
    USE SIGNAL ;
    SHAPE ABUTMENT ;
    PORT
      LAYER M5 ;
      RECT 407.736 777.408 407.760 777.600 ;
    END
  END rx_flit[392]
  PIN rx_flit[393]
    DIRECTION OUTPUT ;
    USE SIGNAL ;
    SHAPE ABUTMENT ;
    PORT
      LAYER M5 ;
      RECT 407.784 777.408 407.808 777.600 ;
    END
  END rx_flit[393]
  PIN rx_flit[394]
    DIRECTION OUTPUT ;
    USE SIGNAL ;
    SHAPE ABUTMENT ;
    PORT
      LAYER M5 ;
      RECT 407.832 777.408 407.856 777.600 ;
    END
  END rx_flit[394]
  PIN rx_flit[395]
    DIRECTION OUTPUT ;
    USE SIGNAL ;
    SHAPE ABUTMENT ;
    PORT
      LAYER M5 ;
      RECT 407.880 777.408 407.904 777.600 ;
    END
  END rx_flit[395]
  PIN rx_flit[396]
    DIRECTION OUTPUT ;
    USE SIGNAL ;
    SHAPE ABUTMENT ;
    PORT
      LAYER M5 ;
      RECT 407.928 777.408 407.952 777.600 ;
    END
  END rx_flit[396]
  PIN rx_flit[397]
    DIRECTION OUTPUT ;
    USE SIGNAL ;
    SHAPE ABUTMENT ;
    PORT
      LAYER M5 ;
      RECT 407.976 777.408 408.000 777.600 ;
    END
  END rx_flit[397]
  PIN rx_flit[398]
    DIRECTION OUTPUT ;
    USE SIGNAL ;
    SHAPE ABUTMENT ;
    PORT
      LAYER M5 ;
      RECT 408.024 777.408 408.048 777.600 ;
    END
  END rx_flit[398]
  PIN rx_flit[399]
    DIRECTION OUTPUT ;
    USE SIGNAL ;
    SHAPE ABUTMENT ;
    PORT
      LAYER M5 ;
      RECT 408.072 777.408 408.096 777.600 ;
    END
  END rx_flit[399]
  PIN rx_flit[400]
    DIRECTION OUTPUT ;
    USE SIGNAL ;
    SHAPE ABUTMENT ;
    PORT
      LAYER M5 ;
      RECT 408.120 777.408 408.144 777.600 ;
    END
  END rx_flit[400]
  PIN rx_flit[401]
    DIRECTION OUTPUT ;
    USE SIGNAL ;
    SHAPE ABUTMENT ;
    PORT
      LAYER M5 ;
      RECT 408.168 777.408 408.192 777.600 ;
    END
  END rx_flit[401]
  PIN rx_flit[402]
    DIRECTION OUTPUT ;
    USE SIGNAL ;
    SHAPE ABUTMENT ;
    PORT
      LAYER M5 ;
      RECT 408.216 777.408 408.240 777.600 ;
    END
  END rx_flit[402]
  PIN rx_flit[403]
    DIRECTION OUTPUT ;
    USE SIGNAL ;
    SHAPE ABUTMENT ;
    PORT
      LAYER M5 ;
      RECT 408.264 777.408 408.288 777.600 ;
    END
  END rx_flit[403]
  PIN rx_flit[404]
    DIRECTION OUTPUT ;
    USE SIGNAL ;
    SHAPE ABUTMENT ;
    PORT
      LAYER M5 ;
      RECT 408.312 777.408 408.336 777.600 ;
    END
  END rx_flit[404]
  PIN rx_flit[405]
    DIRECTION OUTPUT ;
    USE SIGNAL ;
    SHAPE ABUTMENT ;
    PORT
      LAYER M5 ;
      RECT 408.360 777.408 408.384 777.600 ;
    END
  END rx_flit[405]
  PIN rx_flit[406]
    DIRECTION OUTPUT ;
    USE SIGNAL ;
    SHAPE ABUTMENT ;
    PORT
      LAYER M5 ;
      RECT 408.408 777.408 408.432 777.600 ;
    END
  END rx_flit[406]
  PIN rx_flit[407]
    DIRECTION OUTPUT ;
    USE SIGNAL ;
    SHAPE ABUTMENT ;
    PORT
      LAYER M5 ;
      RECT 408.456 777.408 408.480 777.600 ;
    END
  END rx_flit[407]
  PIN rx_flit[408]
    DIRECTION OUTPUT ;
    USE SIGNAL ;
    SHAPE ABUTMENT ;
    PORT
      LAYER M5 ;
      RECT 408.504 777.408 408.528 777.600 ;
    END
  END rx_flit[408]
  PIN rx_flit[409]
    DIRECTION OUTPUT ;
    USE SIGNAL ;
    SHAPE ABUTMENT ;
    PORT
      LAYER M5 ;
      RECT 408.552 777.408 408.576 777.600 ;
    END
  END rx_flit[409]
  PIN rx_flit[410]
    DIRECTION OUTPUT ;
    USE SIGNAL ;
    SHAPE ABUTMENT ;
    PORT
      LAYER M5 ;
      RECT 408.600 777.408 408.624 777.600 ;
    END
  END rx_flit[410]
  PIN rx_flit[411]
    DIRECTION OUTPUT ;
    USE SIGNAL ;
    SHAPE ABUTMENT ;
    PORT
      LAYER M5 ;
      RECT 408.648 777.408 408.672 777.600 ;
    END
  END rx_flit[411]
  PIN rx_flit[412]
    DIRECTION OUTPUT ;
    USE SIGNAL ;
    SHAPE ABUTMENT ;
    PORT
      LAYER M5 ;
      RECT 408.696 777.408 408.720 777.600 ;
    END
  END rx_flit[412]
  PIN rx_flit[413]
    DIRECTION OUTPUT ;
    USE SIGNAL ;
    SHAPE ABUTMENT ;
    PORT
      LAYER M5 ;
      RECT 408.744 777.408 408.768 777.600 ;
    END
  END rx_flit[413]
  PIN rx_flit[414]
    DIRECTION OUTPUT ;
    USE SIGNAL ;
    SHAPE ABUTMENT ;
    PORT
      LAYER M5 ;
      RECT 408.792 777.408 408.816 777.600 ;
    END
  END rx_flit[414]
  PIN rx_flit[415]
    DIRECTION OUTPUT ;
    USE SIGNAL ;
    SHAPE ABUTMENT ;
    PORT
      LAYER M5 ;
      RECT 408.840 777.408 408.864 777.600 ;
    END
  END rx_flit[415]
  PIN rx_flit[416]
    DIRECTION OUTPUT ;
    USE SIGNAL ;
    SHAPE ABUTMENT ;
    PORT
      LAYER M5 ;
      RECT 408.888 777.408 408.912 777.600 ;
    END
  END rx_flit[416]
  PIN rx_flit[417]
    DIRECTION OUTPUT ;
    USE SIGNAL ;
    SHAPE ABUTMENT ;
    PORT
      LAYER M5 ;
      RECT 408.936 777.408 408.960 777.600 ;
    END
  END rx_flit[417]
  PIN rx_flit[418]
    DIRECTION OUTPUT ;
    USE SIGNAL ;
    SHAPE ABUTMENT ;
    PORT
      LAYER M5 ;
      RECT 408.984 777.408 409.008 777.600 ;
    END
  END rx_flit[418]
  PIN rx_flit[419]
    DIRECTION OUTPUT ;
    USE SIGNAL ;
    SHAPE ABUTMENT ;
    PORT
      LAYER M5 ;
      RECT 409.032 777.408 409.056 777.600 ;
    END
  END rx_flit[419]
  PIN rx_flit[420]
    DIRECTION OUTPUT ;
    USE SIGNAL ;
    SHAPE ABUTMENT ;
    PORT
      LAYER M5 ;
      RECT 409.080 777.408 409.104 777.600 ;
    END
  END rx_flit[420]
  PIN rx_flit[421]
    DIRECTION OUTPUT ;
    USE SIGNAL ;
    SHAPE ABUTMENT ;
    PORT
      LAYER M5 ;
      RECT 409.128 777.408 409.152 777.600 ;
    END
  END rx_flit[421]
  PIN rx_flit[422]
    DIRECTION OUTPUT ;
    USE SIGNAL ;
    SHAPE ABUTMENT ;
    PORT
      LAYER M5 ;
      RECT 409.176 777.408 409.200 777.600 ;
    END
  END rx_flit[422]
  PIN rx_flit[423]
    DIRECTION OUTPUT ;
    USE SIGNAL ;
    SHAPE ABUTMENT ;
    PORT
      LAYER M5 ;
      RECT 409.224 777.408 409.248 777.600 ;
    END
  END rx_flit[423]
  PIN rx_flit[424]
    DIRECTION OUTPUT ;
    USE SIGNAL ;
    SHAPE ABUTMENT ;
    PORT
      LAYER M5 ;
      RECT 409.272 777.408 409.296 777.600 ;
    END
  END rx_flit[424]
  PIN rx_flit[425]
    DIRECTION OUTPUT ;
    USE SIGNAL ;
    SHAPE ABUTMENT ;
    PORT
      LAYER M5 ;
      RECT 409.320 777.408 409.344 777.600 ;
    END
  END rx_flit[425]
  PIN rx_flit[426]
    DIRECTION OUTPUT ;
    USE SIGNAL ;
    SHAPE ABUTMENT ;
    PORT
      LAYER M5 ;
      RECT 409.368 777.408 409.392 777.600 ;
    END
  END rx_flit[426]
  PIN rx_flit[427]
    DIRECTION OUTPUT ;
    USE SIGNAL ;
    SHAPE ABUTMENT ;
    PORT
      LAYER M5 ;
      RECT 409.416 777.408 409.440 777.600 ;
    END
  END rx_flit[427]
  PIN rx_flit[428]
    DIRECTION OUTPUT ;
    USE SIGNAL ;
    SHAPE ABUTMENT ;
    PORT
      LAYER M5 ;
      RECT 409.464 777.408 409.488 777.600 ;
    END
  END rx_flit[428]
  PIN rx_flit[429]
    DIRECTION OUTPUT ;
    USE SIGNAL ;
    SHAPE ABUTMENT ;
    PORT
      LAYER M5 ;
      RECT 409.512 777.408 409.536 777.600 ;
    END
  END rx_flit[429]
  PIN rx_flit[430]
    DIRECTION OUTPUT ;
    USE SIGNAL ;
    SHAPE ABUTMENT ;
    PORT
      LAYER M5 ;
      RECT 409.560 777.408 409.584 777.600 ;
    END
  END rx_flit[430]
  PIN rx_flit[431]
    DIRECTION OUTPUT ;
    USE SIGNAL ;
    SHAPE ABUTMENT ;
    PORT
      LAYER M5 ;
      RECT 409.608 777.408 409.632 777.600 ;
    END
  END rx_flit[431]
  PIN rx_flit[432]
    DIRECTION OUTPUT ;
    USE SIGNAL ;
    SHAPE ABUTMENT ;
    PORT
      LAYER M5 ;
      RECT 409.656 777.408 409.680 777.600 ;
    END
  END rx_flit[432]
  PIN rx_flit[433]
    DIRECTION OUTPUT ;
    USE SIGNAL ;
    SHAPE ABUTMENT ;
    PORT
      LAYER M5 ;
      RECT 409.704 777.408 409.728 777.600 ;
    END
  END rx_flit[433]
  PIN rx_flit[434]
    DIRECTION OUTPUT ;
    USE SIGNAL ;
    SHAPE ABUTMENT ;
    PORT
      LAYER M5 ;
      RECT 409.752 777.408 409.776 777.600 ;
    END
  END rx_flit[434]
  PIN rx_flit[435]
    DIRECTION OUTPUT ;
    USE SIGNAL ;
    SHAPE ABUTMENT ;
    PORT
      LAYER M5 ;
      RECT 409.800 777.408 409.824 777.600 ;
    END
  END rx_flit[435]
  PIN rx_flit[436]
    DIRECTION OUTPUT ;
    USE SIGNAL ;
    SHAPE ABUTMENT ;
    PORT
      LAYER M5 ;
      RECT 409.848 777.408 409.872 777.600 ;
    END
  END rx_flit[436]
  PIN rx_flit[437]
    DIRECTION OUTPUT ;
    USE SIGNAL ;
    SHAPE ABUTMENT ;
    PORT
      LAYER M5 ;
      RECT 409.896 777.408 409.920 777.600 ;
    END
  END rx_flit[437]
  PIN rx_flit[438]
    DIRECTION OUTPUT ;
    USE SIGNAL ;
    SHAPE ABUTMENT ;
    PORT
      LAYER M5 ;
      RECT 409.944 777.408 409.968 777.600 ;
    END
  END rx_flit[438]
  PIN rx_flit[439]
    DIRECTION OUTPUT ;
    USE SIGNAL ;
    SHAPE ABUTMENT ;
    PORT
      LAYER M5 ;
      RECT 409.992 777.408 410.016 777.600 ;
    END
  END rx_flit[439]
  PIN rx_flit[440]
    DIRECTION OUTPUT ;
    USE SIGNAL ;
    SHAPE ABUTMENT ;
    PORT
      LAYER M5 ;
      RECT 410.040 777.408 410.064 777.600 ;
    END
  END rx_flit[440]
  PIN rx_flit[441]
    DIRECTION OUTPUT ;
    USE SIGNAL ;
    SHAPE ABUTMENT ;
    PORT
      LAYER M5 ;
      RECT 410.088 777.408 410.112 777.600 ;
    END
  END rx_flit[441]
  PIN rx_flit[442]
    DIRECTION OUTPUT ;
    USE SIGNAL ;
    SHAPE ABUTMENT ;
    PORT
      LAYER M5 ;
      RECT 410.136 777.408 410.160 777.600 ;
    END
  END rx_flit[442]
  PIN rx_flit[443]
    DIRECTION OUTPUT ;
    USE SIGNAL ;
    SHAPE ABUTMENT ;
    PORT
      LAYER M5 ;
      RECT 410.184 777.408 410.208 777.600 ;
    END
  END rx_flit[443]
  PIN rx_flit[444]
    DIRECTION OUTPUT ;
    USE SIGNAL ;
    SHAPE ABUTMENT ;
    PORT
      LAYER M5 ;
      RECT 410.232 777.408 410.256 777.600 ;
    END
  END rx_flit[444]
  PIN rx_flit[445]
    DIRECTION OUTPUT ;
    USE SIGNAL ;
    SHAPE ABUTMENT ;
    PORT
      LAYER M5 ;
      RECT 410.280 777.408 410.304 777.600 ;
    END
  END rx_flit[445]
  PIN rx_flit[446]
    DIRECTION OUTPUT ;
    USE SIGNAL ;
    SHAPE ABUTMENT ;
    PORT
      LAYER M5 ;
      RECT 410.328 777.408 410.352 777.600 ;
    END
  END rx_flit[446]
  PIN rx_flit[447]
    DIRECTION OUTPUT ;
    USE SIGNAL ;
    SHAPE ABUTMENT ;
    PORT
      LAYER M5 ;
      RECT 410.376 777.408 410.400 777.600 ;
    END
  END rx_flit[447]
  PIN rx_flit[448]
    DIRECTION OUTPUT ;
    USE SIGNAL ;
    SHAPE ABUTMENT ;
    PORT
      LAYER M5 ;
      RECT 410.424 777.408 410.448 777.600 ;
    END
  END rx_flit[448]
  PIN rx_flit[449]
    DIRECTION OUTPUT ;
    USE SIGNAL ;
    SHAPE ABUTMENT ;
    PORT
      LAYER M5 ;
      RECT 410.472 777.408 410.496 777.600 ;
    END
  END rx_flit[449]
  PIN rx_flit[450]
    DIRECTION OUTPUT ;
    USE SIGNAL ;
    SHAPE ABUTMENT ;
    PORT
      LAYER M5 ;
      RECT 410.520 777.408 410.544 777.600 ;
    END
  END rx_flit[450]
  PIN rx_flit[451]
    DIRECTION OUTPUT ;
    USE SIGNAL ;
    SHAPE ABUTMENT ;
    PORT
      LAYER M5 ;
      RECT 410.568 777.408 410.592 777.600 ;
    END
  END rx_flit[451]
  PIN rx_flit[452]
    DIRECTION OUTPUT ;
    USE SIGNAL ;
    SHAPE ABUTMENT ;
    PORT
      LAYER M5 ;
      RECT 410.616 777.408 410.640 777.600 ;
    END
  END rx_flit[452]
  PIN rx_flit[453]
    DIRECTION OUTPUT ;
    USE SIGNAL ;
    SHAPE ABUTMENT ;
    PORT
      LAYER M5 ;
      RECT 410.664 777.408 410.688 777.600 ;
    END
  END rx_flit[453]
  PIN rx_flit[454]
    DIRECTION OUTPUT ;
    USE SIGNAL ;
    SHAPE ABUTMENT ;
    PORT
      LAYER M5 ;
      RECT 410.712 777.408 410.736 777.600 ;
    END
  END rx_flit[454]
  PIN rx_flit[455]
    DIRECTION OUTPUT ;
    USE SIGNAL ;
    SHAPE ABUTMENT ;
    PORT
      LAYER M5 ;
      RECT 410.760 777.408 410.784 777.600 ;
    END
  END rx_flit[455]
  PIN rx_flit[456]
    DIRECTION OUTPUT ;
    USE SIGNAL ;
    SHAPE ABUTMENT ;
    PORT
      LAYER M5 ;
      RECT 410.808 777.408 410.832 777.600 ;
    END
  END rx_flit[456]
  PIN rx_flit[457]
    DIRECTION OUTPUT ;
    USE SIGNAL ;
    SHAPE ABUTMENT ;
    PORT
      LAYER M5 ;
      RECT 410.856 777.408 410.880 777.600 ;
    END
  END rx_flit[457]
  PIN rx_flit[458]
    DIRECTION OUTPUT ;
    USE SIGNAL ;
    SHAPE ABUTMENT ;
    PORT
      LAYER M5 ;
      RECT 410.904 777.408 410.928 777.600 ;
    END
  END rx_flit[458]
  PIN rx_flit[459]
    DIRECTION OUTPUT ;
    USE SIGNAL ;
    SHAPE ABUTMENT ;
    PORT
      LAYER M5 ;
      RECT 410.952 777.408 410.976 777.600 ;
    END
  END rx_flit[459]
  PIN rx_flit[460]
    DIRECTION OUTPUT ;
    USE SIGNAL ;
    SHAPE ABUTMENT ;
    PORT
      LAYER M5 ;
      RECT 411.000 777.408 411.024 777.600 ;
    END
  END rx_flit[460]
  PIN rx_flit[461]
    DIRECTION OUTPUT ;
    USE SIGNAL ;
    SHAPE ABUTMENT ;
    PORT
      LAYER M5 ;
      RECT 411.048 777.408 411.072 777.600 ;
    END
  END rx_flit[461]
  PIN rx_flit[462]
    DIRECTION OUTPUT ;
    USE SIGNAL ;
    SHAPE ABUTMENT ;
    PORT
      LAYER M5 ;
      RECT 411.096 777.408 411.120 777.600 ;
    END
  END rx_flit[462]
  PIN rx_flit[463]
    DIRECTION OUTPUT ;
    USE SIGNAL ;
    SHAPE ABUTMENT ;
    PORT
      LAYER M5 ;
      RECT 411.144 777.408 411.168 777.600 ;
    END
  END rx_flit[463]
  PIN rx_flit[464]
    DIRECTION OUTPUT ;
    USE SIGNAL ;
    SHAPE ABUTMENT ;
    PORT
      LAYER M5 ;
      RECT 411.192 777.408 411.216 777.600 ;
    END
  END rx_flit[464]
  PIN rx_flit[465]
    DIRECTION OUTPUT ;
    USE SIGNAL ;
    SHAPE ABUTMENT ;
    PORT
      LAYER M5 ;
      RECT 411.240 777.408 411.264 777.600 ;
    END
  END rx_flit[465]
  PIN rx_flit[466]
    DIRECTION OUTPUT ;
    USE SIGNAL ;
    SHAPE ABUTMENT ;
    PORT
      LAYER M5 ;
      RECT 411.288 777.408 411.312 777.600 ;
    END
  END rx_flit[466]
  PIN rx_flit[467]
    DIRECTION OUTPUT ;
    USE SIGNAL ;
    SHAPE ABUTMENT ;
    PORT
      LAYER M5 ;
      RECT 411.336 777.408 411.360 777.600 ;
    END
  END rx_flit[467]
  PIN rx_flit[468]
    DIRECTION OUTPUT ;
    USE SIGNAL ;
    SHAPE ABUTMENT ;
    PORT
      LAYER M5 ;
      RECT 411.384 777.408 411.408 777.600 ;
    END
  END rx_flit[468]
  PIN rx_flit[469]
    DIRECTION OUTPUT ;
    USE SIGNAL ;
    SHAPE ABUTMENT ;
    PORT
      LAYER M5 ;
      RECT 411.432 777.408 411.456 777.600 ;
    END
  END rx_flit[469]
  PIN rx_flit[470]
    DIRECTION OUTPUT ;
    USE SIGNAL ;
    SHAPE ABUTMENT ;
    PORT
      LAYER M5 ;
      RECT 411.480 777.408 411.504 777.600 ;
    END
  END rx_flit[470]
  PIN rx_flit[471]
    DIRECTION OUTPUT ;
    USE SIGNAL ;
    SHAPE ABUTMENT ;
    PORT
      LAYER M5 ;
      RECT 411.528 777.408 411.552 777.600 ;
    END
  END rx_flit[471]
  PIN rx_flit[472]
    DIRECTION OUTPUT ;
    USE SIGNAL ;
    SHAPE ABUTMENT ;
    PORT
      LAYER M5 ;
      RECT 411.576 777.408 411.600 777.600 ;
    END
  END rx_flit[472]
  PIN rx_flit[473]
    DIRECTION OUTPUT ;
    USE SIGNAL ;
    SHAPE ABUTMENT ;
    PORT
      LAYER M5 ;
      RECT 411.624 777.408 411.648 777.600 ;
    END
  END rx_flit[473]
  PIN rx_flit[474]
    DIRECTION OUTPUT ;
    USE SIGNAL ;
    SHAPE ABUTMENT ;
    PORT
      LAYER M5 ;
      RECT 411.672 777.408 411.696 777.600 ;
    END
  END rx_flit[474]
  PIN rx_flit[475]
    DIRECTION OUTPUT ;
    USE SIGNAL ;
    SHAPE ABUTMENT ;
    PORT
      LAYER M5 ;
      RECT 411.720 777.408 411.744 777.600 ;
    END
  END rx_flit[475]
  PIN rx_flit[476]
    DIRECTION OUTPUT ;
    USE SIGNAL ;
    SHAPE ABUTMENT ;
    PORT
      LAYER M5 ;
      RECT 411.768 777.408 411.792 777.600 ;
    END
  END rx_flit[476]
  PIN rx_flit[477]
    DIRECTION OUTPUT ;
    USE SIGNAL ;
    SHAPE ABUTMENT ;
    PORT
      LAYER M5 ;
      RECT 411.816 777.408 411.840 777.600 ;
    END
  END rx_flit[477]
  PIN rx_flit[478]
    DIRECTION OUTPUT ;
    USE SIGNAL ;
    SHAPE ABUTMENT ;
    PORT
      LAYER M5 ;
      RECT 411.864 777.408 411.888 777.600 ;
    END
  END rx_flit[478]
  PIN rx_flit[479]
    DIRECTION OUTPUT ;
    USE SIGNAL ;
    SHAPE ABUTMENT ;
    PORT
      LAYER M5 ;
      RECT 411.912 777.408 411.936 777.600 ;
    END
  END rx_flit[479]
  PIN rx_flit[480]
    DIRECTION OUTPUT ;
    USE SIGNAL ;
    SHAPE ABUTMENT ;
    PORT
      LAYER M5 ;
      RECT 411.960 777.408 411.984 777.600 ;
    END
  END rx_flit[480]
  PIN rx_flit[481]
    DIRECTION OUTPUT ;
    USE SIGNAL ;
    SHAPE ABUTMENT ;
    PORT
      LAYER M5 ;
      RECT 412.008 777.408 412.032 777.600 ;
    END
  END rx_flit[481]
  PIN rx_flit[482]
    DIRECTION OUTPUT ;
    USE SIGNAL ;
    SHAPE ABUTMENT ;
    PORT
      LAYER M5 ;
      RECT 412.056 777.408 412.080 777.600 ;
    END
  END rx_flit[482]
  PIN rx_flit[483]
    DIRECTION OUTPUT ;
    USE SIGNAL ;
    SHAPE ABUTMENT ;
    PORT
      LAYER M5 ;
      RECT 412.104 777.408 412.128 777.600 ;
    END
  END rx_flit[483]
  PIN rx_flit[484]
    DIRECTION OUTPUT ;
    USE SIGNAL ;
    SHAPE ABUTMENT ;
    PORT
      LAYER M5 ;
      RECT 412.152 777.408 412.176 777.600 ;
    END
  END rx_flit[484]
  PIN rx_flit[485]
    DIRECTION OUTPUT ;
    USE SIGNAL ;
    SHAPE ABUTMENT ;
    PORT
      LAYER M5 ;
      RECT 412.200 777.408 412.224 777.600 ;
    END
  END rx_flit[485]
  PIN rx_flit[486]
    DIRECTION OUTPUT ;
    USE SIGNAL ;
    SHAPE ABUTMENT ;
    PORT
      LAYER M5 ;
      RECT 412.248 777.408 412.272 777.600 ;
    END
  END rx_flit[486]
  PIN rx_flit[487]
    DIRECTION OUTPUT ;
    USE SIGNAL ;
    SHAPE ABUTMENT ;
    PORT
      LAYER M5 ;
      RECT 412.296 777.408 412.320 777.600 ;
    END
  END rx_flit[487]
  PIN rx_flit[488]
    DIRECTION OUTPUT ;
    USE SIGNAL ;
    SHAPE ABUTMENT ;
    PORT
      LAYER M5 ;
      RECT 412.344 777.408 412.368 777.600 ;
    END
  END rx_flit[488]
  PIN rx_flit[489]
    DIRECTION OUTPUT ;
    USE SIGNAL ;
    SHAPE ABUTMENT ;
    PORT
      LAYER M5 ;
      RECT 412.392 777.408 412.416 777.600 ;
    END
  END rx_flit[489]
  PIN rx_flit[490]
    DIRECTION OUTPUT ;
    USE SIGNAL ;
    SHAPE ABUTMENT ;
    PORT
      LAYER M5 ;
      RECT 412.440 777.408 412.464 777.600 ;
    END
  END rx_flit[490]
  PIN rx_flit[491]
    DIRECTION OUTPUT ;
    USE SIGNAL ;
    SHAPE ABUTMENT ;
    PORT
      LAYER M5 ;
      RECT 412.488 777.408 412.512 777.600 ;
    END
  END rx_flit[491]
  PIN rx_flit[492]
    DIRECTION OUTPUT ;
    USE SIGNAL ;
    SHAPE ABUTMENT ;
    PORT
      LAYER M5 ;
      RECT 412.536 777.408 412.560 777.600 ;
    END
  END rx_flit[492]
  PIN rx_flit[493]
    DIRECTION OUTPUT ;
    USE SIGNAL ;
    SHAPE ABUTMENT ;
    PORT
      LAYER M5 ;
      RECT 412.584 777.408 412.608 777.600 ;
    END
  END rx_flit[493]
  PIN rx_flit[494]
    DIRECTION OUTPUT ;
    USE SIGNAL ;
    SHAPE ABUTMENT ;
    PORT
      LAYER M5 ;
      RECT 412.632 777.408 412.656 777.600 ;
    END
  END rx_flit[494]
  PIN rx_flit[495]
    DIRECTION OUTPUT ;
    USE SIGNAL ;
    SHAPE ABUTMENT ;
    PORT
      LAYER M5 ;
      RECT 412.680 777.408 412.704 777.600 ;
    END
  END rx_flit[495]
  PIN rx_flit[496]
    DIRECTION OUTPUT ;
    USE SIGNAL ;
    SHAPE ABUTMENT ;
    PORT
      LAYER M5 ;
      RECT 412.728 777.408 412.752 777.600 ;
    END
  END rx_flit[496]
  PIN rx_flit[497]
    DIRECTION OUTPUT ;
    USE SIGNAL ;
    SHAPE ABUTMENT ;
    PORT
      LAYER M5 ;
      RECT 412.776 777.408 412.800 777.600 ;
    END
  END rx_flit[497]
  PIN rx_flit[498]
    DIRECTION OUTPUT ;
    USE SIGNAL ;
    SHAPE ABUTMENT ;
    PORT
      LAYER M5 ;
      RECT 412.824 777.408 412.848 777.600 ;
    END
  END rx_flit[498]
  PIN rx_flit[499]
    DIRECTION OUTPUT ;
    USE SIGNAL ;
    SHAPE ABUTMENT ;
    PORT
      LAYER M5 ;
      RECT 412.872 777.408 412.896 777.600 ;
    END
  END rx_flit[499]
  PIN rx_flit[500]
    DIRECTION OUTPUT ;
    USE SIGNAL ;
    SHAPE ABUTMENT ;
    PORT
      LAYER M5 ;
      RECT 412.920 777.408 412.944 777.600 ;
    END
  END rx_flit[500]
  PIN rx_flit[501]
    DIRECTION OUTPUT ;
    USE SIGNAL ;
    SHAPE ABUTMENT ;
    PORT
      LAYER M5 ;
      RECT 412.968 777.408 412.992 777.600 ;
    END
  END rx_flit[501]
  PIN rx_flit[502]
    DIRECTION OUTPUT ;
    USE SIGNAL ;
    SHAPE ABUTMENT ;
    PORT
      LAYER M5 ;
      RECT 413.016 777.408 413.040 777.600 ;
    END
  END rx_flit[502]
  PIN rx_flit[503]
    DIRECTION OUTPUT ;
    USE SIGNAL ;
    SHAPE ABUTMENT ;
    PORT
      LAYER M5 ;
      RECT 413.064 777.408 413.088 777.600 ;
    END
  END rx_flit[503]
  PIN rx_flit[504]
    DIRECTION OUTPUT ;
    USE SIGNAL ;
    SHAPE ABUTMENT ;
    PORT
      LAYER M5 ;
      RECT 413.112 777.408 413.136 777.600 ;
    END
  END rx_flit[504]
  PIN rx_flit[505]
    DIRECTION OUTPUT ;
    USE SIGNAL ;
    SHAPE ABUTMENT ;
    PORT
      LAYER M5 ;
      RECT 413.160 777.408 413.184 777.600 ;
    END
  END rx_flit[505]
  PIN rx_flit[506]
    DIRECTION OUTPUT ;
    USE SIGNAL ;
    SHAPE ABUTMENT ;
    PORT
      LAYER M5 ;
      RECT 413.208 777.408 413.232 777.600 ;
    END
  END rx_flit[506]
  PIN rx_flit[507]
    DIRECTION OUTPUT ;
    USE SIGNAL ;
    SHAPE ABUTMENT ;
    PORT
      LAYER M5 ;
      RECT 413.256 777.408 413.280 777.600 ;
    END
  END rx_flit[507]
  PIN rx_flit[508]
    DIRECTION OUTPUT ;
    USE SIGNAL ;
    SHAPE ABUTMENT ;
    PORT
      LAYER M5 ;
      RECT 413.304 777.408 413.328 777.600 ;
    END
  END rx_flit[508]
  PIN rx_flit[509]
    DIRECTION OUTPUT ;
    USE SIGNAL ;
    SHAPE ABUTMENT ;
    PORT
      LAYER M5 ;
      RECT 413.352 777.408 413.376 777.600 ;
    END
  END rx_flit[509]
  PIN rx_flit[510]
    DIRECTION OUTPUT ;
    USE SIGNAL ;
    SHAPE ABUTMENT ;
    PORT
      LAYER M5 ;
      RECT 413.400 777.408 413.424 777.600 ;
    END
  END rx_flit[510]
  PIN rx_flit[511]
    DIRECTION OUTPUT ;
    USE SIGNAL ;
    SHAPE ABUTMENT ;
    PORT
      LAYER M5 ;
      RECT 413.448 777.408 413.472 777.600 ;
    END
  END rx_flit[511]
  PIN rx_flit[512]
    DIRECTION OUTPUT ;
    USE SIGNAL ;
    SHAPE ABUTMENT ;
    PORT
      LAYER M5 ;
      RECT 413.496 777.408 413.520 777.600 ;
    END
  END rx_flit[512]
  PIN rx_flit[513]
    DIRECTION OUTPUT ;
    USE SIGNAL ;
    SHAPE ABUTMENT ;
    PORT
      LAYER M5 ;
      RECT 413.544 777.408 413.568 777.600 ;
    END
  END rx_flit[513]
  PIN rx_flit[514]
    DIRECTION OUTPUT ;
    USE SIGNAL ;
    SHAPE ABUTMENT ;
    PORT
      LAYER M5 ;
      RECT 413.592 777.408 413.616 777.600 ;
    END
  END rx_flit[514]
  PIN rx_flit[515]
    DIRECTION OUTPUT ;
    USE SIGNAL ;
    SHAPE ABUTMENT ;
    PORT
      LAYER M5 ;
      RECT 413.640 777.408 413.664 777.600 ;
    END
  END rx_flit[515]
  PIN rx_flit[516]
    DIRECTION OUTPUT ;
    USE SIGNAL ;
    SHAPE ABUTMENT ;
    PORT
      LAYER M5 ;
      RECT 413.688 777.408 413.712 777.600 ;
    END
  END rx_flit[516]
  PIN rx_flit[517]
    DIRECTION OUTPUT ;
    USE SIGNAL ;
    SHAPE ABUTMENT ;
    PORT
      LAYER M5 ;
      RECT 413.736 777.408 413.760 777.600 ;
    END
  END rx_flit[517]
  PIN rx_flit[518]
    DIRECTION OUTPUT ;
    USE SIGNAL ;
    SHAPE ABUTMENT ;
    PORT
      LAYER M5 ;
      RECT 413.784 777.408 413.808 777.600 ;
    END
  END rx_flit[518]
  PIN rx_flit[519]
    DIRECTION OUTPUT ;
    USE SIGNAL ;
    SHAPE ABUTMENT ;
    PORT
      LAYER M5 ;
      RECT 413.832 777.408 413.856 777.600 ;
    END
  END rx_flit[519]
  PIN rx_flit[520]
    DIRECTION OUTPUT ;
    USE SIGNAL ;
    SHAPE ABUTMENT ;
    PORT
      LAYER M5 ;
      RECT 413.880 777.408 413.904 777.600 ;
    END
  END rx_flit[520]
  PIN rx_flit[521]
    DIRECTION OUTPUT ;
    USE SIGNAL ;
    SHAPE ABUTMENT ;
    PORT
      LAYER M5 ;
      RECT 413.928 777.408 413.952 777.600 ;
    END
  END rx_flit[521]
  PIN rx_flit[522]
    DIRECTION OUTPUT ;
    USE SIGNAL ;
    SHAPE ABUTMENT ;
    PORT
      LAYER M5 ;
      RECT 413.976 777.408 414.000 777.600 ;
    END
  END rx_flit[522]
  PIN rx_flit[523]
    DIRECTION OUTPUT ;
    USE SIGNAL ;
    SHAPE ABUTMENT ;
    PORT
      LAYER M5 ;
      RECT 414.024 777.408 414.048 777.600 ;
    END
  END rx_flit[523]
  PIN rx_flit[524]
    DIRECTION OUTPUT ;
    USE SIGNAL ;
    SHAPE ABUTMENT ;
    PORT
      LAYER M5 ;
      RECT 414.072 777.408 414.096 777.600 ;
    END
  END rx_flit[524]
  PIN rx_flit[525]
    DIRECTION OUTPUT ;
    USE SIGNAL ;
    SHAPE ABUTMENT ;
    PORT
      LAYER M5 ;
      RECT 414.120 777.408 414.144 777.600 ;
    END
  END rx_flit[525]
  PIN rx_flit[526]
    DIRECTION OUTPUT ;
    USE SIGNAL ;
    SHAPE ABUTMENT ;
    PORT
      LAYER M5 ;
      RECT 414.168 777.408 414.192 777.600 ;
    END
  END rx_flit[526]
  PIN rx_flit[527]
    DIRECTION OUTPUT ;
    USE SIGNAL ;
    SHAPE ABUTMENT ;
    PORT
      LAYER M5 ;
      RECT 414.216 777.408 414.240 777.600 ;
    END
  END rx_flit[527]
  PIN rx_flit[528]
    DIRECTION OUTPUT ;
    USE SIGNAL ;
    SHAPE ABUTMENT ;
    PORT
      LAYER M5 ;
      RECT 414.264 777.408 414.288 777.600 ;
    END
  END rx_flit[528]
  PIN rx_flit[529]
    DIRECTION OUTPUT ;
    USE SIGNAL ;
    SHAPE ABUTMENT ;
    PORT
      LAYER M5 ;
      RECT 414.312 777.408 414.336 777.600 ;
    END
  END rx_flit[529]
  PIN rx_flit[530]
    DIRECTION OUTPUT ;
    USE SIGNAL ;
    SHAPE ABUTMENT ;
    PORT
      LAYER M5 ;
      RECT 414.360 777.408 414.384 777.600 ;
    END
  END rx_flit[530]
  PIN rx_flit[531]
    DIRECTION OUTPUT ;
    USE SIGNAL ;
    SHAPE ABUTMENT ;
    PORT
      LAYER M5 ;
      RECT 414.408 777.408 414.432 777.600 ;
    END
  END rx_flit[531]
  PIN rx_flit[532]
    DIRECTION OUTPUT ;
    USE SIGNAL ;
    SHAPE ABUTMENT ;
    PORT
      LAYER M5 ;
      RECT 414.456 777.408 414.480 777.600 ;
    END
  END rx_flit[532]
  PIN rx_flit[533]
    DIRECTION OUTPUT ;
    USE SIGNAL ;
    SHAPE ABUTMENT ;
    PORT
      LAYER M5 ;
      RECT 414.504 777.408 414.528 777.600 ;
    END
  END rx_flit[533]
  PIN rx_flit[534]
    DIRECTION OUTPUT ;
    USE SIGNAL ;
    SHAPE ABUTMENT ;
    PORT
      LAYER M5 ;
      RECT 414.552 777.408 414.576 777.600 ;
    END
  END rx_flit[534]
  PIN rx_flit[535]
    DIRECTION OUTPUT ;
    USE SIGNAL ;
    SHAPE ABUTMENT ;
    PORT
      LAYER M5 ;
      RECT 414.600 777.408 414.624 777.600 ;
    END
  END rx_flit[535]
  PIN rx_flit[536]
    DIRECTION OUTPUT ;
    USE SIGNAL ;
    SHAPE ABUTMENT ;
    PORT
      LAYER M5 ;
      RECT 414.648 777.408 414.672 777.600 ;
    END
  END rx_flit[536]
  PIN rx_flit[537]
    DIRECTION OUTPUT ;
    USE SIGNAL ;
    SHAPE ABUTMENT ;
    PORT
      LAYER M5 ;
      RECT 414.696 777.408 414.720 777.600 ;
    END
  END rx_flit[537]
  PIN rx_flit[538]
    DIRECTION OUTPUT ;
    USE SIGNAL ;
    SHAPE ABUTMENT ;
    PORT
      LAYER M5 ;
      RECT 414.744 777.408 414.768 777.600 ;
    END
  END rx_flit[538]
  PIN rx_flit[539]
    DIRECTION OUTPUT ;
    USE SIGNAL ;
    SHAPE ABUTMENT ;
    PORT
      LAYER M5 ;
      RECT 414.792 777.408 414.816 777.600 ;
    END
  END rx_flit[539]
  PIN rx_flit[540]
    DIRECTION OUTPUT ;
    USE SIGNAL ;
    SHAPE ABUTMENT ;
    PORT
      LAYER M5 ;
      RECT 414.840 777.408 414.864 777.600 ;
    END
  END rx_flit[540]
  PIN rx_flit[541]
    DIRECTION OUTPUT ;
    USE SIGNAL ;
    SHAPE ABUTMENT ;
    PORT
      LAYER M5 ;
      RECT 414.888 777.408 414.912 777.600 ;
    END
  END rx_flit[541]
  PIN rx_flit[542]
    DIRECTION OUTPUT ;
    USE SIGNAL ;
    SHAPE ABUTMENT ;
    PORT
      LAYER M5 ;
      RECT 414.936 777.408 414.960 777.600 ;
    END
  END rx_flit[542]
  PIN rx_flit[543]
    DIRECTION OUTPUT ;
    USE SIGNAL ;
    SHAPE ABUTMENT ;
    PORT
      LAYER M5 ;
      RECT 414.984 777.408 415.008 777.600 ;
    END
  END rx_flit[543]
  PIN rx_flit[544]
    DIRECTION OUTPUT ;
    USE SIGNAL ;
    SHAPE ABUTMENT ;
    PORT
      LAYER M5 ;
      RECT 415.032 777.408 415.056 777.600 ;
    END
  END rx_flit[544]
  PIN rx_flit[545]
    DIRECTION OUTPUT ;
    USE SIGNAL ;
    SHAPE ABUTMENT ;
    PORT
      LAYER M5 ;
      RECT 415.080 777.408 415.104 777.600 ;
    END
  END rx_flit[545]
  PIN rx_flit[546]
    DIRECTION OUTPUT ;
    USE SIGNAL ;
    SHAPE ABUTMENT ;
    PORT
      LAYER M5 ;
      RECT 415.128 777.408 415.152 777.600 ;
    END
  END rx_flit[546]
  PIN rx_flit[547]
    DIRECTION OUTPUT ;
    USE SIGNAL ;
    SHAPE ABUTMENT ;
    PORT
      LAYER M5 ;
      RECT 415.176 777.408 415.200 777.600 ;
    END
  END rx_flit[547]
  PIN rx_flit[548]
    DIRECTION OUTPUT ;
    USE SIGNAL ;
    SHAPE ABUTMENT ;
    PORT
      LAYER M5 ;
      RECT 415.224 777.408 415.248 777.600 ;
    END
  END rx_flit[548]
  PIN rx_flit[549]
    DIRECTION OUTPUT ;
    USE SIGNAL ;
    SHAPE ABUTMENT ;
    PORT
      LAYER M5 ;
      RECT 415.272 777.408 415.296 777.600 ;
    END
  END rx_flit[549]
  PIN rx_flit[550]
    DIRECTION OUTPUT ;
    USE SIGNAL ;
    SHAPE ABUTMENT ;
    PORT
      LAYER M5 ;
      RECT 415.320 777.408 415.344 777.600 ;
    END
  END rx_flit[550]
  PIN rx_flit[551]
    DIRECTION OUTPUT ;
    USE SIGNAL ;
    SHAPE ABUTMENT ;
    PORT
      LAYER M5 ;
      RECT 415.368 777.408 415.392 777.600 ;
    END
  END rx_flit[551]
  PIN rx_flit[552]
    DIRECTION OUTPUT ;
    USE SIGNAL ;
    SHAPE ABUTMENT ;
    PORT
      LAYER M5 ;
      RECT 415.416 777.408 415.440 777.600 ;
    END
  END rx_flit[552]
  PIN rx_flit[553]
    DIRECTION OUTPUT ;
    USE SIGNAL ;
    SHAPE ABUTMENT ;
    PORT
      LAYER M5 ;
      RECT 415.464 777.408 415.488 777.600 ;
    END
  END rx_flit[553]
  PIN rx_flit[554]
    DIRECTION OUTPUT ;
    USE SIGNAL ;
    SHAPE ABUTMENT ;
    PORT
      LAYER M5 ;
      RECT 415.512 777.408 415.536 777.600 ;
    END
  END rx_flit[554]
  PIN rx_flit[555]
    DIRECTION OUTPUT ;
    USE SIGNAL ;
    SHAPE ABUTMENT ;
    PORT
      LAYER M5 ;
      RECT 415.560 777.408 415.584 777.600 ;
    END
  END rx_flit[555]
  PIN rx_flit[556]
    DIRECTION OUTPUT ;
    USE SIGNAL ;
    SHAPE ABUTMENT ;
    PORT
      LAYER M5 ;
      RECT 415.608 777.408 415.632 777.600 ;
    END
  END rx_flit[556]
  PIN rx_flit[557]
    DIRECTION OUTPUT ;
    USE SIGNAL ;
    SHAPE ABUTMENT ;
    PORT
      LAYER M5 ;
      RECT 415.656 777.408 415.680 777.600 ;
    END
  END rx_flit[557]
  PIN rx_flit[558]
    DIRECTION OUTPUT ;
    USE SIGNAL ;
    SHAPE ABUTMENT ;
    PORT
      LAYER M5 ;
      RECT 415.704 777.408 415.728 777.600 ;
    END
  END rx_flit[558]
  PIN rx_flit[559]
    DIRECTION OUTPUT ;
    USE SIGNAL ;
    SHAPE ABUTMENT ;
    PORT
      LAYER M5 ;
      RECT 415.752 777.408 415.776 777.600 ;
    END
  END rx_flit[559]
  PIN rx_flit[560]
    DIRECTION OUTPUT ;
    USE SIGNAL ;
    SHAPE ABUTMENT ;
    PORT
      LAYER M5 ;
      RECT 415.800 777.408 415.824 777.600 ;
    END
  END rx_flit[560]
  PIN rx_flit[561]
    DIRECTION OUTPUT ;
    USE SIGNAL ;
    SHAPE ABUTMENT ;
    PORT
      LAYER M5 ;
      RECT 415.848 777.408 415.872 777.600 ;
    END
  END rx_flit[561]
  PIN rx_flit[562]
    DIRECTION OUTPUT ;
    USE SIGNAL ;
    SHAPE ABUTMENT ;
    PORT
      LAYER M5 ;
      RECT 415.896 777.408 415.920 777.600 ;
    END
  END rx_flit[562]
  PIN rx_flit[563]
    DIRECTION OUTPUT ;
    USE SIGNAL ;
    SHAPE ABUTMENT ;
    PORT
      LAYER M5 ;
      RECT 415.944 777.408 415.968 777.600 ;
    END
  END rx_flit[563]
  PIN rx_flit[564]
    DIRECTION OUTPUT ;
    USE SIGNAL ;
    SHAPE ABUTMENT ;
    PORT
      LAYER M5 ;
      RECT 415.992 777.408 416.016 777.600 ;
    END
  END rx_flit[564]
  PIN rx_flit[565]
    DIRECTION OUTPUT ;
    USE SIGNAL ;
    SHAPE ABUTMENT ;
    PORT
      LAYER M5 ;
      RECT 416.040 777.408 416.064 777.600 ;
    END
  END rx_flit[565]
  PIN rx_flit[566]
    DIRECTION OUTPUT ;
    USE SIGNAL ;
    SHAPE ABUTMENT ;
    PORT
      LAYER M5 ;
      RECT 416.088 777.408 416.112 777.600 ;
    END
  END rx_flit[566]
  PIN rx_flit[567]
    DIRECTION OUTPUT ;
    USE SIGNAL ;
    SHAPE ABUTMENT ;
    PORT
      LAYER M5 ;
      RECT 416.136 777.408 416.160 777.600 ;
    END
  END rx_flit[567]
  PIN rx_flit[568]
    DIRECTION OUTPUT ;
    USE SIGNAL ;
    SHAPE ABUTMENT ;
    PORT
      LAYER M5 ;
      RECT 416.184 777.408 416.208 777.600 ;
    END
  END rx_flit[568]
  PIN rx_flit[569]
    DIRECTION OUTPUT ;
    USE SIGNAL ;
    SHAPE ABUTMENT ;
    PORT
      LAYER M5 ;
      RECT 416.232 777.408 416.256 777.600 ;
    END
  END rx_flit[569]
  PIN rx_flit[570]
    DIRECTION OUTPUT ;
    USE SIGNAL ;
    SHAPE ABUTMENT ;
    PORT
      LAYER M5 ;
      RECT 416.280 777.408 416.304 777.600 ;
    END
  END rx_flit[570]
  PIN rx_flit[571]
    DIRECTION OUTPUT ;
    USE SIGNAL ;
    SHAPE ABUTMENT ;
    PORT
      LAYER M5 ;
      RECT 416.328 777.408 416.352 777.600 ;
    END
  END rx_flit[571]
  PIN rx_flit[572]
    DIRECTION OUTPUT ;
    USE SIGNAL ;
    SHAPE ABUTMENT ;
    PORT
      LAYER M5 ;
      RECT 416.376 777.408 416.400 777.600 ;
    END
  END rx_flit[572]
  PIN rx_flit[573]
    DIRECTION OUTPUT ;
    USE SIGNAL ;
    SHAPE ABUTMENT ;
    PORT
      LAYER M5 ;
      RECT 416.424 777.408 416.448 777.600 ;
    END
  END rx_flit[573]
  PIN rx_flit[574]
    DIRECTION OUTPUT ;
    USE SIGNAL ;
    SHAPE ABUTMENT ;
    PORT
      LAYER M5 ;
      RECT 416.472 777.408 416.496 777.600 ;
    END
  END rx_flit[574]
  PIN rx_flit[575]
    DIRECTION OUTPUT ;
    USE SIGNAL ;
    SHAPE ABUTMENT ;
    PORT
      LAYER M5 ;
      RECT 416.520 777.408 416.544 777.600 ;
    END
  END rx_flit[575]
  PIN rx_flit[576]
    DIRECTION OUTPUT ;
    USE SIGNAL ;
    SHAPE ABUTMENT ;
    PORT
      LAYER M5 ;
      RECT 416.568 777.408 416.592 777.600 ;
    END
  END rx_flit[576]
  PIN rx_flit[577]
    DIRECTION OUTPUT ;
    USE SIGNAL ;
    SHAPE ABUTMENT ;
    PORT
      LAYER M5 ;
      RECT 416.616 777.408 416.640 777.600 ;
    END
  END rx_flit[577]
  PIN rx_flit[578]
    DIRECTION OUTPUT ;
    USE SIGNAL ;
    SHAPE ABUTMENT ;
    PORT
      LAYER M5 ;
      RECT 416.664 777.408 416.688 777.600 ;
    END
  END rx_flit[578]
  PIN rx_flit[579]
    DIRECTION OUTPUT ;
    USE SIGNAL ;
    SHAPE ABUTMENT ;
    PORT
      LAYER M5 ;
      RECT 416.712 777.408 416.736 777.600 ;
    END
  END rx_flit[579]
  PIN rx_flit[580]
    DIRECTION OUTPUT ;
    USE SIGNAL ;
    SHAPE ABUTMENT ;
    PORT
      LAYER M5 ;
      RECT 416.760 777.408 416.784 777.600 ;
    END
  END rx_flit[580]
  PIN rx_flit[581]
    DIRECTION OUTPUT ;
    USE SIGNAL ;
    SHAPE ABUTMENT ;
    PORT
      LAYER M5 ;
      RECT 416.808 777.408 416.832 777.600 ;
    END
  END rx_flit[581]
  PIN rx_flit[582]
    DIRECTION OUTPUT ;
    USE SIGNAL ;
    SHAPE ABUTMENT ;
    PORT
      LAYER M5 ;
      RECT 416.856 777.408 416.880 777.600 ;
    END
  END rx_flit[582]
  PIN rx_flit[583]
    DIRECTION OUTPUT ;
    USE SIGNAL ;
    SHAPE ABUTMENT ;
    PORT
      LAYER M5 ;
      RECT 416.904 777.408 416.928 777.600 ;
    END
  END rx_flit[583]
  PIN rx_flit[584]
    DIRECTION OUTPUT ;
    USE SIGNAL ;
    SHAPE ABUTMENT ;
    PORT
      LAYER M5 ;
      RECT 416.952 777.408 416.976 777.600 ;
    END
  END rx_flit[584]
  PIN rx_flit[585]
    DIRECTION OUTPUT ;
    USE SIGNAL ;
    SHAPE ABUTMENT ;
    PORT
      LAYER M5 ;
      RECT 417.000 777.408 417.024 777.600 ;
    END
  END rx_flit[585]
  PIN rx_flit[586]
    DIRECTION OUTPUT ;
    USE SIGNAL ;
    SHAPE ABUTMENT ;
    PORT
      LAYER M5 ;
      RECT 417.048 777.408 417.072 777.600 ;
    END
  END rx_flit[586]
  PIN rx_flit[587]
    DIRECTION OUTPUT ;
    USE SIGNAL ;
    SHAPE ABUTMENT ;
    PORT
      LAYER M5 ;
      RECT 417.096 777.408 417.120 777.600 ;
    END
  END rx_flit[587]
  PIN rx_flit[588]
    DIRECTION OUTPUT ;
    USE SIGNAL ;
    SHAPE ABUTMENT ;
    PORT
      LAYER M5 ;
      RECT 417.144 777.408 417.168 777.600 ;
    END
  END rx_flit[588]
  PIN rx_flit[589]
    DIRECTION OUTPUT ;
    USE SIGNAL ;
    SHAPE ABUTMENT ;
    PORT
      LAYER M5 ;
      RECT 417.192 777.408 417.216 777.600 ;
    END
  END rx_flit[589]
  PIN rx_flit[590]
    DIRECTION OUTPUT ;
    USE SIGNAL ;
    SHAPE ABUTMENT ;
    PORT
      LAYER M5 ;
      RECT 417.240 777.408 417.264 777.600 ;
    END
  END rx_flit[590]
  PIN rx_flit[591]
    DIRECTION OUTPUT ;
    USE SIGNAL ;
    SHAPE ABUTMENT ;
    PORT
      LAYER M5 ;
      RECT 417.288 777.408 417.312 777.600 ;
    END
  END rx_flit[591]
  PIN rx_flit[592]
    DIRECTION OUTPUT ;
    USE SIGNAL ;
    SHAPE ABUTMENT ;
    PORT
      LAYER M5 ;
      RECT 417.336 777.408 417.360 777.600 ;
    END
  END rx_flit[592]
  PIN rx_flit[593]
    DIRECTION OUTPUT ;
    USE SIGNAL ;
    SHAPE ABUTMENT ;
    PORT
      LAYER M5 ;
      RECT 417.384 777.408 417.408 777.600 ;
    END
  END rx_flit[593]
  PIN rx_flit[594]
    DIRECTION OUTPUT ;
    USE SIGNAL ;
    SHAPE ABUTMENT ;
    PORT
      LAYER M5 ;
      RECT 417.432 777.408 417.456 777.600 ;
    END
  END rx_flit[594]
  PIN rx_flit[595]
    DIRECTION OUTPUT ;
    USE SIGNAL ;
    SHAPE ABUTMENT ;
    PORT
      LAYER M5 ;
      RECT 417.480 777.408 417.504 777.600 ;
    END
  END rx_flit[595]
  PIN rx_flit[596]
    DIRECTION OUTPUT ;
    USE SIGNAL ;
    SHAPE ABUTMENT ;
    PORT
      LAYER M5 ;
      RECT 417.528 777.408 417.552 777.600 ;
    END
  END rx_flit[596]
  PIN rx_flit[597]
    DIRECTION OUTPUT ;
    USE SIGNAL ;
    SHAPE ABUTMENT ;
    PORT
      LAYER M5 ;
      RECT 417.576 777.408 417.600 777.600 ;
    END
  END rx_flit[597]
  PIN rx_flit[598]
    DIRECTION OUTPUT ;
    USE SIGNAL ;
    SHAPE ABUTMENT ;
    PORT
      LAYER M5 ;
      RECT 417.624 777.408 417.648 777.600 ;
    END
  END rx_flit[598]
  PIN rx_flit[599]
    DIRECTION OUTPUT ;
    USE SIGNAL ;
    SHAPE ABUTMENT ;
    PORT
      LAYER M5 ;
      RECT 417.672 777.408 417.696 777.600 ;
    END
  END rx_flit[599]
  PIN rx_flit[600]
    DIRECTION OUTPUT ;
    USE SIGNAL ;
    SHAPE ABUTMENT ;
    PORT
      LAYER M5 ;
      RECT 417.720 777.408 417.744 777.600 ;
    END
  END rx_flit[600]
  PIN rx_flit[601]
    DIRECTION OUTPUT ;
    USE SIGNAL ;
    SHAPE ABUTMENT ;
    PORT
      LAYER M5 ;
      RECT 417.768 777.408 417.792 777.600 ;
    END
  END rx_flit[601]
  PIN rx_flit[602]
    DIRECTION OUTPUT ;
    USE SIGNAL ;
    SHAPE ABUTMENT ;
    PORT
      LAYER M5 ;
      RECT 417.816 777.408 417.840 777.600 ;
    END
  END rx_flit[602]
  PIN rx_flit[603]
    DIRECTION OUTPUT ;
    USE SIGNAL ;
    SHAPE ABUTMENT ;
    PORT
      LAYER M5 ;
      RECT 417.864 777.408 417.888 777.600 ;
    END
  END rx_flit[603]
  PIN rx_flit[604]
    DIRECTION OUTPUT ;
    USE SIGNAL ;
    SHAPE ABUTMENT ;
    PORT
      LAYER M5 ;
      RECT 417.912 777.408 417.936 777.600 ;
    END
  END rx_flit[604]
  PIN rx_flit[605]
    DIRECTION OUTPUT ;
    USE SIGNAL ;
    SHAPE ABUTMENT ;
    PORT
      LAYER M5 ;
      RECT 417.960 777.408 417.984 777.600 ;
    END
  END rx_flit[605]
  PIN rx_flit[606]
    DIRECTION OUTPUT ;
    USE SIGNAL ;
    SHAPE ABUTMENT ;
    PORT
      LAYER M5 ;
      RECT 418.008 777.408 418.032 777.600 ;
    END
  END rx_flit[606]
  PIN rx_flit[607]
    DIRECTION OUTPUT ;
    USE SIGNAL ;
    SHAPE ABUTMENT ;
    PORT
      LAYER M5 ;
      RECT 418.056 777.408 418.080 777.600 ;
    END
  END rx_flit[607]
  PIN rx_flit[608]
    DIRECTION OUTPUT ;
    USE SIGNAL ;
    SHAPE ABUTMENT ;
    PORT
      LAYER M5 ;
      RECT 418.104 777.408 418.128 777.600 ;
    END
  END rx_flit[608]
  PIN rx_flit[609]
    DIRECTION OUTPUT ;
    USE SIGNAL ;
    SHAPE ABUTMENT ;
    PORT
      LAYER M5 ;
      RECT 418.152 777.408 418.176 777.600 ;
    END
  END rx_flit[609]
  PIN rx_flit[610]
    DIRECTION OUTPUT ;
    USE SIGNAL ;
    SHAPE ABUTMENT ;
    PORT
      LAYER M5 ;
      RECT 418.200 777.408 418.224 777.600 ;
    END
  END rx_flit[610]
  PIN rx_flit[611]
    DIRECTION OUTPUT ;
    USE SIGNAL ;
    SHAPE ABUTMENT ;
    PORT
      LAYER M5 ;
      RECT 418.248 777.408 418.272 777.600 ;
    END
  END rx_flit[611]
  PIN rx_flit[612]
    DIRECTION OUTPUT ;
    USE SIGNAL ;
    SHAPE ABUTMENT ;
    PORT
      LAYER M5 ;
      RECT 418.296 777.408 418.320 777.600 ;
    END
  END rx_flit[612]
  PIN rx_flit[613]
    DIRECTION OUTPUT ;
    USE SIGNAL ;
    SHAPE ABUTMENT ;
    PORT
      LAYER M5 ;
      RECT 418.344 777.408 418.368 777.600 ;
    END
  END rx_flit[613]
  PIN rx_flit[614]
    DIRECTION OUTPUT ;
    USE SIGNAL ;
    SHAPE ABUTMENT ;
    PORT
      LAYER M5 ;
      RECT 418.392 777.408 418.416 777.600 ;
    END
  END rx_flit[614]
  PIN rx_flit[615]
    DIRECTION OUTPUT ;
    USE SIGNAL ;
    SHAPE ABUTMENT ;
    PORT
      LAYER M5 ;
      RECT 418.440 777.408 418.464 777.600 ;
    END
  END rx_flit[615]
  PIN rx_flit[616]
    DIRECTION OUTPUT ;
    USE SIGNAL ;
    SHAPE ABUTMENT ;
    PORT
      LAYER M5 ;
      RECT 418.488 777.408 418.512 777.600 ;
    END
  END rx_flit[616]
  PIN rx_flit[617]
    DIRECTION OUTPUT ;
    USE SIGNAL ;
    SHAPE ABUTMENT ;
    PORT
      LAYER M5 ;
      RECT 418.536 777.408 418.560 777.600 ;
    END
  END rx_flit[617]
  PIN rx_flit[618]
    DIRECTION OUTPUT ;
    USE SIGNAL ;
    SHAPE ABUTMENT ;
    PORT
      LAYER M5 ;
      RECT 418.584 777.408 418.608 777.600 ;
    END
  END rx_flit[618]
  PIN rx_flit[619]
    DIRECTION OUTPUT ;
    USE SIGNAL ;
    SHAPE ABUTMENT ;
    PORT
      LAYER M5 ;
      RECT 418.632 777.408 418.656 777.600 ;
    END
  END rx_flit[619]
  PIN rx_flit[620]
    DIRECTION OUTPUT ;
    USE SIGNAL ;
    SHAPE ABUTMENT ;
    PORT
      LAYER M5 ;
      RECT 418.680 777.408 418.704 777.600 ;
    END
  END rx_flit[620]
  PIN rx_flit[621]
    DIRECTION OUTPUT ;
    USE SIGNAL ;
    SHAPE ABUTMENT ;
    PORT
      LAYER M5 ;
      RECT 418.728 777.408 418.752 777.600 ;
    END
  END rx_flit[621]
  PIN rx_flit[622]
    DIRECTION OUTPUT ;
    USE SIGNAL ;
    SHAPE ABUTMENT ;
    PORT
      LAYER M5 ;
      RECT 418.776 777.408 418.800 777.600 ;
    END
  END rx_flit[622]
  PIN rx_flit[623]
    DIRECTION OUTPUT ;
    USE SIGNAL ;
    SHAPE ABUTMENT ;
    PORT
      LAYER M5 ;
      RECT 418.824 777.408 418.848 777.600 ;
    END
  END rx_flit[623]
  PIN rx_flit[624]
    DIRECTION OUTPUT ;
    USE SIGNAL ;
    SHAPE ABUTMENT ;
    PORT
      LAYER M5 ;
      RECT 418.872 777.408 418.896 777.600 ;
    END
  END rx_flit[624]
  PIN rx_flit[625]
    DIRECTION OUTPUT ;
    USE SIGNAL ;
    SHAPE ABUTMENT ;
    PORT
      LAYER M5 ;
      RECT 418.920 777.408 418.944 777.600 ;
    END
  END rx_flit[625]
  PIN rx_flit[626]
    DIRECTION OUTPUT ;
    USE SIGNAL ;
    SHAPE ABUTMENT ;
    PORT
      LAYER M5 ;
      RECT 418.968 777.408 418.992 777.600 ;
    END
  END rx_flit[626]
  PIN rx_flit[627]
    DIRECTION OUTPUT ;
    USE SIGNAL ;
    SHAPE ABUTMENT ;
    PORT
      LAYER M5 ;
      RECT 419.016 777.408 419.040 777.600 ;
    END
  END rx_flit[627]
  PIN rx_flit[628]
    DIRECTION OUTPUT ;
    USE SIGNAL ;
    SHAPE ABUTMENT ;
    PORT
      LAYER M5 ;
      RECT 419.064 777.408 419.088 777.600 ;
    END
  END rx_flit[628]
  PIN rx_flit[629]
    DIRECTION OUTPUT ;
    USE SIGNAL ;
    SHAPE ABUTMENT ;
    PORT
      LAYER M5 ;
      RECT 419.112 777.408 419.136 777.600 ;
    END
  END rx_flit[629]
  PIN rx_flit[630]
    DIRECTION OUTPUT ;
    USE SIGNAL ;
    SHAPE ABUTMENT ;
    PORT
      LAYER M5 ;
      RECT 419.160 777.408 419.184 777.600 ;
    END
  END rx_flit[630]
  PIN rx_flit[631]
    DIRECTION OUTPUT ;
    USE SIGNAL ;
    SHAPE ABUTMENT ;
    PORT
      LAYER M5 ;
      RECT 419.208 777.408 419.232 777.600 ;
    END
  END rx_flit[631]
  PIN rx_flit[632]
    DIRECTION OUTPUT ;
    USE SIGNAL ;
    SHAPE ABUTMENT ;
    PORT
      LAYER M5 ;
      RECT 419.256 777.408 419.280 777.600 ;
    END
  END rx_flit[632]
  PIN rx_flit[633]
    DIRECTION OUTPUT ;
    USE SIGNAL ;
    SHAPE ABUTMENT ;
    PORT
      LAYER M5 ;
      RECT 419.304 777.408 419.328 777.600 ;
    END
  END rx_flit[633]
  PIN rx_flit[634]
    DIRECTION OUTPUT ;
    USE SIGNAL ;
    SHAPE ABUTMENT ;
    PORT
      LAYER M5 ;
      RECT 419.352 777.408 419.376 777.600 ;
    END
  END rx_flit[634]
  PIN rx_flit[635]
    DIRECTION OUTPUT ;
    USE SIGNAL ;
    SHAPE ABUTMENT ;
    PORT
      LAYER M5 ;
      RECT 419.400 777.408 419.424 777.600 ;
    END
  END rx_flit[635]
  PIN rx_flit[636]
    DIRECTION OUTPUT ;
    USE SIGNAL ;
    SHAPE ABUTMENT ;
    PORT
      LAYER M5 ;
      RECT 419.448 777.408 419.472 777.600 ;
    END
  END rx_flit[636]
  PIN rx_flit[637]
    DIRECTION OUTPUT ;
    USE SIGNAL ;
    SHAPE ABUTMENT ;
    PORT
      LAYER M5 ;
      RECT 419.496 777.408 419.520 777.600 ;
    END
  END rx_flit[637]
  PIN rx_flit[638]
    DIRECTION OUTPUT ;
    USE SIGNAL ;
    SHAPE ABUTMENT ;
    PORT
      LAYER M5 ;
      RECT 419.544 777.408 419.568 777.600 ;
    END
  END rx_flit[638]
  PIN rx_flit[639]
    DIRECTION OUTPUT ;
    USE SIGNAL ;
    SHAPE ABUTMENT ;
    PORT
      LAYER M5 ;
      RECT 419.592 777.408 419.616 777.600 ;
    END
  END rx_flit[639]
  PIN rx_flit[640]
    DIRECTION OUTPUT ;
    USE SIGNAL ;
    SHAPE ABUTMENT ;
    PORT
      LAYER M5 ;
      RECT 419.640 777.408 419.664 777.600 ;
    END
  END rx_flit[640]
  PIN rx_flit[641]
    DIRECTION OUTPUT ;
    USE SIGNAL ;
    SHAPE ABUTMENT ;
    PORT
      LAYER M5 ;
      RECT 419.688 777.408 419.712 777.600 ;
    END
  END rx_flit[641]
  PIN rx_flit[642]
    DIRECTION OUTPUT ;
    USE SIGNAL ;
    SHAPE ABUTMENT ;
    PORT
      LAYER M5 ;
      RECT 419.736 777.408 419.760 777.600 ;
    END
  END rx_flit[642]
  PIN rx_flit[643]
    DIRECTION OUTPUT ;
    USE SIGNAL ;
    SHAPE ABUTMENT ;
    PORT
      LAYER M5 ;
      RECT 419.784 777.408 419.808 777.600 ;
    END
  END rx_flit[643]
  PIN rx_flit[644]
    DIRECTION OUTPUT ;
    USE SIGNAL ;
    SHAPE ABUTMENT ;
    PORT
      LAYER M5 ;
      RECT 419.832 777.408 419.856 777.600 ;
    END
  END rx_flit[644]
  PIN rx_flit[645]
    DIRECTION OUTPUT ;
    USE SIGNAL ;
    SHAPE ABUTMENT ;
    PORT
      LAYER M5 ;
      RECT 419.880 777.408 419.904 777.600 ;
    END
  END rx_flit[645]
  PIN rx_flit[646]
    DIRECTION OUTPUT ;
    USE SIGNAL ;
    SHAPE ABUTMENT ;
    PORT
      LAYER M5 ;
      RECT 419.928 777.408 419.952 777.600 ;
    END
  END rx_flit[646]
  PIN rx_flit[647]
    DIRECTION OUTPUT ;
    USE SIGNAL ;
    SHAPE ABUTMENT ;
    PORT
      LAYER M5 ;
      RECT 419.976 777.408 420.000 777.600 ;
    END
  END rx_flit[647]
  PIN rx_flit[648]
    DIRECTION OUTPUT ;
    USE SIGNAL ;
    SHAPE ABUTMENT ;
    PORT
      LAYER M5 ;
      RECT 420.024 777.408 420.048 777.600 ;
    END
  END rx_flit[648]
  PIN rx_flit[649]
    DIRECTION OUTPUT ;
    USE SIGNAL ;
    SHAPE ABUTMENT ;
    PORT
      LAYER M5 ;
      RECT 420.072 777.408 420.096 777.600 ;
    END
  END rx_flit[649]
  PIN rx_flit[650]
    DIRECTION OUTPUT ;
    USE SIGNAL ;
    SHAPE ABUTMENT ;
    PORT
      LAYER M5 ;
      RECT 420.120 777.408 420.144 777.600 ;
    END
  END rx_flit[650]
  PIN rx_flit[651]
    DIRECTION OUTPUT ;
    USE SIGNAL ;
    SHAPE ABUTMENT ;
    PORT
      LAYER M5 ;
      RECT 420.168 777.408 420.192 777.600 ;
    END
  END rx_flit[651]
  PIN rx_flit[652]
    DIRECTION OUTPUT ;
    USE SIGNAL ;
    SHAPE ABUTMENT ;
    PORT
      LAYER M5 ;
      RECT 420.216 777.408 420.240 777.600 ;
    END
  END rx_flit[652]
  PIN rx_flit[653]
    DIRECTION OUTPUT ;
    USE SIGNAL ;
    SHAPE ABUTMENT ;
    PORT
      LAYER M5 ;
      RECT 420.264 777.408 420.288 777.600 ;
    END
  END rx_flit[653]
  PIN rx_flit[654]
    DIRECTION OUTPUT ;
    USE SIGNAL ;
    SHAPE ABUTMENT ;
    PORT
      LAYER M5 ;
      RECT 420.312 777.408 420.336 777.600 ;
    END
  END rx_flit[654]
  PIN rx_flit[655]
    DIRECTION OUTPUT ;
    USE SIGNAL ;
    SHAPE ABUTMENT ;
    PORT
      LAYER M5 ;
      RECT 420.360 777.408 420.384 777.600 ;
    END
  END rx_flit[655]
  PIN rx_flit[656]
    DIRECTION OUTPUT ;
    USE SIGNAL ;
    SHAPE ABUTMENT ;
    PORT
      LAYER M5 ;
      RECT 420.408 777.408 420.432 777.600 ;
    END
  END rx_flit[656]
  PIN rx_flit[657]
    DIRECTION OUTPUT ;
    USE SIGNAL ;
    SHAPE ABUTMENT ;
    PORT
      LAYER M5 ;
      RECT 420.456 777.408 420.480 777.600 ;
    END
  END rx_flit[657]
  PIN rx_flit[658]
    DIRECTION OUTPUT ;
    USE SIGNAL ;
    SHAPE ABUTMENT ;
    PORT
      LAYER M5 ;
      RECT 420.504 777.408 420.528 777.600 ;
    END
  END rx_flit[658]
  PIN rx_flit[659]
    DIRECTION OUTPUT ;
    USE SIGNAL ;
    SHAPE ABUTMENT ;
    PORT
      LAYER M5 ;
      RECT 420.552 777.408 420.576 777.600 ;
    END
  END rx_flit[659]
  PIN rx_flit[660]
    DIRECTION OUTPUT ;
    USE SIGNAL ;
    SHAPE ABUTMENT ;
    PORT
      LAYER M5 ;
      RECT 420.600 777.408 420.624 777.600 ;
    END
  END rx_flit[660]
  PIN rx_flit[661]
    DIRECTION OUTPUT ;
    USE SIGNAL ;
    SHAPE ABUTMENT ;
    PORT
      LAYER M5 ;
      RECT 420.648 777.408 420.672 777.600 ;
    END
  END rx_flit[661]
  PIN rx_flit[662]
    DIRECTION OUTPUT ;
    USE SIGNAL ;
    SHAPE ABUTMENT ;
    PORT
      LAYER M5 ;
      RECT 420.696 777.408 420.720 777.600 ;
    END
  END rx_flit[662]
  PIN rx_flit[663]
    DIRECTION OUTPUT ;
    USE SIGNAL ;
    SHAPE ABUTMENT ;
    PORT
      LAYER M5 ;
      RECT 420.744 777.408 420.768 777.600 ;
    END
  END rx_flit[663]
  PIN rx_flit[664]
    DIRECTION OUTPUT ;
    USE SIGNAL ;
    SHAPE ABUTMENT ;
    PORT
      LAYER M5 ;
      RECT 420.792 777.408 420.816 777.600 ;
    END
  END rx_flit[664]
  PIN rx_flit[665]
    DIRECTION OUTPUT ;
    USE SIGNAL ;
    SHAPE ABUTMENT ;
    PORT
      LAYER M5 ;
      RECT 420.840 777.408 420.864 777.600 ;
    END
  END rx_flit[665]
  PIN rx_flit[666]
    DIRECTION OUTPUT ;
    USE SIGNAL ;
    SHAPE ABUTMENT ;
    PORT
      LAYER M5 ;
      RECT 420.888 777.408 420.912 777.600 ;
    END
  END rx_flit[666]
  PIN rx_flit[667]
    DIRECTION OUTPUT ;
    USE SIGNAL ;
    SHAPE ABUTMENT ;
    PORT
      LAYER M5 ;
      RECT 420.936 777.408 420.960 777.600 ;
    END
  END rx_flit[667]
  PIN rx_flit[668]
    DIRECTION OUTPUT ;
    USE SIGNAL ;
    SHAPE ABUTMENT ;
    PORT
      LAYER M5 ;
      RECT 420.984 777.408 421.008 777.600 ;
    END
  END rx_flit[668]
  PIN rx_flit[669]
    DIRECTION OUTPUT ;
    USE SIGNAL ;
    SHAPE ABUTMENT ;
    PORT
      LAYER M5 ;
      RECT 421.032 777.408 421.056 777.600 ;
    END
  END rx_flit[669]
  PIN rx_flit[670]
    DIRECTION OUTPUT ;
    USE SIGNAL ;
    SHAPE ABUTMENT ;
    PORT
      LAYER M5 ;
      RECT 421.080 777.408 421.104 777.600 ;
    END
  END rx_flit[670]
  PIN rx_flit[671]
    DIRECTION OUTPUT ;
    USE SIGNAL ;
    SHAPE ABUTMENT ;
    PORT
      LAYER M5 ;
      RECT 421.128 777.408 421.152 777.600 ;
    END
  END rx_flit[671]
  PIN rx_flit[672]
    DIRECTION OUTPUT ;
    USE SIGNAL ;
    SHAPE ABUTMENT ;
    PORT
      LAYER M5 ;
      RECT 421.176 777.408 421.200 777.600 ;
    END
  END rx_flit[672]
  PIN rx_flit[673]
    DIRECTION OUTPUT ;
    USE SIGNAL ;
    SHAPE ABUTMENT ;
    PORT
      LAYER M5 ;
      RECT 421.224 777.408 421.248 777.600 ;
    END
  END rx_flit[673]
  PIN rx_flit[674]
    DIRECTION OUTPUT ;
    USE SIGNAL ;
    SHAPE ABUTMENT ;
    PORT
      LAYER M5 ;
      RECT 421.272 777.408 421.296 777.600 ;
    END
  END rx_flit[674]
  PIN rx_flit[675]
    DIRECTION OUTPUT ;
    USE SIGNAL ;
    SHAPE ABUTMENT ;
    PORT
      LAYER M5 ;
      RECT 421.320 777.408 421.344 777.600 ;
    END
  END rx_flit[675]
  PIN rx_flit[676]
    DIRECTION OUTPUT ;
    USE SIGNAL ;
    SHAPE ABUTMENT ;
    PORT
      LAYER M5 ;
      RECT 421.368 777.408 421.392 777.600 ;
    END
  END rx_flit[676]
  PIN rx_flit[677]
    DIRECTION OUTPUT ;
    USE SIGNAL ;
    SHAPE ABUTMENT ;
    PORT
      LAYER M5 ;
      RECT 421.416 777.408 421.440 777.600 ;
    END
  END rx_flit[677]
  PIN rx_flit[678]
    DIRECTION OUTPUT ;
    USE SIGNAL ;
    SHAPE ABUTMENT ;
    PORT
      LAYER M5 ;
      RECT 421.464 777.408 421.488 777.600 ;
    END
  END rx_flit[678]
  PIN rx_flit[679]
    DIRECTION OUTPUT ;
    USE SIGNAL ;
    SHAPE ABUTMENT ;
    PORT
      LAYER M5 ;
      RECT 421.512 777.408 421.536 777.600 ;
    END
  END rx_flit[679]
  PIN rx_flit[680]
    DIRECTION OUTPUT ;
    USE SIGNAL ;
    SHAPE ABUTMENT ;
    PORT
      LAYER M5 ;
      RECT 421.560 777.408 421.584 777.600 ;
    END
  END rx_flit[680]
  PIN rx_flit[681]
    DIRECTION OUTPUT ;
    USE SIGNAL ;
    SHAPE ABUTMENT ;
    PORT
      LAYER M5 ;
      RECT 421.608 777.408 421.632 777.600 ;
    END
  END rx_flit[681]
  PIN rx_flit[682]
    DIRECTION OUTPUT ;
    USE SIGNAL ;
    SHAPE ABUTMENT ;
    PORT
      LAYER M5 ;
      RECT 421.656 777.408 421.680 777.600 ;
    END
  END rx_flit[682]
  PIN rx_flit[683]
    DIRECTION OUTPUT ;
    USE SIGNAL ;
    SHAPE ABUTMENT ;
    PORT
      LAYER M5 ;
      RECT 421.704 777.408 421.728 777.600 ;
    END
  END rx_flit[683]
  PIN rx_flit[684]
    DIRECTION OUTPUT ;
    USE SIGNAL ;
    SHAPE ABUTMENT ;
    PORT
      LAYER M5 ;
      RECT 421.752 777.408 421.776 777.600 ;
    END
  END rx_flit[684]
  PIN rx_flit[685]
    DIRECTION OUTPUT ;
    USE SIGNAL ;
    SHAPE ABUTMENT ;
    PORT
      LAYER M5 ;
      RECT 421.800 777.408 421.824 777.600 ;
    END
  END rx_flit[685]
  PIN rx_flit[686]
    DIRECTION OUTPUT ;
    USE SIGNAL ;
    SHAPE ABUTMENT ;
    PORT
      LAYER M5 ;
      RECT 421.848 777.408 421.872 777.600 ;
    END
  END rx_flit[686]
  PIN rx_flit[687]
    DIRECTION OUTPUT ;
    USE SIGNAL ;
    SHAPE ABUTMENT ;
    PORT
      LAYER M5 ;
      RECT 421.896 777.408 421.920 777.600 ;
    END
  END rx_flit[687]
  PIN rx_flit[688]
    DIRECTION OUTPUT ;
    USE SIGNAL ;
    SHAPE ABUTMENT ;
    PORT
      LAYER M5 ;
      RECT 421.944 777.408 421.968 777.600 ;
    END
  END rx_flit[688]
  PIN rx_flit[689]
    DIRECTION OUTPUT ;
    USE SIGNAL ;
    SHAPE ABUTMENT ;
    PORT
      LAYER M5 ;
      RECT 421.992 777.408 422.016 777.600 ;
    END
  END rx_flit[689]
  PIN rx_flit[690]
    DIRECTION OUTPUT ;
    USE SIGNAL ;
    SHAPE ABUTMENT ;
    PORT
      LAYER M5 ;
      RECT 422.040 777.408 422.064 777.600 ;
    END
  END rx_flit[690]
  PIN rx_flit[691]
    DIRECTION OUTPUT ;
    USE SIGNAL ;
    SHAPE ABUTMENT ;
    PORT
      LAYER M5 ;
      RECT 422.088 777.408 422.112 777.600 ;
    END
  END rx_flit[691]
  PIN rx_flit[692]
    DIRECTION OUTPUT ;
    USE SIGNAL ;
    SHAPE ABUTMENT ;
    PORT
      LAYER M5 ;
      RECT 422.136 777.408 422.160 777.600 ;
    END
  END rx_flit[692]
  PIN rx_flit[693]
    DIRECTION OUTPUT ;
    USE SIGNAL ;
    SHAPE ABUTMENT ;
    PORT
      LAYER M5 ;
      RECT 422.184 777.408 422.208 777.600 ;
    END
  END rx_flit[693]
  PIN rx_flit[694]
    DIRECTION OUTPUT ;
    USE SIGNAL ;
    SHAPE ABUTMENT ;
    PORT
      LAYER M5 ;
      RECT 422.232 777.408 422.256 777.600 ;
    END
  END rx_flit[694]
  PIN rx_flit[695]
    DIRECTION OUTPUT ;
    USE SIGNAL ;
    SHAPE ABUTMENT ;
    PORT
      LAYER M5 ;
      RECT 422.280 777.408 422.304 777.600 ;
    END
  END rx_flit[695]
  PIN rx_flit[696]
    DIRECTION OUTPUT ;
    USE SIGNAL ;
    SHAPE ABUTMENT ;
    PORT
      LAYER M5 ;
      RECT 422.328 777.408 422.352 777.600 ;
    END
  END rx_flit[696]
  PIN rx_flit[697]
    DIRECTION OUTPUT ;
    USE SIGNAL ;
    SHAPE ABUTMENT ;
    PORT
      LAYER M5 ;
      RECT 422.376 777.408 422.400 777.600 ;
    END
  END rx_flit[697]
  PIN rx_flit[698]
    DIRECTION OUTPUT ;
    USE SIGNAL ;
    SHAPE ABUTMENT ;
    PORT
      LAYER M5 ;
      RECT 422.424 777.408 422.448 777.600 ;
    END
  END rx_flit[698]
  PIN rx_flit[699]
    DIRECTION OUTPUT ;
    USE SIGNAL ;
    SHAPE ABUTMENT ;
    PORT
      LAYER M5 ;
      RECT 422.472 777.408 422.496 777.600 ;
    END
  END rx_flit[699]
  PIN rx_flit[700]
    DIRECTION OUTPUT ;
    USE SIGNAL ;
    SHAPE ABUTMENT ;
    PORT
      LAYER M5 ;
      RECT 422.520 777.408 422.544 777.600 ;
    END
  END rx_flit[700]
  PIN rx_flit[701]
    DIRECTION OUTPUT ;
    USE SIGNAL ;
    SHAPE ABUTMENT ;
    PORT
      LAYER M5 ;
      RECT 422.568 777.408 422.592 777.600 ;
    END
  END rx_flit[701]
  PIN rx_flit[702]
    DIRECTION OUTPUT ;
    USE SIGNAL ;
    SHAPE ABUTMENT ;
    PORT
      LAYER M5 ;
      RECT 422.616 777.408 422.640 777.600 ;
    END
  END rx_flit[702]
  PIN rx_flit[703]
    DIRECTION OUTPUT ;
    USE SIGNAL ;
    SHAPE ABUTMENT ;
    PORT
      LAYER M5 ;
      RECT 422.664 777.408 422.688 777.600 ;
    END
  END rx_flit[703]
  PIN rx_flit[704]
    DIRECTION OUTPUT ;
    USE SIGNAL ;
    SHAPE ABUTMENT ;
    PORT
      LAYER M5 ;
      RECT 422.712 777.408 422.736 777.600 ;
    END
  END rx_flit[704]
  PIN rx_flit[705]
    DIRECTION OUTPUT ;
    USE SIGNAL ;
    SHAPE ABUTMENT ;
    PORT
      LAYER M5 ;
      RECT 422.760 777.408 422.784 777.600 ;
    END
  END rx_flit[705]
  PIN rx_flit[706]
    DIRECTION OUTPUT ;
    USE SIGNAL ;
    SHAPE ABUTMENT ;
    PORT
      LAYER M5 ;
      RECT 422.808 777.408 422.832 777.600 ;
    END
  END rx_flit[706]
  PIN rx_flit[707]
    DIRECTION OUTPUT ;
    USE SIGNAL ;
    SHAPE ABUTMENT ;
    PORT
      LAYER M5 ;
      RECT 422.856 777.408 422.880 777.600 ;
    END
  END rx_flit[707]
  PIN rx_flit[708]
    DIRECTION OUTPUT ;
    USE SIGNAL ;
    SHAPE ABUTMENT ;
    PORT
      LAYER M5 ;
      RECT 422.904 777.408 422.928 777.600 ;
    END
  END rx_flit[708]
  PIN rx_flit[709]
    DIRECTION OUTPUT ;
    USE SIGNAL ;
    SHAPE ABUTMENT ;
    PORT
      LAYER M5 ;
      RECT 422.952 777.408 422.976 777.600 ;
    END
  END rx_flit[709]
  PIN rx_flit[710]
    DIRECTION OUTPUT ;
    USE SIGNAL ;
    SHAPE ABUTMENT ;
    PORT
      LAYER M5 ;
      RECT 423.000 777.408 423.024 777.600 ;
    END
  END rx_flit[710]
  PIN rx_flit[711]
    DIRECTION OUTPUT ;
    USE SIGNAL ;
    SHAPE ABUTMENT ;
    PORT
      LAYER M5 ;
      RECT 423.048 777.408 423.072 777.600 ;
    END
  END rx_flit[711]
  PIN rx_flit[712]
    DIRECTION OUTPUT ;
    USE SIGNAL ;
    SHAPE ABUTMENT ;
    PORT
      LAYER M5 ;
      RECT 423.096 777.408 423.120 777.600 ;
    END
  END rx_flit[712]
  PIN rx_flit[713]
    DIRECTION OUTPUT ;
    USE SIGNAL ;
    SHAPE ABUTMENT ;
    PORT
      LAYER M5 ;
      RECT 423.144 777.408 423.168 777.600 ;
    END
  END rx_flit[713]
  PIN rx_flit[714]
    DIRECTION OUTPUT ;
    USE SIGNAL ;
    SHAPE ABUTMENT ;
    PORT
      LAYER M5 ;
      RECT 423.192 777.408 423.216 777.600 ;
    END
  END rx_flit[714]
  PIN rx_flit[715]
    DIRECTION OUTPUT ;
    USE SIGNAL ;
    SHAPE ABUTMENT ;
    PORT
      LAYER M5 ;
      RECT 423.240 777.408 423.264 777.600 ;
    END
  END rx_flit[715]
  PIN rx_flit[716]
    DIRECTION OUTPUT ;
    USE SIGNAL ;
    SHAPE ABUTMENT ;
    PORT
      LAYER M5 ;
      RECT 423.288 777.408 423.312 777.600 ;
    END
  END rx_flit[716]
  PIN rx_flit[717]
    DIRECTION OUTPUT ;
    USE SIGNAL ;
    SHAPE ABUTMENT ;
    PORT
      LAYER M5 ;
      RECT 423.336 777.408 423.360 777.600 ;
    END
  END rx_flit[717]
  PIN rx_flit[718]
    DIRECTION OUTPUT ;
    USE SIGNAL ;
    SHAPE ABUTMENT ;
    PORT
      LAYER M5 ;
      RECT 423.384 777.408 423.408 777.600 ;
    END
  END rx_flit[718]
  PIN rx_flit[719]
    DIRECTION OUTPUT ;
    USE SIGNAL ;
    SHAPE ABUTMENT ;
    PORT
      LAYER M5 ;
      RECT 423.432 777.408 423.456 777.600 ;
    END
  END rx_flit[719]
  PIN rx_flit[720]
    DIRECTION OUTPUT ;
    USE SIGNAL ;
    SHAPE ABUTMENT ;
    PORT
      LAYER M5 ;
      RECT 423.480 777.408 423.504 777.600 ;
    END
  END rx_flit[720]
  PIN rx_flit[721]
    DIRECTION OUTPUT ;
    USE SIGNAL ;
    SHAPE ABUTMENT ;
    PORT
      LAYER M5 ;
      RECT 423.528 777.408 423.552 777.600 ;
    END
  END rx_flit[721]
  PIN rx_flit[722]
    DIRECTION OUTPUT ;
    USE SIGNAL ;
    SHAPE ABUTMENT ;
    PORT
      LAYER M5 ;
      RECT 423.576 777.408 423.600 777.600 ;
    END
  END rx_flit[722]
  PIN rx_flit[723]
    DIRECTION OUTPUT ;
    USE SIGNAL ;
    SHAPE ABUTMENT ;
    PORT
      LAYER M5 ;
      RECT 423.624 777.408 423.648 777.600 ;
    END
  END rx_flit[723]
  PIN rx_flit[724]
    DIRECTION OUTPUT ;
    USE SIGNAL ;
    SHAPE ABUTMENT ;
    PORT
      LAYER M5 ;
      RECT 423.672 777.408 423.696 777.600 ;
    END
  END rx_flit[724]
  PIN rx_flit[725]
    DIRECTION OUTPUT ;
    USE SIGNAL ;
    SHAPE ABUTMENT ;
    PORT
      LAYER M5 ;
      RECT 423.720 777.408 423.744 777.600 ;
    END
  END rx_flit[725]
  PIN rx_flit[726]
    DIRECTION OUTPUT ;
    USE SIGNAL ;
    SHAPE ABUTMENT ;
    PORT
      LAYER M5 ;
      RECT 423.768 777.408 423.792 777.600 ;
    END
  END rx_flit[726]
  PIN rx_flit[727]
    DIRECTION OUTPUT ;
    USE SIGNAL ;
    SHAPE ABUTMENT ;
    PORT
      LAYER M5 ;
      RECT 423.816 777.408 423.840 777.600 ;
    END
  END rx_flit[727]
  PIN rx_flit[728]
    DIRECTION OUTPUT ;
    USE SIGNAL ;
    SHAPE ABUTMENT ;
    PORT
      LAYER M5 ;
      RECT 423.864 777.408 423.888 777.600 ;
    END
  END rx_flit[728]
  PIN rx_flit[729]
    DIRECTION OUTPUT ;
    USE SIGNAL ;
    SHAPE ABUTMENT ;
    PORT
      LAYER M5 ;
      RECT 423.912 777.408 423.936 777.600 ;
    END
  END rx_flit[729]
  PIN rx_flit[730]
    DIRECTION OUTPUT ;
    USE SIGNAL ;
    SHAPE ABUTMENT ;
    PORT
      LAYER M5 ;
      RECT 423.960 777.408 423.984 777.600 ;
    END
  END rx_flit[730]
  PIN rx_flit[731]
    DIRECTION OUTPUT ;
    USE SIGNAL ;
    SHAPE ABUTMENT ;
    PORT
      LAYER M5 ;
      RECT 424.008 777.408 424.032 777.600 ;
    END
  END rx_flit[731]
  PIN rx_flit[732]
    DIRECTION OUTPUT ;
    USE SIGNAL ;
    SHAPE ABUTMENT ;
    PORT
      LAYER M5 ;
      RECT 424.056 777.408 424.080 777.600 ;
    END
  END rx_flit[732]
  PIN rx_flit[733]
    DIRECTION OUTPUT ;
    USE SIGNAL ;
    SHAPE ABUTMENT ;
    PORT
      LAYER M5 ;
      RECT 424.104 777.408 424.128 777.600 ;
    END
  END rx_flit[733]
  PIN rx_flit[734]
    DIRECTION OUTPUT ;
    USE SIGNAL ;
    SHAPE ABUTMENT ;
    PORT
      LAYER M5 ;
      RECT 424.152 777.408 424.176 777.600 ;
    END
  END rx_flit[734]
  PIN rx_flit[735]
    DIRECTION OUTPUT ;
    USE SIGNAL ;
    SHAPE ABUTMENT ;
    PORT
      LAYER M5 ;
      RECT 424.200 777.408 424.224 777.600 ;
    END
  END rx_flit[735]
  PIN rx_flit[736]
    DIRECTION OUTPUT ;
    USE SIGNAL ;
    SHAPE ABUTMENT ;
    PORT
      LAYER M5 ;
      RECT 424.248 777.408 424.272 777.600 ;
    END
  END rx_flit[736]
  PIN rx_flit[737]
    DIRECTION OUTPUT ;
    USE SIGNAL ;
    SHAPE ABUTMENT ;
    PORT
      LAYER M5 ;
      RECT 424.296 777.408 424.320 777.600 ;
    END
  END rx_flit[737]
  PIN rx_flit[738]
    DIRECTION OUTPUT ;
    USE SIGNAL ;
    SHAPE ABUTMENT ;
    PORT
      LAYER M5 ;
      RECT 424.344 777.408 424.368 777.600 ;
    END
  END rx_flit[738]
  PIN rx_flit[739]
    DIRECTION OUTPUT ;
    USE SIGNAL ;
    SHAPE ABUTMENT ;
    PORT
      LAYER M5 ;
      RECT 424.392 777.408 424.416 777.600 ;
    END
  END rx_flit[739]
  PIN rx_flit[740]
    DIRECTION OUTPUT ;
    USE SIGNAL ;
    SHAPE ABUTMENT ;
    PORT
      LAYER M5 ;
      RECT 424.440 777.408 424.464 777.600 ;
    END
  END rx_flit[740]
  PIN rx_flit[741]
    DIRECTION OUTPUT ;
    USE SIGNAL ;
    SHAPE ABUTMENT ;
    PORT
      LAYER M5 ;
      RECT 424.488 777.408 424.512 777.600 ;
    END
  END rx_flit[741]
  PIN rx_flit[742]
    DIRECTION OUTPUT ;
    USE SIGNAL ;
    SHAPE ABUTMENT ;
    PORT
      LAYER M5 ;
      RECT 424.536 777.408 424.560 777.600 ;
    END
  END rx_flit[742]
  PIN rx_flit[743]
    DIRECTION OUTPUT ;
    USE SIGNAL ;
    SHAPE ABUTMENT ;
    PORT
      LAYER M5 ;
      RECT 424.584 777.408 424.608 777.600 ;
    END
  END rx_flit[743]
  PIN rx_flit[744]
    DIRECTION OUTPUT ;
    USE SIGNAL ;
    SHAPE ABUTMENT ;
    PORT
      LAYER M5 ;
      RECT 424.632 777.408 424.656 777.600 ;
    END
  END rx_flit[744]
  PIN rx_flit[745]
    DIRECTION OUTPUT ;
    USE SIGNAL ;
    SHAPE ABUTMENT ;
    PORT
      LAYER M5 ;
      RECT 424.680 777.408 424.704 777.600 ;
    END
  END rx_flit[745]
  PIN rx_flit[746]
    DIRECTION OUTPUT ;
    USE SIGNAL ;
    SHAPE ABUTMENT ;
    PORT
      LAYER M5 ;
      RECT 424.728 777.408 424.752 777.600 ;
    END
  END rx_flit[746]
  PIN rx_flit[747]
    DIRECTION OUTPUT ;
    USE SIGNAL ;
    SHAPE ABUTMENT ;
    PORT
      LAYER M5 ;
      RECT 424.776 777.408 424.800 777.600 ;
    END
  END rx_flit[747]
  PIN rx_flit[748]
    DIRECTION OUTPUT ;
    USE SIGNAL ;
    SHAPE ABUTMENT ;
    PORT
      LAYER M5 ;
      RECT 424.824 777.408 424.848 777.600 ;
    END
  END rx_flit[748]
  PIN rx_flit[749]
    DIRECTION OUTPUT ;
    USE SIGNAL ;
    SHAPE ABUTMENT ;
    PORT
      LAYER M5 ;
      RECT 424.872 777.408 424.896 777.600 ;
    END
  END rx_flit[749]
  PIN rx_flit[750]
    DIRECTION OUTPUT ;
    USE SIGNAL ;
    SHAPE ABUTMENT ;
    PORT
      LAYER M5 ;
      RECT 424.920 777.408 424.944 777.600 ;
    END
  END rx_flit[750]
  PIN rx_flit[751]
    DIRECTION OUTPUT ;
    USE SIGNAL ;
    SHAPE ABUTMENT ;
    PORT
      LAYER M5 ;
      RECT 424.968 777.408 424.992 777.600 ;
    END
  END rx_flit[751]
  PIN rx_flit[752]
    DIRECTION OUTPUT ;
    USE SIGNAL ;
    SHAPE ABUTMENT ;
    PORT
      LAYER M5 ;
      RECT 425.016 777.408 425.040 777.600 ;
    END
  END rx_flit[752]
  PIN rx_flit[753]
    DIRECTION OUTPUT ;
    USE SIGNAL ;
    SHAPE ABUTMENT ;
    PORT
      LAYER M5 ;
      RECT 425.064 777.408 425.088 777.600 ;
    END
  END rx_flit[753]
  PIN rx_flit[754]
    DIRECTION OUTPUT ;
    USE SIGNAL ;
    SHAPE ABUTMENT ;
    PORT
      LAYER M5 ;
      RECT 425.112 777.408 425.136 777.600 ;
    END
  END rx_flit[754]
  PIN rx_flit[755]
    DIRECTION OUTPUT ;
    USE SIGNAL ;
    SHAPE ABUTMENT ;
    PORT
      LAYER M5 ;
      RECT 425.160 777.408 425.184 777.600 ;
    END
  END rx_flit[755]
  PIN rx_flit[756]
    DIRECTION OUTPUT ;
    USE SIGNAL ;
    SHAPE ABUTMENT ;
    PORT
      LAYER M5 ;
      RECT 425.208 777.408 425.232 777.600 ;
    END
  END rx_flit[756]
  PIN rx_flit[757]
    DIRECTION OUTPUT ;
    USE SIGNAL ;
    SHAPE ABUTMENT ;
    PORT
      LAYER M5 ;
      RECT 425.256 777.408 425.280 777.600 ;
    END
  END rx_flit[757]
  PIN rx_flit[758]
    DIRECTION OUTPUT ;
    USE SIGNAL ;
    SHAPE ABUTMENT ;
    PORT
      LAYER M5 ;
      RECT 425.304 777.408 425.328 777.600 ;
    END
  END rx_flit[758]
  PIN rx_flit[759]
    DIRECTION OUTPUT ;
    USE SIGNAL ;
    SHAPE ABUTMENT ;
    PORT
      LAYER M5 ;
      RECT 425.352 777.408 425.376 777.600 ;
    END
  END rx_flit[759]
  PIN rx_flit[760]
    DIRECTION OUTPUT ;
    USE SIGNAL ;
    SHAPE ABUTMENT ;
    PORT
      LAYER M5 ;
      RECT 425.400 777.408 425.424 777.600 ;
    END
  END rx_flit[760]
  PIN rx_flit[761]
    DIRECTION OUTPUT ;
    USE SIGNAL ;
    SHAPE ABUTMENT ;
    PORT
      LAYER M5 ;
      RECT 425.448 777.408 425.472 777.600 ;
    END
  END rx_flit[761]
  PIN rx_flit[762]
    DIRECTION OUTPUT ;
    USE SIGNAL ;
    SHAPE ABUTMENT ;
    PORT
      LAYER M5 ;
      RECT 425.496 777.408 425.520 777.600 ;
    END
  END rx_flit[762]
  PIN rx_flit[763]
    DIRECTION OUTPUT ;
    USE SIGNAL ;
    SHAPE ABUTMENT ;
    PORT
      LAYER M5 ;
      RECT 425.544 777.408 425.568 777.600 ;
    END
  END rx_flit[763]
  PIN rx_flit[764]
    DIRECTION OUTPUT ;
    USE SIGNAL ;
    SHAPE ABUTMENT ;
    PORT
      LAYER M5 ;
      RECT 425.592 777.408 425.616 777.600 ;
    END
  END rx_flit[764]
  PIN rx_flit[765]
    DIRECTION OUTPUT ;
    USE SIGNAL ;
    SHAPE ABUTMENT ;
    PORT
      LAYER M5 ;
      RECT 425.640 777.408 425.664 777.600 ;
    END
  END rx_flit[765]
  PIN rx_flit[766]
    DIRECTION OUTPUT ;
    USE SIGNAL ;
    SHAPE ABUTMENT ;
    PORT
      LAYER M5 ;
      RECT 425.688 777.408 425.712 777.600 ;
    END
  END rx_flit[766]
  PIN rx_flit[767]
    DIRECTION OUTPUT ;
    USE SIGNAL ;
    SHAPE ABUTMENT ;
    PORT
      LAYER M5 ;
      RECT 425.736 777.408 425.760 777.600 ;
    END
  END rx_flit[767]
  PIN rx_flit[768]
    DIRECTION OUTPUT ;
    USE SIGNAL ;
    SHAPE ABUTMENT ;
    PORT
      LAYER M5 ;
      RECT 425.784 777.408 425.808 777.600 ;
    END
  END rx_flit[768]
  PIN rx_flit[769]
    DIRECTION OUTPUT ;
    USE SIGNAL ;
    SHAPE ABUTMENT ;
    PORT
      LAYER M5 ;
      RECT 425.832 777.408 425.856 777.600 ;
    END
  END rx_flit[769]
  PIN rx_flit[770]
    DIRECTION OUTPUT ;
    USE SIGNAL ;
    SHAPE ABUTMENT ;
    PORT
      LAYER M5 ;
      RECT 425.880 777.408 425.904 777.600 ;
    END
  END rx_flit[770]
  PIN rx_flit[771]
    DIRECTION OUTPUT ;
    USE SIGNAL ;
    SHAPE ABUTMENT ;
    PORT
      LAYER M5 ;
      RECT 425.928 777.408 425.952 777.600 ;
    END
  END rx_flit[771]
  PIN rx_flit[772]
    DIRECTION OUTPUT ;
    USE SIGNAL ;
    SHAPE ABUTMENT ;
    PORT
      LAYER M5 ;
      RECT 425.976 777.408 426.000 777.600 ;
    END
  END rx_flit[772]
  PIN rx_flit[773]
    DIRECTION OUTPUT ;
    USE SIGNAL ;
    SHAPE ABUTMENT ;
    PORT
      LAYER M5 ;
      RECT 426.024 777.408 426.048 777.600 ;
    END
  END rx_flit[773]
  PIN rx_flit[774]
    DIRECTION OUTPUT ;
    USE SIGNAL ;
    SHAPE ABUTMENT ;
    PORT
      LAYER M5 ;
      RECT 426.072 777.408 426.096 777.600 ;
    END
  END rx_flit[774]
  PIN rx_flit[775]
    DIRECTION OUTPUT ;
    USE SIGNAL ;
    SHAPE ABUTMENT ;
    PORT
      LAYER M5 ;
      RECT 426.120 777.408 426.144 777.600 ;
    END
  END rx_flit[775]
  PIN rx_flit[776]
    DIRECTION OUTPUT ;
    USE SIGNAL ;
    SHAPE ABUTMENT ;
    PORT
      LAYER M5 ;
      RECT 426.168 777.408 426.192 777.600 ;
    END
  END rx_flit[776]
  PIN rx_flit[777]
    DIRECTION OUTPUT ;
    USE SIGNAL ;
    SHAPE ABUTMENT ;
    PORT
      LAYER M5 ;
      RECT 426.216 777.408 426.240 777.600 ;
    END
  END rx_flit[777]
  PIN rx_flit[778]
    DIRECTION OUTPUT ;
    USE SIGNAL ;
    SHAPE ABUTMENT ;
    PORT
      LAYER M5 ;
      RECT 426.264 777.408 426.288 777.600 ;
    END
  END rx_flit[778]
  PIN rx_flit[779]
    DIRECTION OUTPUT ;
    USE SIGNAL ;
    SHAPE ABUTMENT ;
    PORT
      LAYER M5 ;
      RECT 426.312 777.408 426.336 777.600 ;
    END
  END rx_flit[779]
  PIN rx_flit[780]
    DIRECTION OUTPUT ;
    USE SIGNAL ;
    SHAPE ABUTMENT ;
    PORT
      LAYER M5 ;
      RECT 426.360 777.408 426.384 777.600 ;
    END
  END rx_flit[780]
  PIN rx_flit[781]
    DIRECTION OUTPUT ;
    USE SIGNAL ;
    SHAPE ABUTMENT ;
    PORT
      LAYER M5 ;
      RECT 426.408 777.408 426.432 777.600 ;
    END
  END rx_flit[781]
  PIN rx_flit[782]
    DIRECTION OUTPUT ;
    USE SIGNAL ;
    SHAPE ABUTMENT ;
    PORT
      LAYER M5 ;
      RECT 426.456 777.408 426.480 777.600 ;
    END
  END rx_flit[782]
  PIN rx_flit[783]
    DIRECTION OUTPUT ;
    USE SIGNAL ;
    SHAPE ABUTMENT ;
    PORT
      LAYER M5 ;
      RECT 426.504 777.408 426.528 777.600 ;
    END
  END rx_flit[783]
  PIN rx_flit[784]
    DIRECTION OUTPUT ;
    USE SIGNAL ;
    SHAPE ABUTMENT ;
    PORT
      LAYER M5 ;
      RECT 426.552 777.408 426.576 777.600 ;
    END
  END rx_flit[784]
  PIN rx_flit[785]
    DIRECTION OUTPUT ;
    USE SIGNAL ;
    SHAPE ABUTMENT ;
    PORT
      LAYER M5 ;
      RECT 426.600 777.408 426.624 777.600 ;
    END
  END rx_flit[785]
  PIN rx_flit[786]
    DIRECTION OUTPUT ;
    USE SIGNAL ;
    SHAPE ABUTMENT ;
    PORT
      LAYER M5 ;
      RECT 426.648 777.408 426.672 777.600 ;
    END
  END rx_flit[786]
  PIN rx_flit[787]
    DIRECTION OUTPUT ;
    USE SIGNAL ;
    SHAPE ABUTMENT ;
    PORT
      LAYER M5 ;
      RECT 426.696 777.408 426.720 777.600 ;
    END
  END rx_flit[787]
  PIN rx_flit[788]
    DIRECTION OUTPUT ;
    USE SIGNAL ;
    SHAPE ABUTMENT ;
    PORT
      LAYER M5 ;
      RECT 426.744 777.408 426.768 777.600 ;
    END
  END rx_flit[788]
  PIN rx_flit[789]
    DIRECTION OUTPUT ;
    USE SIGNAL ;
    SHAPE ABUTMENT ;
    PORT
      LAYER M5 ;
      RECT 426.792 777.408 426.816 777.600 ;
    END
  END rx_flit[789]
  PIN rx_flit[790]
    DIRECTION OUTPUT ;
    USE SIGNAL ;
    SHAPE ABUTMENT ;
    PORT
      LAYER M5 ;
      RECT 426.840 777.408 426.864 777.600 ;
    END
  END rx_flit[790]
  PIN rx_flit[791]
    DIRECTION OUTPUT ;
    USE SIGNAL ;
    SHAPE ABUTMENT ;
    PORT
      LAYER M5 ;
      RECT 426.888 777.408 426.912 777.600 ;
    END
  END rx_flit[791]
  PIN rx_flit[792]
    DIRECTION OUTPUT ;
    USE SIGNAL ;
    SHAPE ABUTMENT ;
    PORT
      LAYER M5 ;
      RECT 426.936 777.408 426.960 777.600 ;
    END
  END rx_flit[792]
  PIN rx_flit[793]
    DIRECTION OUTPUT ;
    USE SIGNAL ;
    SHAPE ABUTMENT ;
    PORT
      LAYER M5 ;
      RECT 426.984 777.408 427.008 777.600 ;
    END
  END rx_flit[793]
  PIN rx_flit[794]
    DIRECTION OUTPUT ;
    USE SIGNAL ;
    SHAPE ABUTMENT ;
    PORT
      LAYER M5 ;
      RECT 427.032 777.408 427.056 777.600 ;
    END
  END rx_flit[794]
  PIN rx_flit[795]
    DIRECTION OUTPUT ;
    USE SIGNAL ;
    SHAPE ABUTMENT ;
    PORT
      LAYER M5 ;
      RECT 427.080 777.408 427.104 777.600 ;
    END
  END rx_flit[795]
  PIN rx_flit[796]
    DIRECTION OUTPUT ;
    USE SIGNAL ;
    SHAPE ABUTMENT ;
    PORT
      LAYER M5 ;
      RECT 427.128 777.408 427.152 777.600 ;
    END
  END rx_flit[796]
  PIN rx_flit[797]
    DIRECTION OUTPUT ;
    USE SIGNAL ;
    SHAPE ABUTMENT ;
    PORT
      LAYER M5 ;
      RECT 427.176 777.408 427.200 777.600 ;
    END
  END rx_flit[797]
  PIN rx_flit[798]
    DIRECTION OUTPUT ;
    USE SIGNAL ;
    SHAPE ABUTMENT ;
    PORT
      LAYER M5 ;
      RECT 427.224 777.408 427.248 777.600 ;
    END
  END rx_flit[798]
  PIN rx_flit[799]
    DIRECTION OUTPUT ;
    USE SIGNAL ;
    SHAPE ABUTMENT ;
    PORT
      LAYER M5 ;
      RECT 427.272 777.408 427.296 777.600 ;
    END
  END rx_flit[799]
  PIN rx_flit[800]
    DIRECTION OUTPUT ;
    USE SIGNAL ;
    SHAPE ABUTMENT ;
    PORT
      LAYER M5 ;
      RECT 427.320 777.408 427.344 777.600 ;
    END
  END rx_flit[800]
  PIN rx_flit[801]
    DIRECTION OUTPUT ;
    USE SIGNAL ;
    SHAPE ABUTMENT ;
    PORT
      LAYER M5 ;
      RECT 427.368 777.408 427.392 777.600 ;
    END
  END rx_flit[801]
  PIN rx_flit[802]
    DIRECTION OUTPUT ;
    USE SIGNAL ;
    SHAPE ABUTMENT ;
    PORT
      LAYER M5 ;
      RECT 427.416 777.408 427.440 777.600 ;
    END
  END rx_flit[802]
  PIN rx_flit[803]
    DIRECTION OUTPUT ;
    USE SIGNAL ;
    SHAPE ABUTMENT ;
    PORT
      LAYER M5 ;
      RECT 427.464 777.408 427.488 777.600 ;
    END
  END rx_flit[803]
  PIN rx_flit[804]
    DIRECTION OUTPUT ;
    USE SIGNAL ;
    SHAPE ABUTMENT ;
    PORT
      LAYER M5 ;
      RECT 427.512 777.408 427.536 777.600 ;
    END
  END rx_flit[804]
  PIN rx_flit[805]
    DIRECTION OUTPUT ;
    USE SIGNAL ;
    SHAPE ABUTMENT ;
    PORT
      LAYER M5 ;
      RECT 427.560 777.408 427.584 777.600 ;
    END
  END rx_flit[805]
  PIN rx_flit[806]
    DIRECTION OUTPUT ;
    USE SIGNAL ;
    SHAPE ABUTMENT ;
    PORT
      LAYER M5 ;
      RECT 427.608 777.408 427.632 777.600 ;
    END
  END rx_flit[806]
  PIN rx_flit[807]
    DIRECTION OUTPUT ;
    USE SIGNAL ;
    SHAPE ABUTMENT ;
    PORT
      LAYER M5 ;
      RECT 427.656 777.408 427.680 777.600 ;
    END
  END rx_flit[807]
  PIN rx_flit[808]
    DIRECTION OUTPUT ;
    USE SIGNAL ;
    SHAPE ABUTMENT ;
    PORT
      LAYER M5 ;
      RECT 427.704 777.408 427.728 777.600 ;
    END
  END rx_flit[808]
  PIN rx_flit[809]
    DIRECTION OUTPUT ;
    USE SIGNAL ;
    SHAPE ABUTMENT ;
    PORT
      LAYER M5 ;
      RECT 427.752 777.408 427.776 777.600 ;
    END
  END rx_flit[809]
  PIN rx_flit[810]
    DIRECTION OUTPUT ;
    USE SIGNAL ;
    SHAPE ABUTMENT ;
    PORT
      LAYER M5 ;
      RECT 427.800 777.408 427.824 777.600 ;
    END
  END rx_flit[810]
  PIN rx_flit[811]
    DIRECTION OUTPUT ;
    USE SIGNAL ;
    SHAPE ABUTMENT ;
    PORT
      LAYER M5 ;
      RECT 427.848 777.408 427.872 777.600 ;
    END
  END rx_flit[811]
  PIN rx_flit[812]
    DIRECTION OUTPUT ;
    USE SIGNAL ;
    SHAPE ABUTMENT ;
    PORT
      LAYER M5 ;
      RECT 427.896 777.408 427.920 777.600 ;
    END
  END rx_flit[812]
  PIN rx_flit[813]
    DIRECTION OUTPUT ;
    USE SIGNAL ;
    SHAPE ABUTMENT ;
    PORT
      LAYER M5 ;
      RECT 427.944 777.408 427.968 777.600 ;
    END
  END rx_flit[813]
  PIN rx_flit[814]
    DIRECTION OUTPUT ;
    USE SIGNAL ;
    SHAPE ABUTMENT ;
    PORT
      LAYER M5 ;
      RECT 427.992 777.408 428.016 777.600 ;
    END
  END rx_flit[814]
  PIN rx_flit[815]
    DIRECTION OUTPUT ;
    USE SIGNAL ;
    SHAPE ABUTMENT ;
    PORT
      LAYER M5 ;
      RECT 428.040 777.408 428.064 777.600 ;
    END
  END rx_flit[815]
  PIN rx_flit[816]
    DIRECTION OUTPUT ;
    USE SIGNAL ;
    SHAPE ABUTMENT ;
    PORT
      LAYER M5 ;
      RECT 428.088 777.408 428.112 777.600 ;
    END
  END rx_flit[816]
  PIN rx_flit[817]
    DIRECTION OUTPUT ;
    USE SIGNAL ;
    SHAPE ABUTMENT ;
    PORT
      LAYER M5 ;
      RECT 428.136 777.408 428.160 777.600 ;
    END
  END rx_flit[817]
  PIN rx_flit[818]
    DIRECTION OUTPUT ;
    USE SIGNAL ;
    SHAPE ABUTMENT ;
    PORT
      LAYER M5 ;
      RECT 428.184 777.408 428.208 777.600 ;
    END
  END rx_flit[818]
  PIN rx_flit[819]
    DIRECTION OUTPUT ;
    USE SIGNAL ;
    SHAPE ABUTMENT ;
    PORT
      LAYER M5 ;
      RECT 428.232 777.408 428.256 777.600 ;
    END
  END rx_flit[819]
  PIN rx_flit[820]
    DIRECTION OUTPUT ;
    USE SIGNAL ;
    SHAPE ABUTMENT ;
    PORT
      LAYER M5 ;
      RECT 428.280 777.408 428.304 777.600 ;
    END
  END rx_flit[820]
  PIN rx_flit[821]
    DIRECTION OUTPUT ;
    USE SIGNAL ;
    SHAPE ABUTMENT ;
    PORT
      LAYER M5 ;
      RECT 428.328 777.408 428.352 777.600 ;
    END
  END rx_flit[821]
  PIN rx_flit[822]
    DIRECTION OUTPUT ;
    USE SIGNAL ;
    SHAPE ABUTMENT ;
    PORT
      LAYER M5 ;
      RECT 428.376 777.408 428.400 777.600 ;
    END
  END rx_flit[822]
  PIN rx_flit[823]
    DIRECTION OUTPUT ;
    USE SIGNAL ;
    SHAPE ABUTMENT ;
    PORT
      LAYER M5 ;
      RECT 428.424 777.408 428.448 777.600 ;
    END
  END rx_flit[823]
  PIN rx_flit[824]
    DIRECTION OUTPUT ;
    USE SIGNAL ;
    SHAPE ABUTMENT ;
    PORT
      LAYER M5 ;
      RECT 428.472 777.408 428.496 777.600 ;
    END
  END rx_flit[824]
  PIN rx_flit[825]
    DIRECTION OUTPUT ;
    USE SIGNAL ;
    SHAPE ABUTMENT ;
    PORT
      LAYER M5 ;
      RECT 428.520 777.408 428.544 777.600 ;
    END
  END rx_flit[825]
  PIN rx_flit[826]
    DIRECTION OUTPUT ;
    USE SIGNAL ;
    SHAPE ABUTMENT ;
    PORT
      LAYER M5 ;
      RECT 428.568 777.408 428.592 777.600 ;
    END
  END rx_flit[826]
  PIN rx_flit[827]
    DIRECTION OUTPUT ;
    USE SIGNAL ;
    SHAPE ABUTMENT ;
    PORT
      LAYER M5 ;
      RECT 428.616 777.408 428.640 777.600 ;
    END
  END rx_flit[827]
  PIN rx_flit[828]
    DIRECTION OUTPUT ;
    USE SIGNAL ;
    SHAPE ABUTMENT ;
    PORT
      LAYER M5 ;
      RECT 428.664 777.408 428.688 777.600 ;
    END
  END rx_flit[828]
  PIN rx_flit[829]
    DIRECTION OUTPUT ;
    USE SIGNAL ;
    SHAPE ABUTMENT ;
    PORT
      LAYER M5 ;
      RECT 428.712 777.408 428.736 777.600 ;
    END
  END rx_flit[829]
  PIN rx_flit[830]
    DIRECTION OUTPUT ;
    USE SIGNAL ;
    SHAPE ABUTMENT ;
    PORT
      LAYER M5 ;
      RECT 428.760 777.408 428.784 777.600 ;
    END
  END rx_flit[830]
  PIN rx_flit[831]
    DIRECTION OUTPUT ;
    USE SIGNAL ;
    SHAPE ABUTMENT ;
    PORT
      LAYER M5 ;
      RECT 428.808 777.408 428.832 777.600 ;
    END
  END rx_flit[831]
  PIN rx_flit[832]
    DIRECTION OUTPUT ;
    USE SIGNAL ;
    SHAPE ABUTMENT ;
    PORT
      LAYER M5 ;
      RECT 428.856 777.408 428.880 777.600 ;
    END
  END rx_flit[832]
  PIN rx_flit[833]
    DIRECTION OUTPUT ;
    USE SIGNAL ;
    SHAPE ABUTMENT ;
    PORT
      LAYER M5 ;
      RECT 428.904 777.408 428.928 777.600 ;
    END
  END rx_flit[833]
  PIN rx_flit[834]
    DIRECTION OUTPUT ;
    USE SIGNAL ;
    SHAPE ABUTMENT ;
    PORT
      LAYER M5 ;
      RECT 428.952 777.408 428.976 777.600 ;
    END
  END rx_flit[834]
  PIN rx_flit[835]
    DIRECTION OUTPUT ;
    USE SIGNAL ;
    SHAPE ABUTMENT ;
    PORT
      LAYER M5 ;
      RECT 429.000 777.408 429.024 777.600 ;
    END
  END rx_flit[835]
  PIN rx_flit[836]
    DIRECTION OUTPUT ;
    USE SIGNAL ;
    SHAPE ABUTMENT ;
    PORT
      LAYER M5 ;
      RECT 429.048 777.408 429.072 777.600 ;
    END
  END rx_flit[836]
  PIN rx_flit[837]
    DIRECTION OUTPUT ;
    USE SIGNAL ;
    SHAPE ABUTMENT ;
    PORT
      LAYER M5 ;
      RECT 429.096 777.408 429.120 777.600 ;
    END
  END rx_flit[837]
  PIN rx_flit[838]
    DIRECTION OUTPUT ;
    USE SIGNAL ;
    SHAPE ABUTMENT ;
    PORT
      LAYER M5 ;
      RECT 429.144 777.408 429.168 777.600 ;
    END
  END rx_flit[838]
  PIN rx_flit[839]
    DIRECTION OUTPUT ;
    USE SIGNAL ;
    SHAPE ABUTMENT ;
    PORT
      LAYER M5 ;
      RECT 429.192 777.408 429.216 777.600 ;
    END
  END rx_flit[839]
  PIN rx_flit[840]
    DIRECTION OUTPUT ;
    USE SIGNAL ;
    SHAPE ABUTMENT ;
    PORT
      LAYER M5 ;
      RECT 429.240 777.408 429.264 777.600 ;
    END
  END rx_flit[840]
  PIN rx_flit[841]
    DIRECTION OUTPUT ;
    USE SIGNAL ;
    SHAPE ABUTMENT ;
    PORT
      LAYER M5 ;
      RECT 429.288 777.408 429.312 777.600 ;
    END
  END rx_flit[841]
  PIN rx_flit[842]
    DIRECTION OUTPUT ;
    USE SIGNAL ;
    SHAPE ABUTMENT ;
    PORT
      LAYER M5 ;
      RECT 429.336 777.408 429.360 777.600 ;
    END
  END rx_flit[842]
  PIN rx_flit[843]
    DIRECTION OUTPUT ;
    USE SIGNAL ;
    SHAPE ABUTMENT ;
    PORT
      LAYER M5 ;
      RECT 429.384 777.408 429.408 777.600 ;
    END
  END rx_flit[843]
  PIN rx_flit[844]
    DIRECTION OUTPUT ;
    USE SIGNAL ;
    SHAPE ABUTMENT ;
    PORT
      LAYER M5 ;
      RECT 429.432 777.408 429.456 777.600 ;
    END
  END rx_flit[844]
  PIN rx_flit[845]
    DIRECTION OUTPUT ;
    USE SIGNAL ;
    SHAPE ABUTMENT ;
    PORT
      LAYER M5 ;
      RECT 429.480 777.408 429.504 777.600 ;
    END
  END rx_flit[845]
  PIN rx_flit[846]
    DIRECTION OUTPUT ;
    USE SIGNAL ;
    SHAPE ABUTMENT ;
    PORT
      LAYER M5 ;
      RECT 429.528 777.408 429.552 777.600 ;
    END
  END rx_flit[846]
  PIN rx_flit[847]
    DIRECTION OUTPUT ;
    USE SIGNAL ;
    SHAPE ABUTMENT ;
    PORT
      LAYER M5 ;
      RECT 429.576 777.408 429.600 777.600 ;
    END
  END rx_flit[847]
  PIN rx_flit[848]
    DIRECTION OUTPUT ;
    USE SIGNAL ;
    SHAPE ABUTMENT ;
    PORT
      LAYER M5 ;
      RECT 429.624 777.408 429.648 777.600 ;
    END
  END rx_flit[848]
  PIN rx_flit[849]
    DIRECTION OUTPUT ;
    USE SIGNAL ;
    SHAPE ABUTMENT ;
    PORT
      LAYER M5 ;
      RECT 429.672 777.408 429.696 777.600 ;
    END
  END rx_flit[849]
  PIN rx_flit[850]
    DIRECTION OUTPUT ;
    USE SIGNAL ;
    SHAPE ABUTMENT ;
    PORT
      LAYER M5 ;
      RECT 429.720 777.408 429.744 777.600 ;
    END
  END rx_flit[850]
  PIN rx_flit[851]
    DIRECTION OUTPUT ;
    USE SIGNAL ;
    SHAPE ABUTMENT ;
    PORT
      LAYER M5 ;
      RECT 429.768 777.408 429.792 777.600 ;
    END
  END rx_flit[851]
  PIN rx_flit[852]
    DIRECTION OUTPUT ;
    USE SIGNAL ;
    SHAPE ABUTMENT ;
    PORT
      LAYER M5 ;
      RECT 429.816 777.408 429.840 777.600 ;
    END
  END rx_flit[852]
  PIN rx_flit[853]
    DIRECTION OUTPUT ;
    USE SIGNAL ;
    SHAPE ABUTMENT ;
    PORT
      LAYER M5 ;
      RECT 429.864 777.408 429.888 777.600 ;
    END
  END rx_flit[853]
  PIN rx_flit[854]
    DIRECTION OUTPUT ;
    USE SIGNAL ;
    SHAPE ABUTMENT ;
    PORT
      LAYER M5 ;
      RECT 429.912 777.408 429.936 777.600 ;
    END
  END rx_flit[854]
  PIN rx_flit[855]
    DIRECTION OUTPUT ;
    USE SIGNAL ;
    SHAPE ABUTMENT ;
    PORT
      LAYER M5 ;
      RECT 429.960 777.408 429.984 777.600 ;
    END
  END rx_flit[855]
  PIN rx_flit[856]
    DIRECTION OUTPUT ;
    USE SIGNAL ;
    SHAPE ABUTMENT ;
    PORT
      LAYER M5 ;
      RECT 430.008 777.408 430.032 777.600 ;
    END
  END rx_flit[856]
  PIN rx_flit[857]
    DIRECTION OUTPUT ;
    USE SIGNAL ;
    SHAPE ABUTMENT ;
    PORT
      LAYER M5 ;
      RECT 430.056 777.408 430.080 777.600 ;
    END
  END rx_flit[857]
  PIN rx_flit[858]
    DIRECTION OUTPUT ;
    USE SIGNAL ;
    SHAPE ABUTMENT ;
    PORT
      LAYER M5 ;
      RECT 430.104 777.408 430.128 777.600 ;
    END
  END rx_flit[858]
  PIN rx_flit[859]
    DIRECTION OUTPUT ;
    USE SIGNAL ;
    SHAPE ABUTMENT ;
    PORT
      LAYER M5 ;
      RECT 430.152 777.408 430.176 777.600 ;
    END
  END rx_flit[859]
  PIN rx_flit[860]
    DIRECTION OUTPUT ;
    USE SIGNAL ;
    SHAPE ABUTMENT ;
    PORT
      LAYER M5 ;
      RECT 430.200 777.408 430.224 777.600 ;
    END
  END rx_flit[860]
  PIN rx_flit[861]
    DIRECTION OUTPUT ;
    USE SIGNAL ;
    SHAPE ABUTMENT ;
    PORT
      LAYER M5 ;
      RECT 430.248 777.408 430.272 777.600 ;
    END
  END rx_flit[861]
  PIN rx_flit[862]
    DIRECTION OUTPUT ;
    USE SIGNAL ;
    SHAPE ABUTMENT ;
    PORT
      LAYER M5 ;
      RECT 430.296 777.408 430.320 777.600 ;
    END
  END rx_flit[862]
  PIN rx_flit[863]
    DIRECTION OUTPUT ;
    USE SIGNAL ;
    SHAPE ABUTMENT ;
    PORT
      LAYER M5 ;
      RECT 430.344 777.408 430.368 777.600 ;
    END
  END rx_flit[863]
  PIN rx_flit[864]
    DIRECTION OUTPUT ;
    USE SIGNAL ;
    SHAPE ABUTMENT ;
    PORT
      LAYER M5 ;
      RECT 430.392 777.408 430.416 777.600 ;
    END
  END rx_flit[864]
  PIN rx_flit[865]
    DIRECTION OUTPUT ;
    USE SIGNAL ;
    SHAPE ABUTMENT ;
    PORT
      LAYER M5 ;
      RECT 430.440 777.408 430.464 777.600 ;
    END
  END rx_flit[865]
  PIN rx_flit[866]
    DIRECTION OUTPUT ;
    USE SIGNAL ;
    SHAPE ABUTMENT ;
    PORT
      LAYER M5 ;
      RECT 430.488 777.408 430.512 777.600 ;
    END
  END rx_flit[866]
  PIN rx_flit[867]
    DIRECTION OUTPUT ;
    USE SIGNAL ;
    SHAPE ABUTMENT ;
    PORT
      LAYER M5 ;
      RECT 430.536 777.408 430.560 777.600 ;
    END
  END rx_flit[867]
  PIN rx_flit[868]
    DIRECTION OUTPUT ;
    USE SIGNAL ;
    SHAPE ABUTMENT ;
    PORT
      LAYER M5 ;
      RECT 430.584 777.408 430.608 777.600 ;
    END
  END rx_flit[868]
  PIN rx_flit[869]
    DIRECTION OUTPUT ;
    USE SIGNAL ;
    SHAPE ABUTMENT ;
    PORT
      LAYER M5 ;
      RECT 430.632 777.408 430.656 777.600 ;
    END
  END rx_flit[869]
  PIN rx_flit[870]
    DIRECTION OUTPUT ;
    USE SIGNAL ;
    SHAPE ABUTMENT ;
    PORT
      LAYER M5 ;
      RECT 430.680 777.408 430.704 777.600 ;
    END
  END rx_flit[870]
  PIN rx_flit[871]
    DIRECTION OUTPUT ;
    USE SIGNAL ;
    SHAPE ABUTMENT ;
    PORT
      LAYER M5 ;
      RECT 430.728 777.408 430.752 777.600 ;
    END
  END rx_flit[871]
  PIN rx_flit[872]
    DIRECTION OUTPUT ;
    USE SIGNAL ;
    SHAPE ABUTMENT ;
    PORT
      LAYER M5 ;
      RECT 430.776 777.408 430.800 777.600 ;
    END
  END rx_flit[872]
  PIN rx_flit[873]
    DIRECTION OUTPUT ;
    USE SIGNAL ;
    SHAPE ABUTMENT ;
    PORT
      LAYER M5 ;
      RECT 430.824 777.408 430.848 777.600 ;
    END
  END rx_flit[873]
  PIN rx_flit[874]
    DIRECTION OUTPUT ;
    USE SIGNAL ;
    SHAPE ABUTMENT ;
    PORT
      LAYER M5 ;
      RECT 430.872 777.408 430.896 777.600 ;
    END
  END rx_flit[874]
  PIN rx_flit[875]
    DIRECTION OUTPUT ;
    USE SIGNAL ;
    SHAPE ABUTMENT ;
    PORT
      LAYER M5 ;
      RECT 430.920 777.408 430.944 777.600 ;
    END
  END rx_flit[875]
  PIN rx_flit[876]
    DIRECTION OUTPUT ;
    USE SIGNAL ;
    SHAPE ABUTMENT ;
    PORT
      LAYER M5 ;
      RECT 430.968 777.408 430.992 777.600 ;
    END
  END rx_flit[876]
  PIN rx_flit[877]
    DIRECTION OUTPUT ;
    USE SIGNAL ;
    SHAPE ABUTMENT ;
    PORT
      LAYER M5 ;
      RECT 431.016 777.408 431.040 777.600 ;
    END
  END rx_flit[877]
  PIN rx_flit[878]
    DIRECTION OUTPUT ;
    USE SIGNAL ;
    SHAPE ABUTMENT ;
    PORT
      LAYER M5 ;
      RECT 431.064 777.408 431.088 777.600 ;
    END
  END rx_flit[878]
  PIN rx_flit[879]
    DIRECTION OUTPUT ;
    USE SIGNAL ;
    SHAPE ABUTMENT ;
    PORT
      LAYER M5 ;
      RECT 431.112 777.408 431.136 777.600 ;
    END
  END rx_flit[879]
  PIN rx_flit[880]
    DIRECTION OUTPUT ;
    USE SIGNAL ;
    SHAPE ABUTMENT ;
    PORT
      LAYER M5 ;
      RECT 431.160 777.408 431.184 777.600 ;
    END
  END rx_flit[880]
  PIN rx_flit[881]
    DIRECTION OUTPUT ;
    USE SIGNAL ;
    SHAPE ABUTMENT ;
    PORT
      LAYER M5 ;
      RECT 431.208 777.408 431.232 777.600 ;
    END
  END rx_flit[881]
  PIN rx_flit[882]
    DIRECTION OUTPUT ;
    USE SIGNAL ;
    SHAPE ABUTMENT ;
    PORT
      LAYER M5 ;
      RECT 431.256 777.408 431.280 777.600 ;
    END
  END rx_flit[882]
  PIN rx_flit[883]
    DIRECTION OUTPUT ;
    USE SIGNAL ;
    SHAPE ABUTMENT ;
    PORT
      LAYER M5 ;
      RECT 431.304 777.408 431.328 777.600 ;
    END
  END rx_flit[883]
  PIN rx_flit[884]
    DIRECTION OUTPUT ;
    USE SIGNAL ;
    SHAPE ABUTMENT ;
    PORT
      LAYER M5 ;
      RECT 431.352 777.408 431.376 777.600 ;
    END
  END rx_flit[884]
  PIN rx_flit[885]
    DIRECTION OUTPUT ;
    USE SIGNAL ;
    SHAPE ABUTMENT ;
    PORT
      LAYER M5 ;
      RECT 431.400 777.408 431.424 777.600 ;
    END
  END rx_flit[885]
  PIN rx_flit[886]
    DIRECTION OUTPUT ;
    USE SIGNAL ;
    SHAPE ABUTMENT ;
    PORT
      LAYER M5 ;
      RECT 431.448 777.408 431.472 777.600 ;
    END
  END rx_flit[886]
  PIN rx_flit[887]
    DIRECTION OUTPUT ;
    USE SIGNAL ;
    SHAPE ABUTMENT ;
    PORT
      LAYER M5 ;
      RECT 431.496 777.408 431.520 777.600 ;
    END
  END rx_flit[887]
  PIN rx_flit[888]
    DIRECTION OUTPUT ;
    USE SIGNAL ;
    SHAPE ABUTMENT ;
    PORT
      LAYER M5 ;
      RECT 431.544 777.408 431.568 777.600 ;
    END
  END rx_flit[888]
  PIN rx_flit[889]
    DIRECTION OUTPUT ;
    USE SIGNAL ;
    SHAPE ABUTMENT ;
    PORT
      LAYER M5 ;
      RECT 431.592 777.408 431.616 777.600 ;
    END
  END rx_flit[889]
  PIN rx_flit[890]
    DIRECTION OUTPUT ;
    USE SIGNAL ;
    SHAPE ABUTMENT ;
    PORT
      LAYER M5 ;
      RECT 431.640 777.408 431.664 777.600 ;
    END
  END rx_flit[890]
  PIN rx_flit[891]
    DIRECTION OUTPUT ;
    USE SIGNAL ;
    SHAPE ABUTMENT ;
    PORT
      LAYER M5 ;
      RECT 431.688 777.408 431.712 777.600 ;
    END
  END rx_flit[891]
  PIN rx_flit[892]
    DIRECTION OUTPUT ;
    USE SIGNAL ;
    SHAPE ABUTMENT ;
    PORT
      LAYER M5 ;
      RECT 431.736 777.408 431.760 777.600 ;
    END
  END rx_flit[892]
  PIN rx_flit[893]
    DIRECTION OUTPUT ;
    USE SIGNAL ;
    SHAPE ABUTMENT ;
    PORT
      LAYER M5 ;
      RECT 431.784 777.408 431.808 777.600 ;
    END
  END rx_flit[893]
  PIN rx_flit[894]
    DIRECTION OUTPUT ;
    USE SIGNAL ;
    SHAPE ABUTMENT ;
    PORT
      LAYER M5 ;
      RECT 431.832 777.408 431.856 777.600 ;
    END
  END rx_flit[894]
  PIN rx_flit[895]
    DIRECTION OUTPUT ;
    USE SIGNAL ;
    SHAPE ABUTMENT ;
    PORT
      LAYER M5 ;
      RECT 431.880 777.408 431.904 777.600 ;
    END
  END rx_flit[895]
  PIN rx_flit[896]
    DIRECTION OUTPUT ;
    USE SIGNAL ;
    SHAPE ABUTMENT ;
    PORT
      LAYER M5 ;
      RECT 431.928 777.408 431.952 777.600 ;
    END
  END rx_flit[896]
  PIN rx_flit[897]
    DIRECTION OUTPUT ;
    USE SIGNAL ;
    SHAPE ABUTMENT ;
    PORT
      LAYER M5 ;
      RECT 431.976 777.408 432.000 777.600 ;
    END
  END rx_flit[897]
  PIN rx_flit[898]
    DIRECTION OUTPUT ;
    USE SIGNAL ;
    SHAPE ABUTMENT ;
    PORT
      LAYER M5 ;
      RECT 432.024 777.408 432.048 777.600 ;
    END
  END rx_flit[898]
  PIN rx_flit[899]
    DIRECTION OUTPUT ;
    USE SIGNAL ;
    SHAPE ABUTMENT ;
    PORT
      LAYER M5 ;
      RECT 432.072 777.408 432.096 777.600 ;
    END
  END rx_flit[899]
  PIN rx_flit[900]
    DIRECTION OUTPUT ;
    USE SIGNAL ;
    SHAPE ABUTMENT ;
    PORT
      LAYER M5 ;
      RECT 432.120 777.408 432.144 777.600 ;
    END
  END rx_flit[900]
  PIN rx_flit[901]
    DIRECTION OUTPUT ;
    USE SIGNAL ;
    SHAPE ABUTMENT ;
    PORT
      LAYER M5 ;
      RECT 432.168 777.408 432.192 777.600 ;
    END
  END rx_flit[901]
  PIN rx_flit[902]
    DIRECTION OUTPUT ;
    USE SIGNAL ;
    SHAPE ABUTMENT ;
    PORT
      LAYER M5 ;
      RECT 432.216 777.408 432.240 777.600 ;
    END
  END rx_flit[902]
  PIN rx_flit[903]
    DIRECTION OUTPUT ;
    USE SIGNAL ;
    SHAPE ABUTMENT ;
    PORT
      LAYER M5 ;
      RECT 432.264 777.408 432.288 777.600 ;
    END
  END rx_flit[903]
  PIN rx_flit[904]
    DIRECTION OUTPUT ;
    USE SIGNAL ;
    SHAPE ABUTMENT ;
    PORT
      LAYER M5 ;
      RECT 432.312 777.408 432.336 777.600 ;
    END
  END rx_flit[904]
  PIN rx_flit[905]
    DIRECTION OUTPUT ;
    USE SIGNAL ;
    SHAPE ABUTMENT ;
    PORT
      LAYER M5 ;
      RECT 432.360 777.408 432.384 777.600 ;
    END
  END rx_flit[905]
  PIN rx_flit[906]
    DIRECTION OUTPUT ;
    USE SIGNAL ;
    SHAPE ABUTMENT ;
    PORT
      LAYER M5 ;
      RECT 432.408 777.408 432.432 777.600 ;
    END
  END rx_flit[906]
  PIN rx_flit[907]
    DIRECTION OUTPUT ;
    USE SIGNAL ;
    SHAPE ABUTMENT ;
    PORT
      LAYER M5 ;
      RECT 432.456 777.408 432.480 777.600 ;
    END
  END rx_flit[907]
  PIN rx_flit[908]
    DIRECTION OUTPUT ;
    USE SIGNAL ;
    SHAPE ABUTMENT ;
    PORT
      LAYER M5 ;
      RECT 432.504 777.408 432.528 777.600 ;
    END
  END rx_flit[908]
  PIN rx_flit[909]
    DIRECTION OUTPUT ;
    USE SIGNAL ;
    SHAPE ABUTMENT ;
    PORT
      LAYER M5 ;
      RECT 432.552 777.408 432.576 777.600 ;
    END
  END rx_flit[909]
  PIN rx_flit[910]
    DIRECTION OUTPUT ;
    USE SIGNAL ;
    SHAPE ABUTMENT ;
    PORT
      LAYER M5 ;
      RECT 432.600 777.408 432.624 777.600 ;
    END
  END rx_flit[910]
  PIN rx_flit[911]
    DIRECTION OUTPUT ;
    USE SIGNAL ;
    SHAPE ABUTMENT ;
    PORT
      LAYER M5 ;
      RECT 432.648 777.408 432.672 777.600 ;
    END
  END rx_flit[911]
  PIN rx_flit[912]
    DIRECTION OUTPUT ;
    USE SIGNAL ;
    SHAPE ABUTMENT ;
    PORT
      LAYER M5 ;
      RECT 432.696 777.408 432.720 777.600 ;
    END
  END rx_flit[912]
  PIN rx_flit[913]
    DIRECTION OUTPUT ;
    USE SIGNAL ;
    SHAPE ABUTMENT ;
    PORT
      LAYER M5 ;
      RECT 432.744 777.408 432.768 777.600 ;
    END
  END rx_flit[913]
  PIN rx_flit[914]
    DIRECTION OUTPUT ;
    USE SIGNAL ;
    SHAPE ABUTMENT ;
    PORT
      LAYER M5 ;
      RECT 432.792 777.408 432.816 777.600 ;
    END
  END rx_flit[914]
  PIN rx_flit[915]
    DIRECTION OUTPUT ;
    USE SIGNAL ;
    SHAPE ABUTMENT ;
    PORT
      LAYER M5 ;
      RECT 432.840 777.408 432.864 777.600 ;
    END
  END rx_flit[915]
  PIN rx_flit[916]
    DIRECTION OUTPUT ;
    USE SIGNAL ;
    SHAPE ABUTMENT ;
    PORT
      LAYER M5 ;
      RECT 432.888 777.408 432.912 777.600 ;
    END
  END rx_flit[916]
  PIN rx_flit[917]
    DIRECTION OUTPUT ;
    USE SIGNAL ;
    SHAPE ABUTMENT ;
    PORT
      LAYER M5 ;
      RECT 432.936 777.408 432.960 777.600 ;
    END
  END rx_flit[917]
  PIN rx_flit[918]
    DIRECTION OUTPUT ;
    USE SIGNAL ;
    SHAPE ABUTMENT ;
    PORT
      LAYER M5 ;
      RECT 432.984 777.408 433.008 777.600 ;
    END
  END rx_flit[918]
  PIN rx_flit[919]
    DIRECTION OUTPUT ;
    USE SIGNAL ;
    SHAPE ABUTMENT ;
    PORT
      LAYER M5 ;
      RECT 433.032 777.408 433.056 777.600 ;
    END
  END rx_flit[919]
  PIN rx_flit[920]
    DIRECTION OUTPUT ;
    USE SIGNAL ;
    SHAPE ABUTMENT ;
    PORT
      LAYER M5 ;
      RECT 433.080 777.408 433.104 777.600 ;
    END
  END rx_flit[920]
  PIN rx_flit[921]
    DIRECTION OUTPUT ;
    USE SIGNAL ;
    SHAPE ABUTMENT ;
    PORT
      LAYER M5 ;
      RECT 433.128 777.408 433.152 777.600 ;
    END
  END rx_flit[921]
  PIN rx_flit[922]
    DIRECTION OUTPUT ;
    USE SIGNAL ;
    SHAPE ABUTMENT ;
    PORT
      LAYER M5 ;
      RECT 433.176 777.408 433.200 777.600 ;
    END
  END rx_flit[922]
  PIN rx_flit[923]
    DIRECTION OUTPUT ;
    USE SIGNAL ;
    SHAPE ABUTMENT ;
    PORT
      LAYER M5 ;
      RECT 433.224 777.408 433.248 777.600 ;
    END
  END rx_flit[923]
  PIN rx_flit[924]
    DIRECTION OUTPUT ;
    USE SIGNAL ;
    SHAPE ABUTMENT ;
    PORT
      LAYER M5 ;
      RECT 433.272 777.408 433.296 777.600 ;
    END
  END rx_flit[924]
  PIN rx_flit[925]
    DIRECTION OUTPUT ;
    USE SIGNAL ;
    SHAPE ABUTMENT ;
    PORT
      LAYER M5 ;
      RECT 433.320 777.408 433.344 777.600 ;
    END
  END rx_flit[925]
  PIN rx_flit[926]
    DIRECTION OUTPUT ;
    USE SIGNAL ;
    SHAPE ABUTMENT ;
    PORT
      LAYER M5 ;
      RECT 433.368 777.408 433.392 777.600 ;
    END
  END rx_flit[926]
  PIN rx_flit[927]
    DIRECTION OUTPUT ;
    USE SIGNAL ;
    SHAPE ABUTMENT ;
    PORT
      LAYER M5 ;
      RECT 433.416 777.408 433.440 777.600 ;
    END
  END rx_flit[927]
  PIN rx_flit[928]
    DIRECTION OUTPUT ;
    USE SIGNAL ;
    SHAPE ABUTMENT ;
    PORT
      LAYER M5 ;
      RECT 433.464 777.408 433.488 777.600 ;
    END
  END rx_flit[928]
  PIN rx_flit[929]
    DIRECTION OUTPUT ;
    USE SIGNAL ;
    SHAPE ABUTMENT ;
    PORT
      LAYER M5 ;
      RECT 433.512 777.408 433.536 777.600 ;
    END
  END rx_flit[929]
  PIN rx_flit[930]
    DIRECTION OUTPUT ;
    USE SIGNAL ;
    SHAPE ABUTMENT ;
    PORT
      LAYER M5 ;
      RECT 433.560 777.408 433.584 777.600 ;
    END
  END rx_flit[930]
  PIN rx_flit[931]
    DIRECTION OUTPUT ;
    USE SIGNAL ;
    SHAPE ABUTMENT ;
    PORT
      LAYER M5 ;
      RECT 433.608 777.408 433.632 777.600 ;
    END
  END rx_flit[931]
  PIN rx_flit[932]
    DIRECTION OUTPUT ;
    USE SIGNAL ;
    SHAPE ABUTMENT ;
    PORT
      LAYER M5 ;
      RECT 433.656 777.408 433.680 777.600 ;
    END
  END rx_flit[932]
  PIN rx_flit[933]
    DIRECTION OUTPUT ;
    USE SIGNAL ;
    SHAPE ABUTMENT ;
    PORT
      LAYER M5 ;
      RECT 433.704 777.408 433.728 777.600 ;
    END
  END rx_flit[933]
  PIN rx_flit[934]
    DIRECTION OUTPUT ;
    USE SIGNAL ;
    SHAPE ABUTMENT ;
    PORT
      LAYER M5 ;
      RECT 433.752 777.408 433.776 777.600 ;
    END
  END rx_flit[934]
  PIN rx_flit[935]
    DIRECTION OUTPUT ;
    USE SIGNAL ;
    SHAPE ABUTMENT ;
    PORT
      LAYER M5 ;
      RECT 433.800 777.408 433.824 777.600 ;
    END
  END rx_flit[935]
  PIN rx_flit[936]
    DIRECTION OUTPUT ;
    USE SIGNAL ;
    SHAPE ABUTMENT ;
    PORT
      LAYER M5 ;
      RECT 433.848 777.408 433.872 777.600 ;
    END
  END rx_flit[936]
  PIN rx_flit[937]
    DIRECTION OUTPUT ;
    USE SIGNAL ;
    SHAPE ABUTMENT ;
    PORT
      LAYER M5 ;
      RECT 433.896 777.408 433.920 777.600 ;
    END
  END rx_flit[937]
  PIN rx_flit[938]
    DIRECTION OUTPUT ;
    USE SIGNAL ;
    SHAPE ABUTMENT ;
    PORT
      LAYER M5 ;
      RECT 433.944 777.408 433.968 777.600 ;
    END
  END rx_flit[938]
  PIN rx_flit[939]
    DIRECTION OUTPUT ;
    USE SIGNAL ;
    SHAPE ABUTMENT ;
    PORT
      LAYER M5 ;
      RECT 433.992 777.408 434.016 777.600 ;
    END
  END rx_flit[939]
  PIN rx_flit[940]
    DIRECTION OUTPUT ;
    USE SIGNAL ;
    SHAPE ABUTMENT ;
    PORT
      LAYER M5 ;
      RECT 434.040 777.408 434.064 777.600 ;
    END
  END rx_flit[940]
  PIN rx_flit[941]
    DIRECTION OUTPUT ;
    USE SIGNAL ;
    SHAPE ABUTMENT ;
    PORT
      LAYER M5 ;
      RECT 434.088 777.408 434.112 777.600 ;
    END
  END rx_flit[941]
  PIN rx_flit[942]
    DIRECTION OUTPUT ;
    USE SIGNAL ;
    SHAPE ABUTMENT ;
    PORT
      LAYER M5 ;
      RECT 434.136 777.408 434.160 777.600 ;
    END
  END rx_flit[942]
  PIN rx_flit[943]
    DIRECTION OUTPUT ;
    USE SIGNAL ;
    SHAPE ABUTMENT ;
    PORT
      LAYER M5 ;
      RECT 434.184 777.408 434.208 777.600 ;
    END
  END rx_flit[943]
  PIN rx_flit[944]
    DIRECTION OUTPUT ;
    USE SIGNAL ;
    SHAPE ABUTMENT ;
    PORT
      LAYER M5 ;
      RECT 434.232 777.408 434.256 777.600 ;
    END
  END rx_flit[944]
  PIN rx_flit[945]
    DIRECTION OUTPUT ;
    USE SIGNAL ;
    SHAPE ABUTMENT ;
    PORT
      LAYER M5 ;
      RECT 434.280 777.408 434.304 777.600 ;
    END
  END rx_flit[945]
  PIN rx_flit[946]
    DIRECTION OUTPUT ;
    USE SIGNAL ;
    SHAPE ABUTMENT ;
    PORT
      LAYER M5 ;
      RECT 434.328 777.408 434.352 777.600 ;
    END
  END rx_flit[946]
  PIN rx_flit[947]
    DIRECTION OUTPUT ;
    USE SIGNAL ;
    SHAPE ABUTMENT ;
    PORT
      LAYER M5 ;
      RECT 434.376 777.408 434.400 777.600 ;
    END
  END rx_flit[947]
  PIN rx_flit[948]
    DIRECTION OUTPUT ;
    USE SIGNAL ;
    SHAPE ABUTMENT ;
    PORT
      LAYER M5 ;
      RECT 434.424 777.408 434.448 777.600 ;
    END
  END rx_flit[948]
  PIN rx_flit[949]
    DIRECTION OUTPUT ;
    USE SIGNAL ;
    SHAPE ABUTMENT ;
    PORT
      LAYER M5 ;
      RECT 434.472 777.408 434.496 777.600 ;
    END
  END rx_flit[949]
  PIN rx_flit[950]
    DIRECTION OUTPUT ;
    USE SIGNAL ;
    SHAPE ABUTMENT ;
    PORT
      LAYER M5 ;
      RECT 434.520 777.408 434.544 777.600 ;
    END
  END rx_flit[950]
  PIN rx_flit[951]
    DIRECTION OUTPUT ;
    USE SIGNAL ;
    SHAPE ABUTMENT ;
    PORT
      LAYER M5 ;
      RECT 434.568 777.408 434.592 777.600 ;
    END
  END rx_flit[951]
  PIN rx_flit[952]
    DIRECTION OUTPUT ;
    USE SIGNAL ;
    SHAPE ABUTMENT ;
    PORT
      LAYER M5 ;
      RECT 434.616 777.408 434.640 777.600 ;
    END
  END rx_flit[952]
  PIN rx_flit[953]
    DIRECTION OUTPUT ;
    USE SIGNAL ;
    SHAPE ABUTMENT ;
    PORT
      LAYER M5 ;
      RECT 434.664 777.408 434.688 777.600 ;
    END
  END rx_flit[953]
  PIN rx_flit[954]
    DIRECTION OUTPUT ;
    USE SIGNAL ;
    SHAPE ABUTMENT ;
    PORT
      LAYER M5 ;
      RECT 434.712 777.408 434.736 777.600 ;
    END
  END rx_flit[954]
  PIN rx_flit[955]
    DIRECTION OUTPUT ;
    USE SIGNAL ;
    SHAPE ABUTMENT ;
    PORT
      LAYER M5 ;
      RECT 434.760 777.408 434.784 777.600 ;
    END
  END rx_flit[955]
  PIN rx_flit[956]
    DIRECTION OUTPUT ;
    USE SIGNAL ;
    SHAPE ABUTMENT ;
    PORT
      LAYER M5 ;
      RECT 434.808 777.408 434.832 777.600 ;
    END
  END rx_flit[956]
  PIN rx_flit[957]
    DIRECTION OUTPUT ;
    USE SIGNAL ;
    SHAPE ABUTMENT ;
    PORT
      LAYER M5 ;
      RECT 434.856 777.408 434.880 777.600 ;
    END
  END rx_flit[957]
  PIN rx_flit[958]
    DIRECTION OUTPUT ;
    USE SIGNAL ;
    SHAPE ABUTMENT ;
    PORT
      LAYER M5 ;
      RECT 434.904 777.408 434.928 777.600 ;
    END
  END rx_flit[958]
  PIN rx_flit[959]
    DIRECTION OUTPUT ;
    USE SIGNAL ;
    SHAPE ABUTMENT ;
    PORT
      LAYER M5 ;
      RECT 434.952 777.408 434.976 777.600 ;
    END
  END rx_flit[959]
  PIN rx_flit[960]
    DIRECTION OUTPUT ;
    USE SIGNAL ;
    SHAPE ABUTMENT ;
    PORT
      LAYER M5 ;
      RECT 435.000 777.408 435.024 777.600 ;
    END
  END rx_flit[960]
  PIN rx_flit[961]
    DIRECTION OUTPUT ;
    USE SIGNAL ;
    SHAPE ABUTMENT ;
    PORT
      LAYER M5 ;
      RECT 435.048 777.408 435.072 777.600 ;
    END
  END rx_flit[961]
  PIN rx_flit[962]
    DIRECTION OUTPUT ;
    USE SIGNAL ;
    SHAPE ABUTMENT ;
    PORT
      LAYER M5 ;
      RECT 435.096 777.408 435.120 777.600 ;
    END
  END rx_flit[962]
  PIN rx_flit[963]
    DIRECTION OUTPUT ;
    USE SIGNAL ;
    SHAPE ABUTMENT ;
    PORT
      LAYER M5 ;
      RECT 435.144 777.408 435.168 777.600 ;
    END
  END rx_flit[963]
  PIN rx_flit[964]
    DIRECTION OUTPUT ;
    USE SIGNAL ;
    SHAPE ABUTMENT ;
    PORT
      LAYER M5 ;
      RECT 435.192 777.408 435.216 777.600 ;
    END
  END rx_flit[964]
  PIN rx_flit[965]
    DIRECTION OUTPUT ;
    USE SIGNAL ;
    SHAPE ABUTMENT ;
    PORT
      LAYER M5 ;
      RECT 435.240 777.408 435.264 777.600 ;
    END
  END rx_flit[965]
  PIN rx_flit[966]
    DIRECTION OUTPUT ;
    USE SIGNAL ;
    SHAPE ABUTMENT ;
    PORT
      LAYER M5 ;
      RECT 435.288 777.408 435.312 777.600 ;
    END
  END rx_flit[966]
  PIN rx_flit[967]
    DIRECTION OUTPUT ;
    USE SIGNAL ;
    SHAPE ABUTMENT ;
    PORT
      LAYER M5 ;
      RECT 435.336 777.408 435.360 777.600 ;
    END
  END rx_flit[967]
  PIN rx_flit[968]
    DIRECTION OUTPUT ;
    USE SIGNAL ;
    SHAPE ABUTMENT ;
    PORT
      LAYER M5 ;
      RECT 435.384 777.408 435.408 777.600 ;
    END
  END rx_flit[968]
  PIN rx_flit[969]
    DIRECTION OUTPUT ;
    USE SIGNAL ;
    SHAPE ABUTMENT ;
    PORT
      LAYER M5 ;
      RECT 435.432 777.408 435.456 777.600 ;
    END
  END rx_flit[969]
  PIN rx_flit[970]
    DIRECTION OUTPUT ;
    USE SIGNAL ;
    SHAPE ABUTMENT ;
    PORT
      LAYER M5 ;
      RECT 435.480 777.408 435.504 777.600 ;
    END
  END rx_flit[970]
  PIN rx_flit[971]
    DIRECTION OUTPUT ;
    USE SIGNAL ;
    SHAPE ABUTMENT ;
    PORT
      LAYER M5 ;
      RECT 435.528 777.408 435.552 777.600 ;
    END
  END rx_flit[971]
  PIN rx_flit[972]
    DIRECTION OUTPUT ;
    USE SIGNAL ;
    SHAPE ABUTMENT ;
    PORT
      LAYER M5 ;
      RECT 435.576 777.408 435.600 777.600 ;
    END
  END rx_flit[972]
  PIN rx_flit[973]
    DIRECTION OUTPUT ;
    USE SIGNAL ;
    SHAPE ABUTMENT ;
    PORT
      LAYER M5 ;
      RECT 435.624 777.408 435.648 777.600 ;
    END
  END rx_flit[973]
  PIN rx_flit[974]
    DIRECTION OUTPUT ;
    USE SIGNAL ;
    SHAPE ABUTMENT ;
    PORT
      LAYER M5 ;
      RECT 435.672 777.408 435.696 777.600 ;
    END
  END rx_flit[974]
  PIN rx_flit[975]
    DIRECTION OUTPUT ;
    USE SIGNAL ;
    SHAPE ABUTMENT ;
    PORT
      LAYER M5 ;
      RECT 435.720 777.408 435.744 777.600 ;
    END
  END rx_flit[975]
  PIN rx_flit[976]
    DIRECTION OUTPUT ;
    USE SIGNAL ;
    SHAPE ABUTMENT ;
    PORT
      LAYER M5 ;
      RECT 435.768 777.408 435.792 777.600 ;
    END
  END rx_flit[976]
  PIN rx_flit[977]
    DIRECTION OUTPUT ;
    USE SIGNAL ;
    SHAPE ABUTMENT ;
    PORT
      LAYER M5 ;
      RECT 435.816 777.408 435.840 777.600 ;
    END
  END rx_flit[977]
  PIN rx_flit[978]
    DIRECTION OUTPUT ;
    USE SIGNAL ;
    SHAPE ABUTMENT ;
    PORT
      LAYER M5 ;
      RECT 435.864 777.408 435.888 777.600 ;
    END
  END rx_flit[978]
  PIN rx_flit[979]
    DIRECTION OUTPUT ;
    USE SIGNAL ;
    SHAPE ABUTMENT ;
    PORT
      LAYER M5 ;
      RECT 435.912 777.408 435.936 777.600 ;
    END
  END rx_flit[979]
  PIN rx_flit[980]
    DIRECTION OUTPUT ;
    USE SIGNAL ;
    SHAPE ABUTMENT ;
    PORT
      LAYER M5 ;
      RECT 435.960 777.408 435.984 777.600 ;
    END
  END rx_flit[980]
  PIN rx_flit[981]
    DIRECTION OUTPUT ;
    USE SIGNAL ;
    SHAPE ABUTMENT ;
    PORT
      LAYER M5 ;
      RECT 436.008 777.408 436.032 777.600 ;
    END
  END rx_flit[981]
  PIN rx_flit[982]
    DIRECTION OUTPUT ;
    USE SIGNAL ;
    SHAPE ABUTMENT ;
    PORT
      LAYER M5 ;
      RECT 436.056 777.408 436.080 777.600 ;
    END
  END rx_flit[982]
  PIN rx_flit[983]
    DIRECTION OUTPUT ;
    USE SIGNAL ;
    SHAPE ABUTMENT ;
    PORT
      LAYER M5 ;
      RECT 436.104 777.408 436.128 777.600 ;
    END
  END rx_flit[983]
  PIN rx_flit[984]
    DIRECTION OUTPUT ;
    USE SIGNAL ;
    SHAPE ABUTMENT ;
    PORT
      LAYER M5 ;
      RECT 436.152 777.408 436.176 777.600 ;
    END
  END rx_flit[984]
  PIN rx_flit[985]
    DIRECTION OUTPUT ;
    USE SIGNAL ;
    SHAPE ABUTMENT ;
    PORT
      LAYER M5 ;
      RECT 436.200 777.408 436.224 777.600 ;
    END
  END rx_flit[985]
  PIN rx_flit[986]
    DIRECTION OUTPUT ;
    USE SIGNAL ;
    SHAPE ABUTMENT ;
    PORT
      LAYER M5 ;
      RECT 436.248 777.408 436.272 777.600 ;
    END
  END rx_flit[986]
  PIN rx_flit[987]
    DIRECTION OUTPUT ;
    USE SIGNAL ;
    SHAPE ABUTMENT ;
    PORT
      LAYER M5 ;
      RECT 436.296 777.408 436.320 777.600 ;
    END
  END rx_flit[987]
  PIN rx_flit[988]
    DIRECTION OUTPUT ;
    USE SIGNAL ;
    SHAPE ABUTMENT ;
    PORT
      LAYER M5 ;
      RECT 436.344 777.408 436.368 777.600 ;
    END
  END rx_flit[988]
  PIN rx_flit[989]
    DIRECTION OUTPUT ;
    USE SIGNAL ;
    SHAPE ABUTMENT ;
    PORT
      LAYER M5 ;
      RECT 436.392 777.408 436.416 777.600 ;
    END
  END rx_flit[989]
  PIN rx_flit[990]
    DIRECTION OUTPUT ;
    USE SIGNAL ;
    SHAPE ABUTMENT ;
    PORT
      LAYER M5 ;
      RECT 436.440 777.408 436.464 777.600 ;
    END
  END rx_flit[990]
  PIN rx_flit[991]
    DIRECTION OUTPUT ;
    USE SIGNAL ;
    SHAPE ABUTMENT ;
    PORT
      LAYER M5 ;
      RECT 436.488 777.408 436.512 777.600 ;
    END
  END rx_flit[991]
  PIN rx_flit[992]
    DIRECTION OUTPUT ;
    USE SIGNAL ;
    SHAPE ABUTMENT ;
    PORT
      LAYER M5 ;
      RECT 436.536 777.408 436.560 777.600 ;
    END
  END rx_flit[992]
  PIN rx_flit[993]
    DIRECTION OUTPUT ;
    USE SIGNAL ;
    SHAPE ABUTMENT ;
    PORT
      LAYER M5 ;
      RECT 436.584 777.408 436.608 777.600 ;
    END
  END rx_flit[993]
  PIN rx_flit[994]
    DIRECTION OUTPUT ;
    USE SIGNAL ;
    SHAPE ABUTMENT ;
    PORT
      LAYER M5 ;
      RECT 436.632 777.408 436.656 777.600 ;
    END
  END rx_flit[994]
  PIN rx_flit[995]
    DIRECTION OUTPUT ;
    USE SIGNAL ;
    SHAPE ABUTMENT ;
    PORT
      LAYER M5 ;
      RECT 436.680 777.408 436.704 777.600 ;
    END
  END rx_flit[995]
  PIN rx_flit[996]
    DIRECTION OUTPUT ;
    USE SIGNAL ;
    SHAPE ABUTMENT ;
    PORT
      LAYER M5 ;
      RECT 436.728 777.408 436.752 777.600 ;
    END
  END rx_flit[996]
  PIN rx_flit[997]
    DIRECTION OUTPUT ;
    USE SIGNAL ;
    SHAPE ABUTMENT ;
    PORT
      LAYER M5 ;
      RECT 436.776 777.408 436.800 777.600 ;
    END
  END rx_flit[997]
  PIN rx_flit[998]
    DIRECTION OUTPUT ;
    USE SIGNAL ;
    SHAPE ABUTMENT ;
    PORT
      LAYER M5 ;
      RECT 436.824 777.408 436.848 777.600 ;
    END
  END rx_flit[998]
  PIN rx_flit[999]
    DIRECTION OUTPUT ;
    USE SIGNAL ;
    SHAPE ABUTMENT ;
    PORT
      LAYER M5 ;
      RECT 436.872 777.408 436.896 777.600 ;
    END
  END rx_flit[999]
  PIN rx_flit[1000]
    DIRECTION OUTPUT ;
    USE SIGNAL ;
    SHAPE ABUTMENT ;
    PORT
      LAYER M5 ;
      RECT 436.920 777.408 436.944 777.600 ;
    END
  END rx_flit[1000]
  PIN rx_flit[1001]
    DIRECTION OUTPUT ;
    USE SIGNAL ;
    SHAPE ABUTMENT ;
    PORT
      LAYER M5 ;
      RECT 436.968 777.408 436.992 777.600 ;
    END
  END rx_flit[1001]
  PIN rx_flit[1002]
    DIRECTION OUTPUT ;
    USE SIGNAL ;
    SHAPE ABUTMENT ;
    PORT
      LAYER M5 ;
      RECT 437.016 777.408 437.040 777.600 ;
    END
  END rx_flit[1002]
  PIN rx_flit[1003]
    DIRECTION OUTPUT ;
    USE SIGNAL ;
    SHAPE ABUTMENT ;
    PORT
      LAYER M5 ;
      RECT 437.064 777.408 437.088 777.600 ;
    END
  END rx_flit[1003]
  PIN rx_flit[1004]
    DIRECTION OUTPUT ;
    USE SIGNAL ;
    SHAPE ABUTMENT ;
    PORT
      LAYER M5 ;
      RECT 437.112 777.408 437.136 777.600 ;
    END
  END rx_flit[1004]
  PIN rx_flit[1005]
    DIRECTION OUTPUT ;
    USE SIGNAL ;
    SHAPE ABUTMENT ;
    PORT
      LAYER M5 ;
      RECT 437.160 777.408 437.184 777.600 ;
    END
  END rx_flit[1005]
  PIN rx_flit[1006]
    DIRECTION OUTPUT ;
    USE SIGNAL ;
    SHAPE ABUTMENT ;
    PORT
      LAYER M5 ;
      RECT 437.208 777.408 437.232 777.600 ;
    END
  END rx_flit[1006]
  PIN rx_flit[1007]
    DIRECTION OUTPUT ;
    USE SIGNAL ;
    SHAPE ABUTMENT ;
    PORT
      LAYER M5 ;
      RECT 437.256 777.408 437.280 777.600 ;
    END
  END rx_flit[1007]
  PIN rx_flit[1008]
    DIRECTION OUTPUT ;
    USE SIGNAL ;
    SHAPE ABUTMENT ;
    PORT
      LAYER M5 ;
      RECT 437.304 777.408 437.328 777.600 ;
    END
  END rx_flit[1008]
  PIN rx_flit[1009]
    DIRECTION OUTPUT ;
    USE SIGNAL ;
    SHAPE ABUTMENT ;
    PORT
      LAYER M5 ;
      RECT 437.352 777.408 437.376 777.600 ;
    END
  END rx_flit[1009]
  PIN rx_flit[1010]
    DIRECTION OUTPUT ;
    USE SIGNAL ;
    SHAPE ABUTMENT ;
    PORT
      LAYER M5 ;
      RECT 437.400 777.408 437.424 777.600 ;
    END
  END rx_flit[1010]
  PIN rx_flit[1011]
    DIRECTION OUTPUT ;
    USE SIGNAL ;
    SHAPE ABUTMENT ;
    PORT
      LAYER M5 ;
      RECT 437.448 777.408 437.472 777.600 ;
    END
  END rx_flit[1011]
  PIN rx_flit[1012]
    DIRECTION OUTPUT ;
    USE SIGNAL ;
    SHAPE ABUTMENT ;
    PORT
      LAYER M5 ;
      RECT 437.496 777.408 437.520 777.600 ;
    END
  END rx_flit[1012]
  PIN rx_flit[1013]
    DIRECTION OUTPUT ;
    USE SIGNAL ;
    SHAPE ABUTMENT ;
    PORT
      LAYER M5 ;
      RECT 437.544 777.408 437.568 777.600 ;
    END
  END rx_flit[1013]
  PIN rx_flit[1014]
    DIRECTION OUTPUT ;
    USE SIGNAL ;
    SHAPE ABUTMENT ;
    PORT
      LAYER M5 ;
      RECT 437.592 777.408 437.616 777.600 ;
    END
  END rx_flit[1014]
  PIN rx_flit[1015]
    DIRECTION OUTPUT ;
    USE SIGNAL ;
    SHAPE ABUTMENT ;
    PORT
      LAYER M5 ;
      RECT 437.640 777.408 437.664 777.600 ;
    END
  END rx_flit[1015]
  PIN rx_flit[1016]
    DIRECTION OUTPUT ;
    USE SIGNAL ;
    SHAPE ABUTMENT ;
    PORT
      LAYER M5 ;
      RECT 437.688 777.408 437.712 777.600 ;
    END
  END rx_flit[1016]
  PIN rx_flit[1017]
    DIRECTION OUTPUT ;
    USE SIGNAL ;
    SHAPE ABUTMENT ;
    PORT
      LAYER M5 ;
      RECT 437.736 777.408 437.760 777.600 ;
    END
  END rx_flit[1017]
  PIN rx_flit[1018]
    DIRECTION OUTPUT ;
    USE SIGNAL ;
    SHAPE ABUTMENT ;
    PORT
      LAYER M5 ;
      RECT 437.784 777.408 437.808 777.600 ;
    END
  END rx_flit[1018]
  PIN rx_flit[1019]
    DIRECTION OUTPUT ;
    USE SIGNAL ;
    SHAPE ABUTMENT ;
    PORT
      LAYER M5 ;
      RECT 437.832 777.408 437.856 777.600 ;
    END
  END rx_flit[1019]
  PIN rx_flit[1020]
    DIRECTION OUTPUT ;
    USE SIGNAL ;
    SHAPE ABUTMENT ;
    PORT
      LAYER M5 ;
      RECT 437.880 777.408 437.904 777.600 ;
    END
  END rx_flit[1020]
  PIN rx_flit[1021]
    DIRECTION OUTPUT ;
    USE SIGNAL ;
    SHAPE ABUTMENT ;
    PORT
      LAYER M5 ;
      RECT 437.928 777.408 437.952 777.600 ;
    END
  END rx_flit[1021]
  PIN rx_flit[1022]
    DIRECTION OUTPUT ;
    USE SIGNAL ;
    SHAPE ABUTMENT ;
    PORT
      LAYER M5 ;
      RECT 437.976 777.408 438.000 777.600 ;
    END
  END rx_flit[1022]
  PIN rx_flit[1023]
    DIRECTION OUTPUT ;
    USE SIGNAL ;
    SHAPE ABUTMENT ;
    PORT
      LAYER M5 ;
      RECT 438.024 777.408 438.048 777.600 ;
    END
  END rx_flit[1023]
  PIN rx_flit[1024]
    DIRECTION OUTPUT ;
    USE SIGNAL ;
    SHAPE ABUTMENT ;
    PORT
      LAYER M5 ;
      RECT 438.072 777.408 438.096 777.600 ;
    END
  END rx_flit[1024]
  PIN rx_flit[1025]
    DIRECTION OUTPUT ;
    USE SIGNAL ;
    SHAPE ABUTMENT ;
    PORT
      LAYER M5 ;
      RECT 438.120 777.408 438.144 777.600 ;
    END
  END rx_flit[1025]
  PIN rx_flit[1026]
    DIRECTION OUTPUT ;
    USE SIGNAL ;
    SHAPE ABUTMENT ;
    PORT
      LAYER M5 ;
      RECT 438.168 777.408 438.192 777.600 ;
    END
  END rx_flit[1026]
  PIN rx_flit[1027]
    DIRECTION OUTPUT ;
    USE SIGNAL ;
    SHAPE ABUTMENT ;
    PORT
      LAYER M5 ;
      RECT 438.216 777.408 438.240 777.600 ;
    END
  END rx_flit[1027]
  PIN rx_flit[1028]
    DIRECTION OUTPUT ;
    USE SIGNAL ;
    SHAPE ABUTMENT ;
    PORT
      LAYER M5 ;
      RECT 438.264 777.408 438.288 777.600 ;
    END
  END rx_flit[1028]
  PIN rx_flit[1029]
    DIRECTION OUTPUT ;
    USE SIGNAL ;
    SHAPE ABUTMENT ;
    PORT
      LAYER M5 ;
      RECT 438.312 777.408 438.336 777.600 ;
    END
  END rx_flit[1029]
  PIN rx_flit[1030]
    DIRECTION OUTPUT ;
    USE SIGNAL ;
    SHAPE ABUTMENT ;
    PORT
      LAYER M5 ;
      RECT 438.360 777.408 438.384 777.600 ;
    END
  END rx_flit[1030]
  PIN rx_flit[1031]
    DIRECTION OUTPUT ;
    USE SIGNAL ;
    SHAPE ABUTMENT ;
    PORT
      LAYER M5 ;
      RECT 438.408 777.408 438.432 777.600 ;
    END
  END rx_flit[1031]
  PIN rx_flit[1032]
    DIRECTION OUTPUT ;
    USE SIGNAL ;
    SHAPE ABUTMENT ;
    PORT
      LAYER M5 ;
      RECT 438.456 777.408 438.480 777.600 ;
    END
  END rx_flit[1032]
  PIN rx_flit[1033]
    DIRECTION OUTPUT ;
    USE SIGNAL ;
    SHAPE ABUTMENT ;
    PORT
      LAYER M5 ;
      RECT 438.504 777.408 438.528 777.600 ;
    END
  END rx_flit[1033]
  PIN rx_flit[1034]
    DIRECTION OUTPUT ;
    USE SIGNAL ;
    SHAPE ABUTMENT ;
    PORT
      LAYER M5 ;
      RECT 438.552 777.408 438.576 777.600 ;
    END
  END rx_flit[1034]
  PIN rx_flit[1035]
    DIRECTION OUTPUT ;
    USE SIGNAL ;
    SHAPE ABUTMENT ;
    PORT
      LAYER M5 ;
      RECT 438.600 777.408 438.624 777.600 ;
    END
  END rx_flit[1035]
  PIN rx_flit[1036]
    DIRECTION OUTPUT ;
    USE SIGNAL ;
    SHAPE ABUTMENT ;
    PORT
      LAYER M5 ;
      RECT 438.648 777.408 438.672 777.600 ;
    END
  END rx_flit[1036]
  PIN rx_flit[1037]
    DIRECTION OUTPUT ;
    USE SIGNAL ;
    SHAPE ABUTMENT ;
    PORT
      LAYER M5 ;
      RECT 438.696 777.408 438.720 777.600 ;
    END
  END rx_flit[1037]
  PIN rx_flit[1038]
    DIRECTION OUTPUT ;
    USE SIGNAL ;
    SHAPE ABUTMENT ;
    PORT
      LAYER M5 ;
      RECT 438.744 777.408 438.768 777.600 ;
    END
  END rx_flit[1038]
  PIN rx_flit[1039]
    DIRECTION OUTPUT ;
    USE SIGNAL ;
    SHAPE ABUTMENT ;
    PORT
      LAYER M5 ;
      RECT 438.792 777.408 438.816 777.600 ;
    END
  END rx_flit[1039]
  PIN rx_flit[1040]
    DIRECTION OUTPUT ;
    USE SIGNAL ;
    SHAPE ABUTMENT ;
    PORT
      LAYER M5 ;
      RECT 438.840 777.408 438.864 777.600 ;
    END
  END rx_flit[1040]
  PIN rx_flit[1041]
    DIRECTION OUTPUT ;
    USE SIGNAL ;
    SHAPE ABUTMENT ;
    PORT
      LAYER M5 ;
      RECT 438.888 777.408 438.912 777.600 ;
    END
  END rx_flit[1041]
  PIN rx_flit[1042]
    DIRECTION OUTPUT ;
    USE SIGNAL ;
    SHAPE ABUTMENT ;
    PORT
      LAYER M5 ;
      RECT 438.936 777.408 438.960 777.600 ;
    END
  END rx_flit[1042]
  PIN VDD
    DIRECTION INOUT ;
    USE POWER ;
    PORT
      LAYER M4 ;
      RECT 0.500 1.000 777.100 1.288 ;
      RECT 0.500 3.400 777.100 3.688 ;
      RECT 0.500 5.800 777.100 6.088 ;
      RECT 0.500 8.200 777.100 8.488 ;
      RECT 0.500 10.600 777.100 10.888 ;
      RECT 0.500 13.000 777.100 13.288 ;
      RECT 0.500 15.400 777.100 15.688 ;
      RECT 0.500 17.800 777.100 18.088 ;
      RECT 0.500 20.200 777.100 20.488 ;
      RECT 0.500 22.600 777.100 22.888 ;
      RECT 0.500 25.000 777.100 25.288 ;
      RECT 0.500 27.400 777.100 27.688 ;
      RECT 0.500 29.800 777.100 30.088 ;
      RECT 0.500 32.200 777.100 32.488 ;
      RECT 0.500 34.600 777.100 34.888 ;
      RECT 0.500 37.000 777.100 37.288 ;
      RECT 0.500 39.400 777.100 39.688 ;
      RECT 0.500 41.800 777.100 42.088 ;
      RECT 0.500 44.200 777.100 44.488 ;
      RECT 0.500 46.600 777.100 46.888 ;
      RECT 0.500 49.000 777.100 49.288 ;
      RECT 0.500 51.400 777.100 51.688 ;
      RECT 0.500 53.800 777.100 54.088 ;
      RECT 0.500 56.200 777.100 56.488 ;
      RECT 0.500 58.600 777.100 58.888 ;
      RECT 0.500 61.000 777.100 61.288 ;
      RECT 0.500 63.400 777.100 63.688 ;
      RECT 0.500 65.800 777.100 66.088 ;
      RECT 0.500 68.200 777.100 68.488 ;
      RECT 0.500 70.600 777.100 70.888 ;
      RECT 0.500 73.000 777.100 73.288 ;
      RECT 0.500 75.400 777.100 75.688 ;
      RECT 0.500 77.800 777.100 78.088 ;
      RECT 0.500 80.200 777.100 80.488 ;
      RECT 0.500 82.600 777.100 82.888 ;
      RECT 0.500 85.000 777.100 85.288 ;
      RECT 0.500 87.400 777.100 87.688 ;
      RECT 0.500 89.800 777.100 90.088 ;
      RECT 0.500 92.200 777.100 92.488 ;
      RECT 0.500 94.600 777.100 94.888 ;
      RECT 0.500 97.000 777.100 97.288 ;
      RECT 0.500 99.400 777.100 99.688 ;
      RECT 0.500 101.800 777.100 102.088 ;
      RECT 0.500 104.200 777.100 104.488 ;
      RECT 0.500 106.600 777.100 106.888 ;
      RECT 0.500 109.000 777.100 109.288 ;
      RECT 0.500 111.400 777.100 111.688 ;
      RECT 0.500 113.800 777.100 114.088 ;
      RECT 0.500 116.200 777.100 116.488 ;
      RECT 0.500 118.600 777.100 118.888 ;
      RECT 0.500 121.000 777.100 121.288 ;
      RECT 0.500 123.400 777.100 123.688 ;
      RECT 0.500 125.800 777.100 126.088 ;
      RECT 0.500 128.200 777.100 128.488 ;
      RECT 0.500 130.600 777.100 130.888 ;
      RECT 0.500 133.000 777.100 133.288 ;
      RECT 0.500 135.400 777.100 135.688 ;
      RECT 0.500 137.800 777.100 138.088 ;
      RECT 0.500 140.200 777.100 140.488 ;
      RECT 0.500 142.600 777.100 142.888 ;
      RECT 0.500 145.000 777.100 145.288 ;
      RECT 0.500 147.400 777.100 147.688 ;
      RECT 0.500 149.800 777.100 150.088 ;
      RECT 0.500 152.200 777.100 152.488 ;
      RECT 0.500 154.600 777.100 154.888 ;
      RECT 0.500 157.000 777.100 157.288 ;
      RECT 0.500 159.400 777.100 159.688 ;
      RECT 0.500 161.800 777.100 162.088 ;
      RECT 0.500 164.200 777.100 164.488 ;
      RECT 0.500 166.600 777.100 166.888 ;
      RECT 0.500 169.000 777.100 169.288 ;
      RECT 0.500 171.400 777.100 171.688 ;
      RECT 0.500 173.800 777.100 174.088 ;
      RECT 0.500 176.200 777.100 176.488 ;
      RECT 0.500 178.600 777.100 178.888 ;
      RECT 0.500 181.000 777.100 181.288 ;
      RECT 0.500 183.400 777.100 183.688 ;
      RECT 0.500 185.800 777.100 186.088 ;
      RECT 0.500 188.200 777.100 188.488 ;
      RECT 0.500 190.600 777.100 190.888 ;
      RECT 0.500 193.000 777.100 193.288 ;
      RECT 0.500 195.400 777.100 195.688 ;
      RECT 0.500 197.800 777.100 198.088 ;
      RECT 0.500 200.200 777.100 200.488 ;
      RECT 0.500 202.600 777.100 202.888 ;
      RECT 0.500 205.000 777.100 205.288 ;
      RECT 0.500 207.400 777.100 207.688 ;
      RECT 0.500 209.800 777.100 210.088 ;
      RECT 0.500 212.200 777.100 212.488 ;
      RECT 0.500 214.600 777.100 214.888 ;
      RECT 0.500 217.000 777.100 217.288 ;
      RECT 0.500 219.400 777.100 219.688 ;
      RECT 0.500 221.800 777.100 222.088 ;
      RECT 0.500 224.200 777.100 224.488 ;
      RECT 0.500 226.600 777.100 226.888 ;
      RECT 0.500 229.000 777.100 229.288 ;
      RECT 0.500 231.400 777.100 231.688 ;
      RECT 0.500 233.800 777.100 234.088 ;
      RECT 0.500 236.200 777.100 236.488 ;
      RECT 0.500 238.600 777.100 238.888 ;
      RECT 0.500 241.000 777.100 241.288 ;
      RECT 0.500 243.400 777.100 243.688 ;
      RECT 0.500 245.800 777.100 246.088 ;
      RECT 0.500 248.200 777.100 248.488 ;
      RECT 0.500 250.600 777.100 250.888 ;
      RECT 0.500 253.000 777.100 253.288 ;
      RECT 0.500 255.400 777.100 255.688 ;
      RECT 0.500 257.800 777.100 258.088 ;
      RECT 0.500 260.200 777.100 260.488 ;
      RECT 0.500 262.600 777.100 262.888 ;
      RECT 0.500 265.000 777.100 265.288 ;
      RECT 0.500 267.400 777.100 267.688 ;
      RECT 0.500 269.800 777.100 270.088 ;
      RECT 0.500 272.200 777.100 272.488 ;
      RECT 0.500 274.600 777.100 274.888 ;
      RECT 0.500 277.000 777.100 277.288 ;
      RECT 0.500 279.400 777.100 279.688 ;
      RECT 0.500 281.800 777.100 282.088 ;
      RECT 0.500 284.200 777.100 284.488 ;
      RECT 0.500 286.600 777.100 286.888 ;
      RECT 0.500 289.000 777.100 289.288 ;
      RECT 0.500 291.400 777.100 291.688 ;
      RECT 0.500 293.800 777.100 294.088 ;
      RECT 0.500 296.200 777.100 296.488 ;
      RECT 0.500 298.600 777.100 298.888 ;
      RECT 0.500 301.000 777.100 301.288 ;
      RECT 0.500 303.400 777.100 303.688 ;
      RECT 0.500 305.800 777.100 306.088 ;
      RECT 0.500 308.200 777.100 308.488 ;
      RECT 0.500 310.600 777.100 310.888 ;
      RECT 0.500 313.000 777.100 313.288 ;
      RECT 0.500 315.400 777.100 315.688 ;
      RECT 0.500 317.800 777.100 318.088 ;
      RECT 0.500 320.200 777.100 320.488 ;
      RECT 0.500 322.600 777.100 322.888 ;
      RECT 0.500 325.000 777.100 325.288 ;
      RECT 0.500 327.400 777.100 327.688 ;
      RECT 0.500 329.800 777.100 330.088 ;
      RECT 0.500 332.200 777.100 332.488 ;
      RECT 0.500 334.600 777.100 334.888 ;
      RECT 0.500 337.000 777.100 337.288 ;
      RECT 0.500 339.400 777.100 339.688 ;
      RECT 0.500 341.800 777.100 342.088 ;
      RECT 0.500 344.200 777.100 344.488 ;
      RECT 0.500 346.600 777.100 346.888 ;
      RECT 0.500 349.000 777.100 349.288 ;
      RECT 0.500 351.400 777.100 351.688 ;
      RECT 0.500 353.800 777.100 354.088 ;
      RECT 0.500 356.200 777.100 356.488 ;
      RECT 0.500 358.600 777.100 358.888 ;
      RECT 0.500 361.000 777.100 361.288 ;
      RECT 0.500 363.400 777.100 363.688 ;
      RECT 0.500 365.800 777.100 366.088 ;
      RECT 0.500 368.200 777.100 368.488 ;
      RECT 0.500 370.600 777.100 370.888 ;
      RECT 0.500 373.000 777.100 373.288 ;
      RECT 0.500 375.400 777.100 375.688 ;
      RECT 0.500 377.800 777.100 378.088 ;
      RECT 0.500 380.200 777.100 380.488 ;
      RECT 0.500 382.600 777.100 382.888 ;
      RECT 0.500 385.000 777.100 385.288 ;
      RECT 0.500 387.400 777.100 387.688 ;
      RECT 0.500 389.800 777.100 390.088 ;
      RECT 0.500 392.200 777.100 392.488 ;
      RECT 0.500 394.600 777.100 394.888 ;
      RECT 0.500 397.000 777.100 397.288 ;
      RECT 0.500 399.400 777.100 399.688 ;
      RECT 0.500 401.800 777.100 402.088 ;
      RECT 0.500 404.200 777.100 404.488 ;
      RECT 0.500 406.600 777.100 406.888 ;
      RECT 0.500 409.000 777.100 409.288 ;
      RECT 0.500 411.400 777.100 411.688 ;
      RECT 0.500 413.800 777.100 414.088 ;
      RECT 0.500 416.200 777.100 416.488 ;
      RECT 0.500 418.600 777.100 418.888 ;
      RECT 0.500 421.000 777.100 421.288 ;
      RECT 0.500 423.400 777.100 423.688 ;
      RECT 0.500 425.800 777.100 426.088 ;
      RECT 0.500 428.200 777.100 428.488 ;
      RECT 0.500 430.600 777.100 430.888 ;
      RECT 0.500 433.000 777.100 433.288 ;
      RECT 0.500 435.400 777.100 435.688 ;
      RECT 0.500 437.800 777.100 438.088 ;
      RECT 0.500 440.200 777.100 440.488 ;
      RECT 0.500 442.600 777.100 442.888 ;
      RECT 0.500 445.000 777.100 445.288 ;
      RECT 0.500 447.400 777.100 447.688 ;
      RECT 0.500 449.800 777.100 450.088 ;
      RECT 0.500 452.200 777.100 452.488 ;
      RECT 0.500 454.600 777.100 454.888 ;
      RECT 0.500 457.000 777.100 457.288 ;
      RECT 0.500 459.400 777.100 459.688 ;
      RECT 0.500 461.800 777.100 462.088 ;
      RECT 0.500 464.200 777.100 464.488 ;
      RECT 0.500 466.600 777.100 466.888 ;
      RECT 0.500 469.000 777.100 469.288 ;
      RECT 0.500 471.400 777.100 471.688 ;
      RECT 0.500 473.800 777.100 474.088 ;
      RECT 0.500 476.200 777.100 476.488 ;
      RECT 0.500 478.600 777.100 478.888 ;
      RECT 0.500 481.000 777.100 481.288 ;
      RECT 0.500 483.400 777.100 483.688 ;
      RECT 0.500 485.800 777.100 486.088 ;
      RECT 0.500 488.200 777.100 488.488 ;
      RECT 0.500 490.600 777.100 490.888 ;
      RECT 0.500 493.000 777.100 493.288 ;
      RECT 0.500 495.400 777.100 495.688 ;
      RECT 0.500 497.800 777.100 498.088 ;
      RECT 0.500 500.200 777.100 500.488 ;
      RECT 0.500 502.600 777.100 502.888 ;
      RECT 0.500 505.000 777.100 505.288 ;
      RECT 0.500 507.400 777.100 507.688 ;
      RECT 0.500 509.800 777.100 510.088 ;
      RECT 0.500 512.200 777.100 512.488 ;
      RECT 0.500 514.600 777.100 514.888 ;
      RECT 0.500 517.000 777.100 517.288 ;
      RECT 0.500 519.400 777.100 519.688 ;
      RECT 0.500 521.800 777.100 522.088 ;
      RECT 0.500 524.200 777.100 524.488 ;
      RECT 0.500 526.600 777.100 526.888 ;
      RECT 0.500 529.000 777.100 529.288 ;
      RECT 0.500 531.400 777.100 531.688 ;
      RECT 0.500 533.800 777.100 534.088 ;
      RECT 0.500 536.200 777.100 536.488 ;
      RECT 0.500 538.600 777.100 538.888 ;
      RECT 0.500 541.000 777.100 541.288 ;
      RECT 0.500 543.400 777.100 543.688 ;
      RECT 0.500 545.800 777.100 546.088 ;
      RECT 0.500 548.200 777.100 548.488 ;
      RECT 0.500 550.600 777.100 550.888 ;
      RECT 0.500 553.000 777.100 553.288 ;
      RECT 0.500 555.400 777.100 555.688 ;
      RECT 0.500 557.800 777.100 558.088 ;
      RECT 0.500 560.200 777.100 560.488 ;
      RECT 0.500 562.600 777.100 562.888 ;
      RECT 0.500 565.000 777.100 565.288 ;
      RECT 0.500 567.400 777.100 567.688 ;
      RECT 0.500 569.800 777.100 570.088 ;
      RECT 0.500 572.200 777.100 572.488 ;
      RECT 0.500 574.600 777.100 574.888 ;
      RECT 0.500 577.000 777.100 577.288 ;
      RECT 0.500 579.400 777.100 579.688 ;
      RECT 0.500 581.800 777.100 582.088 ;
      RECT 0.500 584.200 777.100 584.488 ;
      RECT 0.500 586.600 777.100 586.888 ;
      RECT 0.500 589.000 777.100 589.288 ;
      RECT 0.500 591.400 777.100 591.688 ;
      RECT 0.500 593.800 777.100 594.088 ;
      RECT 0.500 596.200 777.100 596.488 ;
      RECT 0.500 598.600 777.100 598.888 ;
      RECT 0.500 601.000 777.100 601.288 ;
      RECT 0.500 603.400 777.100 603.688 ;
      RECT 0.500 605.800 777.100 606.088 ;
      RECT 0.500 608.200 777.100 608.488 ;
      RECT 0.500 610.600 777.100 610.888 ;
      RECT 0.500 613.000 777.100 613.288 ;
      RECT 0.500 615.400 777.100 615.688 ;
      RECT 0.500 617.800 777.100 618.088 ;
      RECT 0.500 620.200 777.100 620.488 ;
      RECT 0.500 622.600 777.100 622.888 ;
      RECT 0.500 625.000 777.100 625.288 ;
      RECT 0.500 627.400 777.100 627.688 ;
      RECT 0.500 629.800 777.100 630.088 ;
      RECT 0.500 632.200 777.100 632.488 ;
      RECT 0.500 634.600 777.100 634.888 ;
      RECT 0.500 637.000 777.100 637.288 ;
      RECT 0.500 639.400 777.100 639.688 ;
      RECT 0.500 641.800 777.100 642.088 ;
      RECT 0.500 644.200 777.100 644.488 ;
      RECT 0.500 646.600 777.100 646.888 ;
      RECT 0.500 649.000 777.100 649.288 ;
      RECT 0.500 651.400 777.100 651.688 ;
      RECT 0.500 653.800 777.100 654.088 ;
      RECT 0.500 656.200 777.100 656.488 ;
      RECT 0.500 658.600 777.100 658.888 ;
      RECT 0.500 661.000 777.100 661.288 ;
      RECT 0.500 663.400 777.100 663.688 ;
      RECT 0.500 665.800 777.100 666.088 ;
      RECT 0.500 668.200 777.100 668.488 ;
      RECT 0.500 670.600 777.100 670.888 ;
      RECT 0.500 673.000 777.100 673.288 ;
      RECT 0.500 675.400 777.100 675.688 ;
      RECT 0.500 677.800 777.100 678.088 ;
      RECT 0.500 680.200 777.100 680.488 ;
      RECT 0.500 682.600 777.100 682.888 ;
      RECT 0.500 685.000 777.100 685.288 ;
      RECT 0.500 687.400 777.100 687.688 ;
      RECT 0.500 689.800 777.100 690.088 ;
      RECT 0.500 692.200 777.100 692.488 ;
      RECT 0.500 694.600 777.100 694.888 ;
      RECT 0.500 697.000 777.100 697.288 ;
      RECT 0.500 699.400 777.100 699.688 ;
      RECT 0.500 701.800 777.100 702.088 ;
      RECT 0.500 704.200 777.100 704.488 ;
      RECT 0.500 706.600 777.100 706.888 ;
      RECT 0.500 709.000 777.100 709.288 ;
      RECT 0.500 711.400 777.100 711.688 ;
      RECT 0.500 713.800 777.100 714.088 ;
      RECT 0.500 716.200 777.100 716.488 ;
      RECT 0.500 718.600 777.100 718.888 ;
      RECT 0.500 721.000 777.100 721.288 ;
      RECT 0.500 723.400 777.100 723.688 ;
      RECT 0.500 725.800 777.100 726.088 ;
      RECT 0.500 728.200 777.100 728.488 ;
      RECT 0.500 730.600 777.100 730.888 ;
      RECT 0.500 733.000 777.100 733.288 ;
      RECT 0.500 735.400 777.100 735.688 ;
      RECT 0.500 737.800 777.100 738.088 ;
      RECT 0.500 740.200 777.100 740.488 ;
      RECT 0.500 742.600 777.100 742.888 ;
      RECT 0.500 745.000 777.100 745.288 ;
      RECT 0.500 747.400 777.100 747.688 ;
      RECT 0.500 749.800 777.100 750.088 ;
      RECT 0.500 752.200 777.100 752.488 ;
      RECT 0.500 754.600 777.100 754.888 ;
      RECT 0.500 757.000 777.100 757.288 ;
      RECT 0.500 759.400 777.100 759.688 ;
      RECT 0.500 761.800 777.100 762.088 ;
      RECT 0.500 764.200 777.100 764.488 ;
      RECT 0.500 766.600 777.100 766.888 ;
      RECT 0.500 769.000 777.100 769.288 ;
      RECT 0.500 771.400 777.100 771.688 ;
      RECT 0.500 773.800 777.100 774.088 ;
      RECT 0.500 776.200 777.100 776.488 ;
    END
  END VDD
  PIN VSS
    DIRECTION INOUT ;
    USE GROUND ;
    PORT
      LAYER M4 ;
      RECT 0.500 2.200 777.100 2.488 ;
      RECT 0.500 4.600 777.100 4.888 ;
      RECT 0.500 7.000 777.100 7.288 ;
      RECT 0.500 9.400 777.100 9.688 ;
      RECT 0.500 11.800 777.100 12.088 ;
      RECT 0.500 14.200 777.100 14.488 ;
      RECT 0.500 16.600 777.100 16.888 ;
      RECT 0.500 19.000 777.100 19.288 ;
      RECT 0.500 21.400 777.100 21.688 ;
      RECT 0.500 23.800 777.100 24.088 ;
      RECT 0.500 26.200 777.100 26.488 ;
      RECT 0.500 28.600 777.100 28.888 ;
      RECT 0.500 31.000 777.100 31.288 ;
      RECT 0.500 33.400 777.100 33.688 ;
      RECT 0.500 35.800 777.100 36.088 ;
      RECT 0.500 38.200 777.100 38.488 ;
      RECT 0.500 40.600 777.100 40.888 ;
      RECT 0.500 43.000 777.100 43.288 ;
      RECT 0.500 45.400 777.100 45.688 ;
      RECT 0.500 47.800 777.100 48.088 ;
      RECT 0.500 50.200 777.100 50.488 ;
      RECT 0.500 52.600 777.100 52.888 ;
      RECT 0.500 55.000 777.100 55.288 ;
      RECT 0.500 57.400 777.100 57.688 ;
      RECT 0.500 59.800 777.100 60.088 ;
      RECT 0.500 62.200 777.100 62.488 ;
      RECT 0.500 64.600 777.100 64.888 ;
      RECT 0.500 67.000 777.100 67.288 ;
      RECT 0.500 69.400 777.100 69.688 ;
      RECT 0.500 71.800 777.100 72.088 ;
      RECT 0.500 74.200 777.100 74.488 ;
      RECT 0.500 76.600 777.100 76.888 ;
      RECT 0.500 79.000 777.100 79.288 ;
      RECT 0.500 81.400 777.100 81.688 ;
      RECT 0.500 83.800 777.100 84.088 ;
      RECT 0.500 86.200 777.100 86.488 ;
      RECT 0.500 88.600 777.100 88.888 ;
      RECT 0.500 91.000 777.100 91.288 ;
      RECT 0.500 93.400 777.100 93.688 ;
      RECT 0.500 95.800 777.100 96.088 ;
      RECT 0.500 98.200 777.100 98.488 ;
      RECT 0.500 100.600 777.100 100.888 ;
      RECT 0.500 103.000 777.100 103.288 ;
      RECT 0.500 105.400 777.100 105.688 ;
      RECT 0.500 107.800 777.100 108.088 ;
      RECT 0.500 110.200 777.100 110.488 ;
      RECT 0.500 112.600 777.100 112.888 ;
      RECT 0.500 115.000 777.100 115.288 ;
      RECT 0.500 117.400 777.100 117.688 ;
      RECT 0.500 119.800 777.100 120.088 ;
      RECT 0.500 122.200 777.100 122.488 ;
      RECT 0.500 124.600 777.100 124.888 ;
      RECT 0.500 127.000 777.100 127.288 ;
      RECT 0.500 129.400 777.100 129.688 ;
      RECT 0.500 131.800 777.100 132.088 ;
      RECT 0.500 134.200 777.100 134.488 ;
      RECT 0.500 136.600 777.100 136.888 ;
      RECT 0.500 139.000 777.100 139.288 ;
      RECT 0.500 141.400 777.100 141.688 ;
      RECT 0.500 143.800 777.100 144.088 ;
      RECT 0.500 146.200 777.100 146.488 ;
      RECT 0.500 148.600 777.100 148.888 ;
      RECT 0.500 151.000 777.100 151.288 ;
      RECT 0.500 153.400 777.100 153.688 ;
      RECT 0.500 155.800 777.100 156.088 ;
      RECT 0.500 158.200 777.100 158.488 ;
      RECT 0.500 160.600 777.100 160.888 ;
      RECT 0.500 163.000 777.100 163.288 ;
      RECT 0.500 165.400 777.100 165.688 ;
      RECT 0.500 167.800 777.100 168.088 ;
      RECT 0.500 170.200 777.100 170.488 ;
      RECT 0.500 172.600 777.100 172.888 ;
      RECT 0.500 175.000 777.100 175.288 ;
      RECT 0.500 177.400 777.100 177.688 ;
      RECT 0.500 179.800 777.100 180.088 ;
      RECT 0.500 182.200 777.100 182.488 ;
      RECT 0.500 184.600 777.100 184.888 ;
      RECT 0.500 187.000 777.100 187.288 ;
      RECT 0.500 189.400 777.100 189.688 ;
      RECT 0.500 191.800 777.100 192.088 ;
      RECT 0.500 194.200 777.100 194.488 ;
      RECT 0.500 196.600 777.100 196.888 ;
      RECT 0.500 199.000 777.100 199.288 ;
      RECT 0.500 201.400 777.100 201.688 ;
      RECT 0.500 203.800 777.100 204.088 ;
      RECT 0.500 206.200 777.100 206.488 ;
      RECT 0.500 208.600 777.100 208.888 ;
      RECT 0.500 211.000 777.100 211.288 ;
      RECT 0.500 213.400 777.100 213.688 ;
      RECT 0.500 215.800 777.100 216.088 ;
      RECT 0.500 218.200 777.100 218.488 ;
      RECT 0.500 220.600 777.100 220.888 ;
      RECT 0.500 223.000 777.100 223.288 ;
      RECT 0.500 225.400 777.100 225.688 ;
      RECT 0.500 227.800 777.100 228.088 ;
      RECT 0.500 230.200 777.100 230.488 ;
      RECT 0.500 232.600 777.100 232.888 ;
      RECT 0.500 235.000 777.100 235.288 ;
      RECT 0.500 237.400 777.100 237.688 ;
      RECT 0.500 239.800 777.100 240.088 ;
      RECT 0.500 242.200 777.100 242.488 ;
      RECT 0.500 244.600 777.100 244.888 ;
      RECT 0.500 247.000 777.100 247.288 ;
      RECT 0.500 249.400 777.100 249.688 ;
      RECT 0.500 251.800 777.100 252.088 ;
      RECT 0.500 254.200 777.100 254.488 ;
      RECT 0.500 256.600 777.100 256.888 ;
      RECT 0.500 259.000 777.100 259.288 ;
      RECT 0.500 261.400 777.100 261.688 ;
      RECT 0.500 263.800 777.100 264.088 ;
      RECT 0.500 266.200 777.100 266.488 ;
      RECT 0.500 268.600 777.100 268.888 ;
      RECT 0.500 271.000 777.100 271.288 ;
      RECT 0.500 273.400 777.100 273.688 ;
      RECT 0.500 275.800 777.100 276.088 ;
      RECT 0.500 278.200 777.100 278.488 ;
      RECT 0.500 280.600 777.100 280.888 ;
      RECT 0.500 283.000 777.100 283.288 ;
      RECT 0.500 285.400 777.100 285.688 ;
      RECT 0.500 287.800 777.100 288.088 ;
      RECT 0.500 290.200 777.100 290.488 ;
      RECT 0.500 292.600 777.100 292.888 ;
      RECT 0.500 295.000 777.100 295.288 ;
      RECT 0.500 297.400 777.100 297.688 ;
      RECT 0.500 299.800 777.100 300.088 ;
      RECT 0.500 302.200 777.100 302.488 ;
      RECT 0.500 304.600 777.100 304.888 ;
      RECT 0.500 307.000 777.100 307.288 ;
      RECT 0.500 309.400 777.100 309.688 ;
      RECT 0.500 311.800 777.100 312.088 ;
      RECT 0.500 314.200 777.100 314.488 ;
      RECT 0.500 316.600 777.100 316.888 ;
      RECT 0.500 319.000 777.100 319.288 ;
      RECT 0.500 321.400 777.100 321.688 ;
      RECT 0.500 323.800 777.100 324.088 ;
      RECT 0.500 326.200 777.100 326.488 ;
      RECT 0.500 328.600 777.100 328.888 ;
      RECT 0.500 331.000 777.100 331.288 ;
      RECT 0.500 333.400 777.100 333.688 ;
      RECT 0.500 335.800 777.100 336.088 ;
      RECT 0.500 338.200 777.100 338.488 ;
      RECT 0.500 340.600 777.100 340.888 ;
      RECT 0.500 343.000 777.100 343.288 ;
      RECT 0.500 345.400 777.100 345.688 ;
      RECT 0.500 347.800 777.100 348.088 ;
      RECT 0.500 350.200 777.100 350.488 ;
      RECT 0.500 352.600 777.100 352.888 ;
      RECT 0.500 355.000 777.100 355.288 ;
      RECT 0.500 357.400 777.100 357.688 ;
      RECT 0.500 359.800 777.100 360.088 ;
      RECT 0.500 362.200 777.100 362.488 ;
      RECT 0.500 364.600 777.100 364.888 ;
      RECT 0.500 367.000 777.100 367.288 ;
      RECT 0.500 369.400 777.100 369.688 ;
      RECT 0.500 371.800 777.100 372.088 ;
      RECT 0.500 374.200 777.100 374.488 ;
      RECT 0.500 376.600 777.100 376.888 ;
      RECT 0.500 379.000 777.100 379.288 ;
      RECT 0.500 381.400 777.100 381.688 ;
      RECT 0.500 383.800 777.100 384.088 ;
      RECT 0.500 386.200 777.100 386.488 ;
      RECT 0.500 388.600 777.100 388.888 ;
      RECT 0.500 391.000 777.100 391.288 ;
      RECT 0.500 393.400 777.100 393.688 ;
      RECT 0.500 395.800 777.100 396.088 ;
      RECT 0.500 398.200 777.100 398.488 ;
      RECT 0.500 400.600 777.100 400.888 ;
      RECT 0.500 403.000 777.100 403.288 ;
      RECT 0.500 405.400 777.100 405.688 ;
      RECT 0.500 407.800 777.100 408.088 ;
      RECT 0.500 410.200 777.100 410.488 ;
      RECT 0.500 412.600 777.100 412.888 ;
      RECT 0.500 415.000 777.100 415.288 ;
      RECT 0.500 417.400 777.100 417.688 ;
      RECT 0.500 419.800 777.100 420.088 ;
      RECT 0.500 422.200 777.100 422.488 ;
      RECT 0.500 424.600 777.100 424.888 ;
      RECT 0.500 427.000 777.100 427.288 ;
      RECT 0.500 429.400 777.100 429.688 ;
      RECT 0.500 431.800 777.100 432.088 ;
      RECT 0.500 434.200 777.100 434.488 ;
      RECT 0.500 436.600 777.100 436.888 ;
      RECT 0.500 439.000 777.100 439.288 ;
      RECT 0.500 441.400 777.100 441.688 ;
      RECT 0.500 443.800 777.100 444.088 ;
      RECT 0.500 446.200 777.100 446.488 ;
      RECT 0.500 448.600 777.100 448.888 ;
      RECT 0.500 451.000 777.100 451.288 ;
      RECT 0.500 453.400 777.100 453.688 ;
      RECT 0.500 455.800 777.100 456.088 ;
      RECT 0.500 458.200 777.100 458.488 ;
      RECT 0.500 460.600 777.100 460.888 ;
      RECT 0.500 463.000 777.100 463.288 ;
      RECT 0.500 465.400 777.100 465.688 ;
      RECT 0.500 467.800 777.100 468.088 ;
      RECT 0.500 470.200 777.100 470.488 ;
      RECT 0.500 472.600 777.100 472.888 ;
      RECT 0.500 475.000 777.100 475.288 ;
      RECT 0.500 477.400 777.100 477.688 ;
      RECT 0.500 479.800 777.100 480.088 ;
      RECT 0.500 482.200 777.100 482.488 ;
      RECT 0.500 484.600 777.100 484.888 ;
      RECT 0.500 487.000 777.100 487.288 ;
      RECT 0.500 489.400 777.100 489.688 ;
      RECT 0.500 491.800 777.100 492.088 ;
      RECT 0.500 494.200 777.100 494.488 ;
      RECT 0.500 496.600 777.100 496.888 ;
      RECT 0.500 499.000 777.100 499.288 ;
      RECT 0.500 501.400 777.100 501.688 ;
      RECT 0.500 503.800 777.100 504.088 ;
      RECT 0.500 506.200 777.100 506.488 ;
      RECT 0.500 508.600 777.100 508.888 ;
      RECT 0.500 511.000 777.100 511.288 ;
      RECT 0.500 513.400 777.100 513.688 ;
      RECT 0.500 515.800 777.100 516.088 ;
      RECT 0.500 518.200 777.100 518.488 ;
      RECT 0.500 520.600 777.100 520.888 ;
      RECT 0.500 523.000 777.100 523.288 ;
      RECT 0.500 525.400 777.100 525.688 ;
      RECT 0.500 527.800 777.100 528.088 ;
      RECT 0.500 530.200 777.100 530.488 ;
      RECT 0.500 532.600 777.100 532.888 ;
      RECT 0.500 535.000 777.100 535.288 ;
      RECT 0.500 537.400 777.100 537.688 ;
      RECT 0.500 539.800 777.100 540.088 ;
      RECT 0.500 542.200 777.100 542.488 ;
      RECT 0.500 544.600 777.100 544.888 ;
      RECT 0.500 547.000 777.100 547.288 ;
      RECT 0.500 549.400 777.100 549.688 ;
      RECT 0.500 551.800 777.100 552.088 ;
      RECT 0.500 554.200 777.100 554.488 ;
      RECT 0.500 556.600 777.100 556.888 ;
      RECT 0.500 559.000 777.100 559.288 ;
      RECT 0.500 561.400 777.100 561.688 ;
      RECT 0.500 563.800 777.100 564.088 ;
      RECT 0.500 566.200 777.100 566.488 ;
      RECT 0.500 568.600 777.100 568.888 ;
      RECT 0.500 571.000 777.100 571.288 ;
      RECT 0.500 573.400 777.100 573.688 ;
      RECT 0.500 575.800 777.100 576.088 ;
      RECT 0.500 578.200 777.100 578.488 ;
      RECT 0.500 580.600 777.100 580.888 ;
      RECT 0.500 583.000 777.100 583.288 ;
      RECT 0.500 585.400 777.100 585.688 ;
      RECT 0.500 587.800 777.100 588.088 ;
      RECT 0.500 590.200 777.100 590.488 ;
      RECT 0.500 592.600 777.100 592.888 ;
      RECT 0.500 595.000 777.100 595.288 ;
      RECT 0.500 597.400 777.100 597.688 ;
      RECT 0.500 599.800 777.100 600.088 ;
      RECT 0.500 602.200 777.100 602.488 ;
      RECT 0.500 604.600 777.100 604.888 ;
      RECT 0.500 607.000 777.100 607.288 ;
      RECT 0.500 609.400 777.100 609.688 ;
      RECT 0.500 611.800 777.100 612.088 ;
      RECT 0.500 614.200 777.100 614.488 ;
      RECT 0.500 616.600 777.100 616.888 ;
      RECT 0.500 619.000 777.100 619.288 ;
      RECT 0.500 621.400 777.100 621.688 ;
      RECT 0.500 623.800 777.100 624.088 ;
      RECT 0.500 626.200 777.100 626.488 ;
      RECT 0.500 628.600 777.100 628.888 ;
      RECT 0.500 631.000 777.100 631.288 ;
      RECT 0.500 633.400 777.100 633.688 ;
      RECT 0.500 635.800 777.100 636.088 ;
      RECT 0.500 638.200 777.100 638.488 ;
      RECT 0.500 640.600 777.100 640.888 ;
      RECT 0.500 643.000 777.100 643.288 ;
      RECT 0.500 645.400 777.100 645.688 ;
      RECT 0.500 647.800 777.100 648.088 ;
      RECT 0.500 650.200 777.100 650.488 ;
      RECT 0.500 652.600 777.100 652.888 ;
      RECT 0.500 655.000 777.100 655.288 ;
      RECT 0.500 657.400 777.100 657.688 ;
      RECT 0.500 659.800 777.100 660.088 ;
      RECT 0.500 662.200 777.100 662.488 ;
      RECT 0.500 664.600 777.100 664.888 ;
      RECT 0.500 667.000 777.100 667.288 ;
      RECT 0.500 669.400 777.100 669.688 ;
      RECT 0.500 671.800 777.100 672.088 ;
      RECT 0.500 674.200 777.100 674.488 ;
      RECT 0.500 676.600 777.100 676.888 ;
      RECT 0.500 679.000 777.100 679.288 ;
      RECT 0.500 681.400 777.100 681.688 ;
      RECT 0.500 683.800 777.100 684.088 ;
      RECT 0.500 686.200 777.100 686.488 ;
      RECT 0.500 688.600 777.100 688.888 ;
      RECT 0.500 691.000 777.100 691.288 ;
      RECT 0.500 693.400 777.100 693.688 ;
      RECT 0.500 695.800 777.100 696.088 ;
      RECT 0.500 698.200 777.100 698.488 ;
      RECT 0.500 700.600 777.100 700.888 ;
      RECT 0.500 703.000 777.100 703.288 ;
      RECT 0.500 705.400 777.100 705.688 ;
      RECT 0.500 707.800 777.100 708.088 ;
      RECT 0.500 710.200 777.100 710.488 ;
      RECT 0.500 712.600 777.100 712.888 ;
      RECT 0.500 715.000 777.100 715.288 ;
      RECT 0.500 717.400 777.100 717.688 ;
      RECT 0.500 719.800 777.100 720.088 ;
      RECT 0.500 722.200 777.100 722.488 ;
      RECT 0.500 724.600 777.100 724.888 ;
      RECT 0.500 727.000 777.100 727.288 ;
      RECT 0.500 729.400 777.100 729.688 ;
      RECT 0.500 731.800 777.100 732.088 ;
      RECT 0.500 734.200 777.100 734.488 ;
      RECT 0.500 736.600 777.100 736.888 ;
      RECT 0.500 739.000 777.100 739.288 ;
      RECT 0.500 741.400 777.100 741.688 ;
      RECT 0.500 743.800 777.100 744.088 ;
      RECT 0.500 746.200 777.100 746.488 ;
      RECT 0.500 748.600 777.100 748.888 ;
      RECT 0.500 751.000 777.100 751.288 ;
      RECT 0.500 753.400 777.100 753.688 ;
      RECT 0.500 755.800 777.100 756.088 ;
      RECT 0.500 758.200 777.100 758.488 ;
      RECT 0.500 760.600 777.100 760.888 ;
      RECT 0.500 763.000 777.100 763.288 ;
      RECT 0.500 765.400 777.100 765.688 ;
      RECT 0.500 767.800 777.100 768.088 ;
      RECT 0.500 770.200 777.100 770.488 ;
      RECT 0.500 772.600 777.100 772.888 ;
      RECT 0.500 775.000 777.100 775.288 ;
    END
  END VSS
  OBS
    LAYER M1 ;
    RECT 0 0 777.600 777.600 ;
    LAYER M2 ;
    RECT 0 0 777.600 777.600 ;
    LAYER M3 ;
    RECT 0 0 777.600 777.600 ;
    LAYER M4 ;
    RECT 0 0 777.600 777.600 ;
    LAYER M5 ;
    RECT 0 0 777.600 777.200 ;
  END
END ot_qfd_ucie_x64_phy

END LIBRARY
